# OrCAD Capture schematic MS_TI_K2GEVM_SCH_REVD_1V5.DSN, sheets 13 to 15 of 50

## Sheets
13 12. SoC POWER1: size C; title: SOC POWER - CVDD,CVDD1 & PLL
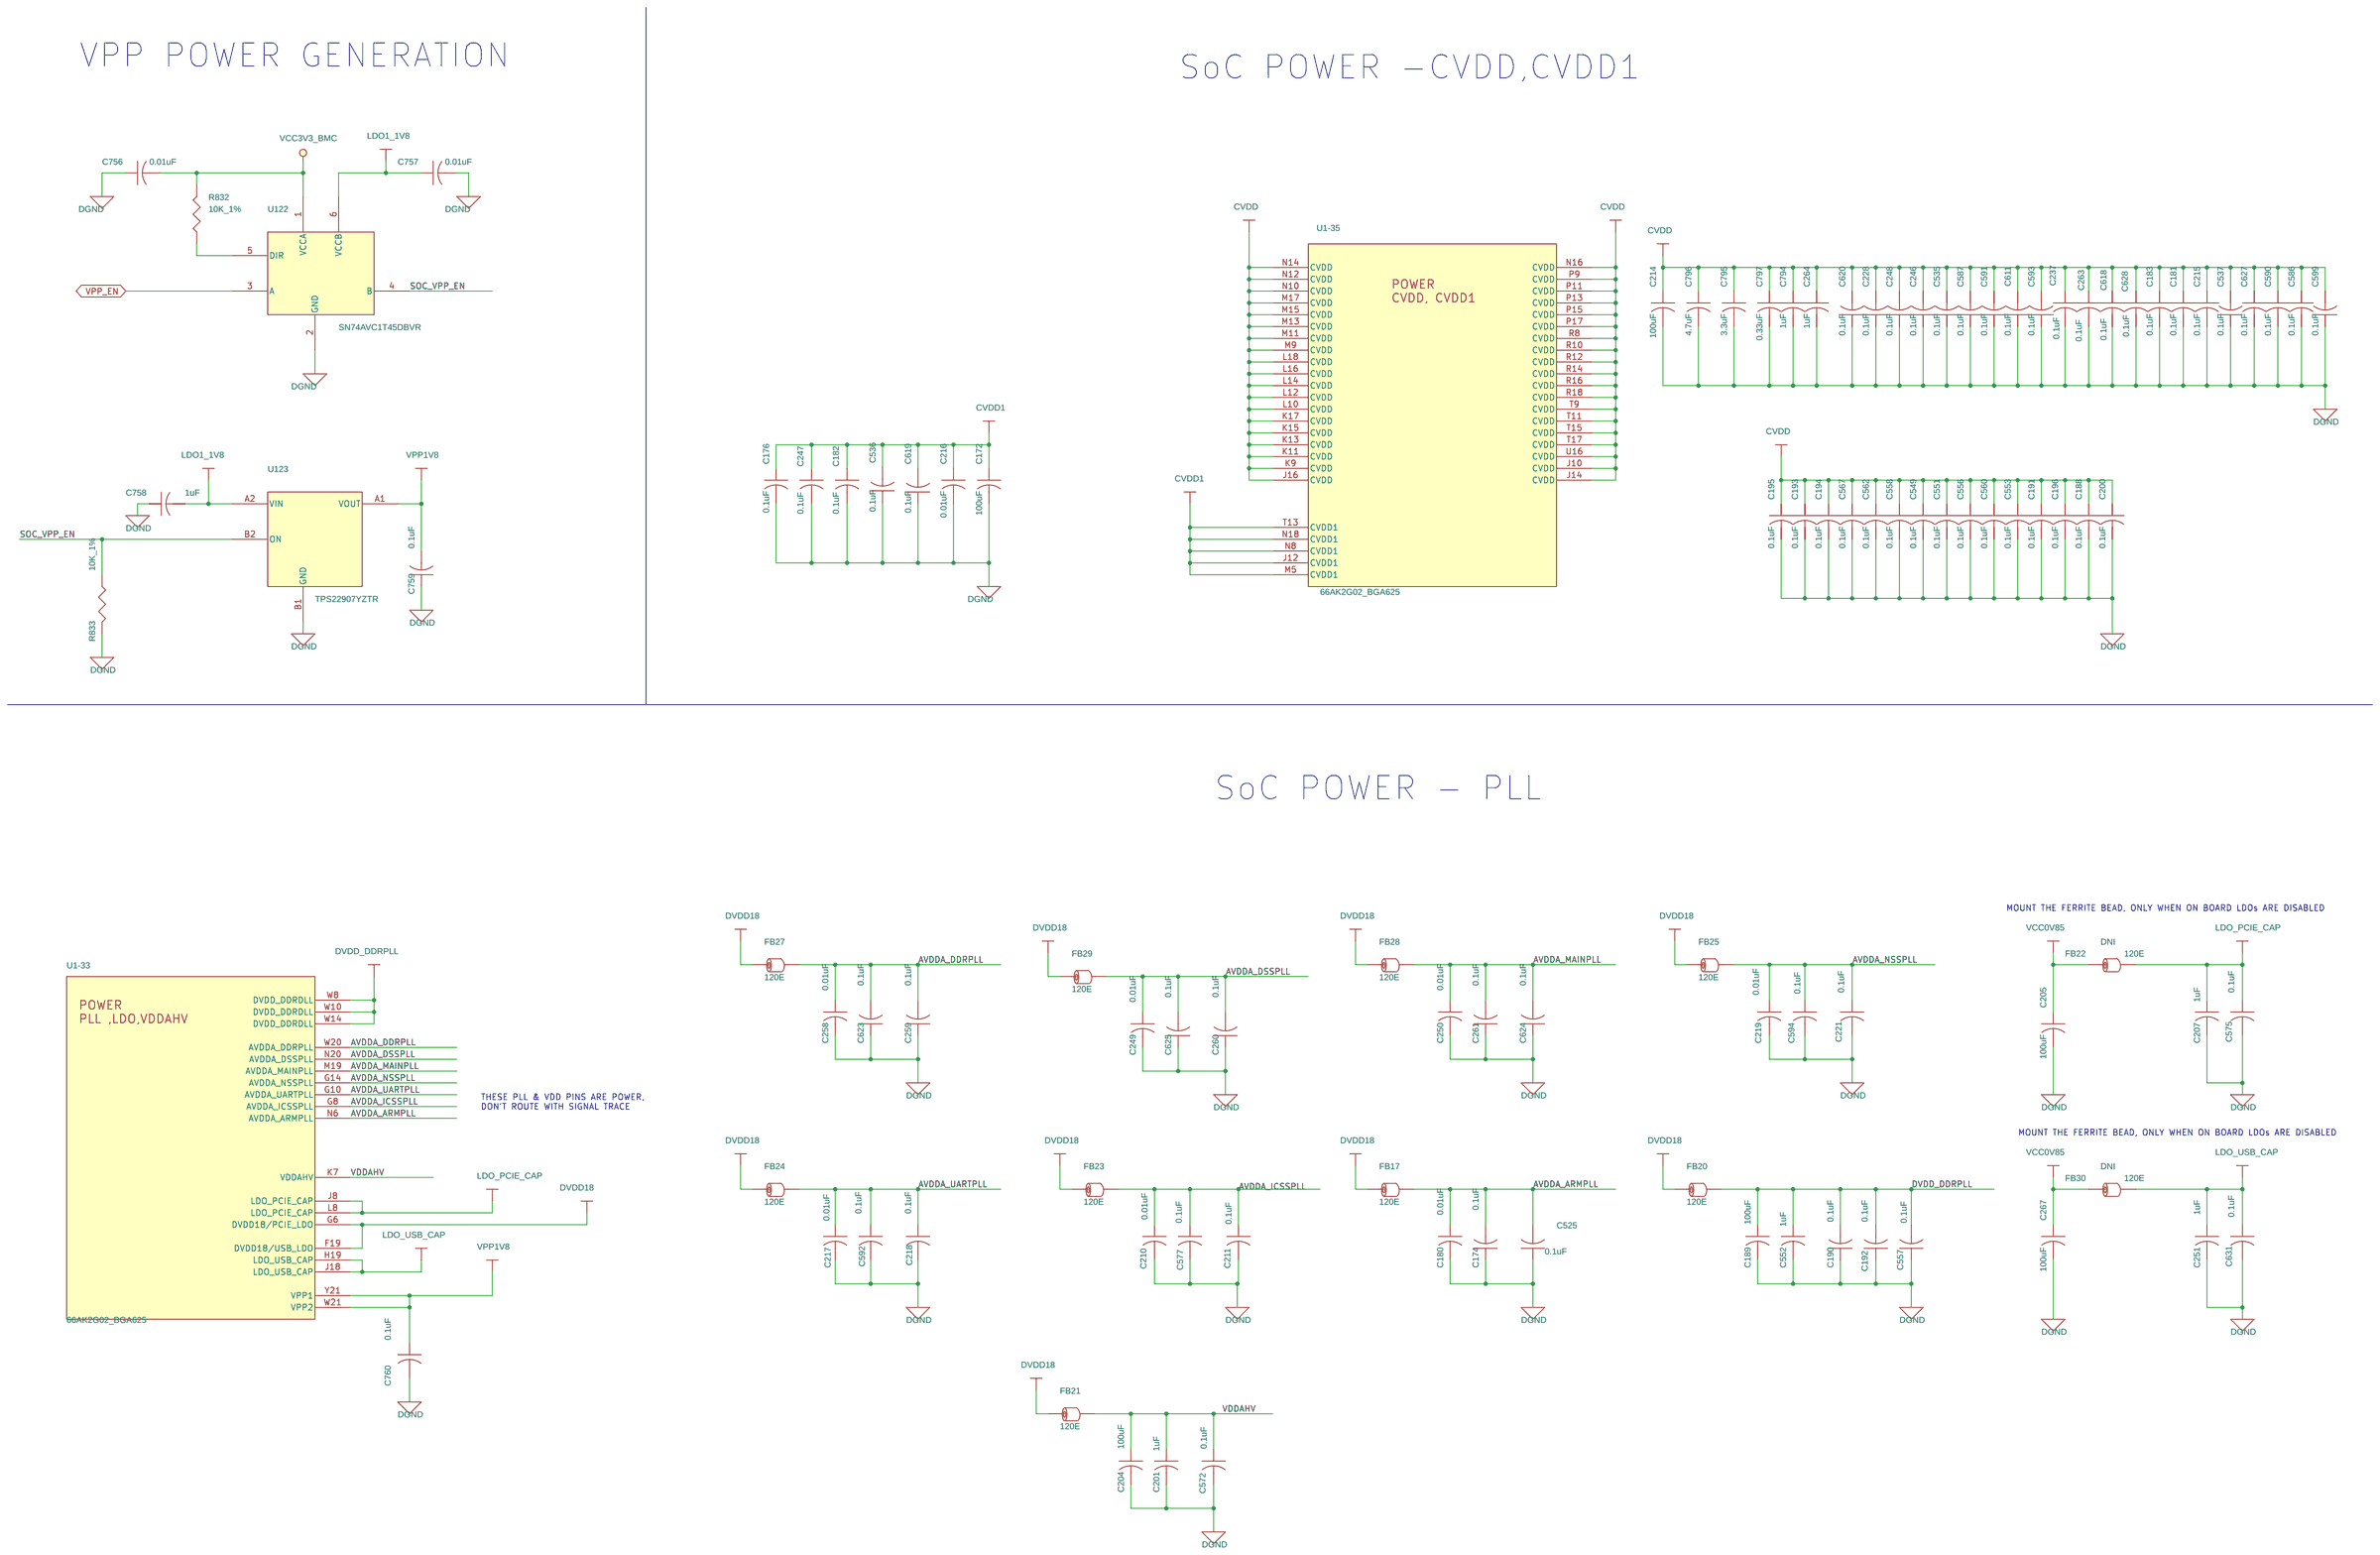
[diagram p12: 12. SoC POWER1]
14 13. SoC POWER2: size C; title: SOC POWER - DVDD33, DVDD18, DVDD_DDR & VSS
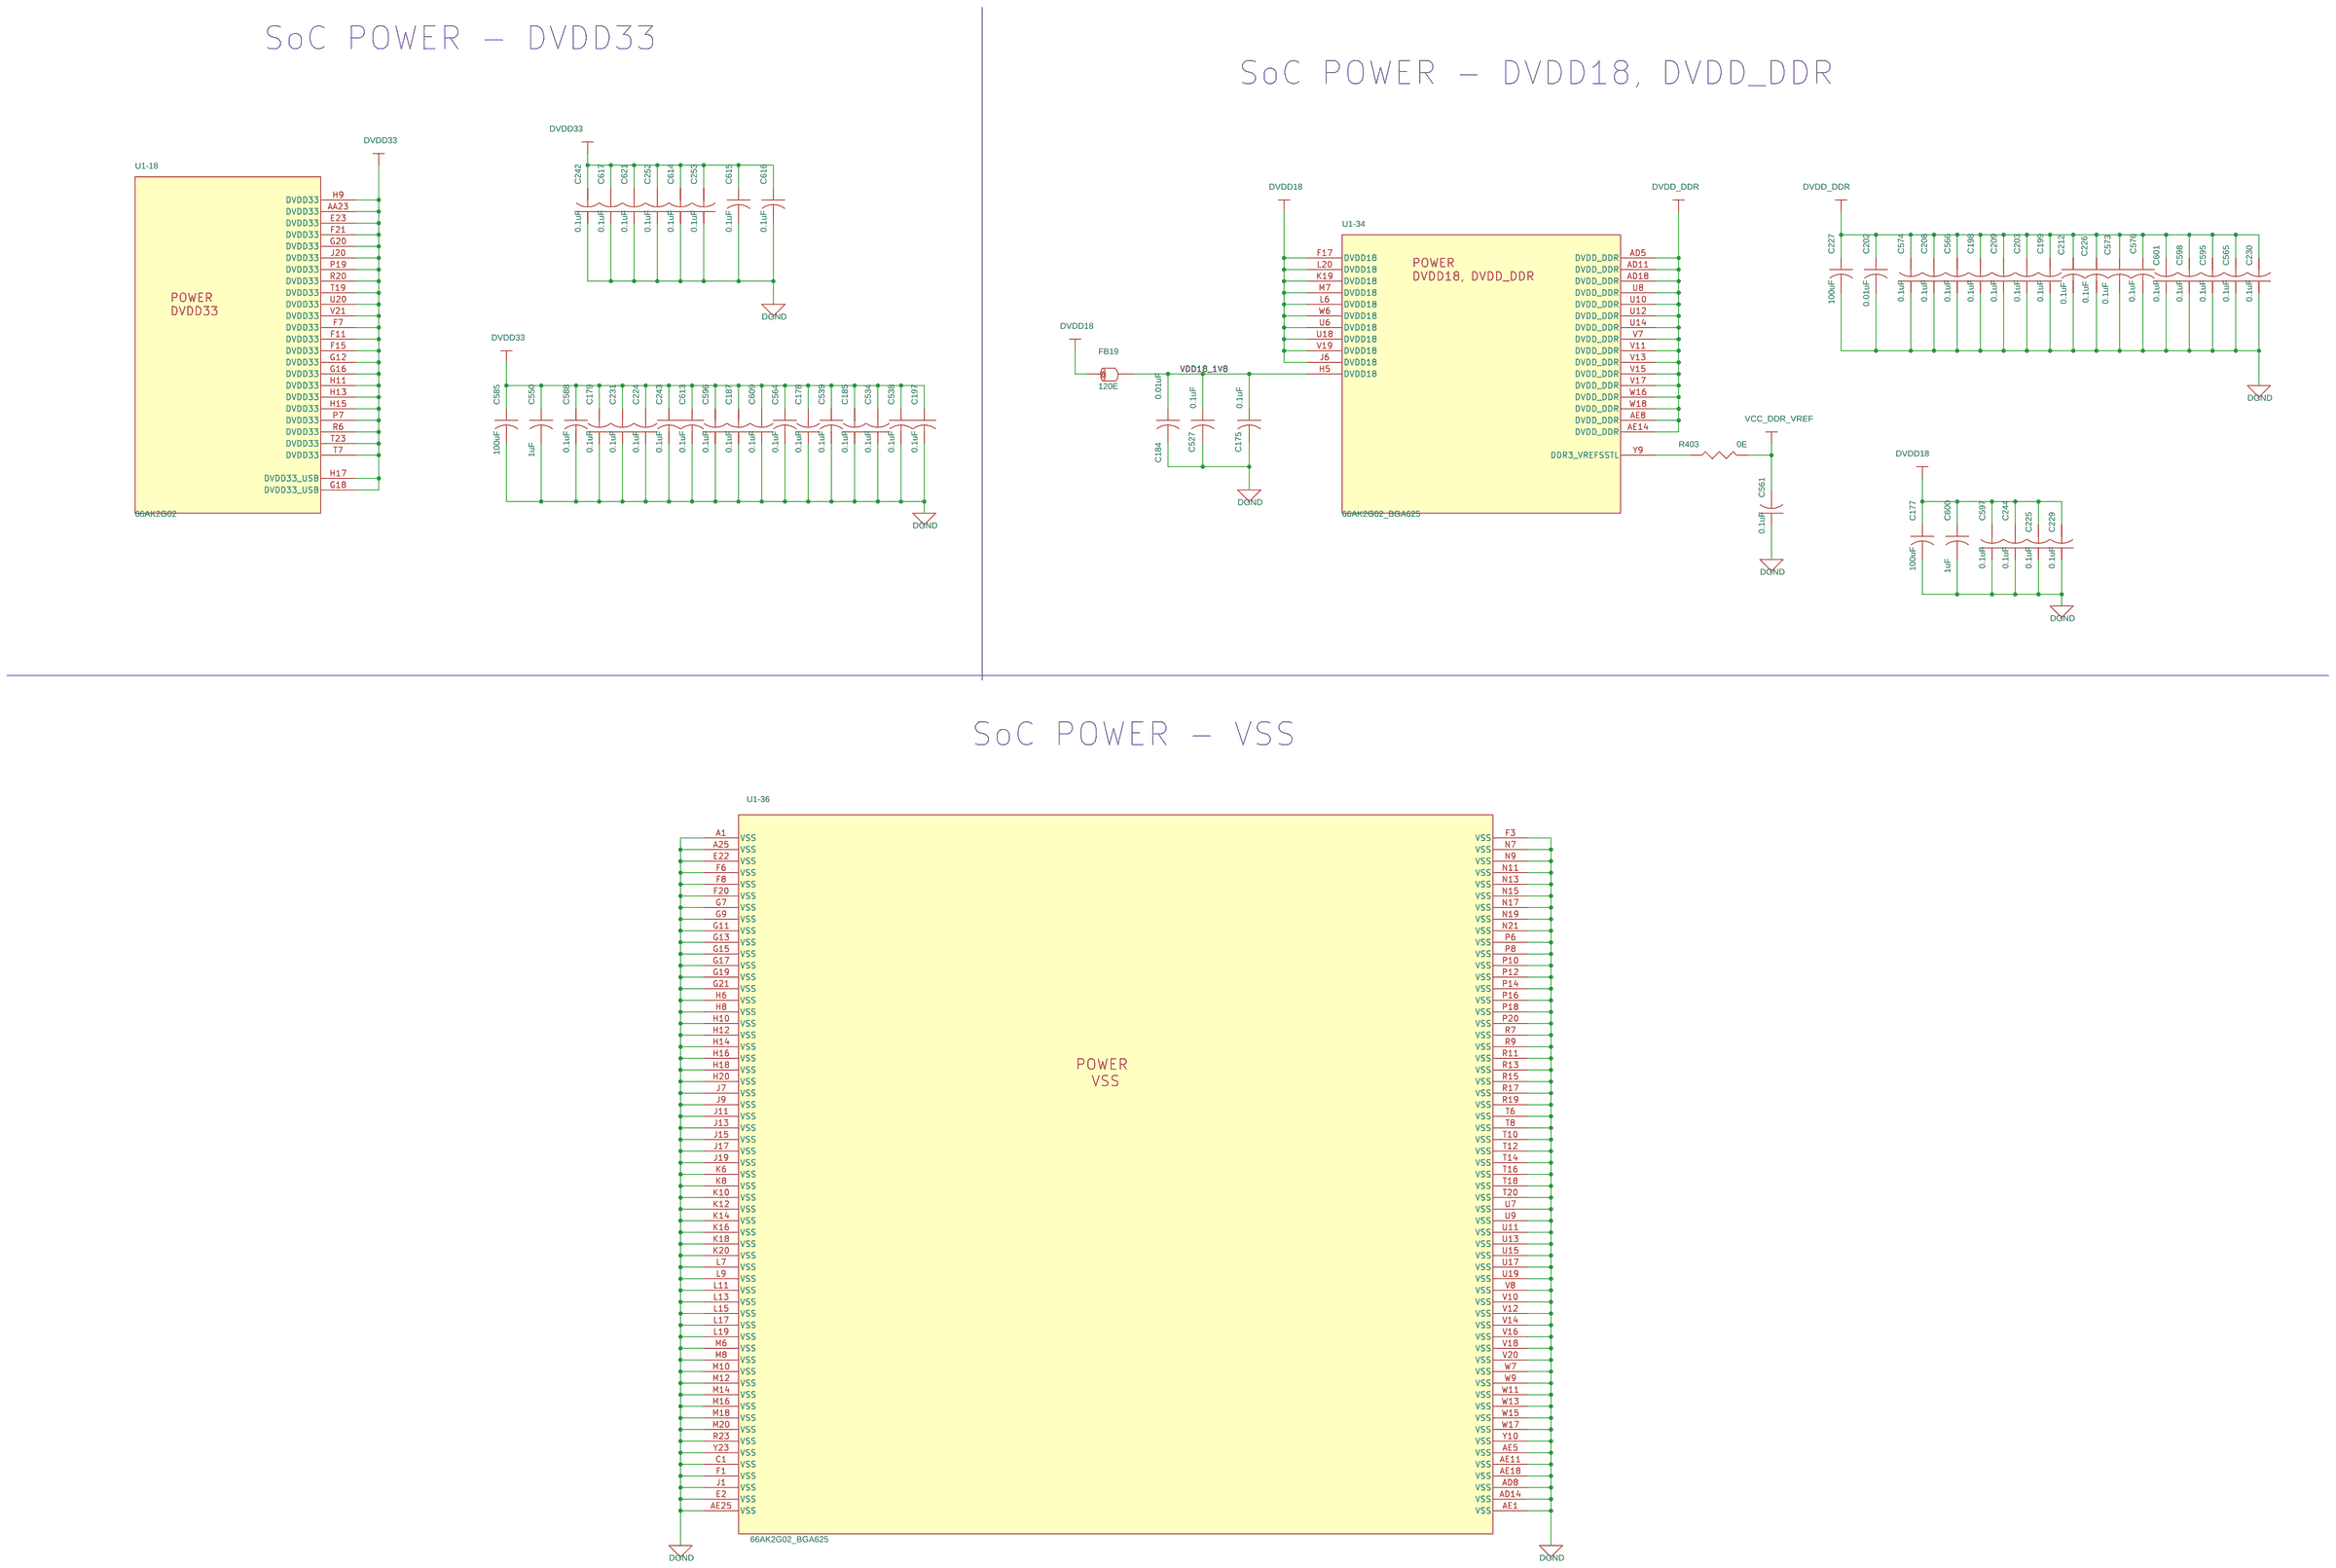
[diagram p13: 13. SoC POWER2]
15 14. DDR3 MEMORY: size C; title: DDR3L  DEVICES

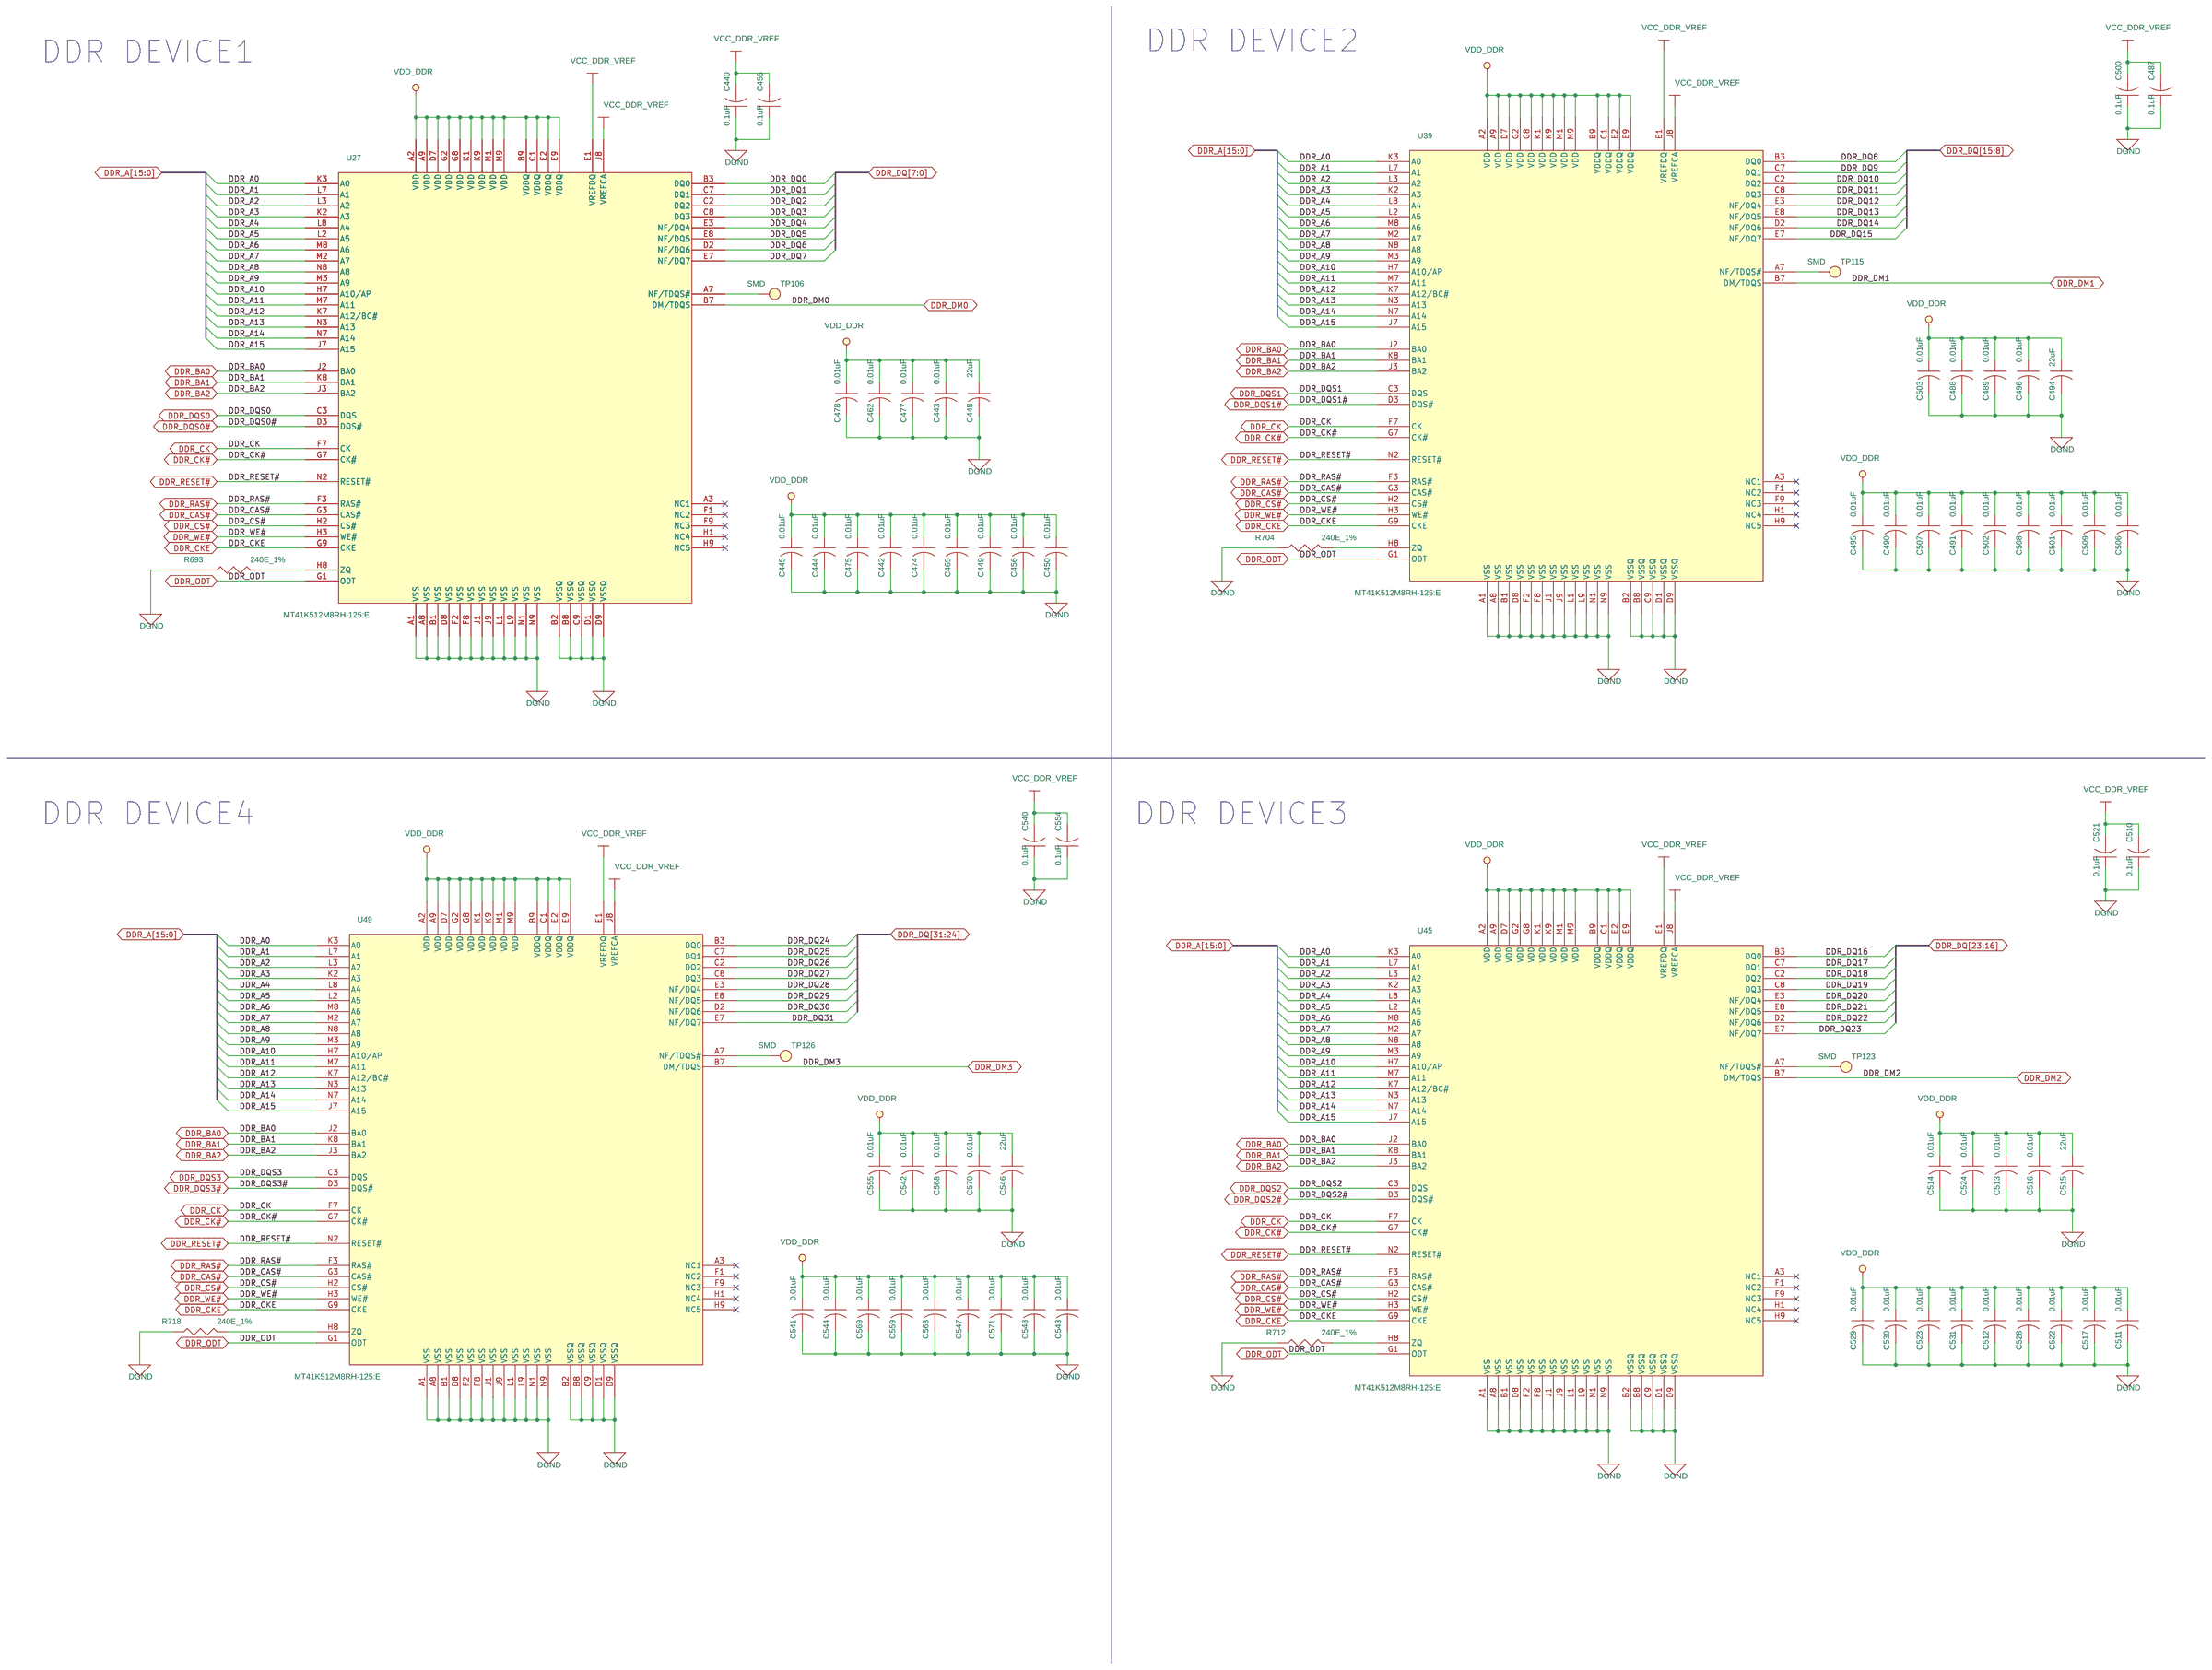
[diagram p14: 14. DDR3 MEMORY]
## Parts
sheet 12. SoC POWER1
C172  100uF  [CAP1210]
C174  0.1uF  [CAP0201]
C176  0.1uF  [CAP0201]
C180  0.01uF  [CAP0201]
C181  0.1uF  [CAP0201]
C182  0.1uF  [CAP0201]
C183  0.1uF  [CAP0201]
C188  0.1uF  [CAP0201]
C189  100uF  [CAP1210]
C190  0.1uF  [CAP0201]
C191  0.1uF  [CAP0201]
C192  0.1uF  [CAP0201]
C193  0.1uF  [CAP0201]
C194  0.1uF  [CAP0201]
C195  0.1uF  [CAP0201]
C196  0.1uF  [CAP0201]
C200  0.1uF  [CAP0201]
C201  1uF  [CAP0402]
C204  100uF  [CAP1210]
C205  100uF  [CAP1210]
C207  1uF  [CAP0204]
C210  0.01uF  [CAP0201]
C211  0.1uF  [CAP0201]
C214  100uF  [CAP1210]
C215  0.1uF  [CAP0201]
C216  0.01uF  [CAP0201]
C217  0.01uF  [CAP0201]
C218  0.1uF  [CAP0201]
C219  0.01uF  [CAP0201]
C221  0.1uF  [CAP0201]
C228  0.1uF  [CAP0201]
C237  0.1uF  [CAP0201]
C246  0.1uF  [CAP0201]
C247  0.1uF  [CAP0201]
C248  0.1uF  [CAP0201]
C249  0.01uF  [CAP0201]
C250  0.01uF  [CAP0201]
C251  1uF  [CAP0204]
C258  0.01uF  [CAP0201]
C259  0.1uF  [CAP0201]
C260  0.1uF  [CAP0201]
C261  0.1uF  [CAP0201]
C263  0.1uF  [CAP0201]
C264  1uF  [CAP0402]
C267  100uF  [CAP1210]
C525  0.1uF  [CAP0201]
C535  0.1uF  [CAP0201]
C536  0.1uF  [CAP0201]
C537  0.1uF  [CAP0402]
C549  0.1uF  [CAP0201]
C551  0.1uF  [CAP0201]
C552  1uF  [CAP0402]
C553  0.1uF  [CAP0201]
C556  0.1uF  [CAP0201]
C557  0.1uF  [CAP0201]
C558  0.1uF  [CAP0201]
C560  0.1uF  [CAP0201]
C562  0.1uF  [CAP0201]
C567  0.1uF  [CAP0201]
C572  0.1uF  [CAP0201]
C575  0.1uF  [CAP0201]
C577  0.1uF  [CAP0201]
C586  0.1uF  [CAP0201]
C587  0.1uF  [CAP0201]
C590  0.1uF  [CAP0201]
C591  0.1uF  [CAP0201]
C592  0.1uF  [CAP0201]
C593  0.1uF  [CAP0201]
C594  0.1uF  [CAP0201]
C599  0.1uF  [CAP0402]
C611  0.1uF  [CAP0201]
C618  0.1uF  [CAP0201]
C619  0.1uF  [CAP0201]
C620  0.1uF  [CAP0201]
C623  0.1uF  [CAP0201]
C624  0.1uF  [CAP0201]
C625  0.1uF  [CAP0201]
C627  0.1uF  [CAP0201]
C628  0.1uF  [CAP0201]
C631  0.1uF  [CAP0201]
C756  0.01uF  [CAP0402]
C757  0.01uF  [CAP0402]
C758  1uF  [CAP0402]
C759  0.1uF  [CAP0402]
C760  0.1uF  [CAP0201]
C794  1uF  [CAP0402]
C795  3.3uF  [CAP0402]
C796  4.7uF  [CAP0603]
C797  0.33uF  [CAP0201]
FB17  120E  [IND0402]
FB20  120E  [IND0402]
FB21  120E  [IND0402]
FB22  120E  [IND0402]
FB23  120E  [IND0402]
FB24  120E  [IND0402]
FB25  120E  [IND0402]
FB27  120E  [IND0402]
FB28  120E  [IND0402]
FB29  120E  [IND0402]
FB30  120E  [IND0402]
R832  10K_1%  [RES0402]
R833  10K_1%  [RES0402]
U122  SN74AVC1T45DBVR  [SOT23-6]
U123  TPS22907YZTR  [DSBGA4_19-68_40X40]
sheet 13. SoC POWER2
C175  0.1uF  [CAP0201]
C177  100uF  [CAP1210]
C178  0.1uF  [CAP0402]
C179  0.1uF  [CAP0402]
C184  0.01uF  [CAP0201]
C185  0.1uF  [CAP0402]
C187  0.1uF  [CAP0402]
C197  0.1uF  [CAP0201]
C198  0.1uF  [CAP0201]
C199  0.1uF  [CAP0201]
C202  0.01uF  [CAP0201]
C203  0.1uF  [CAP0201]
C208  0.1uF  [CAP0201]
C209  0.1uF  [CAP0201]
C212  0.1uF  [CAP0201]
C224  0.1uF  [CAP0402]
C225  0.1uF  [CAP0402]
C226  0.1uF  [CAP0201]
C227  100uF  [CAP1210]
C229  0.1uF  [CAP0402]
C230  0.1uF  [CAP0402]
C231  0.1uF  [CAP0402]
C242  0.1uF  [CAP0201]
C243  0.1uF  [CAP0201]
C244  0.1uF  [CAP0201]
C252  0.1uF  [CAP0201]
C253  0.1uF  [CAP0201]
C527  0.1uF  [CAP0201]
C534  0.1uF  [CAP0402]
C538  0.1uF  [CAP0201]
C539  0.1uF  [CAP0201]
C550  1uF  [CAP0402]
C561  0.1uF  [CAP0402]
C564  0.1uF  [CAP0201]
C565  0.1uF  [CAP0402]
C566  0.1uF  [CAP0201]
C573  0.1uF  [CAP0201]
C574  0.1uF  [CAP0201]
C576  0.1uF  [CAP0201]
C585  100uF  [CAP1210]
C588  0.1uF  [CAP0201]
C595  0.1uF  [CAP0402]
C596  0.1uF  [CAP0402]
C597  0.1uF  [CAP0201]
C598  0.1uF  [CAP0402]
C600  1uF  [CAP0402]
C601  0.1uF  [CAP0402]
C609  0.1uF  [CAP0402]
C613  0.1uF  [CAP0201]
C614  0.1uF  [CAP0201]
C615  0.1uF  [CAP0201]
C616  0.1uF  [CAP0201]
C617  0.1uF  [CAP0201]
C621  0.1uF  [CAP0201]
FB19  120E  [IND0402]
R403  0E  [RES0402]
sheet 14. DDR3 MEMORY
C440  0.1uF  [CAP0402]
C442  0.01uF  [CAP0402]
C443  0.01uF  [CAP0402]
C444  0.01uF  [CAP0402]
C445  0.01uF  [CAP0402]
C448  22uF  [CAP0805]
C449  0.01uF  [CAP0402]
C450  0.01uF  [CAP0402]
C455  0.1uF  [CAP0402]
C456  0.01uF  [CAP0402]
C462  0.01uF  [CAP0402]
C465  0.01uF  [CAP0402]
C474  0.01uF  [CAP0402]
C475  0.01uF  [CAP0402]
C477  0.01uF  [CAP0402]
C478  0.01uF  [CAP0402]
C487  0.1uF  [CAP0402]
C488  0.01uF  [CAP0402]
C489  0.01uF  [CAP0402]
C490  0.01uF  [CAP0402]
C491  0.01uF  [CAP0402]
C494  22uF  [CAP0805]
C495  0.01uF  [CAP0402]
C496  0.01uF  [CAP0402]
C500  0.1uF  [CAP0402]
C501  0.01uF  [CAP0402]
C502  0.01uF  [CAP0402]
C503  0.01uF  [CAP0402]
C506  0.01uF  [CAP0402]
C507  0.01uF  [CAP0402]
C508  0.01uF  [CAP0402]
C509  0.01uF  [CAP0402]
C510  0.1uF  [CAP0402]
C511  0.01uF  [CAP0402]
C512  0.01uF  [CAP0402]
C513  0.01uF  [CAP0402]
C514  0.01uF  [CAP0402]
C515  22uF  [CAP0805]
C516  0.01uF  [CAP0402]
C517  0.01uF  [CAP0402]
C521  0.1uF  [CAP0402]
C522  0.01uF  [CAP0402]
C523  0.01uF  [CAP0402]
C524  0.01uF  [CAP0402]
C528  0.01uF  [CAP0402]
C529  0.01uF  [CAP0402]
C530  0.01uF  [CAP0402]
C531  0.01uF  [CAP0402]
C540  0.1uF  [CAP0402]
C541  0.01uF  [CAP0402]
C542  0.01uF  [CAP0402]
C543  0.01uF  [CAP0402]
C544  0.01uF  [CAP0402]
C546  22uF  [CAP0805]
C547  0.01uF  [CAP0402]
C548  0.01uF  [CAP0402]
C554  0.1uF  [CAP0402]
C555  0.01uF  [CAP0402]
C559  0.01uF  [CAP0402]
C563  0.01uF  [CAP0402]
C568  0.01uF  [CAP0402]
C569  0.01uF  [CAP0402]
C570  0.01uF  [CAP0402]
C571  0.01uF  [CAP0402]
R693  240E_1%  [RES0402]
R704  240E_1%  [RES0402]
R712  240E_1%  [RES0402]
R718  240E_1%  [RES0402]
TP106  SMD  [TP40_SMD]
TP115  SMD  [TP40_SMD]
TP123  SMD  [TP40_SMD]
TP126  SMD  [TP40_SMD]
U27  MT41K512M8RH-125:E  [FBGA78_31-49_360X420]
U39  MT41K512M8RH-125:E  [FBGA78_31-49_360X420]
U45  MT41K512M8RH-125:E  [FBGA78_31-49_360X420]
U49  MT41K512M8RH-125:E  [FBGA78_31-49_360X420]
sheet 18. NAND FLASH & MICRO SD CARD
U1  66AK2G02_BGA625  [BGASKT625_31-49_1270x1270]  (sections -1,-10,-11,-12,-13,-14,-15,-16,-17,-18,-19,-2,-20,-21,-22,-23,-24,-25,-26,-27,-28,-29,-3,-30,-31,-32,-33,-34,-35,-36,-37,-38,-4,-5,-6,-7,-8,-9)

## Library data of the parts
C172 C177 C189 C204 C205 C214 C227 C267 C585 = CAP: CAP CERAMIC 100uF10V 20% X5R 1210; Chkd/date: MAZHAR/161208; Crtd /date: MAZHAR/140505; Custom_Duty: 15%; Customs_HS_Code: 85322990; Distributor_name: DIGIKEY; Distributor_part_number: 587-1965-1-ND; Height: 2.10MM; Mfr_name: TAIYO YUDEN; Mfr_part_number: LMK325BJ107MM-T; Mistral Part No: 120009030172; Package: 1210; Part_type: CAPACITORS\CERAMIC; Project: SMART VIEW_NVR; Tolerance: 20%; Voltage: 10V; Datasheet: Y:\MIS_DATABASE\DATASHEETS\CAPACITORS\JMKSERIES.PDF
C174-C176 C181-C183 C188 C190-C200 C203 C208 C209 C211 C212 C215 C218 C221 C226 C228 C237 C242-C244 C246-C248 C252 C253 C259-C261 C263 C525 C527 C535 C536 C538 C539 C549 C551 C553 C556-C558 C560 C562 C564 C566 C567 C572-C577 C586-C588 C590-C594 C597 C611 C613-C621 C623-C625 C627 C628 C631 C760 = CAP: CAP CERAMIC 0.1uF 10V 10% X5R 0201; Chkd/date: MAZHAR/010709; Crtd /date: USMAN/220509; Custom_Duty: 15%; Customs_HS_Code: 85322990; Distributor_name: DIGIKEY; Distributor_part_number: 587-2241-1-ND; Height: 0.33MM; Mfr_name: TAIYO YUDEN; Mfr_part_number: LMK063BJ104KP-F; Mistral Part No: 120009050017; Package: 0201; Part_type: CAPACITORS\CERAMIC; Project: GPD; Tolerance: 10%; Voltage: 10V; Datasheet: Y:\MIS_DATABASE\DATASHEETS\CAPACITORS\JMKSERIES1.PDF
C180 C184 C202 C210 C216 C217 C219 C249 C250 C258 = CAP: CAP CERAMIC 0.01uF 10V 10% X5R 0201; Chkd/date: MAZHAR/010211; Crtd /date: BAVISH/131010; Custom_Duty: 15%; Customs_HS_Code: 85322990; Distributor_name: DIGIKEY; Distributor_part_number: 445-1793-1-ND; Height: 0.33MM; Mfr_name: TDK CORPORATION; Mfr_part_number: C0603X5R1A103K; Mistral Part No: 120011010015-R; Package: 0201; Part_type: CAPACITORS\CERAMIC; Project: IDMATEK2; RoHS: RoHS; Temperature: -55°C+85°C; Tolerance: 10%; Voltage: 10V; Wattage: NA; Weight: NA; Datasheet: Y:\MIS_DATABASE\DATASHEETS\CAPACITORS\TDK_CAP.PDF
C201 C264 C550 C552 C600 C758 C794 = CAP: CAP CERAMIC 1uF 10V 10% X5R 0402; Chkd/date: BALACHANDAR/160514; Crtd /date: SARANYA/060514; Custom_Duty: 15%; Customs_HS_Code: 85322990; Distributor_name: DIGIKEY; Distributor_part_number: 478-4596-1-ND; Height: 0.56MM; Mfr_name: AVX CORPORATION; Mfr_part_number: 0402ZD105KAT2A; Mistral Part No: 120014050010-R; Package: 0402; Part_type: CAPACITORS\CERAMIC; Project: AEGIS GP BETA2; RoHS: RoHS; Temperature: -55°C+85°C; Tolerance: 10%; Voltage: 10V; Wattage: NA; Weight: NA; Datasheet: Y:\MIS_DATABASE\DATASHEETS\CAPACITORS\AVX_MLC.PDF
C207 C251 = CAP: CAP CERAMIC 1uF 2.5V 20% X7S 0204; Chkd/date: NAVEED/180315; Crtd /date: NAVEED/130115; Custom_Duty: 15%; Customs_HS_Code: 85322990; Distributor_name: NA; Distributor_part_number: NA; Height: 0.35MM; Mfr_name: MURATA; Mfr_part_number: LLL153C70E105ME21; Mistral Part No: 120015010017; Package: 0204; Part_type: CAPACITORS\CERAMIC; Project: GALILEO_EVM; Temperature: -55°C+125°C; Tolerance: 20%; Voltage: 2.5V; Weight: NA; Datasheet: Y:\MIS_DATABASE\DATASHEETS\CAPACITORS\LLL153C7.PDF
C178 C179 C185 C187 C224 C225 C229-C231 C440 C455 C487 C500 C510 C521 C534 C537 C540 C554 C561 C565 C595 C596 C598 C599 C601 C609 C759 = CAP: CAP CERAMIC 0.1uF 25V -20% TO +80 Y5V 0402; Chkd/date: SHREESHAIL/301105; Crtd /date: MAZHAR/251005; Custom_Duty: 15%; Customs_HS_Code: 85322990; Distributor_name: DIGIKEY; Distributor_part_number: 490-3271-1-ND; Height: 0.55MM; Mfr_name: MURATA; Mfr_part_number: GRM155F51E104ZA01D; Mistral Part No: 120009030085; Package: 0402; Part_type: CAPACITORS\CERAMIC; Project: ADR; Tolerance: -20% TO +80%; Voltage: 25V; Datasheet: Y:\MIS_DATABASE\DATASHEETS\CAPACITORS\GRM188SERIES.PDF
C442-C445 C449 C450 C456 C462 C465 C474 C475 C477 C478 C488-C491 C495 C496 C501-C503 C506-C509 C511-C514 C516 C517 C522-C524 C528-C531 C541-C544 C547 C548 C555 C559 C563 C568-C571 C756 C757 = CAP: CAP CERAMIC 0.01uF 16V 10% X7R 0402; Alternate_mfr_name_A: AVX CORPORATION; Alternate_mfr_name_B: KEMET; Alternate_mfr_name_D: TDK CORPORATION; Alternate_mfr_part_number_A: 0402YC103KAT2A; Alternate_mfr_part_number_B: C0402C103K4RACTU; Alternate_mfr_part_number_D: C1005X7R1C103K; Chkd/date: SHREESHAIL/180506; Crtd /date: MAZHAR/110506; Custom_Duty: 15%; Customs_HS_Code: 85322990; Distributor_name: DIGIKEY; Distributor_name_A: DIGIKEY; Distributor_name_B: DIGIKEY; Distributor_name_D: DIGIKEY; Distributor_part_number: PCC103BQCT-ND; Distributor_part_number_A: 478-1114-1-ND; Distributor_part_number_B: 399-1038-1-ND; Distributor_part_number_D: 445-1262-1-ND; Height: 0.55MM; Mfr_name: PANASONIC-ECG; Mfr_part_number: ECJ-0EB1C103K; Mistral Part No: 120009030032-R; Package: 0402; Part_type: CAPACITORS\CERAMIC; Project: VOCERA; RoHS: RoHS; Tolerance: 10%; Voltage: 16V; Datasheet: Y:\MIS_DATABASE\DATASHEETS\CAPACITORS\PAN-ECJ.PDF
C795 = CAP: CAP CERAMIC 3.3uF 6.3V 20% X5R 0402; Chkd/date: NAVEED/270315; Crtd /date: VASANTHA/130215; Custom_Duty: 15%; Customs_HS_Code: 85322990; Distributor_name: DIGIKEY; Distributor_part_number: 445-7394-1-ND; Height: 0.60MM; Mfr_name: TDK CORPORATION; Mfr_part_number: C1005X5R0J335M050BC; Mistral Part No: 120015002002-R; Package: 0402; Part_type: CAPACITORS\CERAMIC; Project: GALILEO_EVM; RoHS: RoHS; Temperature: -55°C+85°C; Tolerance: 20%; Voltage: 6.3V; Wattage: NA; Weight: NA; Datasheet: Y:\MIS_DATABASE\DATASHEETS\CAPACITORS\TDK_CAP.PDF
C796 = CAP: CAP CERAMIC 4.7uF 6.3V 10% X5R 0603; Alternate_mfr_name_A: MURATA; Alternate_mfr_name_B: TAIYO YUDEN; Alternate_mfr_name_C: PANASONIC-ECG; Alternate_mfr_part_number_A: GRM188R60J475KE19D; Alternate_mfr_part_number_B: JMK107BJ475KA-T; Alternate_mfr_part_number_C: ECJ-1VB0J475K; Chkd/date: SHREESHAIL/301105; Crtd /date: MAZHAR/241005; Custom_Duty: 15%; Customs_HS_Code: 85322990; Distributor_name: DIGIKEY; Distributor_name_A: DIGIKEY; Distributor_name_B: DIGIKEY; Distributor_name_C: DIGIKEY; Distributor_part_number: 399-3482-2-ND; Distributor_part_number_A: 490-3297-1-ND; Distributor_part_number_B: 587-1785-1-ND; Distributor_part_number_C: PCC2396CT-ND; Height: 0.90MM; Mfr_name: KEMET; Mfr_part_number: C0603C475K9PACTU; Mistral Part No: 120009030426-R; Package: 0603; Part_type: CAPACITORS\CERAMIC; Project: G4SLIM; RoHS: RoHS; Tolerance: 10%; Voltage: 6.3V; Datasheet: Y:\MIS_DATABASE\DATASHEETS\CAPACITORS\KEMET-C08.PDF
C797 = CAP: CAP CERAMIC 0.33uF 6.3V 20% JB 0201; Chkd/date: NAVEED/230215; Crtd /date: VASANTHA/230215; Custom_Duty: 15%; Customs_HS_Code: 85322990; Distributor_name: DIGIKEY; Distributor_part_number: 445-10738-1-ND; Height: 0.33MM; Mfr_name: TDK CORPORATION; Mfr_part_number: C0603JB0J334M030BC; Mistral Part No: 120015002003-R; Package: 0201; Part_type: CAPACITORS\CERAMIC; Project: GALILEO_EVM; RoHS: RoHS; Temperature: -25°C+85°C; Tolerance: 20%; Voltage: 6.3V; Wattage: NA; Weight: NA; Datasheet: Y:\MIS_DATABASE\DATASHEETS\CAPACITORS\CAP_SERIES.PDF
FB17 FB19-FB21 FB23-FB25 FB27-FB29 = INDUCTOR_FERRITE: IND BEAD CHIP 120E 1.2A 0402; Chkd/date: ASHOK/240212; Crtd /date: BAVISH/060711; Custom_Duty: 24%; Customs_HS_Code: 85437099; Distributor_name: DIGIKEY; Distributor_part_number: 445-2981-1-ND; Height: 0.55MM; Mfr_name: TDK CORPORATION; Mfr_part_number: MPZ1005S121C; Mistral Part No: 130011070007-R; Package: 0402; Part_type: INDUCTOR; Project: SVDU; RoHS: RoHS; Temperature: -40°C+85°C; Tolerance: NA; Voltage: NA; Wattage: NA; Weight: 1mg; Datasheet: Y:\MIS_DATABASE\DATASHEETS\DISCRETES\INDUCTORS\MPZ1005.PDF
FB22 FB30 = INDUCTOR_FERRITE: IND BEAD CHIP 120E 1.2A 0402; Chkd/date: ASHOK/240212; Crtd /date: BAVISH/060711; Custom_Duty: 24%; Customs_HS_Code: 85437099; Distributor_name: DIGIKEY; Distributor_part_number: 445-2981-1-ND; Height: 0.55MM; Loading: DNI; Mfr_name: TDK CORPORATION; Mfr_part_number: MPZ1005S121C; Mistral Part No: 130011070007-R; Package: 0402; Part_type: INDUCTOR; Project: SVDU; RoHS: RoHS; Temperature: -40°C+85°C; Tolerance: NA; Voltage: NA; Wattage: NA; Weight: 1mg; Datasheet: Y:\MIS_DATABASE\DATASHEETS\DISCRETES\INDUCTORS\MPZ1005.PDF
R832 R833 = RESISTOR: RES 10K 1/16W 1% 0402; Alternate_mfr_name_A: AVX CORPORATION; Alternate_mfr_name_B: PANASONIC-ECG-ECG; Alternate_mfr_name_C: YAGEO AMERICA; Alternate_mfr_name_D: VISHAY; Alternate_mfr_part_number_A: CR05-103F-H; Alternate_mfr_part_number_B: ERJ-2RKF1002X; Alternate_mfr_part_number_C: 9C04021A1002FLHF3; Alternate_mfr_part_number_D: CRCW040210K0FKED; Chkd/date: SHREESHAIL/310506; Crtd /date: GEETHA/290506; Custom_Duty: 15%; Customs_HS_Code: 85332119; Distributor_name: DIGIKEY; Distributor_name_A: NA; Distributor_name_B: DIGIKEY; Distributor_name_C: DIGIKEY; Distributor_name_D: DIGIKEY; Distributor_part_number: 311-10.0KLRTR-ND; Distributor_part_number_A: NA; Distributor_part_number_B: P10.0KLCT-ND; Distributor_part_number_C: 311-10.0KLCT-ND; Distributor_part_number_D: 541-10.0KLCT-ND; Height: 0.40MM; Mfr_name: YAGEO AMERICA; Mfr_part_number: RC0402FR-0710KL; Mistral Part No: 110009030220-P; Package: 0402; Part_type: RESISTORS\FIXED; Project: VOCERA; RoHS: Pb-Free; Tolerance: 1%; Wattage: 1/16W; Datasheet: Y:\MIS_DATABASE\DATASHEETS\RESISTORS\YAGEO-RC0402.PDF
U122 = SN74AVC1T45DBVR_SOT23-6: IC SINGLE-BIT DUAL-SUPPLY BUS TRANSCEIVER SOT23-6; Chkd/date: MAZHAR/050208; Crtd /date: USMAN/050208; Custom_Duty: 15%; Customs_HS_Code: 85423100; Distributor_name: DIGIKEY; Distributor_part_number: 296-19094-1-ND; Height: 1.45MM; Mfr_name: TEXAS INSTRUMENTS; Mistral Part No: 141009030019-R; Part_type: ICS\DIGITAL\BUSTRANSCEIVER; Project: HS100RD; RoHS: RoHS; Datasheet: Y:\MIS_DATABASE\DATASHEETS\ICS\DIGITAL\BUSTRANSCEIVER\SN74AVC1T45.PDF
U123 = TPS22907YZTR_DSBGA4: IC LOW INPUT VOLTAGE LOAD SWITCH WITH ULTRA-LOW Ron  DSBGA4; Chkd/date: RAGESH/080311; Crtd /date: MUDDU/290110; Custom_Duty: 15%; Customs_HS_Code: 85423100; Distributor_name: NA; Distributor_part_number: NA; Height: 0.62MM; Mfr_name: TEXAS INSTRUMENTS; Mistral Part No: 142010020003-R; Package: DSBGA4; Part_type: ICS\POWER; Project: KOPIN_MODULS; RoHS: RoHS; Temperature: -40°C to 85°C; Datasheet: Y:\MIS_DATABASE\DATASHEETS\ICS\POWER\TPS22907YZTR.pdf
R403 = RESISTOR: RES 0E 1/10W 5% 0402; Chkd/date: NAVEED/241114; Crtd /date: NAVEED/201014; Custom_Duty: 15%; Customs_HS_Code: 85332119; Distributor_name: DIGIKEY; Distributor_part_number: P0.0JCT-ND; Height: 0.40MM; Mfr_name: PANASONIC-ECG; Mfr_part_number: ERJ-2GE0R00X; Mistral Part No: 110014100008-R; Package: 0402; Part_type: RESISTORS\FIXED; Project: AEGIS POM; RoHS: RoHS; Tolerance: 5%; Wattage: 1/10W; Datasheet: Y:\MIS_DATABASE\DATASHEETS\RESISTORS\ERJ12.PDF
C448 C494 C515 C546 = CAP: CAP CERAMIC 22uF 16V 10% X5R 0805; Chkd/date: MAZHAR/291110; Crtd /date: BAVISH/271110; Custom_Duty: 15%; Customs_HS_Code: 85322990; Distributor_name: NA; Distributor_part_number: NA; Height: 1.45MM; Mfr_name: TDK CORPORATION; Mfr_part_number: C2012X5R1C226K; Mistral Part No: 120010110025-R; Package: 0805; Part_type: CAPACITORS\CERAMIC; Project: EM-FLS; RoHS: RoHS; Temperature: -55°C+85°C; Tolerance: 10%; Voltage: 16V; Wattage: NA; Weight: NA; Datasheet: Y:\MIS_DATABASE\DATASHEETS\CAPACITORS\C2012.PDF
R693 R704 R712 R718 = RESISTOR: RES 240E 1/10W 1% 0402; Chkd/date: MAZHAR/150611; Crtd /date: BAVISH/020611; Custom_Duty: 15%; Customs_HS_Code: 85332119; Distributor_name: DIGIKEY; Distributor_part_number: P240LCT-ND; Height: 0.40MM; Mfr_name: PANASONIC-ECG; Mfr_part_number: ERJ-2RKF2400X; Mistral Part No: 110011060017-R; Package: 0402; Part_type: RESISTORS\FIXED; Project: AM4515_EVM_LCD; RoHS: RoHS; Temperature: -55°C+125°C; Tolerance: 1%; Voltage: NA; Wattage: 1/10W; Weight: 0.8/1000g; Datasheet: Y:\MIS_DATABASE\DATASHEETS\RESISTORS\ERJ-2R.PDF
TP106 TP115 TP123 TP126 = TESTPOINT: TESTPOINT 40 SMD; Chkd/date: MAZHAR/190505; Crtd /date: MAZHAR/190505; Distributor_name: NA; Distributor_part_number: NA; Height: NA; Mfr_name: LOCAL; Mistral Part No: 130009030933; Part_type: MISC\TESTPOINT; Project: RAINIER-3
U27 U39 U45 U49 = MT41J128M8JP-125_FBGA78: IC 512Mb DDR SDRAM FBGA78; Chkd/date: NAVEED/241114; Crtd /date: VASANTHA/071014; Custom_Duty: 15%; Customs_HS_Code: 85423100; Distributor_name: NA; Distributor_part_number: NA; Height: 1.20MM; Mfr_name: MICRON; Mistral Part No: 141114100002-P; Package: FBGA78; Part_type: ICS\DIGITAL\MEMORY; Project: GALILEO_EVM; RoHS: Pb-Free; Temperature: -0°C+85°C; Tolerance: NA; Voltage: NA; Wattage: NA; Weight: NA; Datasheet: Y:\MIS_DATABASE\DATASHEETS\ICS\MEMORY\MT41K.PDF
U1 = 66AK2G02_BGA625: IC ARM CORTEX AND DSP 32 BIT MICROPROCESSOR BGA625; Chkd/date: NAVEED/141114; Color: Default; Crtd /date: VASANTHA/081014; Custom_Duty: 15%; Customs_HS_Code: 85423100; Distributor_name: NA; Distributor_part_number: NA; Height: 1.70MM; Location X-Coordinate: 0; Location Y-Coordinate: 0; Mfr_name: TEXAS INSTRUMENTS; Mfr_part_number: 66AK2G02; Mistral Part No: 141014100003; Package: BGA625; Part_type: ICS\DIGITAL\MICROPROCESSOR; Power Pins Visible: False; Primitive: DEFAULT; Project: GALILEO_EVM; Tolerance: NA; Voltage: NA; Wattage: NA; Weight: NA; Datasheet: Y:\MIS_DATABASE\DATASHEETS\ICS\DIGITAL\MICROCONTROLLER\SG-BGA-6094.PDF    Y:\MIS_DATABASE\DATASHEETS\ICS\DIGITAL\MICROCONTROLLER\SG-BGA_FP.PDF

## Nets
AVDDA_ARMPLL: C174.2 C180.1 C525.2 FB17.2 U1.N6(AVDDA_ARMPLL)
AVDDA_DDRPLL: C258.1 C259.2 C623.2 FB27.2 U1.W20(AVDDA_DDRPLL)
AVDDA_DSSPLL: C249.1 C260.2 C625.2 FB29.2 U1.N20(AVDDA_DSSPLL)
AVDDA_ICSSPLL: C210.1 C211.1 C577.1 FB23.2 U1.G8(AVDDA_ICSSPLL)
AVDDA_MAINPLL: C250.1 C261.2 C624.2 FB28.2 U1.M19(AVDDA_MAINPLL)
AVDDA_NSSPLL: C219.1 C221.1 C594.1 FB25.2 U1.G14(AVDDA_NSSPLL)
AVDDA_UARTPLL: C217.1 C218.1 C592.1 FB24.2 U1.G10(AVDDA_UARTPLL)
DGND: C172.2 C174.1 C175.2 C176.2 C177.2 C178.1 C179.1 C180.2 C181.2 C182.2 C183.2 C184.2 C185.1 C187.1 C188.2 C189.2 C190.1 C191.2 C192.1 C193.2 C194.2 C195.2 C196.2 C197.2 C198.1 C199.1 C200.2 C201.2 C202.2 C203.1 C204.2 C205.2 C207.2 C208.1 C209.1 C210.2 C211.2 C212.2 C214.2 C215.2 C216.2 C217.2 C218.2 C219.2 C221.2 C224.1 C225.1 C226.2 C227.2 C228.1 C229.1 C230.1 C231.1 C237.2 C242.1 C243.2 C244.1 C246.1 C247.2 C248.1 C249.2 C250.2 C251.2 C252.1 C253.1 C258.2 C259.1 C260.1 C261.1 C263.2 C264.2 C267.2 C440.1 C442.2 C443.2 C444.2 C445.2 C448.2 C449.2 C450.2 C455.1 C456.2 C462.2 C465.2 C474.2 C475.2 C477.2 C478.2 C487.1 C488.2 C489.2 C490.2 C491.2 C494.2 C495.2 C496.2 C500.1 C501.2 C502.2 C503.2 C506.2 C507.2 C508.2 C509.2 C510.1 C511.2 C512.2 C513.2 C514.2 C515.2 C516.2 C517.2 C521.1 C522.2 C523.2 C524.2 C525.1 C527.2 C528.2 C529.2 C530.2 C531.2 C534.1 C535.1 C536.1 C537.1 C538.2 C539.2 C540.1 C541.2 C542.2 C543.2 C544.2 C546.2 C547.2 C548.2 C549.2 C550.2 C551.2 C552.2 C553.2 C554.1 C555.2 C556.2 C557.1 C558.2 C559.2 C560.2 C561.1 C562.2 C563.2 C564.2 C565.1 C566.1 C567.2 C568.2 C569.2 C570.2 C571.2 C572.2 C573.2 C574.1 C575.2 C576.2 C577.2 C585.2 C586.2 C587.1 C588.2 C590.2 C591.1 C592.2 C593.1 C594.2 C595.1 C596.1 C597.1 C598.1 C599.1 C600.2 C601.1 C609.1 C611.1 C613.2 C614.1 C615.2 C616.2 C617.1 C618.2 C619.1 C620.1 C621.1 C623.1 C624.1 C625.1 C627.2 C628.2 C631.2 C756.1 C757.2 C758.1 C759.1 C760.2 C794.2 C795.2 C796.2 C797.2 R693.1 R704.1 R712.1 R718.1 R833.2 U1.A1(VSS) U1.A25(VSS) U1.AD8(VSS) U1.AD14(VSS) U1.AE1(VSS) U1.AE5(VSS) U1.AE11(VSS) U1.AE18(VSS) U1.AE25(VSS) U1.C1(VSS) U1.E2(VSS) U1.E22(VSS) U1.F1(VSS) U1.F3(VSS) U1.F6(VSS) U1.F8(VSS) U1.F20(VSS) U1.G7(VSS) U1.G9(VSS) U1.G11(VSS) U1.G13(VSS) U1.G15(VSS) U1.G17(VSS) U1.G19(VSS) U1.G21(VSS) U1.H6(VSS) U1.H8(VSS) U1.H10(VSS) U1.H12(VSS) U1.H14(VSS) U1.H16(VSS) U1.H18(VSS) U1.H20(VSS) U1.J1(VSS) U1.J7(VSS) U1.J9(VSS) U1.J11(VSS) U1.J13(VSS) U1.J15(VSS) U1.J17(VSS) U1.J19(VSS) U1.K6(VSS) U1.K8(VSS) U1.K10(VSS) U1.K12(VSS) U1.K14(VSS) U1.K16(VSS) U1.K18(VSS) U1.K20(VSS) U1.L7(VSS) U1.L9(VSS) U1.L11(VSS) U1.L13(VSS) U1.L15(VSS) U1.L17(VSS) U1.L19(VSS) U1.M6(VSS) U1.M8(VSS) U1.M10(VSS) U1.M12(VSS) U1.M14(VSS) U1.M16(VSS) U1.M18(VSS) U1.M20(VSS) U1.N7(VSS) U1.N9(VSS) U1.N11(VSS) U1.N13(VSS) U1.N15(VSS) U1.N17(VSS) U1.N19(VSS) U1.N21(VSS) U1.P6(VSS) U1.P8(VSS) U1.P10(VSS) U1.P12(VSS) U1.P14(VSS) U1.P16(VSS) U1.P18(VSS) U1.P20(VSS) U1.R7(VSS) U1.R9(VSS) U1.R11(VSS) U1.R13(VSS) U1.R15(VSS) U1.R17(VSS) U1.R19(VSS) U1.R23(VSS) U1.T6(VSS) U1.T8(VSS) U1.T10(VSS) U1.T12(VSS) U1.T14(VSS) U1.T16(VSS) U1.T18(VSS) U1.T20(VSS) U1.U7(VSS) U1.U9(VSS) U1.U11(VSS) U1.U13(VSS) U1.U15(VSS) U1.U17(VSS) U1.U19(VSS) U1.V8(VSS) U1.V10(VSS) U1.V12(VSS) U1.V14(VSS) U1.V16(VSS) U1.V18(VSS) U1.V20(VSS) U1.W7(VSS) U1.W9(VSS) U1.W11(VSS) U1.W13(VSS) U1.W15(VSS) U1.W17(VSS) U1.Y10(VSS) U1.Y23(VSS) U27.A1(VSS) U27.A8(VSS) U27.B1(VSS) U27.B2(VSSQ) U27.B8(VSSQ) U27.C9(VSSQ) U27.D1(VSSQ) U27.D8(VSS) U27.D9(VSSQ) U27.F2(VSS) U27.F8(VSS) U27.J1(VSS) U27.J9(VSS) U27.L1(VSS) U27.L9(VSS) U27.N1(VSS) U27.N9(VSS) U39.A1(VSS) U39.A8(VSS) U39.B1(VSS) U39.B2(VSSQ) U39.B8(VSSQ) U39.C9(VSSQ) U39.D1(VSSQ) U39.D8(VSS) U39.D9(VSSQ) U39.F2(VSS) U39.F8(VSS) U39.J1(VSS) U39.J9(VSS) U39.L1(VSS) U39.L9(VSS) U39.N1(VSS) U39.N9(VSS) U45.A1(VSS) U45.A8(VSS) U45.B1(VSS) U45.B2(VSSQ) U45.B8(VSSQ) U45.C9(VSSQ) U45.D1(VSSQ) U45.D8(VSS) U45.D9(VSSQ) U45.F2(VSS) U45.F8(VSS) U45.J1(VSS) U45.J9(VSS) U45.L1(VSS) U45.L9(VSS) U45.N1(VSS) U45.N9(VSS) U49.A1(VSS) U49.A8(VSS) U49.B1(VSS) U49.B2(VSSQ) U49.B8(VSSQ) U49.C9(VSSQ) U49.D1(VSSQ) U49.D8(VSS) U49.D9(VSSQ) U49.F2(VSS) U49.F8(VSS) U49.J1(VSS) U49.J9(VSS) U49.L1(VSS) U49.L9(VSS) U49.N1(VSS) U49.N9(VSS) U122.2(GND) U123.B1(GND) ; also on sheet 1 11 12 16 17 18 19 20 21 22 23 24 25 26 27 28 29 30 31 32 33 34 35 36 37 38 39 40 41 42 43 44 45 46 47 48 49 50
DVDD18: C177.1 C225.2 C229.2 C244.2 C597.2 C600.1 FB17.1 FB19.1 FB20.1 FB21.1 FB23.1 FB24.1 FB25.1 FB27.1 FB28.1 FB29.1 U1.F17(DVDD18) U1.F19(DVDD18/USB_LDO) U1.G6(DVDD18/PCIE_LDO) U1.J6(DVDD18) U1.K19(DVDD18) U1.L6(DVDD18) U1.L20(DVDD18) U1.M7(DVDD18) U1.U6(DVDD18) U1.U18(DVDD18) U1.V19(DVDD18) U1.W6(DVDD18) ; also on sheet 48
DVDD33: C178.2 C179.2 C185.2 C187.2 C197.1 C224.2 C231.2 C242.2 C243.1 C252.2 C253.2 C534.2 C538.1 C539.1 C550.1 C564.1 C585.1 C588.1 C596.2 C609.2 C613.1 C614.2 C615.1 C616.1 C617.2 C621.2 U1.AA23(DVDD33) U1.E23(DVDD33) U1.F7(DVDD33) U1.F11(DVDD33) U1.F15(DVDD33) U1.F21(DVDD33) U1.G12(DVDD33) U1.G16(DVDD33) U1.G18(DVDD33_USB) U1.G20(DVDD33) U1.H9(DVDD33) U1.H11(DVDD33) U1.H13(DVDD33) U1.H15(DVDD33) U1.H17(DVDD33_USB) U1.J20(DVDD33) U1.P7(DVDD33) U1.P19(DVDD33) U1.R6(DVDD33) U1.R20(DVDD33) U1.T7(DVDD33) U1.T19(DVDD33) U1.T23(DVDD33) U1.U20(DVDD33) U1.V21(DVDD33) ; also on sheet 48
DVDD_DDR: C198.2 C199.2 C202.1 C203.2 C208.2 C209.2 C212.1 C226.1 C227.1 C230.2 C565.2 C566.2 C573.1 C574.2 C576.1 C595.2 C598.2 C601.2 U1.AD5(DVDD_DDR) U1.AD11(DVDD_DDR) U1.AD18(DVDD_DDR) U1.AE8(DVDD_DDR) U1.AE14(DVDD_DDR) U1.U8(DVDD_DDR) U1.U10(DVDD_DDR) U1.U12(DVDD_DDR) U1.U14(DVDD_DDR) U1.V7(DVDD_DDR) U1.V11(DVDD_DDR) U1.V13(DVDD_DDR) U1.V15(DVDD_DDR) U1.V17(DVDD_DDR) U1.W16(DVDD_DDR) U1.W18(DVDD_DDR) ; also on sheet 48
DVDD_DDRPLL: C189.1 C190.2 C192.2 C552.1 C557.2 FB20.2 U1.W8(DVDD_DDRDLL) U1.W10(DVDD_DDRDLL) U1.W14(DVDD_DDRDLL)
VCC0V85: C205.1 C267.1 FB22.1 FB30.1 ; also on sheet 50
VCC3V3_BMC: C756.2 R832.1 U122.1(VCCA) ; also on sheet 28 29 37 38 45 46 47 50
VCC_DDR_VREF: C440.2 C455.2 C487.2 C500.2 C510.2 C521.2 C540.2 C554.2 C561.2 R403.2 U27.E1(VREFDQ) U27.J8(VREFCA) U39.E1(VREFDQ) U39.J8(VREFCA) U45.E1(VREFDQ) U45.J8(VREFCA) U49.E1(VREFDQ) U49.J8(VREFCA) ; also on sheet 16 50
VDD18_1V8: C175.1 C184.1 C527.1 FB19.2 U1.H5(DVDD18)
VDDAHV: C201.1 C204.1 C572.1 FB21.2 U1.K7(VDDAHV)
CVDD: C181.1 C183.1 C188.1 C191.1 C193.1 C194.1 C195.1 C196.1 C200.1 C214.1 C215.1 C228.2 C237.1 C246.2 C248.2 C263.1 C264.1 C535.2 C537.2 C549.1 C551.1 C553.1 C556.1 C558.1 C560.1 C562.1 C567.1 C586.1 C587.2 C590.1 C591.2 C593.2 C599.2 C611.2 C618.1 C620.2 C627.1 C628.1 C794.1 C795.1 C796.1 C797.1 U1.J10(CVDD) U1.J14(CVDD) U1.J16(CVDD) U1.K9(CVDD) U1.K11(CVDD) U1.K13(CVDD) U1.K15(CVDD) U1.K17(CVDD) U1.L10(CVDD) U1.L12(CVDD) U1.L14(CVDD) U1.L16(CVDD) U1.L18(CVDD) U1.M9(CVDD) U1.M11(CVDD) U1.M13(CVDD) U1.M15(CVDD) U1.M17(CVDD) U1.N10(CVDD) U1.N12(CVDD) U1.N14(CVDD) U1.N16(CVDD) U1.P9(CVDD) U1.P11(CVDD) U1.P13(CVDD) U1.P15(CVDD) U1.P17(CVDD) U1.R8(CVDD) U1.R10(CVDD) U1.R12(CVDD) U1.R14(CVDD) U1.R16(CVDD) U1.R18(CVDD) U1.T9(CVDD) U1.T11(CVDD) U1.T15(CVDD) U1.T17(CVDD) U1.U16(CVDD) ; also on sheet 48
CVDD1: C172.1 C176.1 C182.1 C216.1 C247.1 C536.2 C619.2 U1.J12(CVDD1) U1.M5(CVDD1) U1.N8(CVDD1) U1.N18(CVDD1) U1.T13(CVDD1) ; also on sheet 48
DDR_A0: U27.K3(A0) U39.K3(A0) U45.K3(A0) U49.K3(A0) ; also on sheet 16
DDR_A1: U27.L7(A1) U39.L7(A1) U45.L7(A1) U49.L7(A1) ; also on sheet 16
DDR_A2: U27.L3(A2) U39.L3(A2) U45.L3(A2) U49.L3(A2) ; also on sheet 16
DDR_A3: U27.K2(A3) U39.K2(A3) U45.K2(A3) U49.K2(A3) ; also on sheet 16
DDR_A4: U27.L8(A4) U39.L8(A4) U45.L8(A4) U49.L8(A4) ; also on sheet 16
DDR_A5: U27.L2(A5) U39.L2(A5) U45.L2(A5) U49.L2(A5) ; also on sheet 16
DDR_A6: U27.M8(A6) U39.M8(A6) U45.M8(A6) U49.M8(A6) ; also on sheet 16
DDR_A7: U27.M2(A7) U39.M2(A7) U45.M2(A7) U49.M2(A7) ; also on sheet 16
DDR_A8: U27.N8(A8) U39.N8(A8) U45.N8(A8) U49.N8(A8) ; also on sheet 16
DDR_A9: U27.M3(A9) U39.M3(A9) U45.M3(A9) U49.M3(A9) ; also on sheet 16
DDR_A10: U27.H7(A10/AP) U39.H7(A10/AP) U45.H7(A10/AP) U49.H7(A10/AP) ; also on sheet 16
DDR_A11: U27.M7(A11) U39.M7(A11) U45.M7(A11) U49.M7(A11) ; also on sheet 16
DDR_A12: U27.K7(A12/BC#) U39.K7(A12/BC#) U45.K7(A12/BC#) U49.K7(A12/BC#) ; also on sheet 16
DDR_A13: U27.N3(A13) U39.N3(A13) U45.N3(A13) U49.N3(A13) ; also on sheet 16
DDR_A14: U27.N7(A14) U39.N7(A14) U45.N7(A14) U49.N7(A14) ; also on sheet 16
DDR_A15: U27.J7(A15) U39.J7(A15) U45.J7(A15) U49.J7(A15) ; also on sheet 16
DDR_BA0: U27.J2(BA0) U39.J2(BA0) U45.J2(BA0) U49.J2(BA0) ; also on sheet 16
DDR_BA1: U27.K8(BA1) U39.K8(BA1) U45.K8(BA1) U49.K8(BA1) ; also on sheet 16
DDR_BA2: U27.J3(BA2) U39.J3(BA2) U45.J3(BA2) U49.J3(BA2) ; also on sheet 16
DDR_CAS#: U27.G3(CAS#) U39.G3(CAS#) U45.G3(CAS#) U49.G3(CAS#) ; also on sheet 16
DDR_CK: U27.F7(CK) U39.F7(CK) U45.F7(CK) U49.F7(CK) ; also on sheet 16
DDR_CK#: U27.G7(CK#) U39.G7(CK#) U45.G7(CK#) U49.G7(CK#) ; also on sheet 16
DDR_CKE: U27.G9(CKE) U39.G9(CKE) U45.G9(CKE) U49.G9(CKE) ; also on sheet 16
DDR_CS#: U27.H2(CS#) U39.H2(CS#) U45.H2(CS#) U49.H2(CS#) ; also on sheet 16
DDR_DM0: U27.B7(DM/TDQS) ; also on sheet 16
DDR_DM1: U39.B7(DM/TDQS) ; also on sheet 16
DDR_DM2: U45.B7(DM/TDQS) ; also on sheet 16
DDR_DM3: U49.B7(DM/TDQS) ; also on sheet 16
DDR_DQ0: U27.B3(DQ0) ; also on sheet 16
DDR_DQ1: U27.C7(DQ1) ; also on sheet 16
DDR_DQ2: U27.C2(DQ2) ; also on sheet 16
DDR_DQ3: U27.C8(DQ3) ; also on sheet 16
DDR_DQ4: U27.E3(NF/DQ4) ; also on sheet 16
DDR_DQ5: U27.E8(NF/DQ5) ; also on sheet 16
DDR_DQ6: U27.D2(NF/DQ6) ; also on sheet 16
DDR_DQ7: U27.E7(NF/DQ7) ; also on sheet 16
DDR_DQ8: U39.B3(DQ0) ; also on sheet 16
DDR_DQ9: U39.C7(DQ1) ; also on sheet 16
DDR_DQ10: U39.C2(DQ2) ; also on sheet 16
DDR_DQ11: U39.C8(DQ3) ; also on sheet 16
DDR_DQ12: U39.E3(NF/DQ4) ; also on sheet 16
DDR_DQ13: U39.E8(NF/DQ5) ; also on sheet 16
DDR_DQ14: U39.D2(NF/DQ6) ; also on sheet 16
DDR_DQ15: U39.E7(NF/DQ7) ; also on sheet 16
DDR_DQ16: U45.B3(DQ0) ; also on sheet 16
DDR_DQ17: U45.C7(DQ1) ; also on sheet 16
DDR_DQ18: U45.C2(DQ2) ; also on sheet 16
DDR_DQ19: U45.C8(DQ3) ; also on sheet 16
DDR_DQ20: U45.E3(NF/DQ4) ; also on sheet 16
DDR_DQ21: U45.E8(NF/DQ5) ; also on sheet 16
DDR_DQ22: U45.D2(NF/DQ6) ; also on sheet 16
DDR_DQ23: U45.E7(NF/DQ7) ; also on sheet 16
DDR_DQ24: U49.B3(DQ0) ; also on sheet 16
DDR_DQ25: U49.C7(DQ1) ; also on sheet 16
DDR_DQ26: U49.C2(DQ2) ; also on sheet 16
DDR_DQ27: U49.C8(DQ3) ; also on sheet 16
DDR_DQ28: U49.E3(NF/DQ4) ; also on sheet 16
DDR_DQ29: U49.E8(NF/DQ5) ; also on sheet 16
DDR_DQ30: U49.D2(NF/DQ6) ; also on sheet 16
DDR_DQ31: U49.E7(NF/DQ7) ; also on sheet 16
DDR_DQS0: U27.C3(DQS) ; also on sheet 16
DDR_DQS0#: U27.D3(DQS#) ; also on sheet 16
DDR_DQS1: U39.C3(DQS) ; also on sheet 16
DDR_DQS1#: U39.D3(DQS#) ; also on sheet 16
DDR_DQS2: U45.C3(DQS) ; also on sheet 16
DDR_DQS2#: U45.D3(DQS#) ; also on sheet 16
DDR_DQS3: U49.C3(DQS) ; also on sheet 16
DDR_DQS3#: U49.D3(DQS#) ; also on sheet 16
DDR_ODT: U27.G1(ODT) U39.G1(ODT) U45.G1(ODT) U49.G1(ODT) ; also on sheet 16
DDR_RAS#: U27.F3(RAS#) U39.F3(RAS#) U45.F3(RAS#) U49.F3(RAS#) ; also on sheet 16
DDR_RESET#: U27.N2(RESET#) U39.N2(RESET#) U45.N2(RESET#) U49.N2(RESET#) ; also on sheet 16
DDR_WE#: U27.H3(WE#) U39.H3(WE#) U45.H3(WE#) U49.H3(WE#) ; also on sheet 16
LDO1_1V8: C757.1 C758.2 U122.6(VCCB) U123.A2(VIN) ; also on sheet 18 23 24 30 36 48
LDO_PCIE_CAP: C207.1 C575.1 FB22.2 U1.J8(LDO_PCIE_CAP) U1.L8(LDO_PCIE_CAP)
LDO_USB_CAP: C251.1 C631.1 FB30.2 U1.H19(LDO_USB_CAP) U1.J18(LDO_USB_CAP)
PMIC_VDD2: C442.1 C443.1 C444.1 C445.1 C448.1 C449.1 C450.1 C456.1 C462.1 C465.1 C474.1 C475.1 C477.1 C478.1 C488.1 C489.1 C490.1 C491.1 C494.1 C495.1 C496.1 C501.1 C502.1 C503.1 C506.1 C507.1 C508.1 C509.1 C511.1 C512.1 C513.1 C514.1 C515.1 C516.1 C517.1 C522.1 C523.1 C524.1 C528.1 C529.1 C530.1 C531.1 C541.1 C542.1 C543.1 C544.1 C546.1 C547.1 C548.1 C555.1 C559.1 C563.1 C568.1 C569.1 C570.1 C571.1 U27.A2(VDD) U27.A9(VDD) U27.B9(VDDQ) U27.C1(VDDQ) U27.D7(VDD) U27.E2(VDDQ) U27.E9(VDDQ) U27.G2(VDD) U27.G8(VDD) U27.K1(VDD) U27.K9(VDD) U27.M1(VDD) U27.M9(VDD) U39.A2(VDD) U39.A9(VDD) U39.B9(VDDQ) U39.C1(VDDQ) U39.D7(VDD) U39.E2(VDDQ) U39.E9(VDDQ) U39.G2(VDD) U39.G8(VDD) U39.K1(VDD) U39.K9(VDD) U39.M1(VDD) U39.M9(VDD) U45.A2(VDD) U45.A9(VDD) U45.B9(VDDQ) U45.C1(VDDQ) U45.D7(VDD) U45.E2(VDDQ) U45.E9(VDDQ) U45.G2(VDD) U45.G8(VDD) U45.K1(VDD) U45.K9(VDD) U45.M1(VDD) U45.M9(VDD) U49.A2(VDD) U49.A9(VDD) U49.B9(VDDQ) U49.C1(VDDQ) U49.D7(VDD) U49.E2(VDDQ) U49.E9(VDDQ) U49.G2(VDD) U49.G8(VDD) U49.K1(VDD) U49.K9(VDD) U49.M1(VDD) U49.M9(VDD) ; also on sheet 16 48 50
SOC_VPP_EN: R833.1 U122.4(B) U123.B2(ON)
VPP1V8: C759.2 C760.1 U1.W21(VPP2) U1.Y21(VPP1) U123.A1(VOUT)
VPP_EN: U122.3(A) ; also on sheet 46
N16863485: R693.2 U27.H8(ZQ)
N16909238: R704.2 U39.H8(ZQ)
N16911821: R712.2 U45.H8(ZQ)
N17856438: TP106.1(TP) U27.A7(NF/TDQS#)
N17856470: TP115.1(TP) U39.A7(NF/TDQS#)
N17856498: TP123.1(TP) U45.A7(NF/TDQS#)
N19533446: R718.2 U49.H8(ZQ)
N19533734: TP126.1(TP) U49.A7(NF/TDQS#)
N19760880: R403.1 U1.Y9(DDR3_VREFSSTL)
N23280297: R832.2 U122.5(DIR)

Not connected (* = marked no-connect by the designer): U27 A3(NC1)* F1(NC2)* F9(NC3)* H1(NC4)* H9(NC5)*; U39 A3(NC1)* F1(NC2)* F9(NC3)* H1(NC4)* H9(NC5)*; U45 A3(NC1)* F1(NC2)* F9(NC3)* H1(NC4)* H9(NC5)*; U49 A3(NC1)* F1(NC2)* F9(NC3)* H1(NC4)* H9(NC5)*

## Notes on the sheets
sheet 13
- VPP POWER GENERATION
- SoC POWER -CVDD,CVDD1
- SoC POWER - PLL
- MOUNT THE FERRITE BEAD, ONLY WHEN ON BOARD LDOs ARE DISABLED
- THESE PLL & VDD PINS ARE POWER,
  DON'T ROUTE WITH SIGNAL TRACE
- MOUNT THE FERRITE BEAD, ONLY WHEN ON BOARD LDOs ARE DISABLED
sheet 14
- SoC POWER - DVDD33
- SoC POWER - DVDD18, DVDD_DDR
- SoC POWER - VSS
sheet 15
- DDR DEVICE2
- DDR DEVICE1
- DDR DEVICE4
- DDR DEVICE3
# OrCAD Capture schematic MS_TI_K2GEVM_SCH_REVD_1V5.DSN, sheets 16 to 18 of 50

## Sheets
16 15. DDR3 ECC & TERMINATIONS: size C; title: SOC DDR MODULE, ECC & TERMINATION
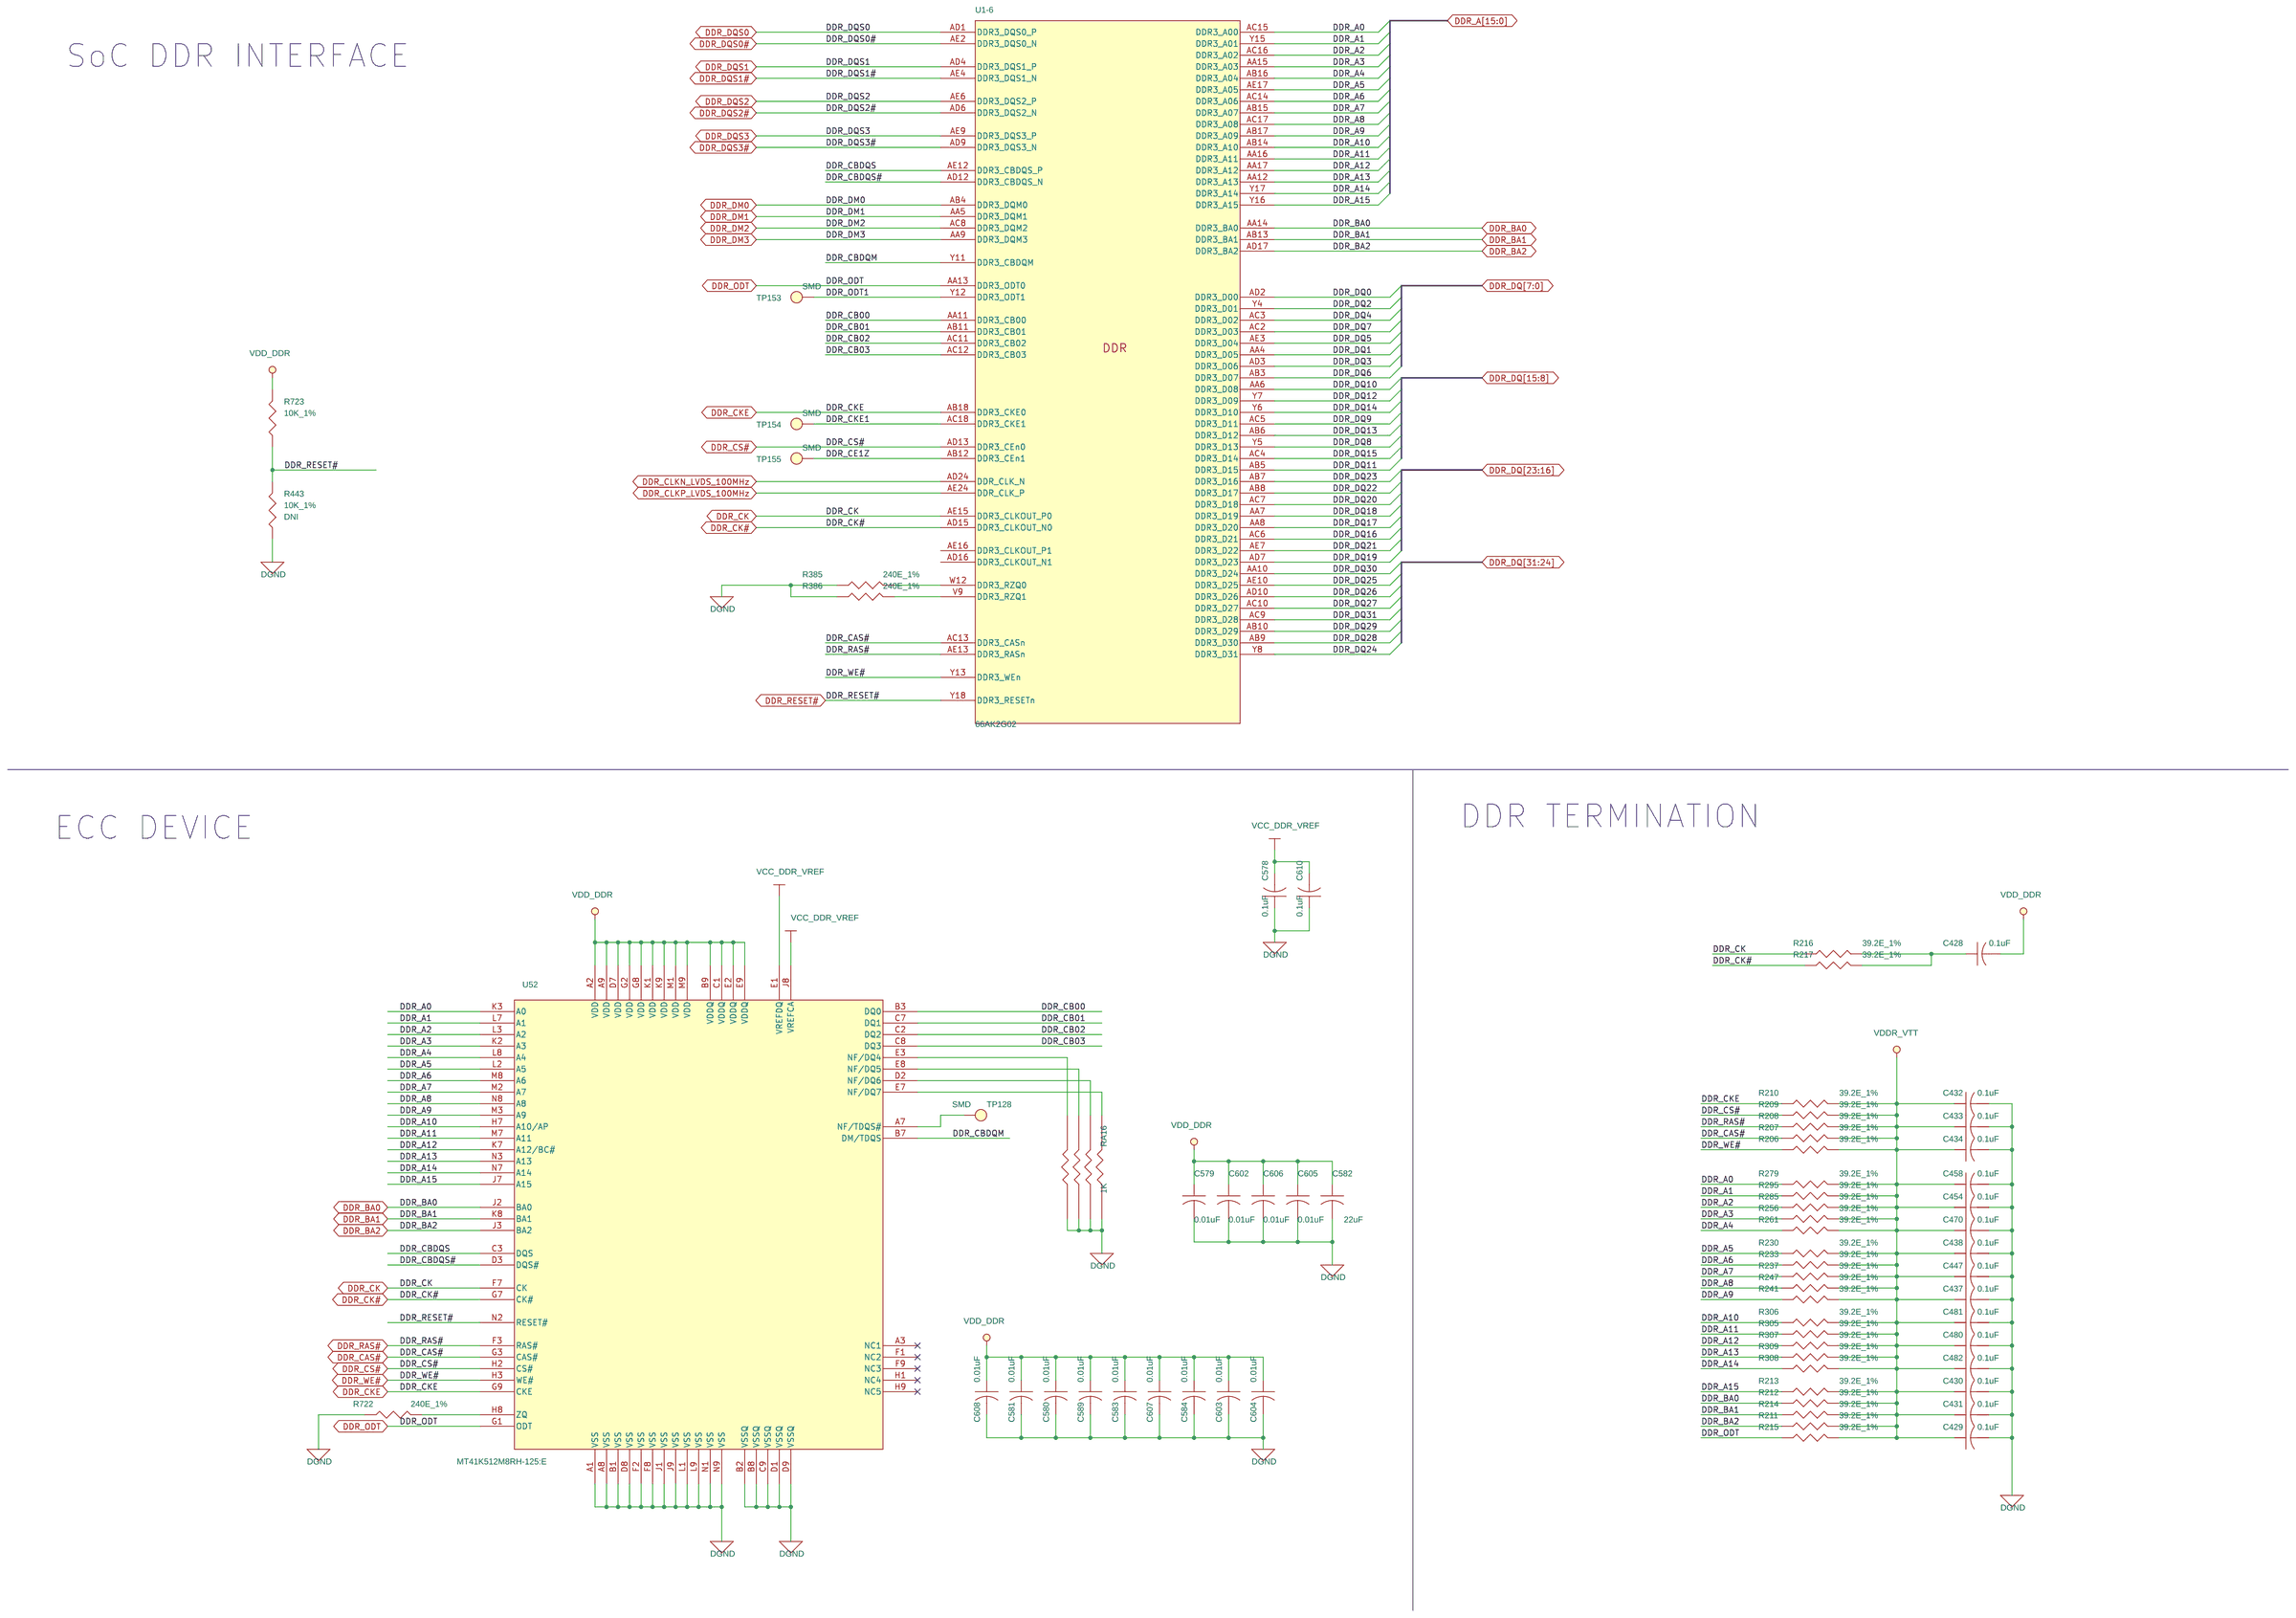
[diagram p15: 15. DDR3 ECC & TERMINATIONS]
17 16. QSPI, SPI & I2C EEPROM: size C; title: QSPI, I2C & SPI EEPROM FLASH
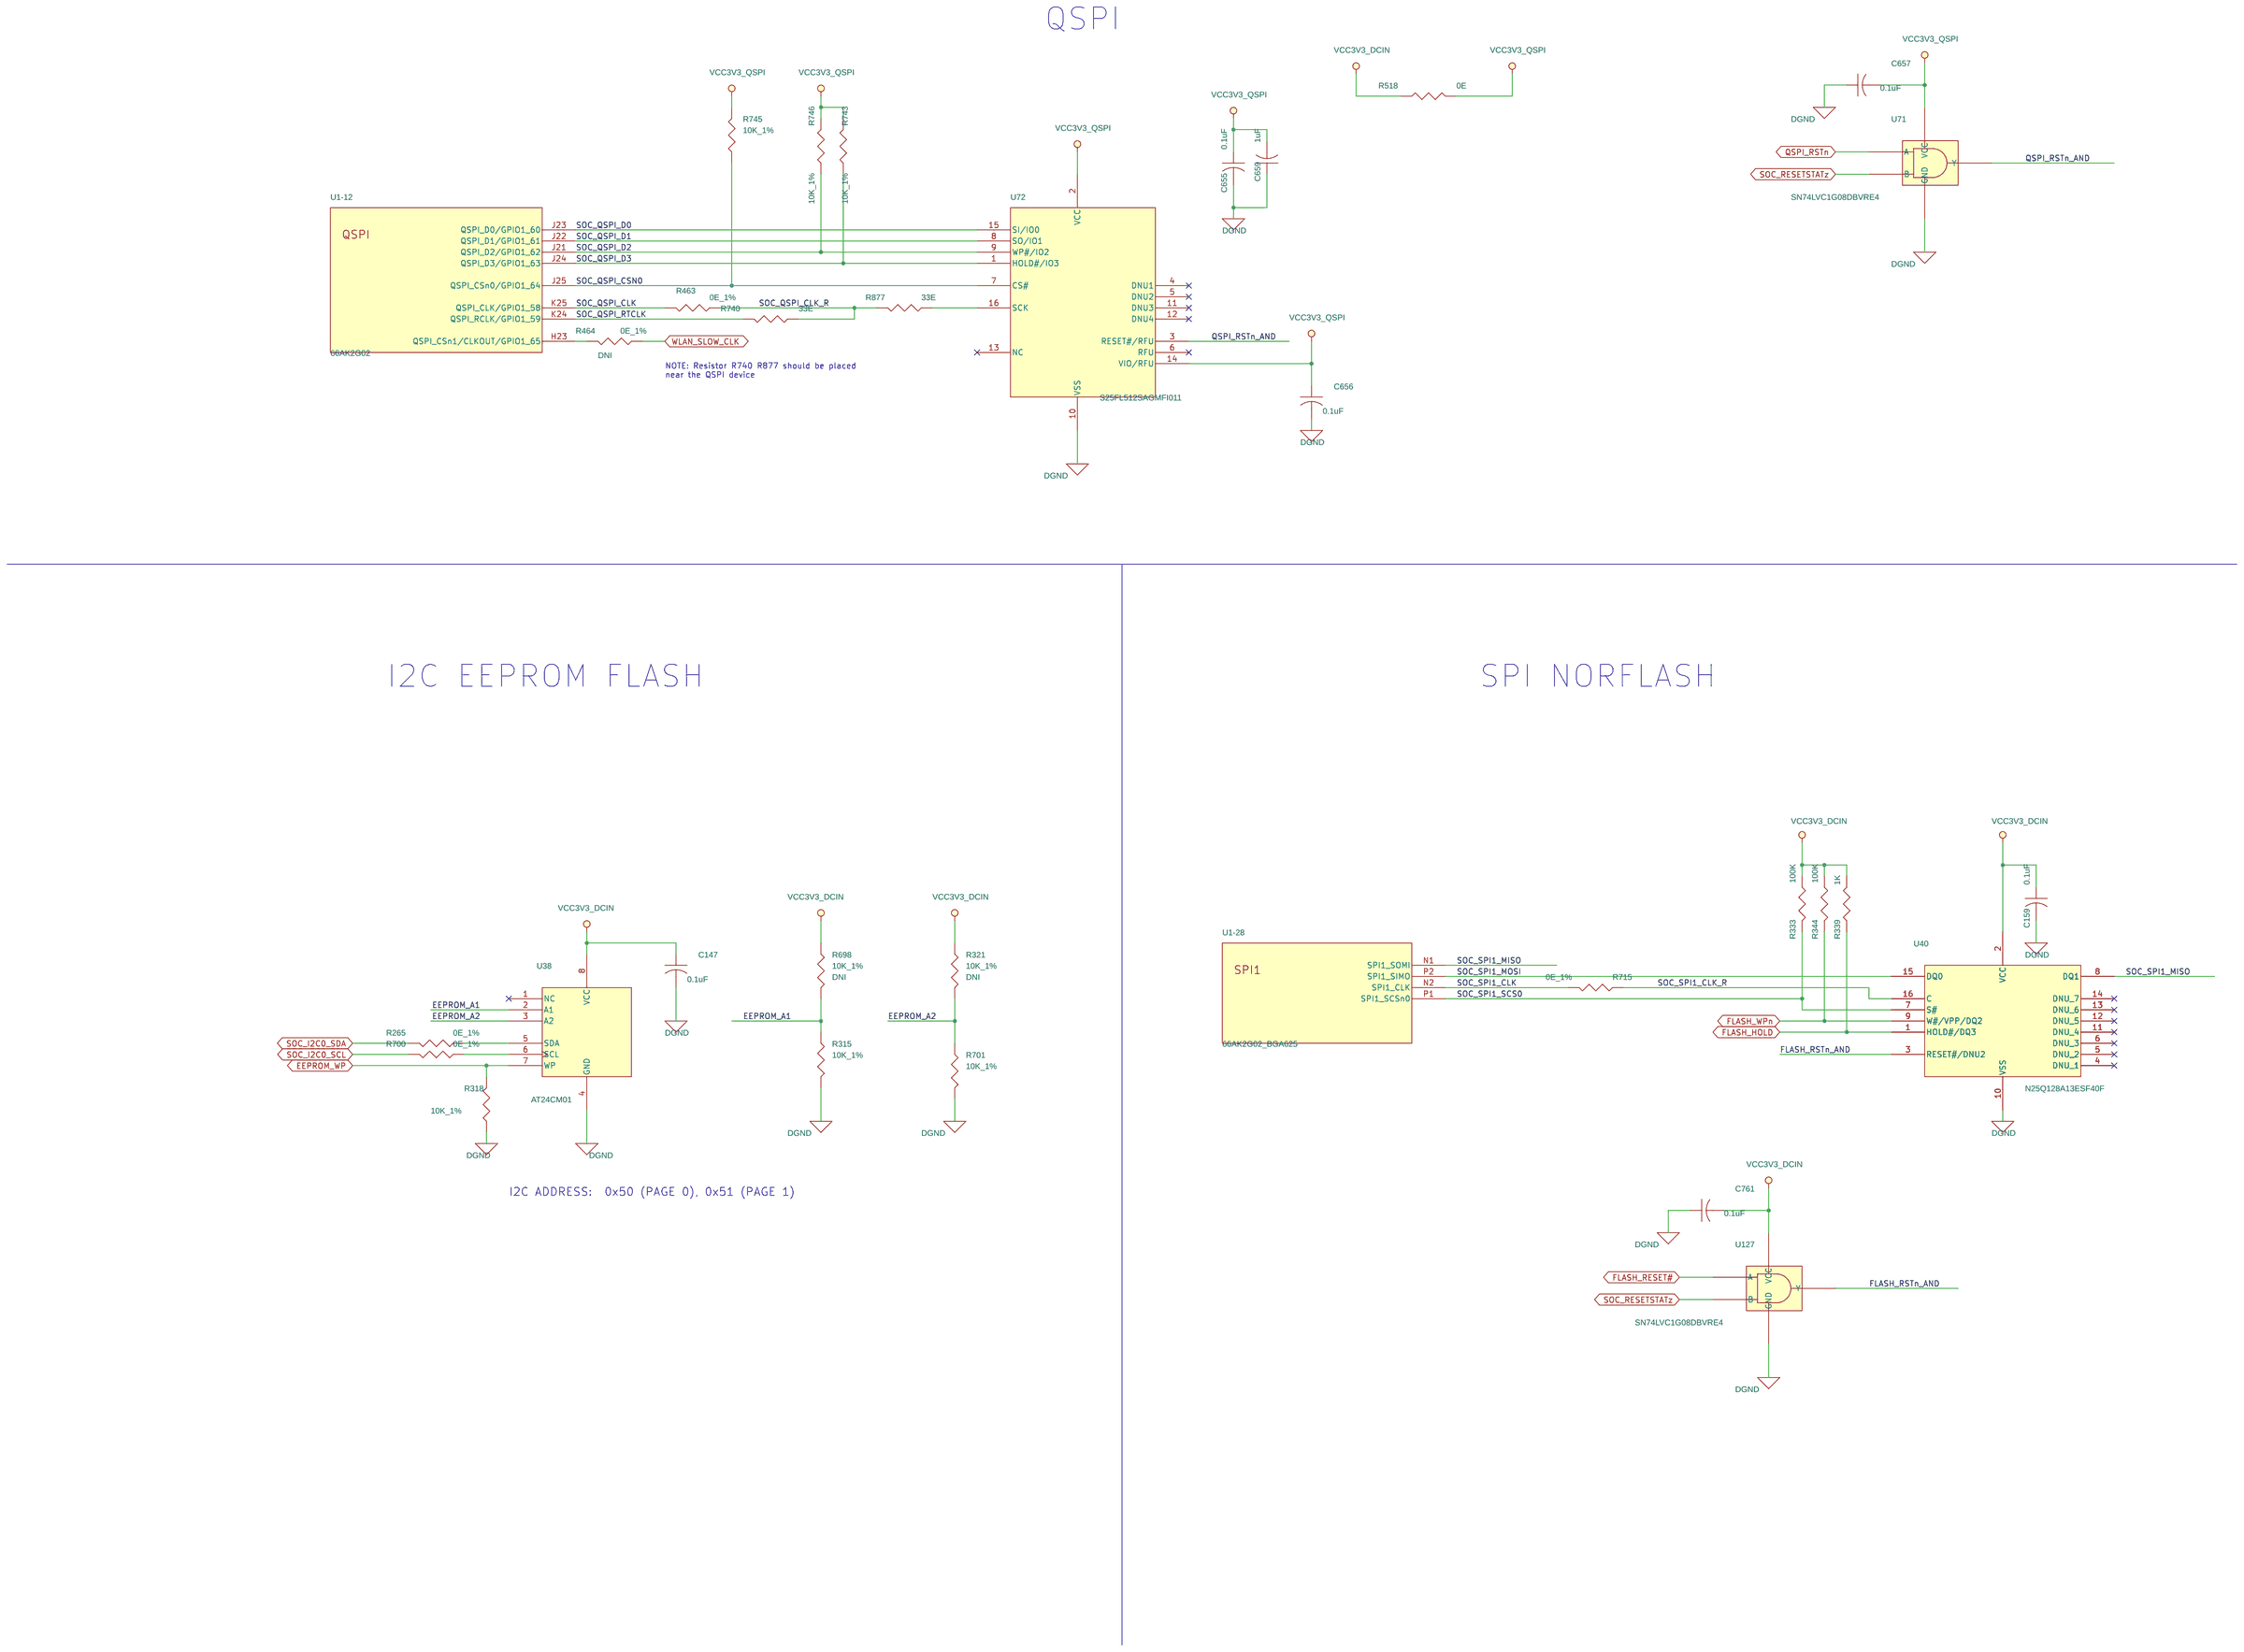
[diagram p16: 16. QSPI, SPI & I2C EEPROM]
18 17. EMMC FLASH: size C; title: EMMC FLASH

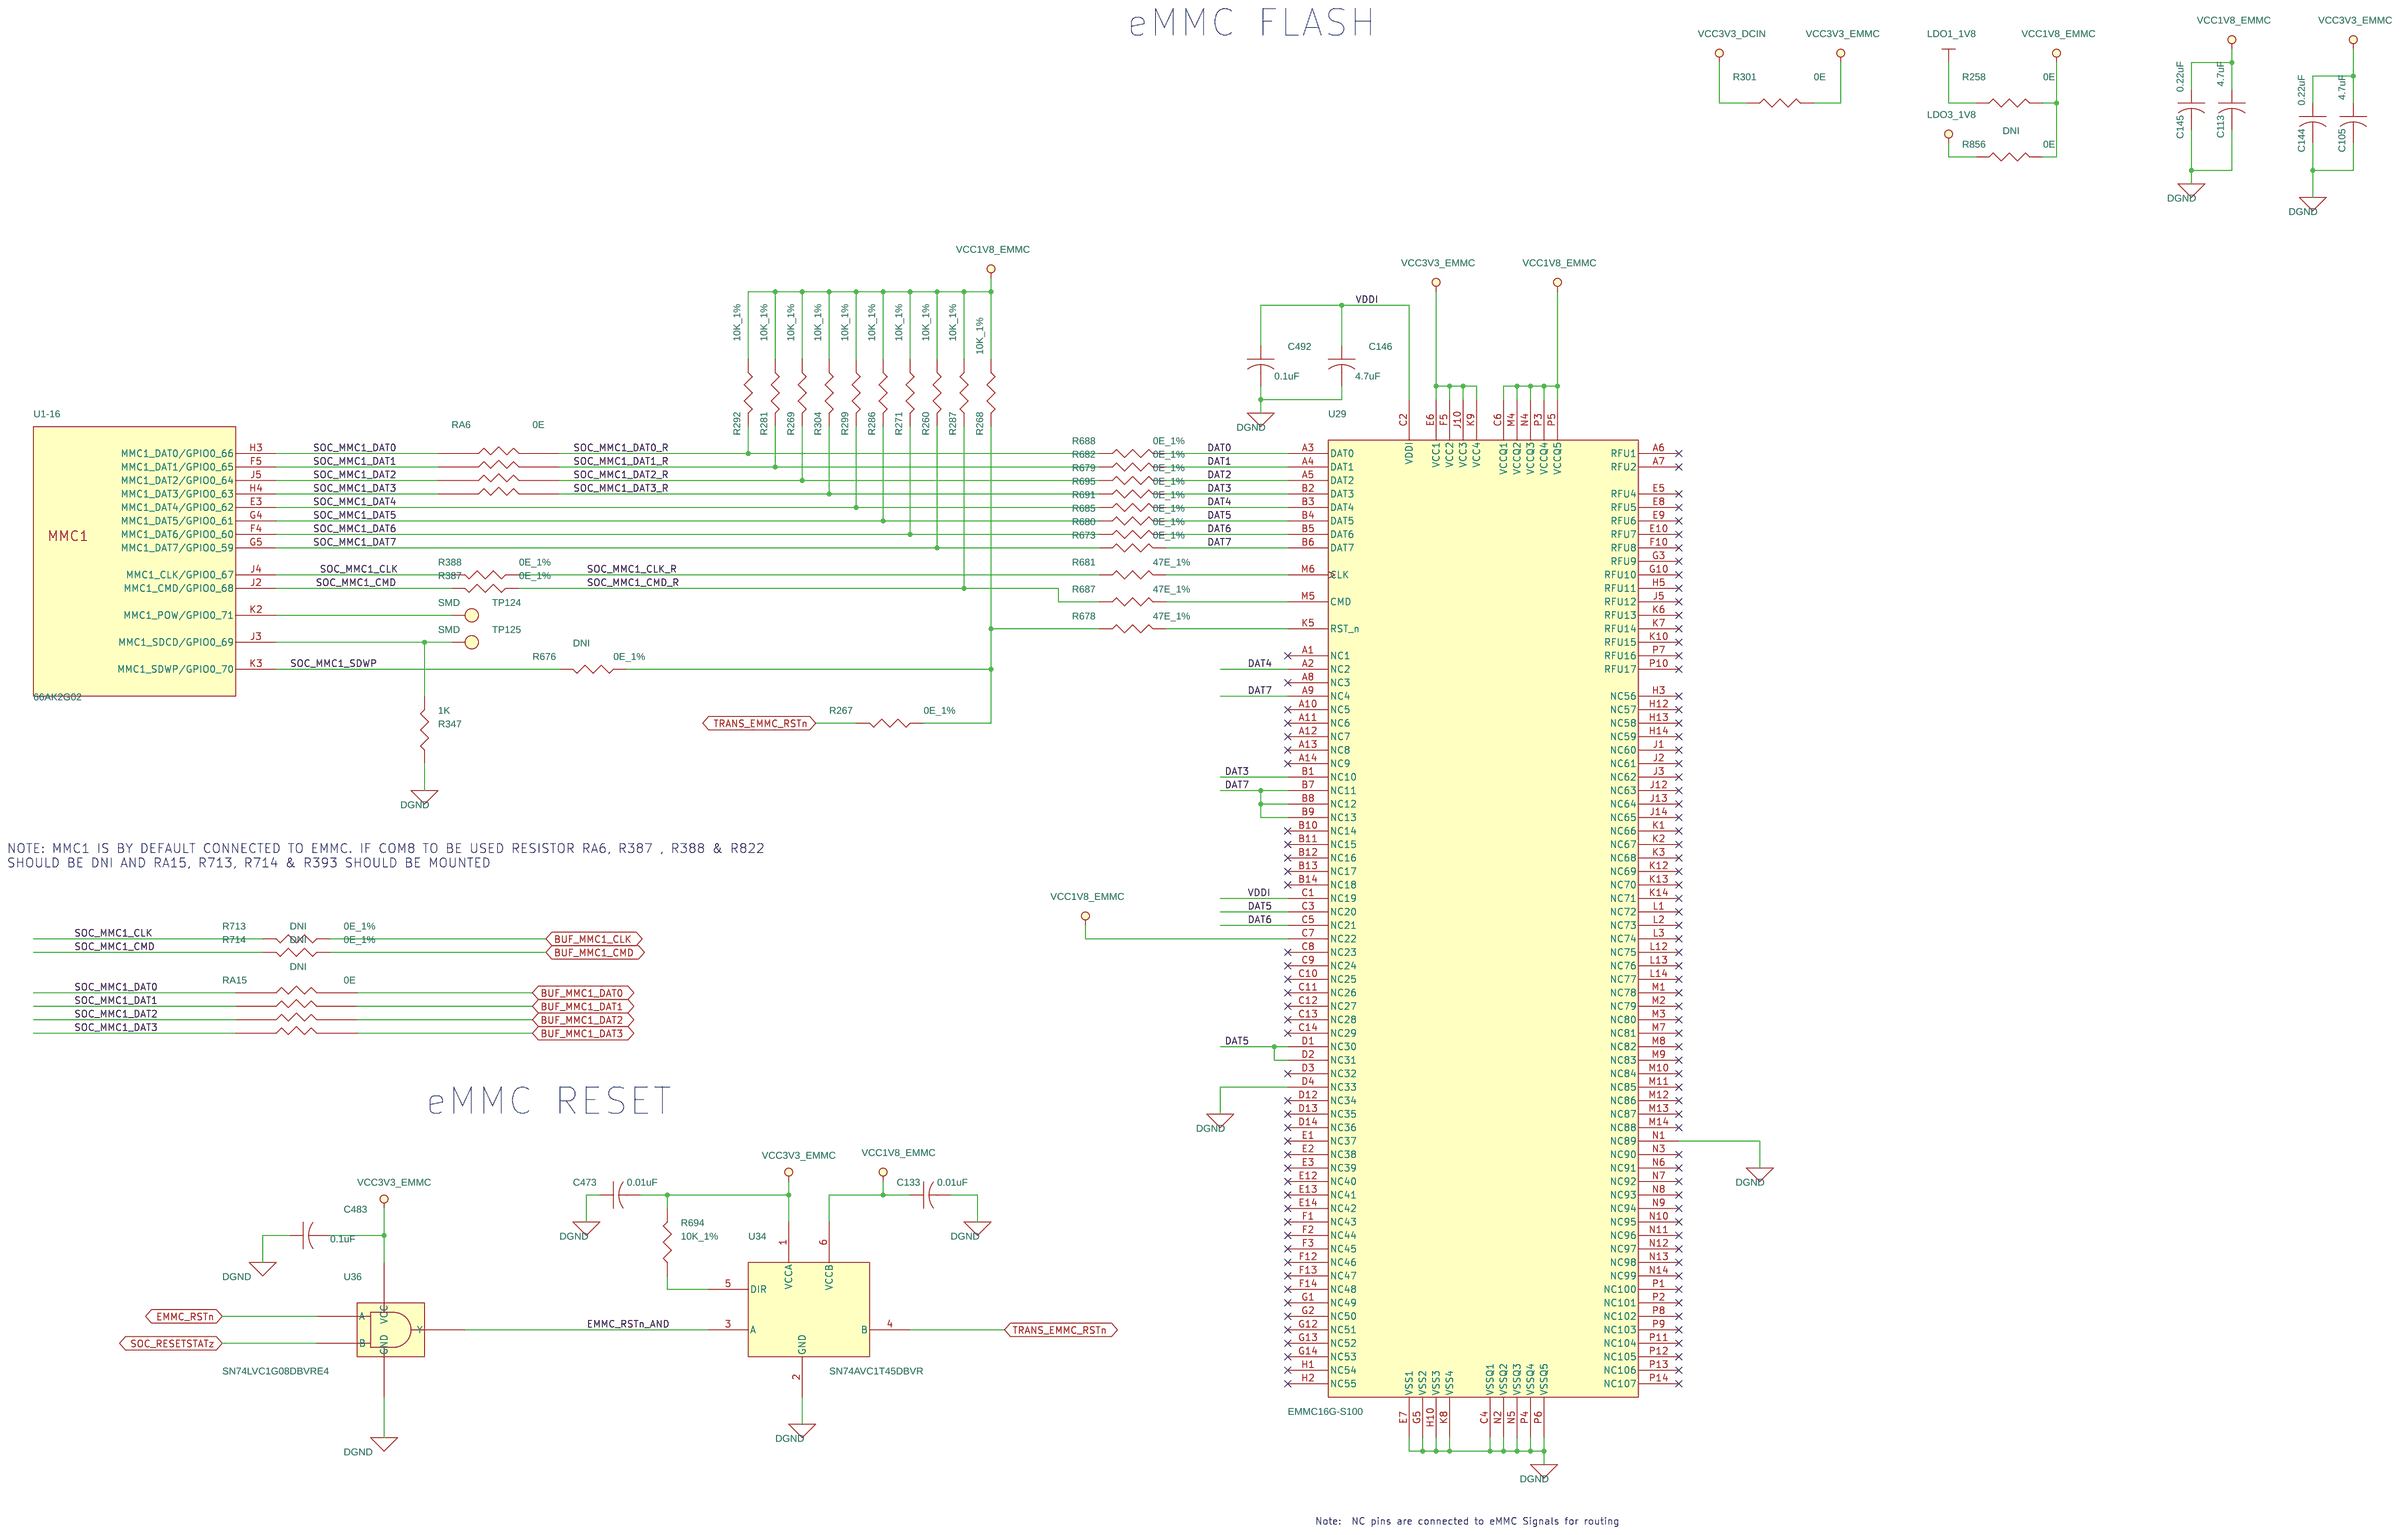
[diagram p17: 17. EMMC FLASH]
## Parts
sheet 15. DDR3 ECC & TERMINATIONS
C428  0.1uF  [CAP0402]
C429  0.1uF  [CAP0402]
C430  0.1uF  [CAP0402]
C431  0.1uF  [CAP0402]
C432  0.1uF  [CAP0402]
C433  0.1uF  [CAP0402]
C434  0.1uF  [CAP0402]
C437  0.1uF  [CAP0402]
C438  0.1uF  [CAP0402]
C447  0.1uF  [CAP0402]
C454  0.1uF  [CAP0402]
C458  0.1uF  [CAP0402]
C470  0.1uF  [CAP0402]
C480  0.1uF  [CAP0402]
C481  0.1uF  [CAP0402]
C482  0.1uF  [CAP0402]
C578  0.1uF  [CAP0402]
C579  0.01uF  [CAP0402]
C580  0.01uF  [CAP0402]
C581  0.01uF  [CAP0402]
C582  22uF  [CAP0805]
C583  0.01uF  [CAP0402]
C584  0.01uF  [CAP0402]
C589  0.01uF  [CAP0402]
C602  0.01uF  [CAP0402]
C603  0.01uF  [CAP0402]
C604  0.01uF  [CAP0402]
C605  0.01uF  [CAP0402]
C606  0.01uF  [CAP0402]
C607  0.01uF  [CAP0402]
C608  0.01uF  [CAP0402]
C610  0.1uF  [CAP0402]
R206  39.2E_1%  [RES0402]
R207  39.2E_1%  [RES0402]
R208  39.2E_1%  [RES0402]
R209  39.2E_1%  [RES0402]
R210  39.2E_1%  [RES0402]
R211  39.2E_1%  [RES0402]
R212  39.2E_1%  [RES0402]
R213  39.2E_1%  [RES0402]
R214  39.2E_1%  [RES0402]
R215  39.2E_1%  [RES0402]
R216  39.2E_1%  [RES0402]
R217  39.2E_1%  [RES0402]
R230  39.2E_1%  [RES0402]
R233  39.2E_1%  [RES0402]
R237  39.2E_1%  [RES0402]
R241  39.2E_1%  [RES0402]
R247  39.2E_1%  [RES0402]
R256  39.2E_1%  [RES0402]
R261  39.2E_1%  [RES0402]
R279  39.2E_1%  [RES0402]
R285  39.2E_1%  [RES0402]
R295  39.2E_1%  [RES0402]
R305  39.2E_1%  [RES0402]
R306  39.2E_1%  [RES0402]
R307  39.2E_1%  [RES0402]
R308  39.2E_1%  [RES0402]
R309  39.2E_1%  [RES0402]
R385  240E_1%  [RES0201]
R386  240E_1%  [RES0201]
R443  10K_1%  [RES0402]
R722  240E_1%  [RES0402]
R723  10K_1%  [RES0402]
RA16  1K  [RESA_0402-4]
TP128  SMD  [TP40_SMD]
TP153  SMD  [TP40_SMD]
TP154  SMD  [TP40_SMD]
TP155  SMD  [TP40_SMD]
U52  MT41K512M8RH-125:E  [FBGA78_31-49_360X420]
sheet 16. QSPI, SPI & I2C EEPROM
C147  0.1uF  [CAP0402]
C159  0.1uF  [CAP0402]
C655  0.1uF  [CAP0402]
C656  0.1uF  [CAP0402]
C657  0.1uF  [CAP0402]
C659  1uF  [CAP0402]
C761  0.1uF  [CAP0402]
R265  0E_1%  [RES0402]
R315  10K_1%  [RES0402]
R318  10K_1%  [RES0402]
R321  10K_1%  [RES0402]
R333  100K  [RES0402]
R339  1K  [RES0402]
R344  100K  [RES0402]
R463  0E_1%  [RES0402]
R464  0E_1%  [RES0402]
R518  0E  [RES0402]
R698  10K_1%  [RES0402]
R700  0E_1%  [RES0402]
R701  10K_1%  [RES0402]
R715  0E_1%  [RES0402]
R740  33E  [RES0402]
R743  10K_1%  [RES0402]
R745  10K_1%  [RES0402]
R746  10K_1%  [RES0402]
R877  33E  [RES0402]
U38  AT24CM01  [TSSOP8_25-59_125X180]
U40  N25Q128A13ESF40F  [SOIC16_W]
U71  SN74LVC1G08DBVRE4  [SOT23-5]
U72  S25FL512SAGMFI011  [SOIC16_W]
U127  SN74LVC1G08DBVRE4  [SOT23-5]
sheet 17. EMMC FLASH
C105  4.7uF  [CAP0603]
C113  4.7uF  [CAP0603]
C133  0.01uF  [CAP0402]
C144  0.22uF  [CAP0402]
C145  0.22uF  [CAP0402]
C146  4.7uF  [CAP0603]
C473  0.01uF  [CAP0402]
C483  0.1uF  [CAP0402]
C492  0.1uF  [CAP0402]
R258  0E  [RES0402]
R260  10K_1%  [RES0402]
R267  0E_1%  [RES0402]
R268  10K_1%  [RES0402]
R269  10K_1%  [RES0402]
R271  10K_1%  [RES0402]
R281  10K_1%  [RES0402]
R286  10K_1%  [RES0402]
R287  10K_1%  [RES0402]
R292  10K_1%  [RES0402]
R299  10K_1%  [RES0402]
R301  0E  [RES0402]
R304  10K_1%  [RES0402]
R347  1K  [RES0402]
R387  0E_1%  [RES0402]
R388  0E_1%  [RES0402]
R673  0E_1%  [RES0402]
R676  0E_1%  [RES0402]
R678  47E_1%  [RES0402]
R679  0E_1%  [RES0402]
R680  0E_1%  [RES0402]
R681  47E_1%  [RES0402]
R682  0E_1%  [RES0402]
R685  0E_1%  [RES0402]
R687  47E_1%  [RES0402]
R688  0E_1%  [RES0402]
R691  0E_1%  [RES0402]
R694  10K_1%  [RES0402]
R695  0E_1%  [RES0402]
R713  0E_1%  [RES0402]
R714  0E_1%  [RES0402]
R856  0E  [RES0402]
RA6  0E  [RESA_0402-4]
RA15  0E  [RESA_0402-4]
TP124  SMD  [TP40_SMD]
TP125  SMD  [TP40_SMD]
U29  EMMC16G-S100  [FBGA153_19-68_460X515]
U34  SN74AVC1T45DBVR  [SOT23-6]
U36  SN74LVC1G08DBVRE4  [SOT23-5]
sheet 18. NAND FLASH & MICRO SD CARD
U1  66AK2G02_BGA625  [BGASKT625_31-49_1270x1270]  (sections -1,-10,-11,-12,-13,-14,-15,-16,-17,-18,-19,-2,-20,-21,-22,-23,-24,-25,-26,-27,-28,-29,-3,-30,-31,-32,-33,-34,-35,-36,-37,-38,-4,-5,-6,-7,-8,-9)

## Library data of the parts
C147 C159 C428-C434 C437 C438 C447 C454 C458 C470 C480-C483 C492 C655-C657 C761 = CAP: CAP CERAMIC 0.1uF 16V 10% X7R 0402; Alternate_mfr_name_A: KEMET; Alternate_mfr_part_number_A: C0402C104K4RACT; Chkd/date: MAZHAR/281108; Crtd /date: MAZHAR/030907; Custom_Duty: 15%; Customs_HS_Code: 85322990; Distributor_name: DIGIKEY; Distributor_name_A: DIGIKEY; Distributor_part_number: 490-3261-1-ND; Distributor_part_number_A: 399-3521-1-ND; Height: 0.55MM; Mfr_name: MURATA; Mfr_part_number: GRM155R71C104KA88D; Mistral Part No: 120009030060-R; Package: 0402; Part_type: CAPACITORS\CERAMIC; Project: SMART VIEW_IP CAMERA; Tolerance: 10%; Voltage: 16V; Datasheet: Y:\MIS_DATABASE\DATASHEETS\CAPACITORS\GRM188SERIES.PDF
C578 C610 = CAP: CAP CERAMIC 0.1uF 25V -20% TO +80 Y5V 0402; Chkd/date: SHREESHAIL/301105; Crtd /date: MAZHAR/251005; Custom_Duty: 15%; Customs_HS_Code: 85322990; Distributor_name: DIGIKEY; Distributor_part_number: 490-3271-1-ND; Height: 0.55MM; Mfr_name: MURATA; Mfr_part_number: GRM155F51E104ZA01D; Mistral Part No: 120009030085; Package: 0402; Part_type: CAPACITORS\CERAMIC; Project: ADR; Tolerance: -20% TO +80%; Voltage: 25V; Datasheet: Y:\MIS_DATABASE\DATASHEETS\CAPACITORS\GRM188SERIES.PDF
C133 C473 C579-C581 C583 C584 C589 C602-C608 = CAP: CAP CERAMIC 0.01uF 16V 10% X7R 0402; Alternate_mfr_name_A: AVX CORPORATION; Alternate_mfr_name_B: KEMET; Alternate_mfr_name_D: TDK CORPORATION; Alternate_mfr_part_number_A: 0402YC103KAT2A; Alternate_mfr_part_number_B: C0402C103K4RACTU; Alternate_mfr_part_number_D: C1005X7R1C103K; Chkd/date: SHREESHAIL/180506; Crtd /date: MAZHAR/110506; Custom_Duty: 15%; Customs_HS_Code: 85322990; Distributor_name: DIGIKEY; Distributor_name_A: DIGIKEY; Distributor_name_B: DIGIKEY; Distributor_name_D: DIGIKEY; Distributor_part_number: PCC103BQCT-ND; Distributor_part_number_A: 478-1114-1-ND; Distributor_part_number_B: 399-1038-1-ND; Distributor_part_number_D: 445-1262-1-ND; Height: 0.55MM; Mfr_name: PANASONIC-ECG; Mfr_part_number: ECJ-0EB1C103K; Mistral Part No: 120009030032-R; Package: 0402; Part_type: CAPACITORS\CERAMIC; Project: VOCERA; RoHS: RoHS; Tolerance: 10%; Voltage: 16V; Datasheet: Y:\MIS_DATABASE\DATASHEETS\CAPACITORS\PAN-ECJ.PDF
C582 = CAP: CAP CERAMIC 22uF 16V 10% X5R 0805; Chkd/date: MAZHAR/291110; Crtd /date: BAVISH/271110; Custom_Duty: 15%; Customs_HS_Code: 85322990; Distributor_name: NA; Distributor_part_number: NA; Height: 1.45MM; Mfr_name: TDK CORPORATION; Mfr_part_number: C2012X5R1C226K; Mistral Part No: 120010110025-R; Package: 0805; Part_type: CAPACITORS\CERAMIC; Project: EM-FLS; RoHS: RoHS; Temperature: -55°C+85°C; Tolerance: 10%; Voltage: 16V; Wattage: NA; Weight: NA; Datasheet: Y:\MIS_DATABASE\DATASHEETS\CAPACITORS\C2012.PDF
R206-R217 R230 R233 R237 R241 R247 R256 R261 R279 R285 R295 R305-R309 = RESISTOR: RES 39.2E 1/16W 1% 0402; Chkd/date: RAGESH/210411; Crtd /date: MAZHAR/210411; Custom_Duty: 15%; Customs_HS_Code: 85332119; Distributor_name: DIGIKEY; Distributor_part_number: RMCF0402FT39R2CT-ND; Height: 0.40MM; Mfr_name: STACKPOLE ELECTRONICS; Mfr_part_number: RMCF0402FT39R2; Mistral Part No: 110011040030-R; Package: 0402; Part_type: RESISTORS\FIXED; Project: AOD_POD-BASECARD; RoHS: RoHS; Temperature: -55°C+155°C; Tolerance: 1%; Voltage: NA; Wattage: 1/16W; Weight: NA; Datasheet: Y:\MIS_DATABASE\DATASHEETS\RESISTORS\RMCF-SERIES.PDF
R385 R386 = RESISTOR: RES 240E 1/20W 1% 0201; Chkd/date: MAZHAR/121207; Crtd /date: USMAN/121207; Custom_Duty: 15%; Customs_HS_Code: 85332119; Distributor_name: DIGIKEY; Distributor_part_number: P240ABCT-ND; Height: 0.26MM; Mfr_name: PANASONIC-ECG; Mfr_part_number: ERJ-1GEF2400C; Mistral Part No: 110009030546; Package: 0201; Part_type: RESISTORS\FIXED; Project: SD_WATERLOO; RoHS: NA; Tolerance: 1%; Wattage: 1/20W; Datasheet: Y:\MIS_DATABASE\DATASHEETS\RESISTORS\ERJ-1G.PDF
R321 R443 R698 = RESISTOR: RES 10K 1/16W 1% 0402; Alternate_mfr_name_A: AVX CORPORATION; Alternate_mfr_name_B: PANASONIC-ECG-ECG; Alternate_mfr_name_C: YAGEO AMERICA; Alternate_mfr_name_D: VISHAY; Alternate_mfr_part_number_A: CR05-103F-H; Alternate_mfr_part_number_B: ERJ-2RKF1002X; Alternate_mfr_part_number_C: 9C04021A1002FLHF3; Alternate_mfr_part_number_D: CRCW040210K0FKED; Chkd/date: SHREESHAIL/310506; Crtd /date: GEETHA/290506; Custom_Duty: 15%; Customs_HS_Code: 85332119; Distributor_name: DIGIKEY; Distributor_name_A: NA; Distributor_name_B: DIGIKEY; Distributor_name_C: DIGIKEY; Distributor_name_D: DIGIKEY; Distributor_part_number: 311-10.0KLRTR-ND; Distributor_part_number_A: NA; Distributor_part_number_B: P10.0KLCT-ND; Distributor_part_number_C: 311-10.0KLCT-ND; Distributor_part_number_D: 541-10.0KLCT-ND; Height: 0.40MM; Loading: DNI; Mfr_name: YAGEO AMERICA; Mfr_part_number: RC0402FR-0710KL; Mistral Part No: 110009030220-P; Package: 0402; Part_type: RESISTORS\FIXED; Project: VOCERA; RoHS: Pb-Free; Tolerance: 1%; Wattage: 1/16W; Datasheet: Y:\MIS_DATABASE\DATASHEETS\RESISTORS\YAGEO-RC0402.PDF
R722 = RESISTOR: RES 240E 1/10W 1% 0402; Chkd/date: MAZHAR/150611; Crtd /date: BAVISH/020611; Custom_Duty: 15%; Customs_HS_Code: 85332119; Distributor_name: DIGIKEY; Distributor_part_number: P240LCT-ND; Height: 0.40MM; Mfr_name: PANASONIC-ECG; Mfr_part_number: ERJ-2RKF2400X; Mistral Part No: 110011060017-R; Package: 0402; Part_type: RESISTORS\FIXED; Project: AM4515_EVM_LCD; RoHS: RoHS; Temperature: -55°C+125°C; Tolerance: 1%; Voltage: NA; Wattage: 1/10W; Weight: 0.8/1000g; Datasheet: Y:\MIS_DATABASE\DATASHEETS\RESISTORS\ERJ-2R.PDF
R260 R268 R269 R271 R281 R286 R287 R292 R299 R304 R315 R318 R694 R701 R723 R743 R745 R746 = RESISTOR: RES 10K 1/16W 1% 0402; Alternate_mfr_name_A: AVX CORPORATION; Alternate_mfr_name_B: PANASONIC-ECG-ECG; Alternate_mfr_name_C: YAGEO AMERICA; Alternate_mfr_name_D: VISHAY; Alternate_mfr_part_number_A: CR05-103F-H; Alternate_mfr_part_number_B: ERJ-2RKF1002X; Alternate_mfr_part_number_C: 9C04021A1002FLHF3; Alternate_mfr_part_number_D: CRCW040210K0FKED; Chkd/date: SHREESHAIL/310506; Crtd /date: GEETHA/290506; Custom_Duty: 15%; Customs_HS_Code: 85332119; Distributor_name: DIGIKEY; Distributor_name_A: NA; Distributor_name_B: DIGIKEY; Distributor_name_C: DIGIKEY; Distributor_name_D: DIGIKEY; Distributor_part_number: 311-10.0KLRTR-ND; Distributor_part_number_A: NA; Distributor_part_number_B: P10.0KLCT-ND; Distributor_part_number_C: 311-10.0KLCT-ND; Distributor_part_number_D: 541-10.0KLCT-ND; Height: 0.40MM; Mfr_name: YAGEO AMERICA; Mfr_part_number: RC0402FR-0710KL; Mistral Part No: 110009030220-P; Package: 0402; Part_type: RESISTORS\FIXED; Project: VOCERA; RoHS: Pb-Free; Tolerance: 1%; Wattage: 1/16W; Datasheet: Y:\MIS_DATABASE\DATASHEETS\RESISTORS\YAGEO-RC0402.PDF
RA16 = RESARR_ISO4: RES ARRAY 1K 31mW 5% 0402; Chkd/date: MAZHAR/291208; Crtd /date: USMAN/261108; Distributor_name: DIGIKEY; Distributor_part_number: Y7102CT-ND; Height: 0.45MM; Mfr_name: PANASONIC-ECG; Mfr_part_number: EXB-28V102JX; Mistral Part No: 110009030016-R; Package: 0402; Part_type: RESISTORS\ARRAY; Project: KHAN_MAIN; RoHS: RoHS; Tolerance: 5%; Wattage: 31mW; Datasheet: Y:\MIS_DATABASE\DATASHEETS\RESISTORS\EXB-2HV.PDF
TP124 TP125 TP128 TP153-TP155 = TESTPOINT: TESTPOINT 40 SMD; Chkd/date: MAZHAR/190505; Crtd /date: MAZHAR/190505; Distributor_name: NA; Distributor_part_number: NA; Height: NA; Mfr_name: LOCAL; Mistral Part No: 130009030933; Part_type: MISC\TESTPOINT; Project: RAINIER-3
U52 = MT41J128M8JP-125_FBGA78: IC 512Mb DDR SDRAM FBGA78; Chkd/date: NAVEED/241114; Crtd /date: VASANTHA/071014; Custom_Duty: 15%; Customs_HS_Code: 85423100; Distributor_name: NA; Distributor_part_number: NA; Height: 1.20MM; Mfr_name: MICRON; Mistral Part No: 141114100002-P; Package: FBGA78; Part_type: ICS\DIGITAL\MEMORY; Project: GALILEO_EVM; RoHS: Pb-Free; Temperature: -0°C+85°C; Tolerance: NA; Voltage: NA; Wattage: NA; Weight: NA; Datasheet: Y:\MIS_DATABASE\DATASHEETS\ICS\MEMORY\MT41K.PDF
C659 = CAP: CAP CERAMIC 1uF 10V 10% X5R 0402; Chkd/date: BALACHANDAR/160514; Crtd /date: SARANYA/060514; Custom_Duty: 15%; Customs_HS_Code: 85322990; Distributor_name: DIGIKEY; Distributor_part_number: 478-4596-1-ND; Height: 0.56MM; Mfr_name: AVX CORPORATION; Mfr_part_number: 0402ZD105KAT2A; Mistral Part No: 120014050010-R; Package: 0402; Part_type: CAPACITORS\CERAMIC; Project: AEGIS GP BETA2; RoHS: RoHS; Temperature: -55°C+85°C; Tolerance: 10%; Voltage: 10V; Wattage: NA; Weight: NA; Datasheet: Y:\MIS_DATABASE\DATASHEETS\CAPACITORS\AVX_MLC.PDF
R265 R267 R387 R388 R463 R673 R679 R680 R682 R685 R688 R691 R695 R700 R715 = RESISTOR: RES 0E 1/16W 1% 0402; Chkd/date: MAZHAR/220709; Crtd /date: USMAN/270109; Custom_Duty: 15%; Customs_HS_Code: 85332119; Distributor_name: NA; Distributor_part_number: NA; Height: 0.40MM; Mfr_name: YAGEO AMERICA; Mfr_part_number: RC0402FR-070RL; Mistral Part No: 110009030085-P; Package: 0402; Part_type: RESISTORS\FIXED; Project: OMAP_EVM; RoHS: Pb-Free; Tolerance: 1%; Wattage: 1/16W; Datasheet: Y:\MIS_DATABASE\DATASHEETS\RESISTORS\CRCW0603.PDF
R333 R344 = RESISTOR: RES 100K 1/16W 5% 0402; Chkd/date: JAGADEESWARAN.S/250414; Crtd /date: BAVISH/010611; Custom_Duty: 15%; Customs_HS_Code: 85332119; Distributor_name: DIGIKEY; Distributor_part_number: 541-100KJCT-ND; Height: 0.40MM; Mfr_name: VISHAY; Mfr_part_number: CRCW0402100KJNED; Mistral Part No: 110011060002-R; Package: 0402; Part_type: RESISTORS\FIXED; Project: AM4515_EVM_LCD; RoHS: RoHS; Temperature: -55°C+155°C; Tolerance: 5%; Voltage: NA; Wattage: 1/16W; Weight: 0.65mg; Datasheet: Y:\MIS_DATABASE\DATASHEETS\RESISTORS\CRCW0603.PDF
R339 R347 = RESISTOR: RES 1K 1/16W 5% 0402; Alternate_mfr_name_A: AVX CORPORATION; Alternate_mfr_name_C: YAGEO AMERICA; Alternate_mfr_part_number_A: CR05-102J-H; Alternate_mfr_part_number_C: RC0402JR-071KL; Chkd/date: SHREESHAIL/121205; Crtd /date: MAZHAR/230805; Custom_Duty: 15%; Customs_HS_Code: 85332119; Distributor_name: DIGIKEY; Distributor_name_A: NA; Distributor_name_C: DIGIKEY; Distributor_part_number: P1.0KJCT-ND; Distributor_part_number_A: NA; Distributor_part_number_C: 311-1.0KJRCT-ND; Height: 0.40MM; Mfr_name: PANASONIC-ECG; Mfr_part_number: ERJ-2GEJ102X; Mistral Part No: 110009030400-R; Package: 0402; Part_type: RESISTORS\FIXED; Project: HSE; RoHS: RoHS; Tolerance: 5%; Wattage: 1/16W; Datasheet: Y:\MIS_DATABASE\DATASHEETS\RESISTORS\ERJ12.PDF
R464 R676 R713 R714 = RESISTOR: RES 0E 1/16W 1% 0402; Chkd/date: MAZHAR/220709; Crtd /date: USMAN/270109; Custom_Duty: 15%; Customs_HS_Code: 85332119; Distributor_name: NA; Distributor_part_number: NA; Height: 0.40MM; Loading: DNI; Mfr_name: YAGEO AMERICA; Mfr_part_number: RC0402FR-070RL; Mistral Part No: 110009030085-P; Package: 0402; Part_type: RESISTORS\FIXED; Project: OMAP_EVM; RoHS: Pb-Free; Tolerance: 1%; Wattage: 1/16W; Datasheet: Y:\MIS_DATABASE\DATASHEETS\RESISTORS\CRCW0603.PDF
R258 R301 R518 = RESISTOR: RES 0E 1/10W 5% 0402; Chkd/date: NAVEED/241114; Crtd /date: NAVEED/201014; Custom_Duty: 15%; Customs_HS_Code: 85332119; Distributor_name: DIGIKEY; Distributor_part_number: P0.0JCT-ND; Height: 0.40MM; Mfr_name: PANASONIC-ECG; Mfr_part_number: ERJ-2GE0R00X; Mistral Part No: 110014100008-R; Package: 0402; Part_type: RESISTORS\FIXED; Project: AEGIS POM; RoHS: RoHS; Tolerance: 5%; Wattage: 1/10W; Datasheet: Y:\MIS_DATABASE\DATASHEETS\RESISTORS\ERJ12.PDF
R740 R877 = RESISTOR: RES 33E 1/16W 5% 0402; Alternate_mfr_name_A: AVX CORPORATION; Alternate_mfr_name_B: ROHM; Alternate_mfr_name_C: YAGEO AMERICA; Alternate_mfr_name_D: YAGEO AMERICA; Alternate_mfr_part_number_A: CR05-330J-H; Alternate_mfr_part_number_B: MCR01MZPJ330; Alternate_mfr_part_number_C: 9C04021A33R0JLHF3; Alternate_mfr_part_number_D: RC0402JR-0733RL; Chkd/date: SHREESHAIL/200406; Crtd /date: GEETHA/190406; Custom_Duty: 15%; Customs_HS_Code: 85332119; Distributor_name: DIGIKEY; Distributor_name_A: NA; Distributor_name_B: DIGIKEY; Distributor_name_C: DIGIKEY; Distributor_name_D: DIGIKEY; Distributor_part_number: P33JCT-ND; Distributor_part_number_A: NA; Distributor_part_number_B: RHM33JCT-ND; Distributor_part_number_C: 311-33JCT-ND; Distributor_part_number_D: 311-33JRCT-ND; Height: 0.40MM; Mfr_name: PANASONIC-ECG; Mfr_part_number: ERJ-2GEJ330X; Mistral Part No: 110009030699-R; Package: 0402; Part_type: RESISTORS\FIXED; Project: RED EYE; RoHS: RoHS; Tolerance: 5%; Wattage: 1/16W; Datasheet: Y:\MIS_DATABASE\DATASHEETS\RESISTORS\ERJ12.PDF
U38 = AT24HC04B-TH-B_TSSOP8: IC SERIAL EEPROM TSSOP8; Chkd/date: NAVEED/241114; Crtd /date: VASANTHA/230914; Custom_Duty: 15%; Customs_HS_Code: 85423100; Distributor_name: DIGIKEY; Distributor_part_number: AT24CM01-XHD-TCT-ND; Height: 1.20MM; Mfr_name: ATMEL; Mfr_part_number: AT24CM01-XHD-T; Mistral Part No: 141114090006-R; Package: TSSOP8; Part_type: ICS\DIGITAL\MEMORY; Project: GALILEO_EVM; RoHS: RoHS; Temperature: -40°C+85°C; Tolerance: NA; Voltage: NA; Wattage: NA; Weight: NA; Datasheet: Y:\MIS_DATABASE\DATASHEETS\ICS\MEMORY\AT24CM01.PDF
U40 = N25Q256A83ESF_SOP2-16: IC 128Mb NOR FLASH MEMORY SOP2-16; Chkd/date: NAVEED/060115; Crtd /date: VASANTHA/101214; Custom_Duty: 15%; Customs_HS_Code: 85423100; Distributor_name: DIGIKEY; Distributor_part_number: N25Q128A13ESF40F-ND; Height: 2.65MM; Mfr_name: MICRON; Mistral Part No: 141114120003-R; Package: SOP2-16; Part_type: ICS\DIGITAL\MEMORY; Project: GALILEO_EVM; RoHS: RoHS; Temperature: -40°C+85°C; Tolerance: NA; Voltage: NA; Wattage: NA; Weight: NA; Datasheet: Y:\MIS_DATABASE\DATASHEETS\ICS\MEMORY\N25Q128A13E.PDF
U36 U71 U127 = SN74LVC1G08DBVRE4_SOT23-5: IC SINGLE 2-INPUT POSITIVE AND GATE SOT23-5; Chkd/date: SUHAS/221010; Crtd /date: USMAN/151008; Custom_Duty: 15%; Customs_HS_Code: 85423100; Distributor_name: DIGIKEY; Distributor_part_number: SN74LVC1G08DBVRE4-ND; Height: 1.45MM; Mfr_name: TEXAS INSTRUMENTS; Mistral Part No: 141009060026-R; Part_type: ICS\DIGITAL\GATES; Project: KHAN_MAIN; RoHS: Sb/ Br FREE; Temperature: -40°C+85°C; Datasheet: Y:\MIS_DATABASE\DATASHEETS\ICS\DIGITAL\GATES\SN74LVC1G08.PDF
U72 = S25FL512SAGMFI011_SOIC16: IC 512MBIT EEPROM SOIC16; Chkd/date: NAVEED/241114; Crtd /date: VASANTHA/230914; Custom_Duty: 15%; Customs_HS_Code: 85423100; Distributor_name: DIGIKEY; Distributor_part_number: 1274-1006-ND; Height: 2.65MM; Mfr_name: SPANSION; Mistral Part No: 141114090005-R; Package: SOIC16; Part_type: ICS\DIGITAL\MEMORY; Project: GALILEO_EVM; RoHS: Pb-Free; Temperature: -40°C+85°C; Tolerance: NA; Voltage: NA; Wattage: NA; Weight: NA; Datasheet: Y:\MIS_DATABASE\DATASHEETS\ICS\MEMORY\S25FL512S.PDF
C105 C113 C146 = CAP: CAP CERAMIC 4.7uF 16V 10% X5R 0603; Chkd/date: VASANTHA/230714; Crtd /date: BAVISH/060511; Custom_Duty: 15%; Customs_HS_Code: 85322990; Distributor_name: DIGIKEY; Distributor_part_number: 587-2786-1-ND; Height: 0.90MM; Mfr_name: TAIYO YUDEN; Mfr_part_number: EMK107ABJ475KA-T; Mistral Part No: 120011050004-R; Package: 0603; Part_type: CAPACITORS\CERAMIC; Project: HMC; RoHS: RoHS; Temperature: -55°C+85°C; Tolerance: 10%; Voltage: 16V; Wattage: NA; Weight: NA; Datasheet: Y:\MIS_DATABASE\DATASHEETS\CAPACITORS\EMK107.PDF
C144 C145 = CAP: CAP CERAMIC 0.22uF 10V 10% X5R 0402; Chkd/date: MAZHAR/151208; Crtd /date: MAZHAR/170907; Custom_Duty: 15%; Customs_HS_Code: 85322990; Distributor_name: DIGIKEY; Distributor_part_number: 490-3910-1-ND; Height: 0.55MM; Mfr_name: MURATA; Mfr_part_number: GRM155R61A224KE19D; Mistral Part No: 120009030090; Package: 0402; Part_type: CAPACITORS\CERAMIC; Project: SMART VIEW_NVR; Tolerance: 10%; Voltage: 10V; Datasheet: Y:\MIS_DATABASE\DATASHEETS\CAPACITORS\GRM188SERIES.PDF
R678 R681 R687 = RESISTOR: RES 47E 1/16W 1% 0402; Alternate_mfr_name_A: AVX CORPORATION; Alternate_mfr_name_C: YAGEO AMERICA; Alternate_mfr_part_number_A: CR05-470F-H; Alternate_mfr_part_number_C: RC0402FR-0747RL; Chkd/date: SHREESHAIL/240507; Crtd /date: MAZHAR/180507; Custom_Duty: 15%; Customs_HS_Code: 85332119; Distributor_name: DIGIKEY; Distributor_name_A: NA; Distributor_name_C: DIGIKEY; Distributor_part_number: 541-47.0LCT-ND; Distributor_part_number_A: NA; Distributor_part_number_C: 311-47JRCT-ND; Height: 0.40MM; Mfr_name: VISHAY; Mfr_part_number: CRCW040247R0FKED; Mistral Part No: 110009030878; Package: 0402; Part_type: RESISTORS\FIXED; Project: MICODER-1; Tolerance: 1%; Wattage: 1/16W; Datasheet: Y:\MIS_DATABASE\DATASHEETS\RESISTORS\CRCW0603.PDF
R856 = RESISTOR: RES 0E 1/10W 5% 0402; Chkd/date: NAVEED/241114; Crtd /date: NAVEED/201014; Custom_Duty: 15%; Customs_HS_Code: 85332119; Distributor_name: DIGIKEY; Distributor_part_number: P0.0JCT-ND; Height: 0.40MM; Loading: DNI; Mfr_name: PANASONIC-ECG; Mfr_part_number: ERJ-2GE0R00X; Mistral Part No: 110014100008-R; Package: 0402; Part_type: RESISTORS\FIXED; Project: AEGIS POM; RoHS: RoHS; Tolerance: 5%; Wattage: 1/10W; Datasheet: Y:\MIS_DATABASE\DATASHEETS\RESISTORS\ERJ12.PDF
RA6 = RESARR_ISO4: RES ARRAY 0E 31mW 0402; Chkd/date: SUHAS/270910; Crtd /date: USMAN/190209; Custom_Duty: 15%; Distributor_name: DIGIKEY; Distributor_part_number: Y10000CT-ND; Height: 0.55MM; Mfr_name: PANASONIC-ECG; Mfr_part_number: EXB-N8VR000X; Mistral Part No: 110009030002-R; Package: 0402; Part_type: RESISTORS\ARRAY; Project: AXON; RoHS: RoHS; Temperature: -55°C+125°C; Voltage: 50V; Wattage: 31mW; Weight: 3g/1000pcs; Datasheet: Y:\MIS_DATABASE\DATASHEETS\RESISTORS\EXB-X.PDF
RA15 = RESARR_ISO4: RES ARRAY 0E 31mW 0402; Chkd/date: SUHAS/270910; Crtd /date: USMAN/190209; Custom_Duty: 15%; Distributor_name: DIGIKEY; Distributor_part_number: Y10000CT-ND; Height: 0.55MM; Loading: DNI; Mfr_name: PANASONIC-ECG; Mfr_part_number: EXB-N8VR000X; Mistral Part No: 110009030002-R; Package: 0402; Part_type: RESISTORS\ARRAY; Project: AXON; RoHS: RoHS; Temperature: -55°C+125°C; Voltage: 50V; Wattage: 31mW; Weight: 3g/1000pcs; Datasheet: Y:\MIS_DATABASE\DATASHEETS\RESISTORS\EXB-X.PDF
U29 = THGBM5G5A1JBAIR_VFBGA153: IC NAND FLASH EMMC 16GB FBGA153; Chkd/date: NAVEED/241114; Crtd /date: VASANTHA/071014; Custom_Duty: 15%; Customs_HS_Code: 85423100; Distributor_name: NA; Distributor_part_number: NA; Height: 1.00MM; Mfr_name: KINGSTON; Mistral Part No: 141114100001-R; Package: FBGA153; Part_type: ICS\DIGITAL\MEMORY; Project: GALILEO_EVM; RoHS: RoHS; Temperature: -25°C+85°C; Tolerance: NA; Voltage: NA; Wattage: NA; Weight: NA; Datasheet: Y:\MIS_DATABASE\DATASHEETS\ICS\MEMORY\EMMC.PDF
U34 = SN74AVC1T45DBVR_SOT23-6: IC SINGLE-BIT DUAL-SUPPLY BUS TRANSCEIVER SOT23-6; Chkd/date: MAZHAR/050208; Crtd /date: USMAN/050208; Custom_Duty: 15%; Customs_HS_Code: 85423100; Distributor_name: DIGIKEY; Distributor_part_number: 296-19094-1-ND; Height: 1.45MM; Mfr_name: TEXAS INSTRUMENTS; Mistral Part No: 141009030019-R; Part_type: ICS\DIGITAL\BUSTRANSCEIVER; Project: HS100RD; RoHS: RoHS; Datasheet: Y:\MIS_DATABASE\DATASHEETS\ICS\DIGITAL\BUSTRANSCEIVER\SN74AVC1T45.PDF
U1 = 66AK2G02_BGA625: IC ARM CORTEX AND DSP 32 BIT MICROPROCESSOR BGA625; Chkd/date: NAVEED/141114; Color: Default; Crtd /date: VASANTHA/081014; Custom_Duty: 15%; Customs_HS_Code: 85423100; Distributor_name: NA; Distributor_part_number: NA; Height: 1.70MM; Location X-Coordinate: 0; Location Y-Coordinate: 0; Mfr_name: TEXAS INSTRUMENTS; Mfr_part_number: 66AK2G02; Mistral Part No: 141014100003; Package: BGA625; Part_type: ICS\DIGITAL\MICROPROCESSOR; Power Pins Visible: False; Primitive: DEFAULT; Project: GALILEO_EVM; Tolerance: NA; Voltage: NA; Wattage: NA; Weight: NA; Datasheet: Y:\MIS_DATABASE\DATASHEETS\ICS\DIGITAL\MICROCONTROLLER\SG-BGA-6094.PDF    Y:\MIS_DATABASE\DATASHEETS\ICS\DIGITAL\MICROCONTROLLER\SG-BGA_FP.PDF

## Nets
DGND: C105.2 C113.2 C133.2 C144.2 C145.2 C146.2 C147.2 C159.2 C429.2 C430.2 C431.2 C432.2 C433.2 C434.2 C437.2 C438.2 C447.2 C454.2 C458.2 C470.2 C473.1 C480.2 C481.2 C482.2 C483.1 C492.2 C578.1 C579.2 C580.2 C581.2 C582.2 C583.2 C584.2 C589.2 C602.2 C603.2 C604.2 C605.2 C606.2 C607.2 C608.2 C610.1 C655.2 C656.2 C657.1 C659.1 C761.1 R315.2 R318.2 R347.1 R385.1 R386.1 R443.1 R701.2 R722.1 RA16.1 RA16.2 RA16.3 RA16.4 U29.C4(VSSQ1) U29.D4(NC33) U29.E7(VSS1) U29.G5(VSS2) U29.H10(VSS3) U29.K8(VSS4) U29.N1(NC89) U29.N2(VSSQ2) U29.N5(VSSQ3) U29.P4(VSSQ4) U29.P6(VSSQ5) U34.2(GND) U36.3(GND) U38.4(GND) U40.10(VSS) U52.A1(VSS) U52.A8(VSS) U52.B1(VSS) U52.B2(VSSQ) U52.B8(VSSQ) U52.C9(VSSQ) U52.D1(VSSQ) U52.D8(VSS) U52.D9(VSSQ) U52.F2(VSS) U52.F8(VSS) U52.J1(VSS) U52.J9(VSS) U52.L1(VSS) U52.L9(VSS) U52.N1(VSS) U52.N9(VSS) U71.3(GND) U72.10(VSS) U127.3(GND) ; also on sheet 1 11 12 13 14 15 19 20 21 22 23 24 25 26 27 28 29 30 31 32 33 34 35 36 37 38 39 40 41 42 43 44 45 46 47 48 49 50
VCC1V8_EMMC: C113.1 C133.1 C145.1 R258.2 R260.2 R268.2 R269.2 R271.2 R281.2 R286.2 R287.2 R292.2 R299.2 R304.2 R856.2 U29.C6(VCCQ1) U29.C7(NC22) U29.M4(VCCQ2) U29.N4(VCCQ3) U29.P3(VCCQ4) U29.P5(VCCQ5) U34.6(VCCB)
VCC3V3_DCIN: C147.1 C159.1 C761.2 R301.1 R321.1 R333.1 R339.2 R344.1 R518.1 R698.1 U38.8(VCC) U40.2(VCC) U127.5(VCC) ; also on sheet 11 19 20 21 22 23 24 25 26 27 28 29 30 31 32 33 34 35 36 37 38 43 44 45 46 47 48 50
VCC3V3_EMMC: C105.1 C144.1 C473.2 C483.2 R301.2 R694.1 U29.E6(VCC1) U29.F5(VCC2) U29.J10(VCC3) U29.K9(VCC4) U34.1(VCCA) U36.5(VCC)
VCC3V3_QSPI: C655.1 C656.1 C657.2 C659.2 R518.2 R743.1 R745.1 R746.1 U71.5(VCC) U72.2(VCC) U72.14(VIO/RFU)
VCC_DDR_VREF: C578.2 C610.2 U52.E1(VREFDQ) U52.J8(VREFCA) ; also on sheet 14 15 50
VDDI: C146.1 C492.1 U29.C1(NC19) U29.C2(VDDI)
VDDR_VTT: C429.1 C430.1 C431.1 C432.1 C433.1 C434.1 C437.1 C438.1 C447.1 C454.1 C458.1 C470.1 C480.1 C481.1 C482.1 R206.2 R207.2 R208.2 R209.2 R210.2 R211.2 R212.2 R213.2 R214.2 R215.2 R230.2 R233.2 R237.2 R241.2 R247.2 R256.2 R261.2 R279.2 R285.2 R295.2 R305.2 R306.2 R307.2 R308.2 R309.2 ; also on sheet 50
BUF_MMC1_CLK: R713.1 ; also on sheet 24
BUF_MMC1_CMD: R714.1 ; also on sheet 24
BUF_MMC1_DAT0: RA15.8 ; also on sheet 24
BUF_MMC1_DAT1: RA15.7 ; also on sheet 24
BUF_MMC1_DAT2: RA15.6 ; also on sheet 24
BUF_MMC1_DAT3: RA15.5 ; also on sheet 24
DAT0: R688.1 U29.A3(DAT0)
DAT1: R682.1 U29.A4(DAT1)
DAT2: R679.1 U29.A5(DAT2)
DAT3: R695.1 U29.B1(NC10) U29.B2(DAT3)
DAT4: R691.1 U29.A2(NC2) U29.B3(DAT4)
DAT5: R685.1 U29.B4(DAT5) U29.C3(NC20) U29.D1(NC30) U29.D2(NC31)
DAT6: R680.1 U29.B5(DAT6) U29.C5(NC21)
DAT7: R673.1 U29.A9(NC4) U29.B6(DAT7) U29.B7(NC11) U29.B8(NC12) U29.B9(NC13)
DDR_A0: R279.1 U1.AC15(DDR3_A00) U52.K3(A0) ; also on sheet 15
DDR_A1: R295.1 U1.Y15(DDR3_A01) U52.L7(A1) ; also on sheet 15
DDR_A2: R285.1 U1.AC16(DDR3_A02) U52.L3(A2) ; also on sheet 15
DDR_A3: R256.1 U1.AA15(DDR3_A03) U52.K2(A3) ; also on sheet 15
DDR_A4: R261.1 U1.AB16(DDR3_A04) U52.L8(A4) ; also on sheet 15
DDR_A5: R230.1 U1.AE17(DDR3_A05) U52.L2(A5) ; also on sheet 15
DDR_A6: R233.1 U1.AC14(DDR3_A06) U52.M8(A6) ; also on sheet 15
DDR_A7: R237.1 U1.AB15(DDR3_A07) U52.M2(A7) ; also on sheet 15
DDR_A8: R247.1 U1.AC17(DDR3_A08) U52.N8(A8) ; also on sheet 15
DDR_A9: R241.1 U1.AB17(DDR3_A09) U52.M3(A9) ; also on sheet 15
DDR_A10: R306.1 U1.AB14(DDR3_A10) U52.H7(A10/AP) ; also on sheet 15
DDR_A11: R305.1 U1.AA16(DDR3_A11) U52.M7(A11) ; also on sheet 15
DDR_A12: R307.1 U1.AA17(DDR3_A12) U52.K7(A12/BC#) ; also on sheet 15
DDR_A13: R309.1 U1.AA12(DDR3_A13) U52.N3(A13) ; also on sheet 15
DDR_A14: R308.1 U1.Y17(DDR3_A14) U52.N7(A14) ; also on sheet 15
DDR_A15: R213.1 U1.Y16(DDR3_A15) U52.J7(A15) ; also on sheet 15
DDR_BA0: R212.1 U1.AA14(DDR3_BA0) U52.J2(BA0) ; also on sheet 15
DDR_BA1: R214.1 U1.AB13(DDR3_BA1) U52.K8(BA1) ; also on sheet 15
DDR_BA2: R211.1 U1.AD17(DDR3_BA2) U52.J3(BA2) ; also on sheet 15
DDR_CAS#: R207.1 U1.AC13(DDR3_CASn) U52.G3(CAS#) ; also on sheet 15
DDR_CB00: U1.AA11(DDR3_CB00) U52.B3(DQ0)
DDR_CB01: U1.AB11(DDR3_CB01) U52.C7(DQ1)
DDR_CB02: U1.AC11(DDR3_CB02) U52.C2(DQ2)
DDR_CB03: U1.AC12(DDR3_CB03) U52.C8(DQ3)
DDR_CBDQM: U1.Y11(DDR3_CBDQM) U52.B7(DM/TDQS)
DDR_CBDQS: U1.AE12(DDR3_CBDQS_P) U52.C3(DQS)
DDR_CBDQS#: U1.AD12(DDR3_CBDQS_N) U52.D3(DQS#)
DDR_CE1Z: TP155.1(TP) U1.AB12(DDR3_CEn1)
DDR_CK: R216.1 U1.AE15(DDR3_CLKOUT_P0) U52.F7(CK) ; also on sheet 15
DDR_CK#: R217.1 U1.AD15(DDR3_CLKOUT_N0) U52.G7(CK#) ; also on sheet 15
DDR_CKE: R210.1 U1.AB18(DDR3_CKE0) U52.G9(CKE) ; also on sheet 15
DDR_CKE1: TP154.1(TP) U1.AC18(DDR3_CKE1)
DDR_CLKN_LVDS_100MHz: U1.AD24(DDR_CLK_N) ; also on sheet 36
DDR_CLKP_LVDS_100MHz: U1.AE24(DDR_CLK_P) ; also on sheet 36
DDR_CS#: R209.1 U1.AD13(DDR3_CEn0) U52.H2(CS#) ; also on sheet 15
DDR_DM0: U1.AB4(DDR3_DQM0) ; also on sheet 15
DDR_DM1: U1.AA5(DDR3_DQM1) ; also on sheet 15
DDR_DM2: U1.AC8(DDR3_DQM2) ; also on sheet 15
DDR_DM3: U1.AA9(DDR3_DQM3) ; also on sheet 15
DDR_DQ0: U1.AD2(DDR3_D00) ; also on sheet 15
DDR_DQ1: U1.AA4(DDR3_D05) ; also on sheet 15
DDR_DQ2: U1.Y4(DDR3_D01) ; also on sheet 15
DDR_DQ3: U1.AD3(DDR3_D06) ; also on sheet 15
DDR_DQ4: U1.AC3(DDR3_D02) ; also on sheet 15
DDR_DQ5: U1.AE3(DDR3_D04) ; also on sheet 15
DDR_DQ6: U1.AB3(DDR3_D07) ; also on sheet 15
DDR_DQ7: U1.AC2(DDR3_D03) ; also on sheet 15
DDR_DQ8: U1.Y5(DDR3_D13) ; also on sheet 15
DDR_DQ9: U1.AC5(DDR3_D11) ; also on sheet 15
DDR_DQ10: U1.AA6(DDR3_D08) ; also on sheet 15
DDR_DQ11: U1.AB5(DDR3_D15) ; also on sheet 15
DDR_DQ12: U1.Y7(DDR3_D09) ; also on sheet 15
DDR_DQ13: U1.AB6(DDR3_D12) ; also on sheet 15
DDR_DQ14: U1.Y6(DDR3_D10) ; also on sheet 15
DDR_DQ15: U1.AC4(DDR3_D14) ; also on sheet 15
DDR_DQ16: U1.AC6(DDR3_D21) ; also on sheet 15
DDR_DQ17: U1.AA8(DDR3_D20) ; also on sheet 15
DDR_DQ18: U1.AA7(DDR3_D19) ; also on sheet 15
DDR_DQ19: U1.AD7(DDR3_D23) ; also on sheet 15
DDR_DQ20: U1.AC7(DDR3_D18) ; also on sheet 15
DDR_DQ21: U1.AE7(DDR3_D22) ; also on sheet 15
DDR_DQ22: U1.AB8(DDR3_D17) ; also on sheet 15
DDR_DQ23: U1.AB7(DDR3_D16) ; also on sheet 15
DDR_DQ24: U1.Y8(DDR3_D31) ; also on sheet 15
DDR_DQ25: U1.AE10(DDR3_D25) ; also on sheet 15
DDR_DQ26: U1.AD10(DDR3_D26) ; also on sheet 15
DDR_DQ27: U1.AC10(DDR3_D27) ; also on sheet 15
DDR_DQ28: U1.AB9(DDR3_D30) ; also on sheet 15
DDR_DQ29: U1.AB10(DDR3_D29) ; also on sheet 15
DDR_DQ30: U1.AA10(DDR3_D24) ; also on sheet 15
DDR_DQ31: U1.AC9(DDR3_D28) ; also on sheet 15
DDR_DQS0: U1.AD1(DDR3_DQS0_P) ; also on sheet 15
DDR_DQS0#: U1.AE2(DDR3_DQS0_N) ; also on sheet 15
DDR_DQS1: U1.AD4(DDR3_DQS1_P) ; also on sheet 15
DDR_DQS1#: U1.AE4(DDR3_DQS1_N) ; also on sheet 15
DDR_DQS2: U1.AE6(DDR3_DQS2_P) ; also on sheet 15
DDR_DQS2#: U1.AD6(DDR3_DQS2_N) ; also on sheet 15
DDR_DQS3: U1.AE9(DDR3_DQS3_P) ; also on sheet 15
DDR_DQS3#: U1.AD9(DDR3_DQS3_N) ; also on sheet 15
DDR_ODT: R215.1 U1.AA13(DDR3_ODT0) U52.G1(ODT) ; also on sheet 15
DDR_ODT1: TP153.1(TP) U1.Y12(DDR3_ODT1)
DDR_RAS#: R208.1 U1.AE13(DDR3_RASn) U52.F3(RAS#) ; also on sheet 15
DDR_RESET#: R443.2 R723.1 U1.Y18(DDR3_RESETn) U52.N2(RESET#) ; also on sheet 15
DDR_WE#: R206.1 U1.Y13(DDR3_WEn) U52.H3(WE#) ; also on sheet 15
EEPROM_A1: R315.1 R698.2 U38.2(A1)
EEPROM_A2: R321.2 R701.1 U38.3(A2)
EEPROM_WP: R318.1 U38.7(WP) ; also on sheet 47
EMMC_RSTn: U36.1(A) ; also on sheet 47
EMMC_RSTn_AND: U34.3(A) U36.4(Y)
FLASH_HOLD: R339.1 U40.1(HOLD#/DQ3) ; also on sheet 12
FLASH_RESET#: U127.1(A) ; also on sheet 47
FLASH_RSTn_AND: U40.3(RESET#/DNU2) U127.4(Y)
FLASH_WPn: R344.2 U40.9(W#/VPP/DQ2) ; also on sheet 47
LDO1_1V8: R258.1 ; also on sheet 13 23 24 30 36 48
LDO3_1V8: R856.1 ; also on sheet 36 48
PMIC_VDD2: C428.2 C579.1 C580.1 C581.1 C582.1 C583.1 C584.1 C589.1 C602.1 C603.1 C604.1 C605.1 C606.1 C607.1 C608.1 R723.2 U52.A2(VDD) U52.A9(VDD) U52.B9(VDDQ) U52.C1(VDDQ) U52.D7(VDD) U52.E2(VDDQ) U52.E9(VDDQ) U52.G2(VDD) U52.G8(VDD) U52.K1(VDD) U52.K9(VDD) U52.M1(VDD) U52.M9(VDD) ; also on sheet 15 48 50
QSPI_RSTn: U71.1(A) ; also on sheet 47
QSPI_RSTn_AND: U71.4(Y) U72.3(RESET#/RFU)
SOC_I2C0_SCL: R700.2 ; also on sheet 26 34 35 45
SOC_I2C0_SDA: R265.2 ; also on sheet 26 34 35 45
SOC_MMC1_CLK: R388.2 R713.2 U1.J4(MMC1_CLK/GPIO0_67)
SOC_MMC1_CLK_R: R388.1 R681.1
SOC_MMC1_CMD: R387.2 R714.2 U1.J2(MMC1_CMD/GPIO0_68)
SOC_MMC1_CMD_R: R287.1 R387.1 R687.1
SOC_MMC1_DAT0: RA6.1 RA15.1 U1.H3(MMC1_DAT0/GPIO0_66)
SOC_MMC1_DAT0_R: R292.1 R688.2 RA6.8
SOC_MMC1_DAT1: RA6.2 RA15.2 U1.F5(MMC1_DAT1/GPIO0_65)
SOC_MMC1_DAT1_R: R281.1 R682.2 RA6.7
SOC_MMC1_DAT2: RA6.3 RA15.3 U1.J5(MMC1_DAT2/GPIO0_64)
SOC_MMC1_DAT2_R: R269.1 R679.2 RA6.6
SOC_MMC1_DAT3: RA6.4 RA15.4 U1.H4(MMC1_DAT3/GPIO0_63)
SOC_MMC1_DAT3_R: R304.1 R695.2 RA6.5
SOC_MMC1_DAT4: R299.1 R691.2 U1.E3(MMC1_DAT4/GPIO0_62)
SOC_MMC1_DAT5: R286.1 R685.2 U1.G4(MMC1_DAT5/GPIO0_61)
SOC_MMC1_DAT6: R271.1 R680.2 U1.F4(MMC1_DAT6/GPIO0_60)
SOC_MMC1_DAT7: R260.1 R673.2 U1.G5(MMC1_DAT7/GPIO0_59)
SOC_MMC1_SDWP: R676.1 U1.K3(MMC1_SDWP/GPIO0_70)
SOC_QSPI_CLK: R463.2 U1.K25(QSPI_CLK/GPIO1_58)
SOC_QSPI_CLK_R: R463.1 R740.1 R877.2
SOC_QSPI_CSN0: R745.2 U1.J25(QSPI_CSn0/GPIO1_64) U72.7(CS#)
SOC_QSPI_D0: U1.J23(QSPI_D0/GPIO1_60) U72.15(SI/IO0)
SOC_QSPI_D1: U1.J22(QSPI_D1/GPIO1_61) U72.8(SO/IO1)
SOC_QSPI_D2: R746.2 U1.J21(QSPI_D2/GPIO1_62) U72.9(WP#/IO2)
SOC_QSPI_D3: R743.2 U1.J24(QSPI_D3/GPIO1_63) U72.1(HOLD#/IO3)
SOC_QSPI_RTCLK: R740.2 U1.K24(QSPI_RCLK/GPIO1_59)
SOC_RESETSTATz: U36.2(B) U71.2(B) U127.2(B) ; also on sheet 11 21 22 23 25 26 31 33 45 46
SOC_SPI1_CLK: R715.2 U1.N2(SPI1_CLK)
SOC_SPI1_CLK_R: R715.1 U40.16(C)
SOC_SPI1_MISO: U1.N1(SPI1_SOMI) U40.8(DQ1)
SOC_SPI1_MOSI: U1.P2(SPI1_SIMO) U40.15(DQ0)
SOC_SPI1_SCS0: R333.2 U1.P1(SPI1_SCSn0) U40.7(S#)
TRANS_EMMC_RSTn: R267.1 U34.4(B)
WLAN_SLOW_CLK: R464.1 ; also on sheet 30 49
N17944399: R347.2 TP125.1(TP) U1.J3(MMC1_SDCD/GPIO0_69)
N17944408: TP124.1(TP) U1.K2(MMC1_POW/GPIO0_71)
N18124845: R694.2 U34.5(DIR)
N19442104: R464.2 U1.H23(QSPI_CSn1/CLKOUT/GPIO1_65)
N19442180: R877.1 U72.16(SCK)
N19520807: R722.2 U52.H8(ZQ)
N19521112: TP128.1(TP) U52.A7(NF/TDQS#)
N19521127: RA16.7 U52.E8(NF/DQ5)
N19521129: RA16.6 U52.D2(NF/DQ6)
N19521147: RA16.8 U52.E3(NF/DQ4)
N19521183: RA16.5 U52.E7(NF/DQ7)
N19525941: C428.1 R216.2 R217.2
N19536013: R385.2 U1.W12(DDR3_RZQ0)
N19536015: R386.2 U1.V9(DDR3_RZQ1)
N21103450: R265.1 U38.5(SDA)
N21103457: R700.1 U38.6(SCL)
N26217961: R681.2 U29.M6(CLK)
N26217993: R687.2 U29.M5(CMD)
N26218848: R267.2 R268.1 R676.2 R678.1
N26218884: R678.2 U29.K5(RST_n)

Not connected (* = marked no-connect by the designer): U1 AD16(DDR3_CLKOUT_N1) AE16(DDR3_CLKOUT_P1); U29 A1(NC1)* A6(RFU1)* A7(RFU2)* A8(NC3)* A10(NC5)* A11(NC6)* A12(NC7)* A13(NC8)* A14(NC9)* B10(NC14)* B11(NC15)* B12(NC16)* B13(NC17)* B14(NC18)* C8(NC23)* C9(NC24)* C10(NC25)* C11(NC26)* C12(NC27)* C13(NC28)* C14(NC29)* D3(NC32)* D12(NC34)* D13(NC35)* D14(NC36)* E1(NC37)* E2(NC38)* E3(NC39)* E5(RFU4)* E8(RFU5)* E9(RFU6)* E10(RFU7)* E12(NC40)* E13(NC41)* E14(NC42)* F1(NC43)* F2(NC44)* F3(NC45)* F10(RFU8)* F12(NC46)* F13(NC47)* F14(NC48)* G1(NC49)* G2(NC50)* G3(RFU9)* G10(RFU10)* G12(NC51)* G13(NC52)* G14(NC53)* H1(NC54)* H2(NC55)* H3(NC56)* H5(RFU11)* H12(NC57)* H13(NC58)* H14(NC59)* J1(NC60)* J2(NC61)* J3(NC62)* J5(RFU12)* J12(NC63)* J13(NC64)* J14(NC65)* K1(NC66)* K2(NC67)* K3(NC68)* K6(RFU13)* K7(RFU14)* K10(RFU15)* K12(NC69)* K13(NC70)* K14(NC71)* L1(NC72)* L2(NC73)* L3(NC74)* L12(NC75)* L13(NC76)* L14(NC77)* M1(NC78)* M2(NC79)* M3(NC80)* M7(NC81)* M8(NC82)* M9(NC83)* M10(NC84)* M11(NC85)* M12(NC86)* M13(NC87)* M14(NC88)* N3(NC90)* N6(NC91)* N7(NC92)* N8(NC93)* N9(NC94)* N10(NC95)* N11(NC96)* N12(NC97)* N13(NC98)* N14(NC99)* P1(NC100)* P2(NC101)* P7(RFU16)* P8(NC102)* P9(NC103)* P10(RFU17)* P11(NC104)* P12(NC105)* P13(NC106)* P14(NC107)*; U38 1(NC)*; U40 4(DNU_1)* 5(DNU_2)* 6(DNU_3)* 11(DNU_4)* 12(DNU_5)* 13(DNU_6)* 14(DNU_7)*; U52 A3(NC1)* F1(NC2)* F9(NC3)* H1(NC4)* H9(NC5)*; U72 4(DNU1)* 5(DNU2)* 6(RFU)* 11(DNU3)* 12(DNU4)* 13(NC)*

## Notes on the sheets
sheet 16
- SoC DDR INTERFACE
- DDR TERMINATION
- ECC DEVICE
sheet 17
- QSPI
- NOTE: Resistor R740 R877 should be placed
  near the QSPI device
- I2C EEPROM FLASH
- SPI NORFLASH
- I2C ADDRESS:  0x50 (PAGE 0), 0x51 (PAGE 1)
sheet 18
- eMMC FLASH
- NOTE: MMC1 IS BY DEFAULT CONNECTED TO EMMC. IF COM8 TO BE USED RESISTOR RA6, R387 , R388 & R822
  SHOULD BE DNI AND RA15, R713, R714 & R393 SHOULD BE MOUNTED
- eMMC RESET
- Note:  NC pins are connected to eMMC Signals for routing
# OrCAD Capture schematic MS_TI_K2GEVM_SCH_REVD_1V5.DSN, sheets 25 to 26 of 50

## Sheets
25 24. ETHERNET PHY: size C; title: ETHERNET PHY
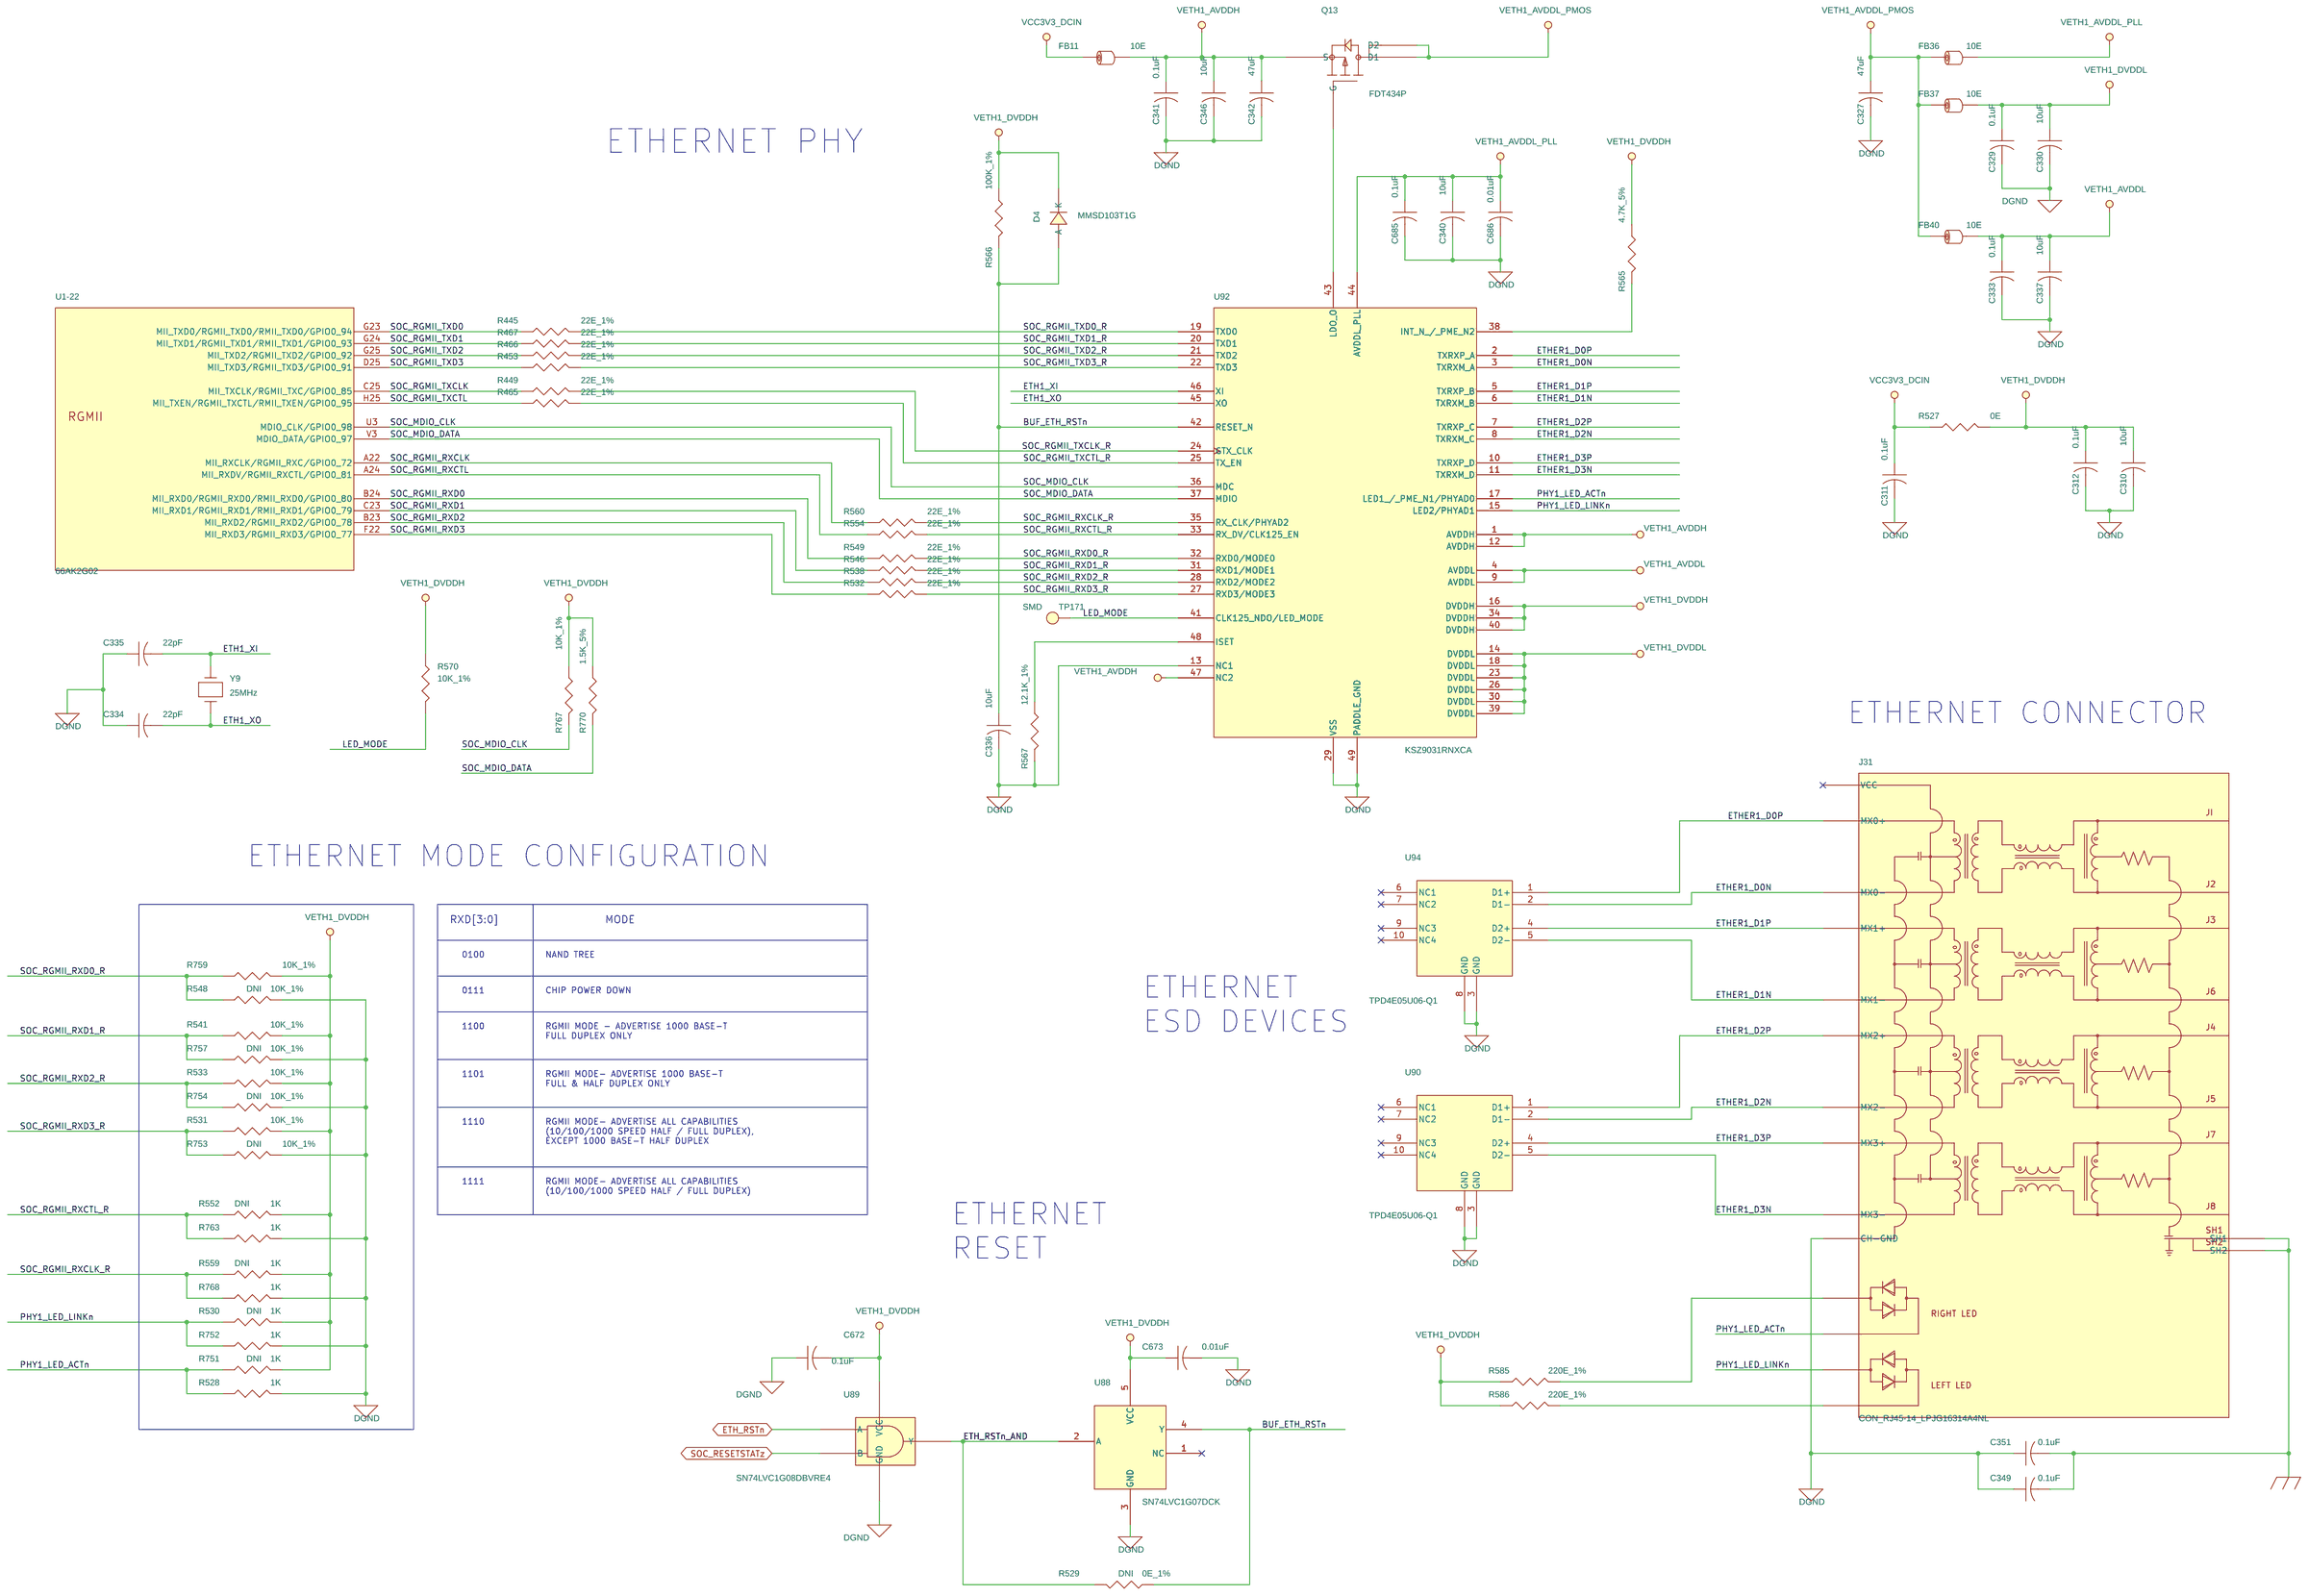
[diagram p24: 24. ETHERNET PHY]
26 25. PCIE x1  CONNECTOR: size C; title: PCIe x1 CONNECTOR

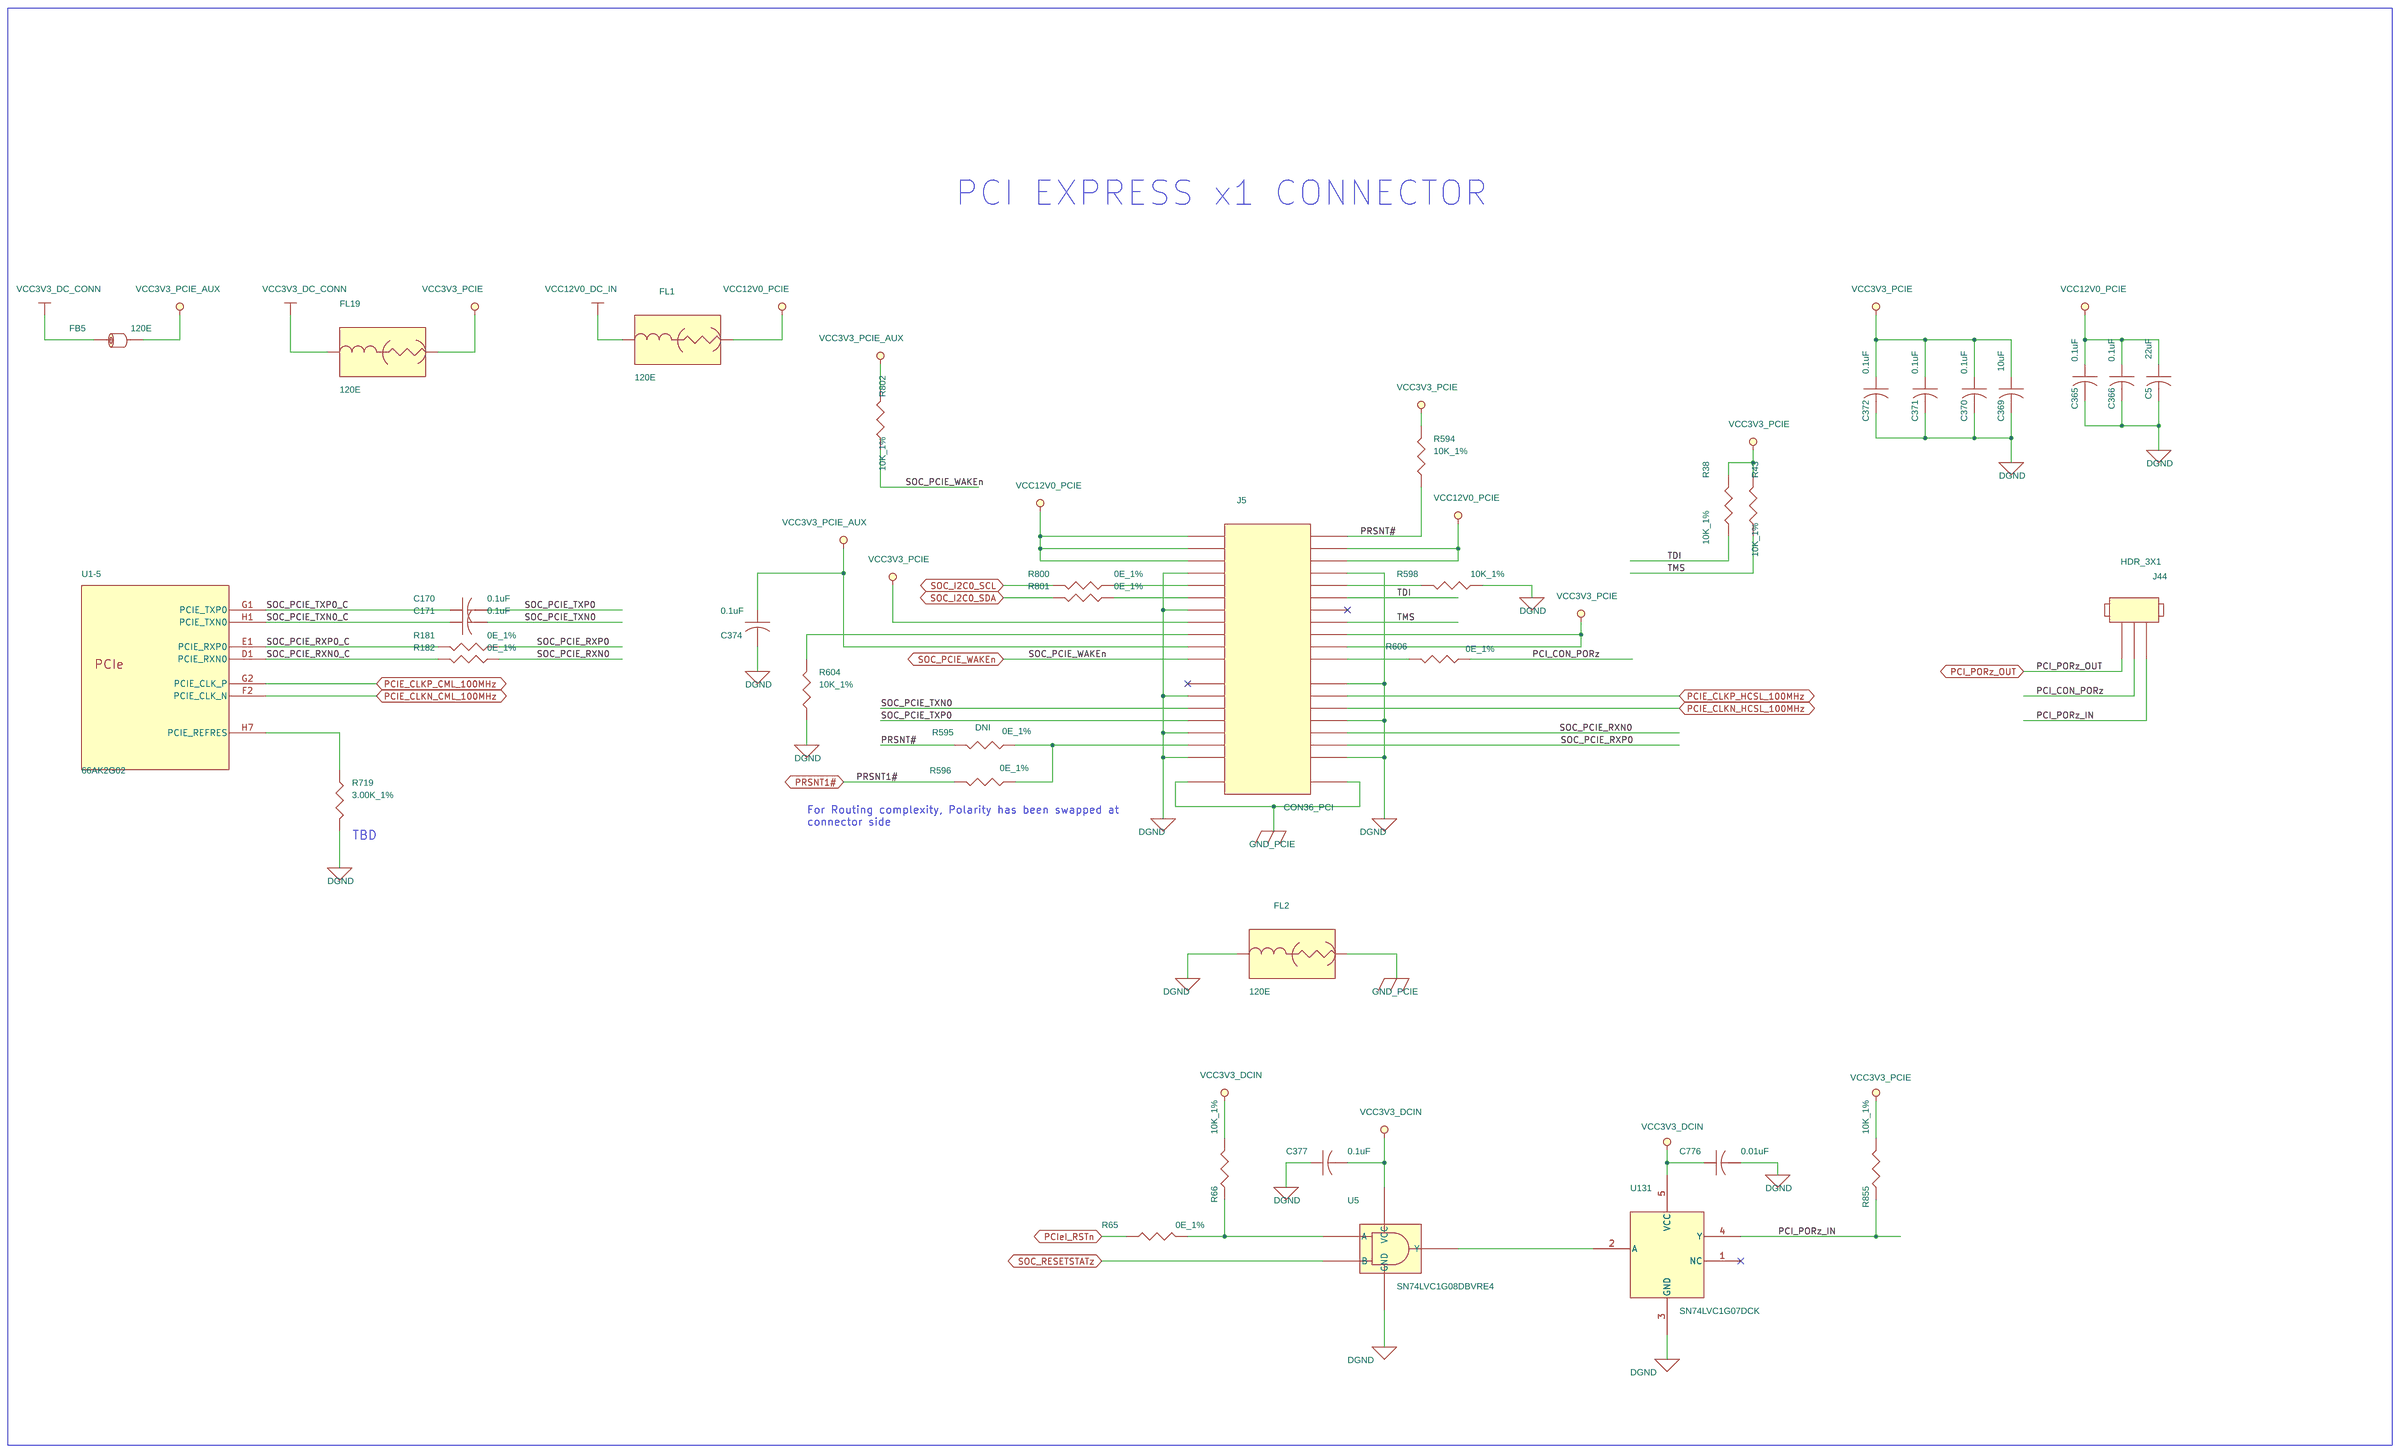
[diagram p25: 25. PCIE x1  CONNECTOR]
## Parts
sheet 18. NAND FLASH & MICRO SD CARD
U1  66AK2G02_BGA625  [BGASKT625_31-49_1270x1270]  (sections -1,-10,-11,-12,-13,-14,-15,-16,-17,-18,-19,-2,-20,-21,-22,-23,-24,-25,-26,-27,-28,-29,-3,-30,-31,-32,-33,-34,-35,-36,-37,-38,-4,-5,-6,-7,-8,-9)
sheet 24. ETHERNET PHY
C310  10uF  [CAP0805]
C311  0.1uF  [CAP0402]
C312  0.1uF  [CAP0402]
C327  47uF  [CAP1206]
C329  0.1uF  [CAP0402]
C330  10uF  [CAP0805]
C333  0.1uF  [CAP0402]
C334  22pF  [CAP0402]
C335  22pF  [CAP0402]
C336  10uF  [CAP0805]
C337  10uF  [CAP0805]
C340  10uF  [CAP0805]
C341  0.1uF  [CAP0402]
C342  47uF  [CAP1206]
C346  10uF  [CAP0805]
C349  0.1uF  [CAP0402]
C351  0.1uF  [CAP0402]
C672  0.1uF  [CAP0402]
C673  0.01uF  [CAP0402]
C685  0.1uF  [CAP0402]
C686  0.01uF  [CAP0402]
D4  MMSD103T1G  [DIO_SOD123]
FB11  10E  [IND_201209_90X60_SMD]
FB36  10E  [IND_201209_90X60_SMD]
FB37  10E  [IND_201209_90X60_SMD]
FB40  10E  [IND_201209_90X60_SMD]
J31  CON_RJ45-14_LPJG16314A4NL  [CON_RJ45-14_LPJG16314A4NL_S_R_T]
Q13  FDT434P  [SOT223-3]
R445  22E_1%  [RES0402]
R449  22E_1%  [RES0402]
R453  22E_1%  [RES0402]
R465  22E_1%  [RES0402]
R466  22E_1%  [RES0402]
R467  22E_1%  [RES0402]
R527  0E  [RES0402]
R528  1K  [RES0402]
R529  0E_1%  [RES0402]
R530  1K  [RES0402]
R531  10K_1%  [RES0402]
R532  22E_1%  [RES0402]
R533  10K_1%  [RES0402]
R538  22E_1%  [RES0402]
R541  10K_1%  [RES0402]
R546  22E_1%  [RES0402]
R548  10K_1%  [RES0402]
R549  22E_1%  [RES0402]
R552  1K  [RES0402]
R554  22E_1%  [RES0402]
R559  1K  [RES0402]
R560  22E_1%  [RES0402]
R565  4.7K_5%  [RES0402]
R566  100K_1%  [RES0402]
R567  12.1K_1%  [RES0603]
R570  10K_1%  [RES0402]
R585  220E_1%  [RES0402]
R586  220E_1%  [RES0402]
R751  1K  [RES0402]
R752  1K  [RES0402]
R753  10K_1%  [RES0402]
R754  10K_1%  [RES0402]
R757  10K_1%  [RES0402]
R759  10K_1%  [RES0402]
R763  1K  [RES0402]
R767  10K_1%  [RES0402]
R768  1K  [RES0402]
R770  1.5K_5%  [RES0402]
TP171  SMD  [TP20_SMD]
U88  SN74LVC1G07DCK  [SC70-5]
U89  SN74LVC1G08DBVRE4  [SOT23-5]
U90  TPD4E05U06-Q1  [USON10_19-68_40X100]
U92  KSZ9031RNXCA  [QFN48_19-68_280X280]
U94  TPD4E05U06-Q1  [USON10_19-68_40X100]
Y9  25MHz  [XTAL_ABM3_205X130_SMD]
sheet 25. PCIE x1  CONNECTOR
C5  22uF  [CAP1210]
C170  0.1uF  [CAP0402]
C171  0.1uF  [CAP0402]
C365  0.1uF  [CAP0402]
C366  0.1uF  [CAP0402]
C369  10uF  [CAP0805]
C370  0.1uF  [CAP0402]
C371  0.1uF  [CAP0402]
C372  0.1uF  [CAP0402]
C374  0.1uF  [CAP0402]
C377  0.1uF  [CAP0402]
C776  0.01uF  [CAP0402]
FB5  120E  [IND0402]
FL1  120E  [EMIFIL_BLM18R_0603]
FL2  120E  [EMIFIL_BLM18R_0603]
FL19  120E  [EMIFIL_BLM18K_0603]
J5  CON36_PCI  [CON_PCI_18X2_10061913_S_S_S]
J44  HDR_3X1  [HDR_3X1_100_S_T]
R38  10K_1%  [RES0402]
R43  10K_1%  [RES0402]
R65  0E_1%  [RES0402]
R66  10K_1%  [RES0402]
R181  0E_1%  [RES0402]
R182  0E_1%  [RES0402]
R594  10K_1%  [RES0402]
R595  0E_1%  [RES0402]
R596  0E_1%  [RES0402]
R598  10K_1%  [RES0402]
R604  10K_1%  [RES0402]
R606  0E_1%  [RES0402]
R719  3.00K_1%  [RES0201]
R800  0E_1%  [RES0402]
R801  0E_1%  [RES0402]
R802  10K_1%  [RES0402]
R855  10K_1%  [RES0402]
U5  SN74LVC1G08DBVRE4  [SOT23-5]
U131  SN74LVC1G07DCK  [SC70-5]

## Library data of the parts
U1 = 66AK2G02_BGA625: IC ARM CORTEX AND DSP 32 BIT MICROPROCESSOR BGA625; Chkd/date: NAVEED/141114; Color: Default; Crtd /date: VASANTHA/081014; Custom_Duty: 15%; Customs_HS_Code: 85423100; Distributor_name: NA; Distributor_part_number: NA; Height: 1.70MM; Location X-Coordinate: 0; Location Y-Coordinate: 0; Mfr_name: TEXAS INSTRUMENTS; Mfr_part_number: 66AK2G02; Mistral Part No: 141014100003; Package: BGA625; Part_type: ICS\DIGITAL\MICROPROCESSOR; Power Pins Visible: False; Primitive: DEFAULT; Project: GALILEO_EVM; Tolerance: NA; Voltage: NA; Wattage: NA; Weight: NA; Datasheet: Y:\MIS_DATABASE\DATASHEETS\ICS\DIGITAL\MICROCONTROLLER\SG-BGA-6094.PDF    Y:\MIS_DATABASE\DATASHEETS\ICS\DIGITAL\MICROCONTROLLER\SG-BGA_FP.PDF
C310 C330 C336 C337 C340 C346 C369 = CAP: CAP CERAMIC 10uF 16V 10% X5R 0805; Alternate_mfr_name_A: TAIYO YUDEN; Alternate_mfr_part_number_A: EMK212BJ106KG-T; Chkd/date: RAVI/020511; Crtd /date: BAVISH/290411; Custom_Duty: 15%; Customs_HS_Code: 85322990; Distributor_name: DIGIKEY; Distributor_name_A: DIGIKEY; Distributor_part_number: 478-5165-1-ND; Distributor_part_number_A: 587-1295-1-ND; Height: 1.40MM; Mfr_name: AVX CORPORATION; Mfr_part_number: 0805YD106KAT2A; Mistral Part No: 120011040011-R; Package: 0805; Part_type: CAPACITORS\CERAMIC; Project: AOD_POD-RF; RoHS: RoHS; Temperature: -55°C+85°C; Tolerance: 10%; Voltage: 16V; Wattage: NA; Weight: NA; Datasheet: Y:\MIS_DATABASE\DATASHEETS\CAPACITORS\AVX_CERAMIC.PDF
C170 C171 C311 C312 C329 C333 C341 C349 C351 C370-C372 C374 C377 C672 C685 = CAP: CAP CERAMIC 0.1uF 16V 10% X7R 0402; Alternate_mfr_name_A: KEMET; Alternate_mfr_part_number_A: C0402C104K4RACT; Chkd/date: MAZHAR/281108; Crtd /date: MAZHAR/030907; Custom_Duty: 15%; Customs_HS_Code: 85322990; Distributor_name: DIGIKEY; Distributor_name_A: DIGIKEY; Distributor_part_number: 490-3261-1-ND; Distributor_part_number_A: 399-3521-1-ND; Height: 0.55MM; Mfr_name: MURATA; Mfr_part_number: GRM155R71C104KA88D; Mistral Part No: 120009030060-R; Package: 0402; Part_type: CAPACITORS\CERAMIC; Project: SMART VIEW_IP CAMERA; Tolerance: 10%; Voltage: 16V; Datasheet: Y:\MIS_DATABASE\DATASHEETS\CAPACITORS\GRM188SERIES.PDF
C327 C342 = CAP: CAP CERAMIC 47uF 16V 20% X5R 1206; Chkd/date: JAGADEESWARAN.S/250414; Crtd /date: BAVISH/010611; Custom_Duty: 15%; Customs_HS_Code: 85322990; Distributor_name: DIGIKEY; Distributor_part_number: 445-6003-1-ND; Height: 1.80MM; Mfr_name: TDK CORPORATION; Mfr_part_number: C3216X5R1C476M; Mistral Part No: 120011060001-R; Package: 1206; Part_type: CAPACITORS\CERAMIC; Project: TE_MODULE; RoHS: RoHS; Temperature: -55°C+85°C; Tolerance: 20%; Voltage: 16V; Wattage: NA; Weight: NA; Datasheet: Y:\MIS_DATABASE\DATASHEETS\CAPACITORS\TDK-C3216.PDF
C334 C335 = CAP: CAP CERAMIC 22pF 25V 5% NP0 0402; Chkd/date: SHREESHAIL/291105; Crtd /date: MAZHAR/040505; Custom_Duty: 15%; Customs_HS_Code: 85322990; Distributor_name: DIGIKEY; Distributor_part_number: 04023A220JAT2A-ND; Height: 0.60MM; Mfr_name: AVX CORPORATION; Mfr_part_number: 04023A220JAT2A; Mistral Part No: 120009030322-R; Package: 0402; Part_type: CAPACITORS\CERAMIC; Project: TELEMATICS-02; RoHS: RoHS; Tolerance: 5%; Voltage: 25V; Datasheet: Y:\MIS_DATABASE\DATASHEETS\CAPACITORS\AVX_MLC.PDF
C673 C686 C776 = CAP: CAP CERAMIC 0.01uF 16V 10% X7R 0402; Alternate_mfr_name_A: AVX CORPORATION; Alternate_mfr_name_B: KEMET; Alternate_mfr_name_D: TDK CORPORATION; Alternate_mfr_part_number_A: 0402YC103KAT2A; Alternate_mfr_part_number_B: C0402C103K4RACTU; Alternate_mfr_part_number_D: C1005X7R1C103K; Chkd/date: SHREESHAIL/180506; Crtd /date: MAZHAR/110506; Custom_Duty: 15%; Customs_HS_Code: 85322990; Distributor_name: DIGIKEY; Distributor_name_A: DIGIKEY; Distributor_name_B: DIGIKEY; Distributor_name_D: DIGIKEY; Distributor_part_number: PCC103BQCT-ND; Distributor_part_number_A: 478-1114-1-ND; Distributor_part_number_B: 399-1038-1-ND; Distributor_part_number_D: 445-1262-1-ND; Height: 0.55MM; Mfr_name: PANASONIC-ECG; Mfr_part_number: ECJ-0EB1C103K; Mistral Part No: 120009030032-R; Package: 0402; Part_type: CAPACITORS\CERAMIC; Project: VOCERA; RoHS: RoHS; Tolerance: 10%; Voltage: 16V; Datasheet: Y:\MIS_DATABASE\DATASHEETS\CAPACITORS\PAN-ECJ.PDF
D4 = DIODE_BAT54T1G_SOD123: DIODE SWITCHING 250V 0.2A SOD123; Chkd/date: VASANTHA/190614; Crtd /date: NAVEED/160614; Custom_Duty: 15%; Customs_HS_Code: 85412900; Distributor_name: DIGIKEY; Distributor_part_number: MMSD103T1GOSCT-ND; Height: 1.35MM; Mfr_name: ON SEMICONDUCTOR; Mistral Part No: 130014060029-R; Package: SOD123; Part_type: DIODE\MISC; Project: AEGIS_POM; RoHS: RoHS; Temperature: -55°C+150°C; Tolerance: NA; Voltage: 250V; Wattage: NA; Weight: NA; Datasheet: Y:\MIS_DATABASE\DATASHEETS\DISCRETES\DIODES\MMSD103T1G.PDF
FB11 FB36 FB37 FB40 = INDUCTOR_FERRITE: IND FERRITE BEAD CHIP 10E SMD; Chkd/date: Suhas/300910; Crtd /date: USMAN/020209; Custom_Duty: 24%; Customs_HS_Code: 85437099; Distributor_name: MOUSER; Distributor_part_number: 810-HF70ACB201209-T; Height: 1.10MM; Mfr_name: TDK CORPORATION; Mfr_part_number: HF70ACB201209; Mistral Part No: 130009030451; Package: SMD; Part_type: INDUCTOR; Project: PMC_ENCODER; Tolerance: 25%; Datasheet: Y:\MIS_DATABASE\DATASHEETS\DISCRETES\INDUCTORS\HF70.PDF
J31 = CON_RJ45-14_LPJG16314A4NL: CON RJ-45 FEMALE 14POS RT TH; Chkd/date: VASANTHA/150714; Crtd /date: BALACHANDAR/120614; Custom_Duty: 24%; Customs_HS_Code: 85369090; Distributor_name: NA; Distributor_part_number: NA; Height: 13.60MM; Mfr_name: LINK-PP; Mfr_part_number: LPJG16314A4NL; Mistral Part No: 150014060029-R; Package: THRU-HOLE; Part_type: CONNECTOR\JACK; Project: AEGIS; RoHS: RoHS; Temperature: -0°C+70°C; Tolerance: NA; Voltage: NA; Wattage: NA; Weight: NA; Datasheet: Y:\MIS_DATABASE\DATASHEETS\CONNECTORS\LPJG16314A4NL.PDF
Q13 = MOSFET_FDT434P_SOT223-3: IC MOSFET P-CHANNEL 20V 6A SOT-223; Chkd/date: NAVEED/150714; Crtd /date: VASANTHA/190614; Custom_Duty: 15%; Customs_HS_Code: 85322990; Distributor_name: DIGIKEY; Distributor_part_number: FDT434PCT-ND; Height: 1.80MM; Mfr_name: FAIRCHILD; Mistral Part No: 142014060010-R; Part_type: ICS\POWER\MOSFET; Project: AEGIS_POM; RoHS: RoHS; Temperature: -55°C+150°C; Tolerance: NA; Voltage: 20V; Wattage: NA; Weight: NA; Datasheet: Y:\MIS_DATABASE\DATASHEETS\DISCRETES\TRANSISTORS_FETS\FDT434P.PDF
R445 R449 R453 R465-R467 R532 R538 R546 R549 R554 R560 = RESISTOR: RES 22E 1/16W 1% 0402; Alternate_mfr_name_A: VISHAY; Alternate_mfr_part_number_A: CRCW040222R0FKED; Chkd/date: SUHAS/290910; Crtd /date: MAZHAR/090909; Custom_Duty: 15%; Customs_HS_Code: 85332119; Distributor_name: DIGIKEY; Distributor_name_A: DIGIKEY; Distributor_part_number: 311-22.0LRCT-ND; Distributor_part_number_A: 541-22.0LCT-ND; Height: 0.40MM; Mfr_name: YAGEO AMERICA; Mfr_part_number: RC0402FR-0722RL; Mistral Part No: 110009090004-P; Package: 0402; Part_type: RESISTORS\FIXED; Project: VMEFMCD; Remarks: In alternate datasheet it is RoHS COMPLIANT. Y:\MIS_DATABASE\DATASHEETS\RESISTORS\CRCW0402.PDF; RoHS: Pb-Free; Temperature: -55°C+155°C; Tolerance: 1%; Voltage: 50V; Wattage: 1/16W; Weight: 0.8g/1000pcs; Datasheet: Y:\MIS_DATABASE\DATASHEETS\RESISTORS\YAGEO-RC0402.PDF
R527 = RESISTOR: RES 0E 1/10W 5% 0402; Chkd/date: NAVEED/241114; Crtd /date: NAVEED/201014; Custom_Duty: 15%; Customs_HS_Code: 85332119; Distributor_name: DIGIKEY; Distributor_part_number: P0.0JCT-ND; Height: 0.40MM; Mfr_name: PANASONIC-ECG; Mfr_part_number: ERJ-2GE0R00X; Mistral Part No: 110014100008-R; Package: 0402; Part_type: RESISTORS\FIXED; Project: AEGIS POM; RoHS: RoHS; Tolerance: 5%; Wattage: 1/10W; Datasheet: Y:\MIS_DATABASE\DATASHEETS\RESISTORS\ERJ12.PDF
R528 R752 R763 R768 = RESISTOR: RES 1K 1/16W 5% 0402; Alternate_mfr_name_A: AVX CORPORATION; Alternate_mfr_name_C: YAGEO AMERICA; Alternate_mfr_part_number_A: CR05-102J-H; Alternate_mfr_part_number_C: RC0402JR-071KL; Chkd/date: SHREESHAIL/121205; Crtd /date: MAZHAR/230805; Custom_Duty: 15%; Customs_HS_Code: 85332119; Distributor_name: DIGIKEY; Distributor_name_A: NA; Distributor_name_C: DIGIKEY; Distributor_part_number: P1.0KJCT-ND; Distributor_part_number_A: NA; Distributor_part_number_C: 311-1.0KJRCT-ND; Height: 0.40MM; Mfr_name: PANASONIC-ECG; Mfr_part_number: ERJ-2GEJ102X; Mistral Part No: 110009030400-R; Package: 0402; Part_type: RESISTORS\FIXED; Project: HSE; RoHS: RoHS; Tolerance: 5%; Wattage: 1/16W; Datasheet: Y:\MIS_DATABASE\DATASHEETS\RESISTORS\ERJ12.PDF
R529 R595 = RESISTOR: RES 0E 1/16W 1% 0402; Chkd/date: MAZHAR/220709; Crtd /date: USMAN/270109; Custom_Duty: 15%; Customs_HS_Code: 85332119; Distributor_name: NA; Distributor_part_number: NA; Height: 0.40MM; Loading: DNI; Mfr_name: YAGEO AMERICA; Mfr_part_number: RC0402FR-070RL; Mistral Part No: 110009030085-P; Package: 0402; Part_type: RESISTORS\FIXED; Project: OMAP_EVM; RoHS: Pb-Free; Tolerance: 1%; Wattage: 1/16W; Datasheet: Y:\MIS_DATABASE\DATASHEETS\RESISTORS\CRCW0603.PDF
R530 R552 R559 R751 = RESISTOR: RES 1K 1/16W 5% 0402; ASSEMBLY_INSTRUCTION: DNI; Alternate_mfr_name_A: AVX CORPORATION; Alternate_mfr_name_C: YAGEO AMERICA; Alternate_mfr_part_number_A: CR05-102J-H; Alternate_mfr_part_number_C: RC0402JR-071KL; Chkd/date: SHREESHAIL/121205; Crtd /date: MAZHAR/230805; Custom_Duty: 15%; Customs_HS_Code: 85332119; Distributor_name: DIGIKEY; Distributor_name_A: NA; Distributor_name_C: DIGIKEY; Distributor_part_number: P1.0KJCT-ND; Distributor_part_number_A: NA; Distributor_part_number_C: 311-1.0KJRCT-ND; Height: 0.40MM; Loading: DNI; Mfr_name: PANASONIC-ECG; Mfr_part_number: ERJ-2GEJ102X; Mistral Part No: 110009030400-R; Package: 0402; Part_type: RESISTORS\FIXED; Project: HSE; RoHS: RoHS; Tolerance: 5%; Wattage: 1/16W; Datasheet: Y:\MIS_DATABASE\DATASHEETS\RESISTORS\ERJ12.PDF
R38 R43 R66 R531 R533 R541 R570 R594 R598 R604 R759 R767 R802 R855 = RESISTOR: RES 10K 1/16W 1% 0402; Alternate_mfr_name_A: AVX CORPORATION; Alternate_mfr_name_B: PANASONIC-ECG-ECG; Alternate_mfr_name_C: YAGEO AMERICA; Alternate_mfr_name_D: VISHAY; Alternate_mfr_part_number_A: CR05-103F-H; Alternate_mfr_part_number_B: ERJ-2RKF1002X; Alternate_mfr_part_number_C: 9C04021A1002FLHF3; Alternate_mfr_part_number_D: CRCW040210K0FKED; Chkd/date: SHREESHAIL/310506; Crtd /date: GEETHA/290506; Custom_Duty: 15%; Customs_HS_Code: 85332119; Distributor_name: DIGIKEY; Distributor_name_A: NA; Distributor_name_B: DIGIKEY; Distributor_name_C: DIGIKEY; Distributor_name_D: DIGIKEY; Distributor_part_number: 311-10.0KLRTR-ND; Distributor_part_number_A: NA; Distributor_part_number_B: P10.0KLCT-ND; Distributor_part_number_C: 311-10.0KLCT-ND; Distributor_part_number_D: 541-10.0KLCT-ND; Height: 0.40MM; Mfr_name: YAGEO AMERICA; Mfr_part_number: RC0402FR-0710KL; Mistral Part No: 110009030220-P; Package: 0402; Part_type: RESISTORS\FIXED; Project: VOCERA; RoHS: Pb-Free; Tolerance: 1%; Wattage: 1/16W; Datasheet: Y:\MIS_DATABASE\DATASHEETS\RESISTORS\YAGEO-RC0402.PDF
R548 R753 R754 R757 = RESISTOR: RES 10K 1/16W 1% 0402; Alternate_mfr_name_A: AVX CORPORATION; Alternate_mfr_name_B: PANASONIC-ECG-ECG; Alternate_mfr_name_C: YAGEO AMERICA; Alternate_mfr_name_D: VISHAY; Alternate_mfr_part_number_A: CR05-103F-H; Alternate_mfr_part_number_B: ERJ-2RKF1002X; Alternate_mfr_part_number_C: 9C04021A1002FLHF3; Alternate_mfr_part_number_D: CRCW040210K0FKED; Chkd/date: SHREESHAIL/310506; Crtd /date: GEETHA/290506; Custom_Duty: 15%; Customs_HS_Code: 85332119; Distributor_name: DIGIKEY; Distributor_name_A: NA; Distributor_name_B: DIGIKEY; Distributor_name_C: DIGIKEY; Distributor_name_D: DIGIKEY; Distributor_part_number: 311-10.0KLRTR-ND; Distributor_part_number_A: NA; Distributor_part_number_B: P10.0KLCT-ND; Distributor_part_number_C: 311-10.0KLCT-ND; Distributor_part_number_D: 541-10.0KLCT-ND; Height: 0.40MM; Loading: DNI; Mfr_name: YAGEO AMERICA; Mfr_part_number: RC0402FR-0710KL; Mistral Part No: 110009030220-P; Package: 0402; Part_type: RESISTORS\FIXED; Project: VOCERA; RoHS: Pb-Free; Tolerance: 1%; Wattage: 1/16W; Datasheet: Y:\MIS_DATABASE\DATASHEETS\RESISTORS\YAGEO-RC0402.PDF
R565 = RESISTOR: RES 4.7K 1/16W 5% 0402; Chkd/date: VASANTHA/190614; Crtd /date: NAVEED/160614; Custom_Duty: 15%; Customs_HS_Code: 85332119; Distributor_name: DIGIKEY; Distributor_part_number: RMCF0402JT4K70CT-ND; Height: 0.40MM; Mfr_name: STACKPOLE ELECTRONICS; Mfr_part_number: RMCF0402JT4K70; Mistral Part No: 110014060028-R; Package: 0402; Part_type: RESISTORS\FIXED; Project: AEGIS_POM; RoHS: RoHS; Temperature: -55°C+155°C; Tolerance: 5%; Voltage: NA; Wattage: 1/16W; Weight: NA; Datasheet: Y:\MIS_DATABASE\DATASHEETS\RESISTORS\RMCF-SERIES1.PDF
R566 = RESISTOR: RES 100K 1/16W 1% 0402; Alternate_mfr_name_A: VISHAY; Alternate_mfr_part_number_A: CRCW0402100KFNED; Chkd/date: VASANTHA/200614; Crtd /date: NAVEED/170614; Custom_Duty: 15%; Customs_HS_Code: 85332119; Distributor_name: DIGIKEY; Distributor_name_A: NA; Distributor_part_number: RMCF0402FT100KCT-ND; Distributor_part_number_A: NA; Height: 0.40MM; Mfr_name: STACKPOLE ELECTRONICS; Mfr_part_number: RMCF0402FT100K; Mistral Part No: 110014060043-R; Package: 0402; Part_type: RESISTORS\FIXED; Project: AEGIS_POM; RoHS: RoHS; Temperature: -55°C+155°C; Tolerance: 1%; Voltage: NA; Wattage: 1/16W; Weight: NA; Datasheet: Y:\MIS_DATABASE\DATASHEETS\RESISTORS\RMCF-SERIES1.PDF
R567 = RESISTOR: RES 12.1K 1/10W 1% 0603; Alternate_mfr_name_A: YAGEO AMERICA; Alternate_mfr_name_D: VISHAY; Alternate_mfr_part_number_A: RC0603FR-0712K1L; Alternate_mfr_part_number_D: CRCW060312K1FKEA; Chkd/date: MAZHAR/310508; Crtd /date: MAZHAR/170907; Custom_Duty: 15%; Customs_HS_Code: 85332119; Distributor_name: DIGIKEY; Distributor_name_A: DIGIKEY; Distributor_name_D: DIGIKEY; Distributor_part_number: P12.1KHCT-ND; Distributor_part_number_A: 311-12.1KHRCT-ND; Distributor_part_number_D: 541-12.1KHCT-ND; Height: 0.55MM; Mfr_name: PANASONIC-ECG; Mfr_part_number: ERJ-3EKF1212V; Mistral Part No: 110009030247-R; Package: 0603; Part_type: RESISTORS\FIXED; Project: SMART VIEW_NVR; RoHS: RoHS; Temperature: -55°C+155°C; Tolerance: 1%; Voltage: NA; Wattage: 1/10W; Weight: 2/1000g; Datasheet: Y:\MIS_DATABASE\DATASHEETS\RESISTORS\PAN_ERJ.PDF
R585 R586 = RESISTOR: RES 220E 1/16W 1% 0402; Chkd/date: BAVISH/290811; Crtd /date: BAVISH/260711; Custom_Duty: 15%; Customs_HS_Code: 85332119; Distributor_name: DIGIKEY; Distributor_part_number: P220LCT-ND; Height: 0.40MM; Mfr_name: PANASONIC-ECG; Mfr_part_number: ERJ-2RKF2200X; Mistral Part No: 110011070017-R; Package: 0402; Part_type: RESISTORS\FIXED; Project: LSM; RoHS: RoHS; Temperature: -55°C+125°C; Tolerance: 1%; Voltage: NA; Wattage: 1/10W; Weight: 0.8/1000g; Datasheet: Y:\MIS_DATABASE\DATASHEETS\RESISTORS\PAN_ERJ.PDF
R770 = RESISTOR: RES 1.5K 1/16W 5% 0402; Chkd/date: VASANTHA/200614; Crtd /date: NAVEED/170614; Custom_Duty: 15%; Customs_HS_Code: 85332119; Distributor_name: DIGIKEY; Distributor_part_number: RMCF0402JT1K50CT-ND; Height: 0.40MM; Mfr_name: STACKPOLE ELECTRONICS; Mfr_part_number: RMCF0402JT1K50C; Mistral Part No: 110014060038-R; Package: 0402; Part_type: RESISTORS\FIXED; Project: AEGIS_POM; RoHS: RoHS; Temperature: -55°C+155°C; Tolerance: 5%; Voltage: NA; Wattage: 1/16W; Weight: NA; Datasheet: Y:\MIS_DATABASE\DATASHEETS\RESISTORS\RMCF-SERIES1.PDF
TP171 = TESTPOINT: TESTPOINT 20 SMD; Chkd/date: SHREESHAIL/171006; Crtd /date: MAZHAR/171006; Distributor_name: NA; Distributor_part_number: NA; Height: NA; Mfr_name: LOCAL; Mistral Part No: NA4; Part_type: MISC\TESTPOINT; Project: BT MODULE_CSRBC04
U88 U131 = SN74LVC1G07DBVR_SOT23-5: IC SINGLE BUFFER/DRIVER SC-70; Chkd/date: VASANTHA/150714; Crtd /date: NAVEED/160614; Custom_Duty: 15%; Customs_HS_Code: 85423100; Distributor_name: DIGIKEY; Distributor_part_number: 296-8486-1-ND; Height: 1.10MM; Mfr_name: TEXAS INSTRUMENTS; Mfr_part_number: SN74LVC1G07DCKR; Mistral Part No: 141014060023-R; Part_type: ICS\INTERFACE\LINE DRIVER; Project: AEGIS_POM; RoHS: Sb/ Br FREE; Temperature: -40°C+85°C; Tolerance: NA; Voltage: NA; Wattage: NA; Weight: NA; Datasheet: Y:\MIS_DATABASE\DATASHEETS\ICS\INTERFACE\SN74LVC1G07.PDF
U5 U89 = SN74LVC1G08DBVRE4_SOT23-5: IC SINGLE 2-INPUT POSITIVE AND GATE SOT23-5; Chkd/date: SUHAS/221010; Crtd /date: USMAN/151008; Custom_Duty: 15%; Customs_HS_Code: 85423100; Distributor_name: DIGIKEY; Distributor_part_number: SN74LVC1G08DBVRE4-ND; Height: 1.45MM; Mfr_name: TEXAS INSTRUMENTS; Mistral Part No: 141009060026-R; Part_type: ICS\DIGITAL\GATES; Project: KHAN_MAIN; RoHS: Sb/ Br FREE; Temperature: -40°C+85°C; Datasheet: Y:\MIS_DATABASE\DATASHEETS\ICS\DIGITAL\GATES\SN74LVC1G08.PDF
U90 U94 = TPD4E05U06_USON10: IC 4-CHANNEL PROTECTION SOLUTION FOR SUPER-SPEED USON10; Chkd/date: NAVEED/070115; Crtd /date: NAVEED/311014; Custom_Duty: 15%; Customs_HS_Code: 85423100; Distributor_name: NA; Distributor_part_number: NA; Height: 0.55MM; Mfr_name: TEXAS INSTRUMENTS; Mistral Part No: 141014100018-R; Package: USON10; Part_type: ICS\INTERFACE; Project: GALILEO_EVM; RoHS: RoHS; Temperature: -40°C+125°C; Tolerance: NA; Voltage: NA; Wattage: NA; Weight: NA; Datasheet: Y:\MIS_DATABASE\DATASHEETS\ICS\INTERFACE\TPD4E05U06.PDF
U92 = KSZ9031RNX_QFN48: IC ETHERNET TRANSCEIVER 10/100/1000 Mbps QFN48; Chkd/date: VASANTHA/150714; Crtd /date: BALACHANDAR/120614; Custom_Duty: 15%; Customs_HS_Code: 85423100; Distributor_name: DIGIKEY; Distributor_part_number: 576-4041-1-ND; Height: 0.90MM; Mfr_name: MICREL; Mistral Part No: 143014060002-R; Package: QFN48; Part_type: ICS\TELECOM\TRANSCEIVER; Project: AEGIS; RoHS: Pb-Free; Temperature: -0°C+70°C; Tolerance: NA; Voltage: NA; Wattage: NA; Weight: NA; Datasheet: Y:\MIS_DATABASE\DATASHEETS\ICS\DIGITAL\BUSTRANSCEIVER\KSZ9031RNX.PDF
Y9 = CRY: CRY 25MHz SMD; Chkd/date: NAVEED/210714; Crtd /date: VASANTHA/160714; Distributor_name: DIGIKEY; Distributor_part_number: CTX1167CT-ND; Height: 1.35MM; Mfr_name: CTS; Mfr_part_number: 445C25D25M00000; Mistral Part No: 130014070029-R; Package: SMD; Part_type: CRYSTAL; Project: AEGIS_POM; RoHS: RoHS; Temperature: -20°C+70°C; Tolerance: NA; Voltage: NA; Wattage: NA; Weight: NA; Datasheet: Y:\MIS_DATABASE\DATASHEETS\MISC\CRY_OSC\445.PDF
C5 = CAP: CAP CERAMIC 22uF 25V 10% X7R 1210; Chkd/date: BAVISH/040311; Crtd /date: MAZHAR/190111; Custom_Duty: 15%; Customs_HS_Code: 85322990; Distributor_name: DIGIKEY; Distributor_part_number: 490-5313-1-ND; Height: 2.70MM; Mfr_name: MURATA; Mfr_part_number: GRM32ER71E226KE15L; Mistral Part No: 120011010016-R; Package: 1210; Part_type: CAPACITORS\CERAMIC; Project: ITS-PWR_CARD; RoHS: RoHS; Temperature: -55°C+125°C; Tolerance: 10%; Voltage: 25V; Wattage: NA; Weight: NA; Datasheet: Y:\MIS_DATABASE\DATASHEETS\CAPACITORS\GRM32,43,55.PDF
C365 C366 = CAP: CAP CERAMIC 0.1uF 25V -20% TO +80 Y5V 0402; Chkd/date: SHREESHAIL/301105; Crtd /date: MAZHAR/251005; Custom_Duty: 15%; Customs_HS_Code: 85322990; Distributor_name: DIGIKEY; Distributor_part_number: 490-3271-1-ND; Height: 0.55MM; Mfr_name: MURATA; Mfr_part_number: GRM155F51E104ZA01D; Mistral Part No: 120009030085; Package: 0402; Part_type: CAPACITORS\CERAMIC; Project: ADR; Tolerance: -20% TO +80%; Voltage: 25V; Datasheet: Y:\MIS_DATABASE\DATASHEETS\CAPACITORS\GRM188SERIES.PDF
FB5 = INDUCTOR_FERRITE: IND BEAD CHIP 120E 1.2A 0402; Chkd/date: ASHOK/240212; Crtd /date: BAVISH/060711; Custom_Duty: 24%; Customs_HS_Code: 85437099; Distributor_name: DIGIKEY; Distributor_part_number: 445-2981-1-ND; Height: 0.55MM; Mfr_name: TDK CORPORATION; Mfr_part_number: MPZ1005S121C; Mistral Part No: 130011070007-R; Package: 0402; Part_type: INDUCTOR; Project: SVDU; RoHS: RoHS; Temperature: -40°C+85°C; Tolerance: NA; Voltage: NA; Wattage: NA; Weight: 1mg; Datasheet: Y:\MIS_DATABASE\DATASHEETS\DISCRETES\INDUCTORS\MPZ1005.PDF
FL1 FL2 = EMIFILTER_IND: FERRITE BEAD 120E 2A 0603; Chkd/date: RAGESH/111010; Crtd /date: MUDDU/190610; Custom_Duty: 24%; Customs_HS_Code: 85437099; Distributor_name: DIGIKEY; Distributor_part_number: 490-3991-1-ND; Height: 0.95MM; Mfr_name: MURATA; Mfr_part_number: BLM18EG121SN1D; Mistral Part No: 130010060030-R; Package: 0603; Part_type: MISC\FILTER; Project: CENTAURUS; Temperature: -55°C+125°C; Weight: NA; Datasheet: Y:\MIS_DATABASE\DATASHEETS\DISCRETES\INDUCTORS\BLM18E.PDF
FL19 = EMIFILTER_IND: FERRITE CHIP 120E 3A 0603; Chkd/date: MANOJ/300414; Crtd /date: USMAN/260313; Custom_Duty: 15%; Customs_HS_Code: 85412900; Distributor_name: DIGIKEY; Distributor_part_number: 490-5254-1-ND; Height: 0.75MM; Mfr_name: MURATA; Mfr_part_number: BLM18KG121TN1D; Mistral Part No: 130013030027-R; Package: 0603; Part_type: MISC\FILTER; Project: GEN_3-8; RoHS: RoHS; Temperature: -55°C+125°C; Tolerance: 25%; Voltage: NA; Wattage: NA; Weight: NA; Datasheet: Y:\MIS_DATABASE\DATASHEETS\DISCRETES\INDUCTORS\BLM18K-SERIES.PDF
J5 = CON36_PCI: CON PCI EXPRESS 36POS SMD; Chkd/date: NAVEED/060115; Crtd /date: VASANTHA/031214; Custom_Duty: 24%; Customs_HS_Code: 85369090; Distributor_name: DIGIKEY; Distributor_part_number: 609-2882-ND; Height: 11.10MM; Mfr_name: FCI; Mfr_part_number: 10061913-100CLF; Mistral Part No: 150014120003-R; Package: SMD; Part_type: CONNECTOR\PCI; Project: GALILEO_EVM; RoHS: RoHS; Temperature: NA; Tolerance: NA; Voltage: NA; Wattage: NA; Weight: NA; Datasheet: Y:\MIS_DATABASE\DATASHEETS\CONNECTORS\10061913-101CLF.PDF
J44 = HEADER_3X1: CON HDR 3X1 2.54MM PITCH ST TH; Chkd/date: MAZHAR/100311; Crtd /date: BAVISH/160211; Custom_Duty: 24%; Customs_HS_Code: 85369090; Distributor_name: DIGIKEY; Distributor_part_number: A26545-ND; Height: 10.74MM; Mfr_name: TYCO ELECTRONICS; Mfr_part_number: 87224-3; Mistral Part No: 150011020004-R; Package: THRU-HOLE; Part_type: CONNECTOR\HEADERS; Project: OMAPL1_PEC20; RoHS: RoHS; Temperature: NA; Tolerance: NA; Voltage: NA; Wattage: NA; Weight: NA; Datasheet: Y:\MIS_DATABASE\DATASHEETS\CONNECTORS\87224.PDF
R65 R181 R182 R596 R606 R800 R801 = RESISTOR: RES 0E 1/16W 1% 0402; Chkd/date: MAZHAR/220709; Crtd /date: USMAN/270109; Custom_Duty: 15%; Customs_HS_Code: 85332119; Distributor_name: NA; Distributor_part_number: NA; Height: 0.40MM; Mfr_name: YAGEO AMERICA; Mfr_part_number: RC0402FR-070RL; Mistral Part No: 110009030085-P; Package: 0402; Part_type: RESISTORS\FIXED; Project: OMAP_EVM; RoHS: Pb-Free; Tolerance: 1%; Wattage: 1/16W; Datasheet: Y:\MIS_DATABASE\DATASHEETS\RESISTORS\CRCW0603.PDF
R719 = RESISTOR: RES 3.00K 1/20W 1% 0201; Chkd/date: SUHAS/270910; Crtd /date: MUDDU/030310; Custom_Duty: 15%; Customs_HS_Code: 85332119; Distributor_name: DIGIKEY; Distributor_part_number: P3.00KABCT-ND; Height: 0.26MM; Mfr_name: PANASONIC-ECG; Mfr_part_number: ERJ-1GEF3001C; Mistral Part No: 110010030003-R; Package: 0201; Part_type: RESISTORS\FIXED; Project: KOPIN_MODULS; RoHS: RoHS; Temperature: -55°C+125°C; Tolerance: 1%; Wattage: 1/20W; Weight: 0.15g/1000pcs; Datasheet: Y:\MIS_DATABASE\DATASHEETS\RESISTORS\ERJ-1G.PDF

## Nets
DGND: C5.2 C310.2 C311.2 C312.2 C327.2 C329.2 C330.2 C333.2 C334.1 C335.1 C336.2 C337.2 C340.2 C341.2 C342.2 C346.2 C349.1 C351.1 C365.2 C366.2 C369.2 C370.2 C371.2 C372.2 C374.2 C377.1 C672.1 C673.2 C685.2 C686.2 C776.2 FL2.1 J5.A4 J5.A12 J5.A15 J5.A18 J5.B4 J5.B7 J5.B13 J5.B16 J5.B18 J31.1(CH-GND) R528.2 R548.2 R567.2 R598.2 R604.2 R719.2 R752.2 R753.2 R754.2 R757.2 R763.2 R768.2 U5.3(GND) U88.3(GND) U89.3(GND) U90.3(GND) U90.8(GND) U92.13(NC1) U92.29(VSS) U92.49(PADDLE_GND) U94.3(GND) U94.8(GND) U131.3(GND) ; also on sheet 1 11 12 13 14 15 16 17 18 19 20 21 22 23 24 27 28 29 30 31 32 33 34 35 36 37 38 39 40 41 42 43 44 45 46 47 48 49 50
GND_EARTH: C349.2 C351.2 J31.15(SH1) J31.16(SH2)
GND_PCIE: FL2.2 J5.SH1 J5.SH2
VCC3V3_DC_CONN: FB5.1 FL19.1 ; also on sheet 32 50
VCC3V3_DCIN: C311.1 C377.2 C776.1 FB11.1 R66.1 R527.1 U5.5(VCC) U131.5(VCC) ; also on sheet 11 17 18 19 20 21 22 23 24 27 28 29 30 31 32 33 34 35 36 37 38 43 44 45 46 47 48 50
VCC3V3_PCIE: C369.1 C370.1 C371.1 C372.1 FL19.2 J5.A9 J5.A10 J5.B8 R38.1 R43.1 R594.2 R855.2
VCC3V3_PCIE_AUX: C374.1 FB5.2 J5.B10 R802.1
VCC12V0_DC_IN: FL1.1 ; also on sheet 1 31 33 34 47 48 50
VCC12V0_PCIE: C5.1 C365.1 C366.1 FL1.2 J5.A2 J5.A3 J5.B1 J5.B2 J5.B3
BUF_ETH_RSTn: C336.1 D4.2(A) R529.1 R566.2 U88.4(Y) U92.42(RESET_N)
ETH1_XI: C335.2 U92.46(XI) Y9.2
ETH1_XO: C334.2 U92.45(XO) Y9.1
ETH_RSTn: U89.1(A) ; also on sheet 47
ETH_RSTn_AND: R529.2 U88.2(A) U89.4(Y)
ETHER1_D0N: J31.10(MX0-) U92.3(TXRXM_A) U94.2(D1-)
ETHER1_D0P: J31.9(MX0+) U92.2(TXRXP_A) U94.1(D1+)
ETHER1_D1N: J31.8(MX1-) U92.6(TXRXM_B) U94.5(D2-)
ETHER1_D1P: J31.7(MX1+) U92.5(TXRXP_B) U94.4(D2+)
ETHER1_D2N: J31.6(MX2-) U90.2(D1-) U92.8(TXRXM_C)
ETHER1_D2P: J31.5(MX2+) U90.1(D1+) U92.7(TXRXP_C)
ETHER1_D3N: J31.4(MX3-) U90.5(D2-) U92.11(TXRXM_D)
ETHER1_D3P: J31.3(MX3+) U90.4(D2+) U92.10(TXRXP_D)
LED_MODE: R570.2 TP171.1(TP) U92.41(CLK125_NDO/LED_MODE)
PCI_CON_PORz: J44.2 R606.2
PCI_PORz_IN: J44.1 R855.1 U131.4(Y)
PCI_PORz_OUT: J44.3 ; also on sheet 11
PCIE_CLKN_CML_100MHz: U1.F2(PCIE_CLK_N) ; also on sheet 36
PCIE_CLKN_HCSL_100MHz: J5.A14 ; also on sheet 36
PCIE_CLKP_CML_100MHz: U1.G2(PCIE_CLK_P) ; also on sheet 36
PCIE_CLKP_HCSL_100MHz: J5.A13 ; also on sheet 36
PCIeI_RSTn: R65.1 ; also on sheet 47
PHY1_LED_ACTn: J31.12 R528.1 R751.1 U92.17(LED1_/_PME_N1/PHYAD0)
PHY1_LED_LINKn: J31.13 R530.1 R752.1 U92.15(LED2/PHYAD1)
PRSNT1#: R596.1 ; also on sheet 12
PRSNT#: J5.A1 R594.1 R595.1
SOC_I2C0_SCL: R800.2 ; also on sheet 17 34 35 45
SOC_I2C0_SDA: R801.2 ; also on sheet 17 34 35 45
SOC_MDIO_CLK: R767.2 U1.U3(MDIO_CLK/GPIO0_98) U92.36(MDC)
SOC_MDIO_DATA: R770.2 U1.V3(MDIO_DATA/GPIO0_97) U92.37(MDIO)
SOC_PCIE_RXN0: J5.A16 R182.2
SOC_PCIE_RXN0_C: R182.1 U1.D1(PCIE_RXN0)
SOC_PCIE_RXP0: J5.A17 R181.2
SOC_PCIE_RXP0_C: R181.1 U1.E1(PCIE_RXP0)
SOC_PCIE_TXN0: C171.2 J5.B14
SOC_PCIE_TXN0_C: C171.1 U1.H1(PCIE_TXN0)
SOC_PCIE_TXP0: C170.2 J5.B15
SOC_PCIE_TXP0_C: C170.1 U1.G1(PCIE_TXP0)
SOC_PCIE_WAKEn: J5.B11 R802.2 ; also on sheet 12
SOC_RESETSTATz: U5.2(B) U89.2(B) ; also on sheet 11 17 18 21 22 23 31 33 45 46
SOC_RGMII_RXCLK: R560.1 U1.A22(MII_RXCLK/RGMII_RXC/GPIO0_72)
SOC_RGMII_RXCLK_R: R559.1 R560.2 R768.1 U92.35(RX_CLK/PHYAD2)
SOC_RGMII_RXCTL: R554.1 U1.A24(MII_RXDV/RGMII_RXCTL/GPIO0_81)
SOC_RGMII_RXCTL_R: R552.1 R554.2 R763.1 U92.33(RX_DV/CLK125_EN)
SOC_RGMII_RXD0: R549.1 U1.B24(MII_RXD0/RGMII_RXD0/RMII_RXD0/GPIO0_80)
SOC_RGMII_RXD0_R: R548.1 R549.2 R759.1 U92.32(RXD0/MODE0)
SOC_RGMII_RXD1: R546.1 U1.C23(MII_RXD1/RGMII_RXD1/RMII_RXD1/GPIO0_79)
SOC_RGMII_RXD1_R: R541.1 R546.2 R757.1 U92.31(RXD1/MODE1)
SOC_RGMII_RXD2: R538.1 U1.B23(MII_RXD2/RGMII_RXD2/GPIO0_78)
SOC_RGMII_RXD2_R: R533.1 R538.2 R754.1 U92.28(RXD2/MODE2)
SOC_RGMII_RXD3: R532.1 U1.F22(MII_RXD3/RGMII_RXD3/GPIO0_77)
SOC_RGMII_RXD3_R: R531.1 R532.2 R753.1 U92.27(RXD3/MODE3)
SOC_RGMII_TXCLK: R449.1 U1.C25(MII_TXCLK/RGMII_TXC/GPIO0_85)
SOC_RGMII_TXCLK_R: R449.2 U92.24(GTX_CLK)
SOC_RGMII_TXCTL: R465.1 U1.H25(MII_TXEN/RGMII_TXCTL/RMII_TXEN/GPIO0_95)
SOC_RGMII_TXCTL_R: R465.2 U92.25(TX_EN)
SOC_RGMII_TXD0: R445.1 U1.G23(MII_TXD0/RGMII_TXD0/RMII_TXD0/GPIO0_94)
SOC_RGMII_TXD0_R: R445.2 U92.19(TXD0)
SOC_RGMII_TXD1: R467.1 U1.G24(MII_TXD1/RGMII_TXD1/RMII_TXD1/GPIO0_93)
SOC_RGMII_TXD1_R: R467.2 U92.20(TXD1)
SOC_RGMII_TXD2: R466.1 U1.G25(MII_TXD2/RGMII_TXD2/GPIO0_92)
SOC_RGMII_TXD2_R: R466.2 U92.21(TXD2)
SOC_RGMII_TXD3: R453.1 U1.D25(MII_TXD3/RGMII_TXD3/GPIO0_91)
SOC_RGMII_TXD3_R: R453.2 U92.22(TXD3)
TDI: J5.A6 R38.2
TMS: J5.A8 R43.2
VETH1_AVDDH: C341.1 C342.1 C346.1 FB11.2 Q13.3(S) U92.1(AVDDH) U92.12(AVDDH) U92.47(NC2)
VETH1_AVDDL: C333.1 C337.1 FB40.2 U92.4(AVDDL) U92.9(AVDDL)
VETH1_AVDDL_PLL: C340.1 C685.1 C686.1 FB36.2 U92.44(AVDDL_PLL)
VETH1_AVDDL_PMOS: C327.1 FB36.1 FB37.1 FB40.1 Q13.2(D1) Q13.4(D2)
VETH1_DVDDH: C310.1 C312.1 C672.2 C673.1 D4.1(K) R527.2 R530.2 R531.2 R533.2 R541.2 R552.2 R559.2 R565.1 R566.1 R570.1 R585.1 R586.1 R751.2 R759.2 R767.1 R770.1 U88.5(VCC) U89.5(VCC) U92.16(DVDDH) U92.34(DVDDH) U92.40(DVDDH)
VETH1_DVDDL: C329.1 C330.1 FB37.2 U92.14(DVDDL) U92.18(DVDDL) U92.23(DVDDL) U92.26(DVDDL) U92.30(DVDDL) U92.39(DVDDL)
N14091468: R567.1 U92.48(ISET)
N14092548: R565.2 U92.38(INT_N_/_PME_N2)
N14093724: Q13.1(G) U92.43(LDO_O)
N14093756: J31.11 R585.2
N17428402: R719.1 U1.H7(PCIE_REFRES)
N18192341: J5.B17 R595.2 R596.2
N18211886: R65.2 R66.2 U5.1(A)
N18211953: U5.4(Y) U131.2(A)
N18214699: J5.A11 R606.1
N19623002: J31.14 R586.2
N20368231: J5.B9 R604.1
N20368804: J5.A5 R598.1
N22366198: J5.B5 R800.1
N22366201: J5.B6 R801.1

Not connected (* = marked no-connect by the designer): J5 A7* B12*; J31 2(VCC)*; U88 1(NC)*; U90 6(NC1)* 7(NC2)* 9(NC3)* 10(NC4)*; U94 6(NC1)* 7(NC2)* 9(NC3)* 10(NC4)*; U131 1(NC)*

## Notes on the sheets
sheet 25
- ETHERNET PHY
- ETHERNET CONNECTOR
- ETHERNET MODE CONFIGURATION
- RXD[3:0]
- MODE
- 0100
- NAND TREE
- 0111
- CHIP POWER DOWN
- ETHERNET
  ESD DEVICES
- 1100
- RGMII MODE - ADVERTISE 1000 BASE-T
  FULL DUPLEX ONLY
- 1101
- RGMII MODE- ADVERTISE 1000 BASE-T
  FULL & HALF DUPLEX ONLY
- 1110
- RGMII MODE- ADVERTISE ALL CAPABILITIES
  (10/100/1000 SPEED HALF / FULL DUPLEX),
  EXCEPT 1000 BASE-T HALF DUPLEX
- 1111
- RGMII MODE- ADVERTISE ALL CAPABILITIES
  (10/100/1000 SPEED HALF / FULL DUPLEX)
- ETHERNET
  RESET
sheet 26
- PCI EXPRESS x1 CONNECTOR
- For Routing complexity, Polarity has been swapped at
  connector side
- TBD
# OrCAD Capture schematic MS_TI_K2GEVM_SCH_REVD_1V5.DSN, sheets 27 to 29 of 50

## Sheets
27 26. USB DUAL ROLE &  HOST: size C; title: USB DUAL ROLE & HOST
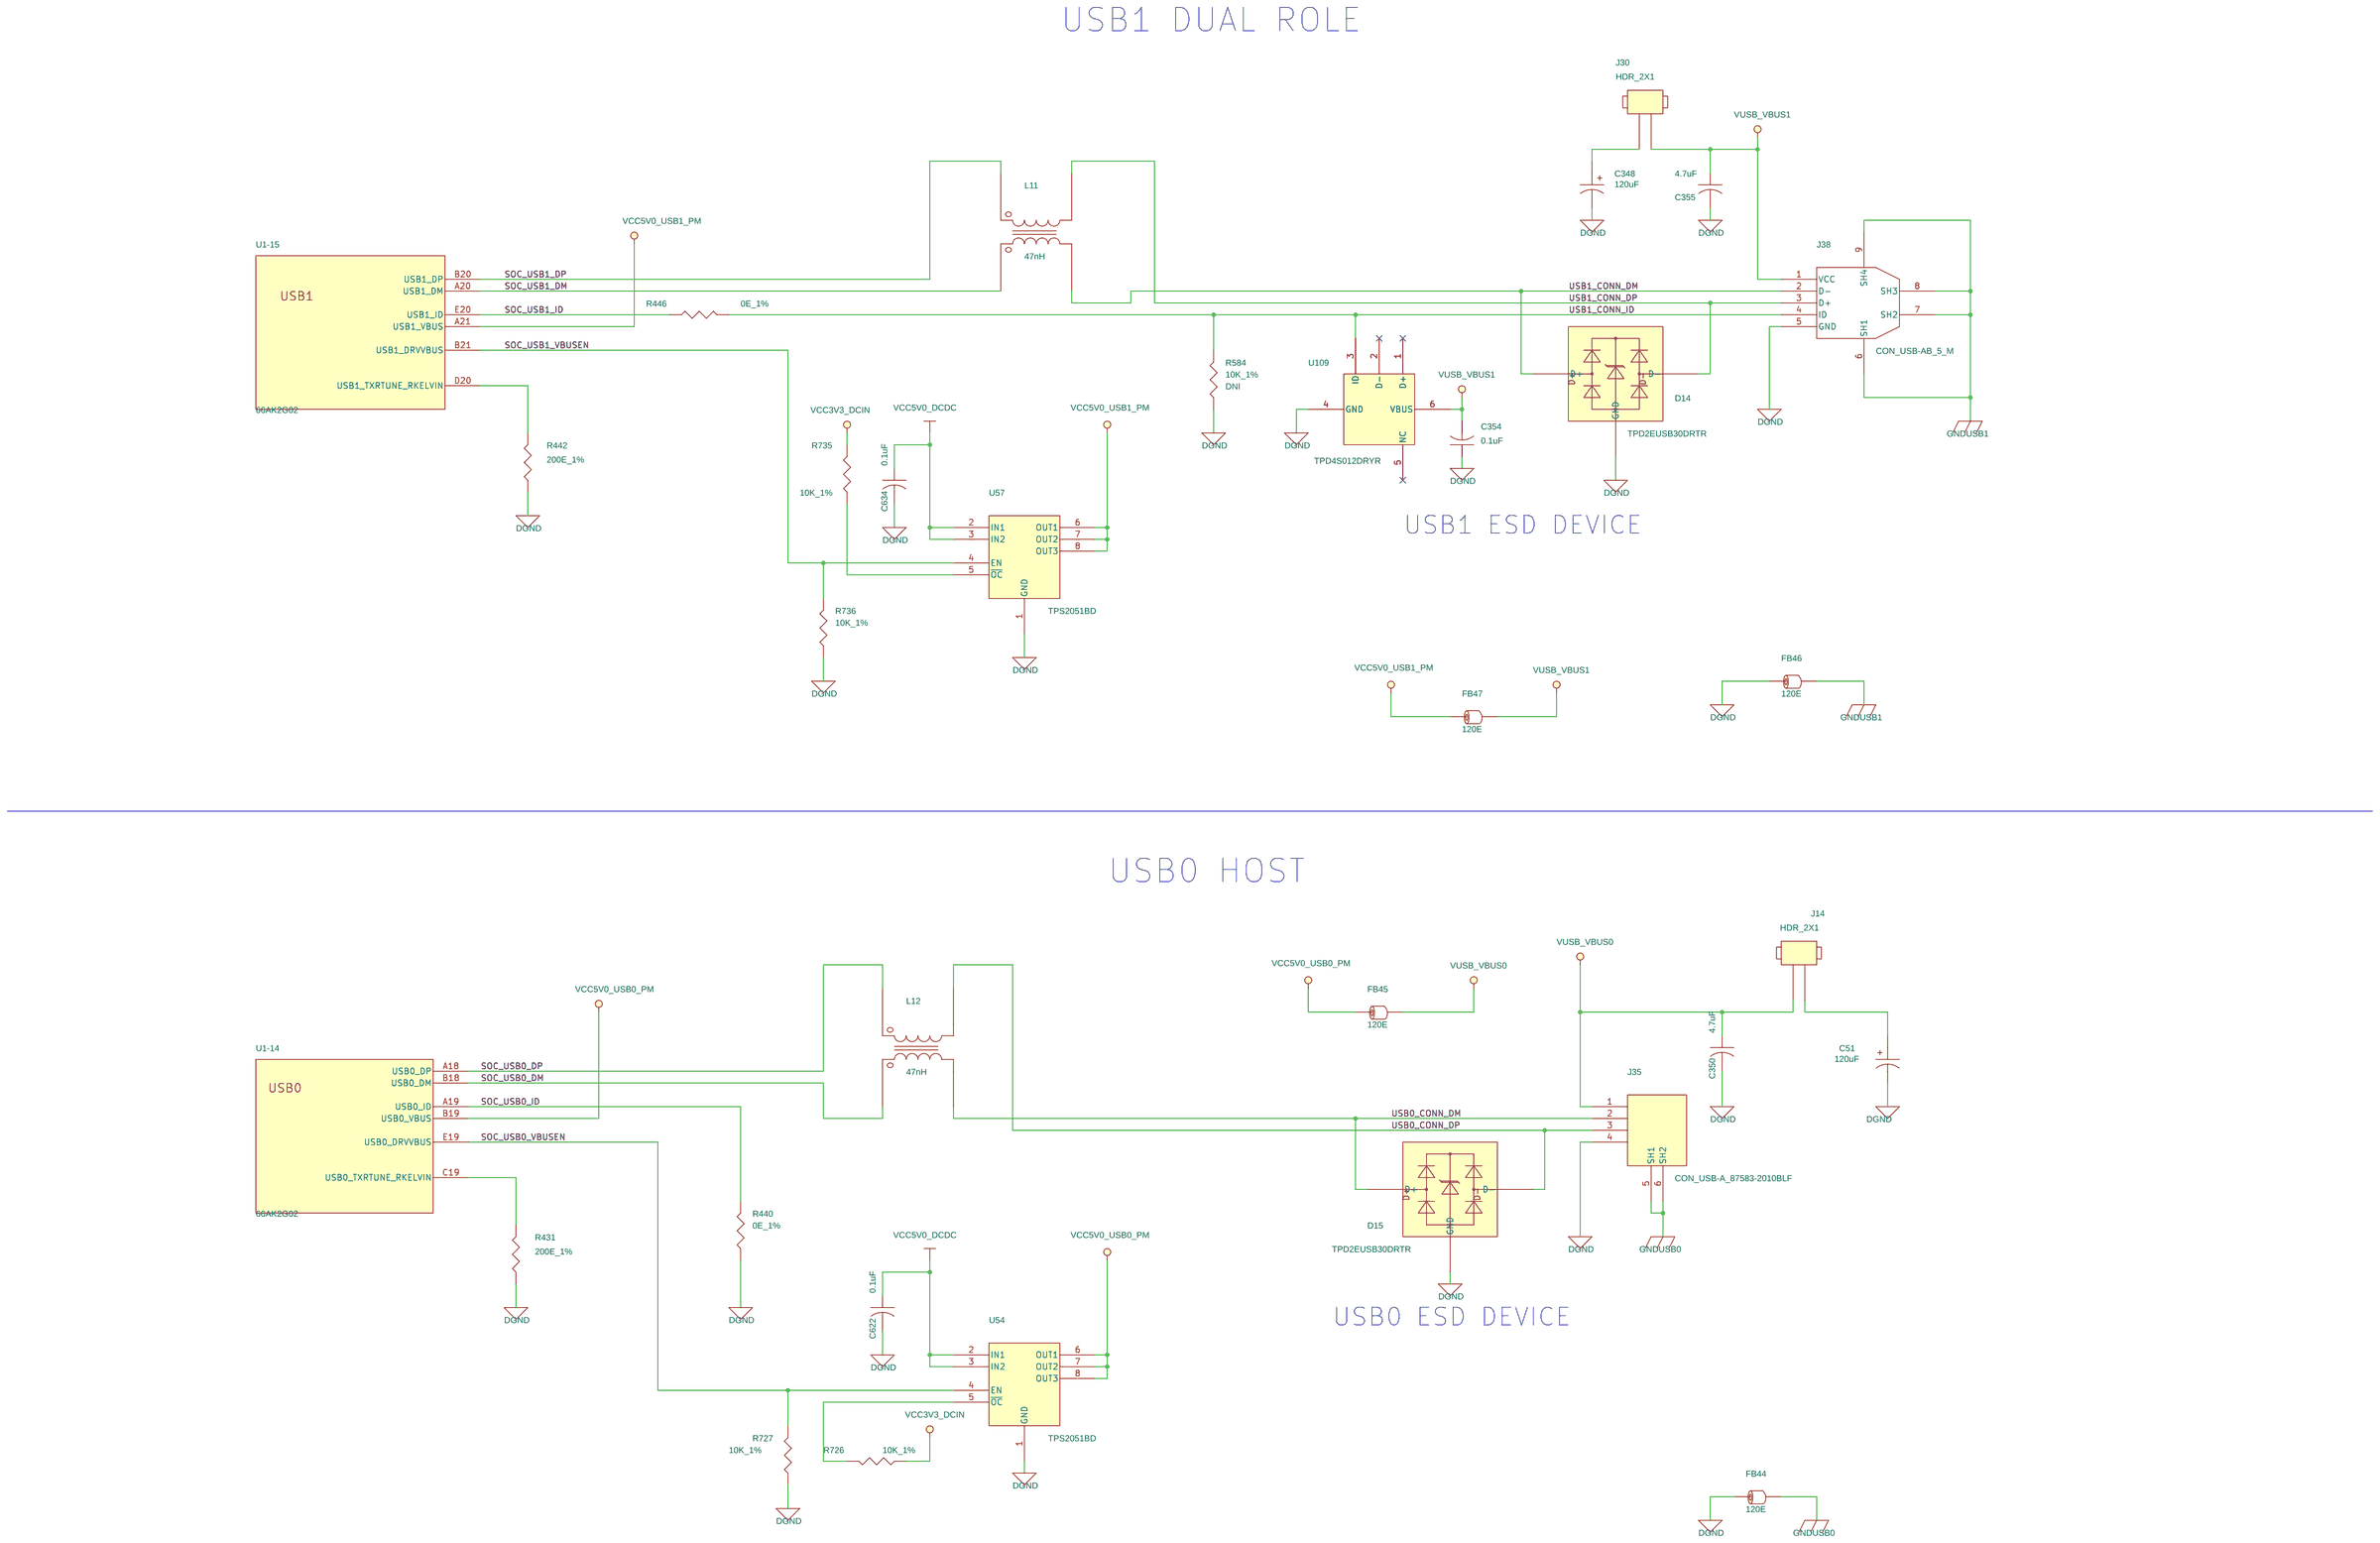
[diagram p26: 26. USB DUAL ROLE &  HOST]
28 27. UART0 & UART1: size C; title: UART 0,1,& 2
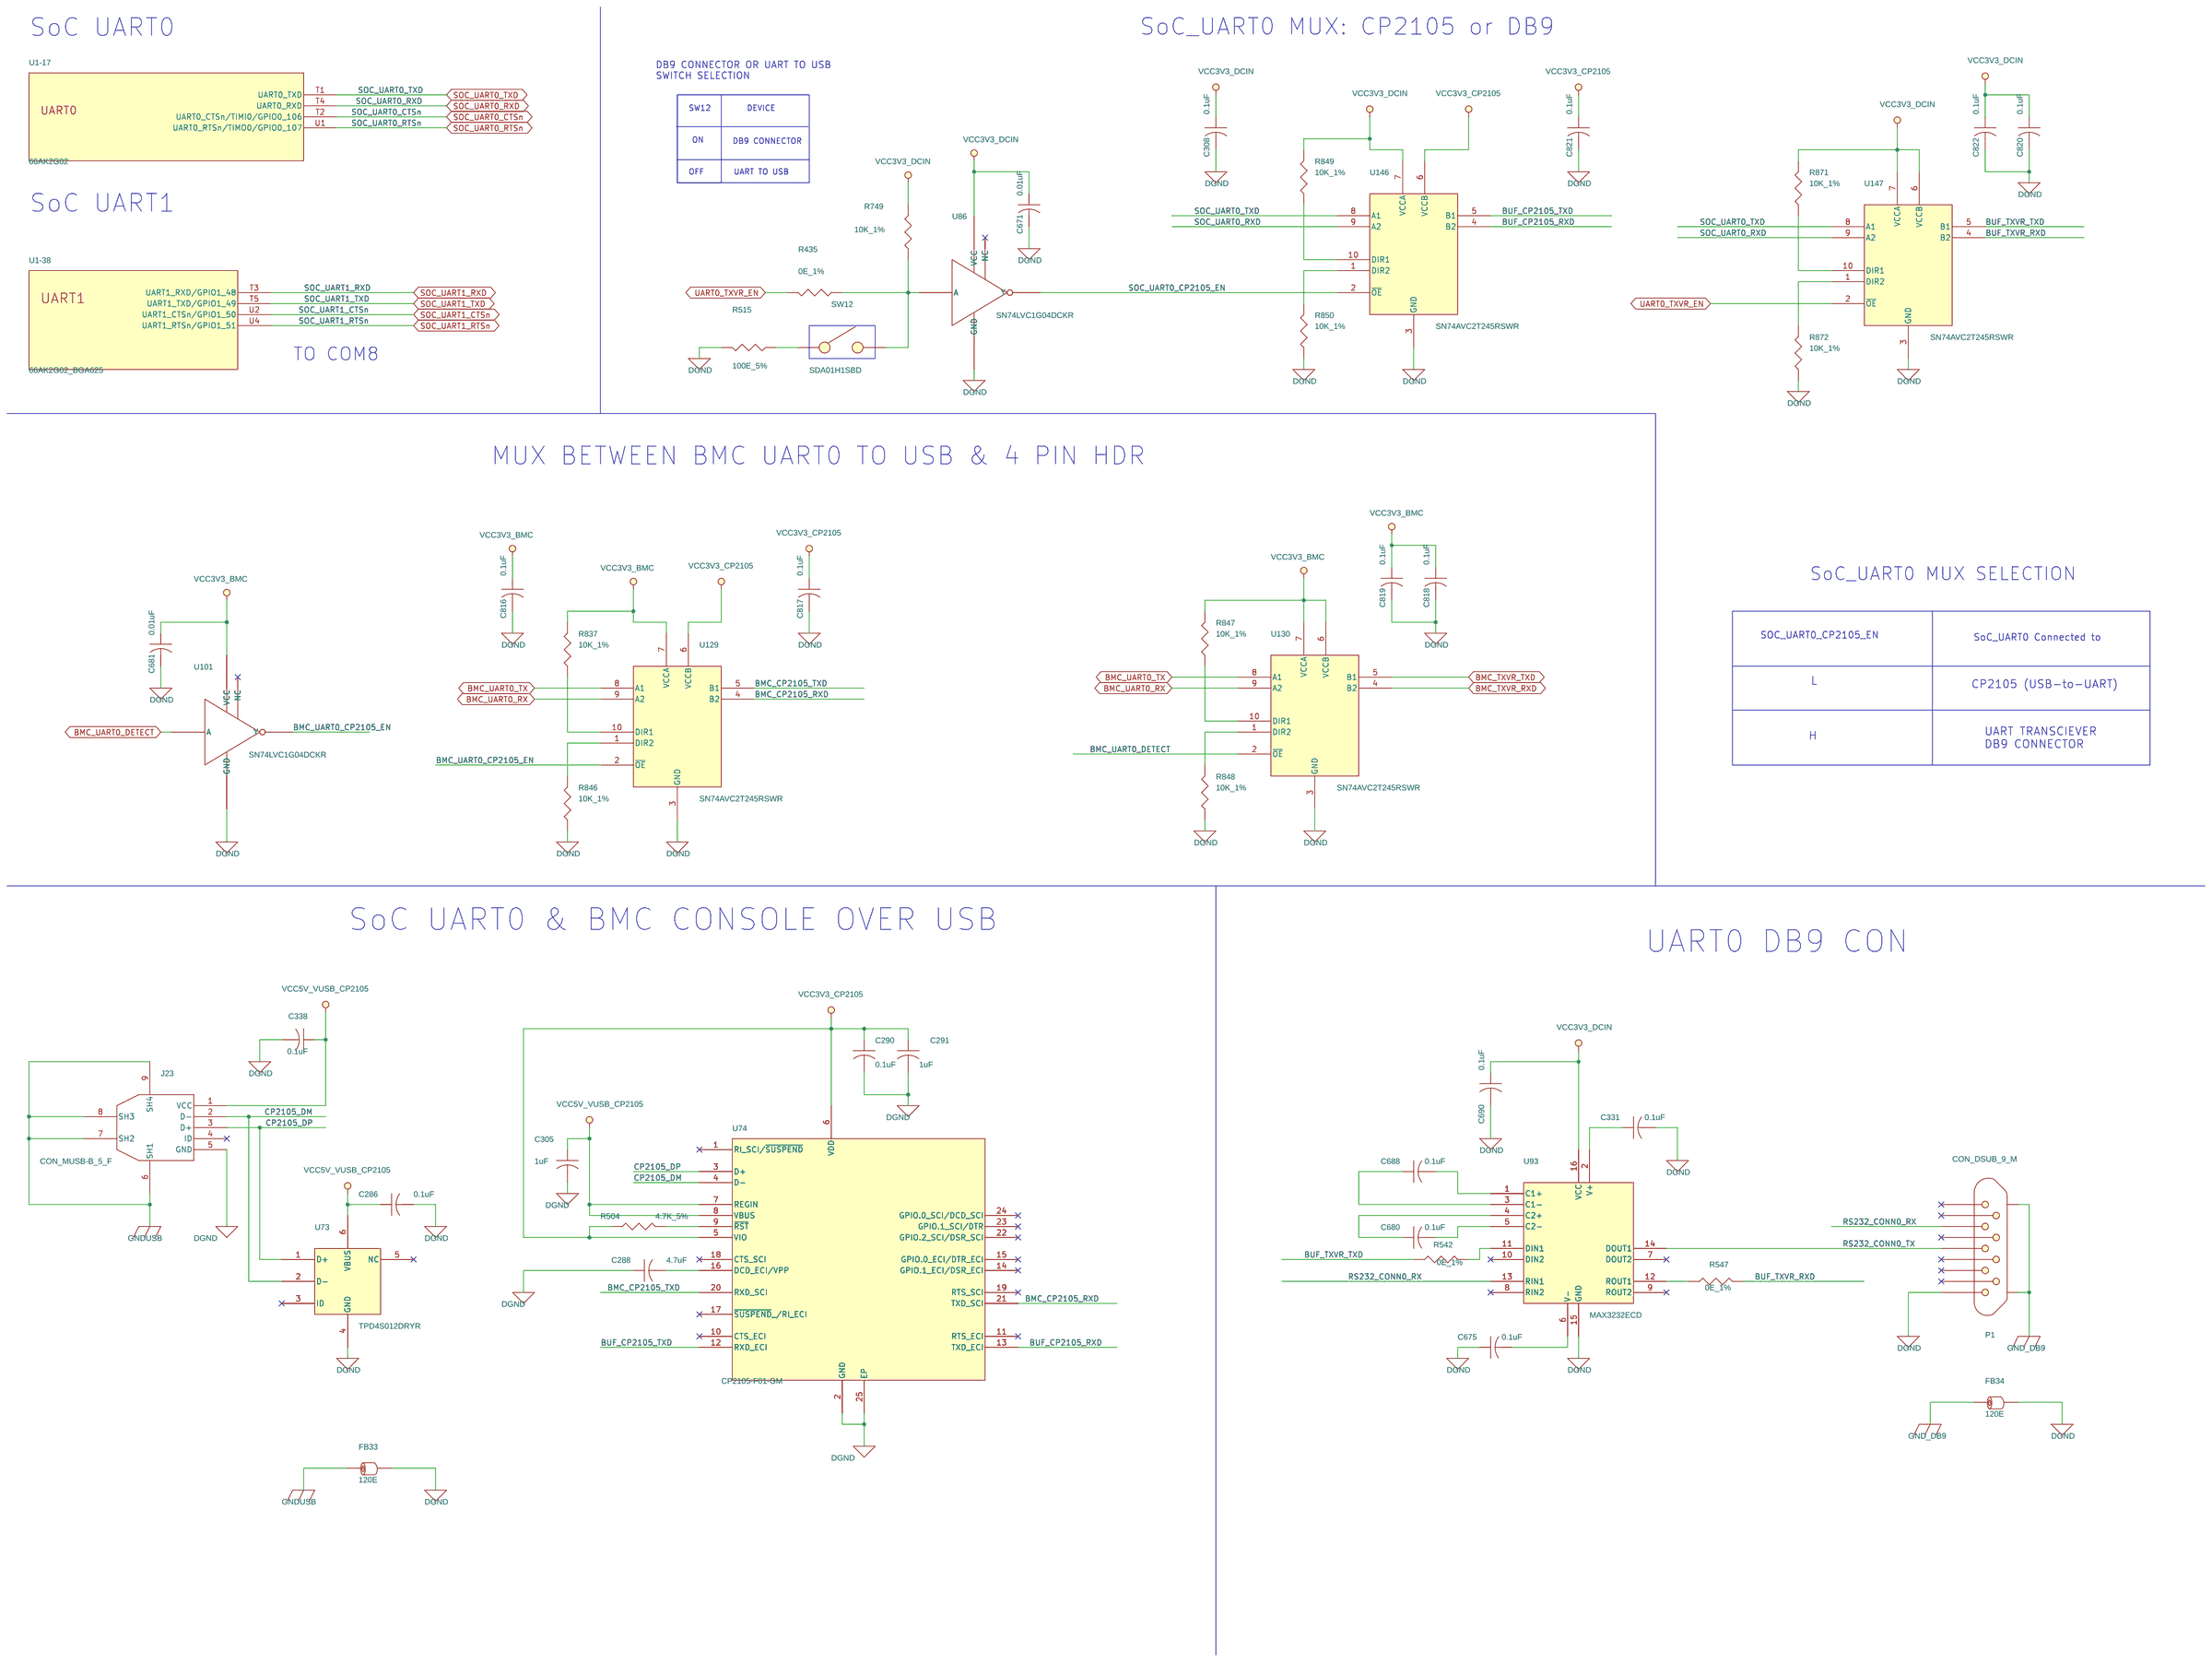
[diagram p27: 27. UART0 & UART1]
29 28. UART2: size C; title: UART2

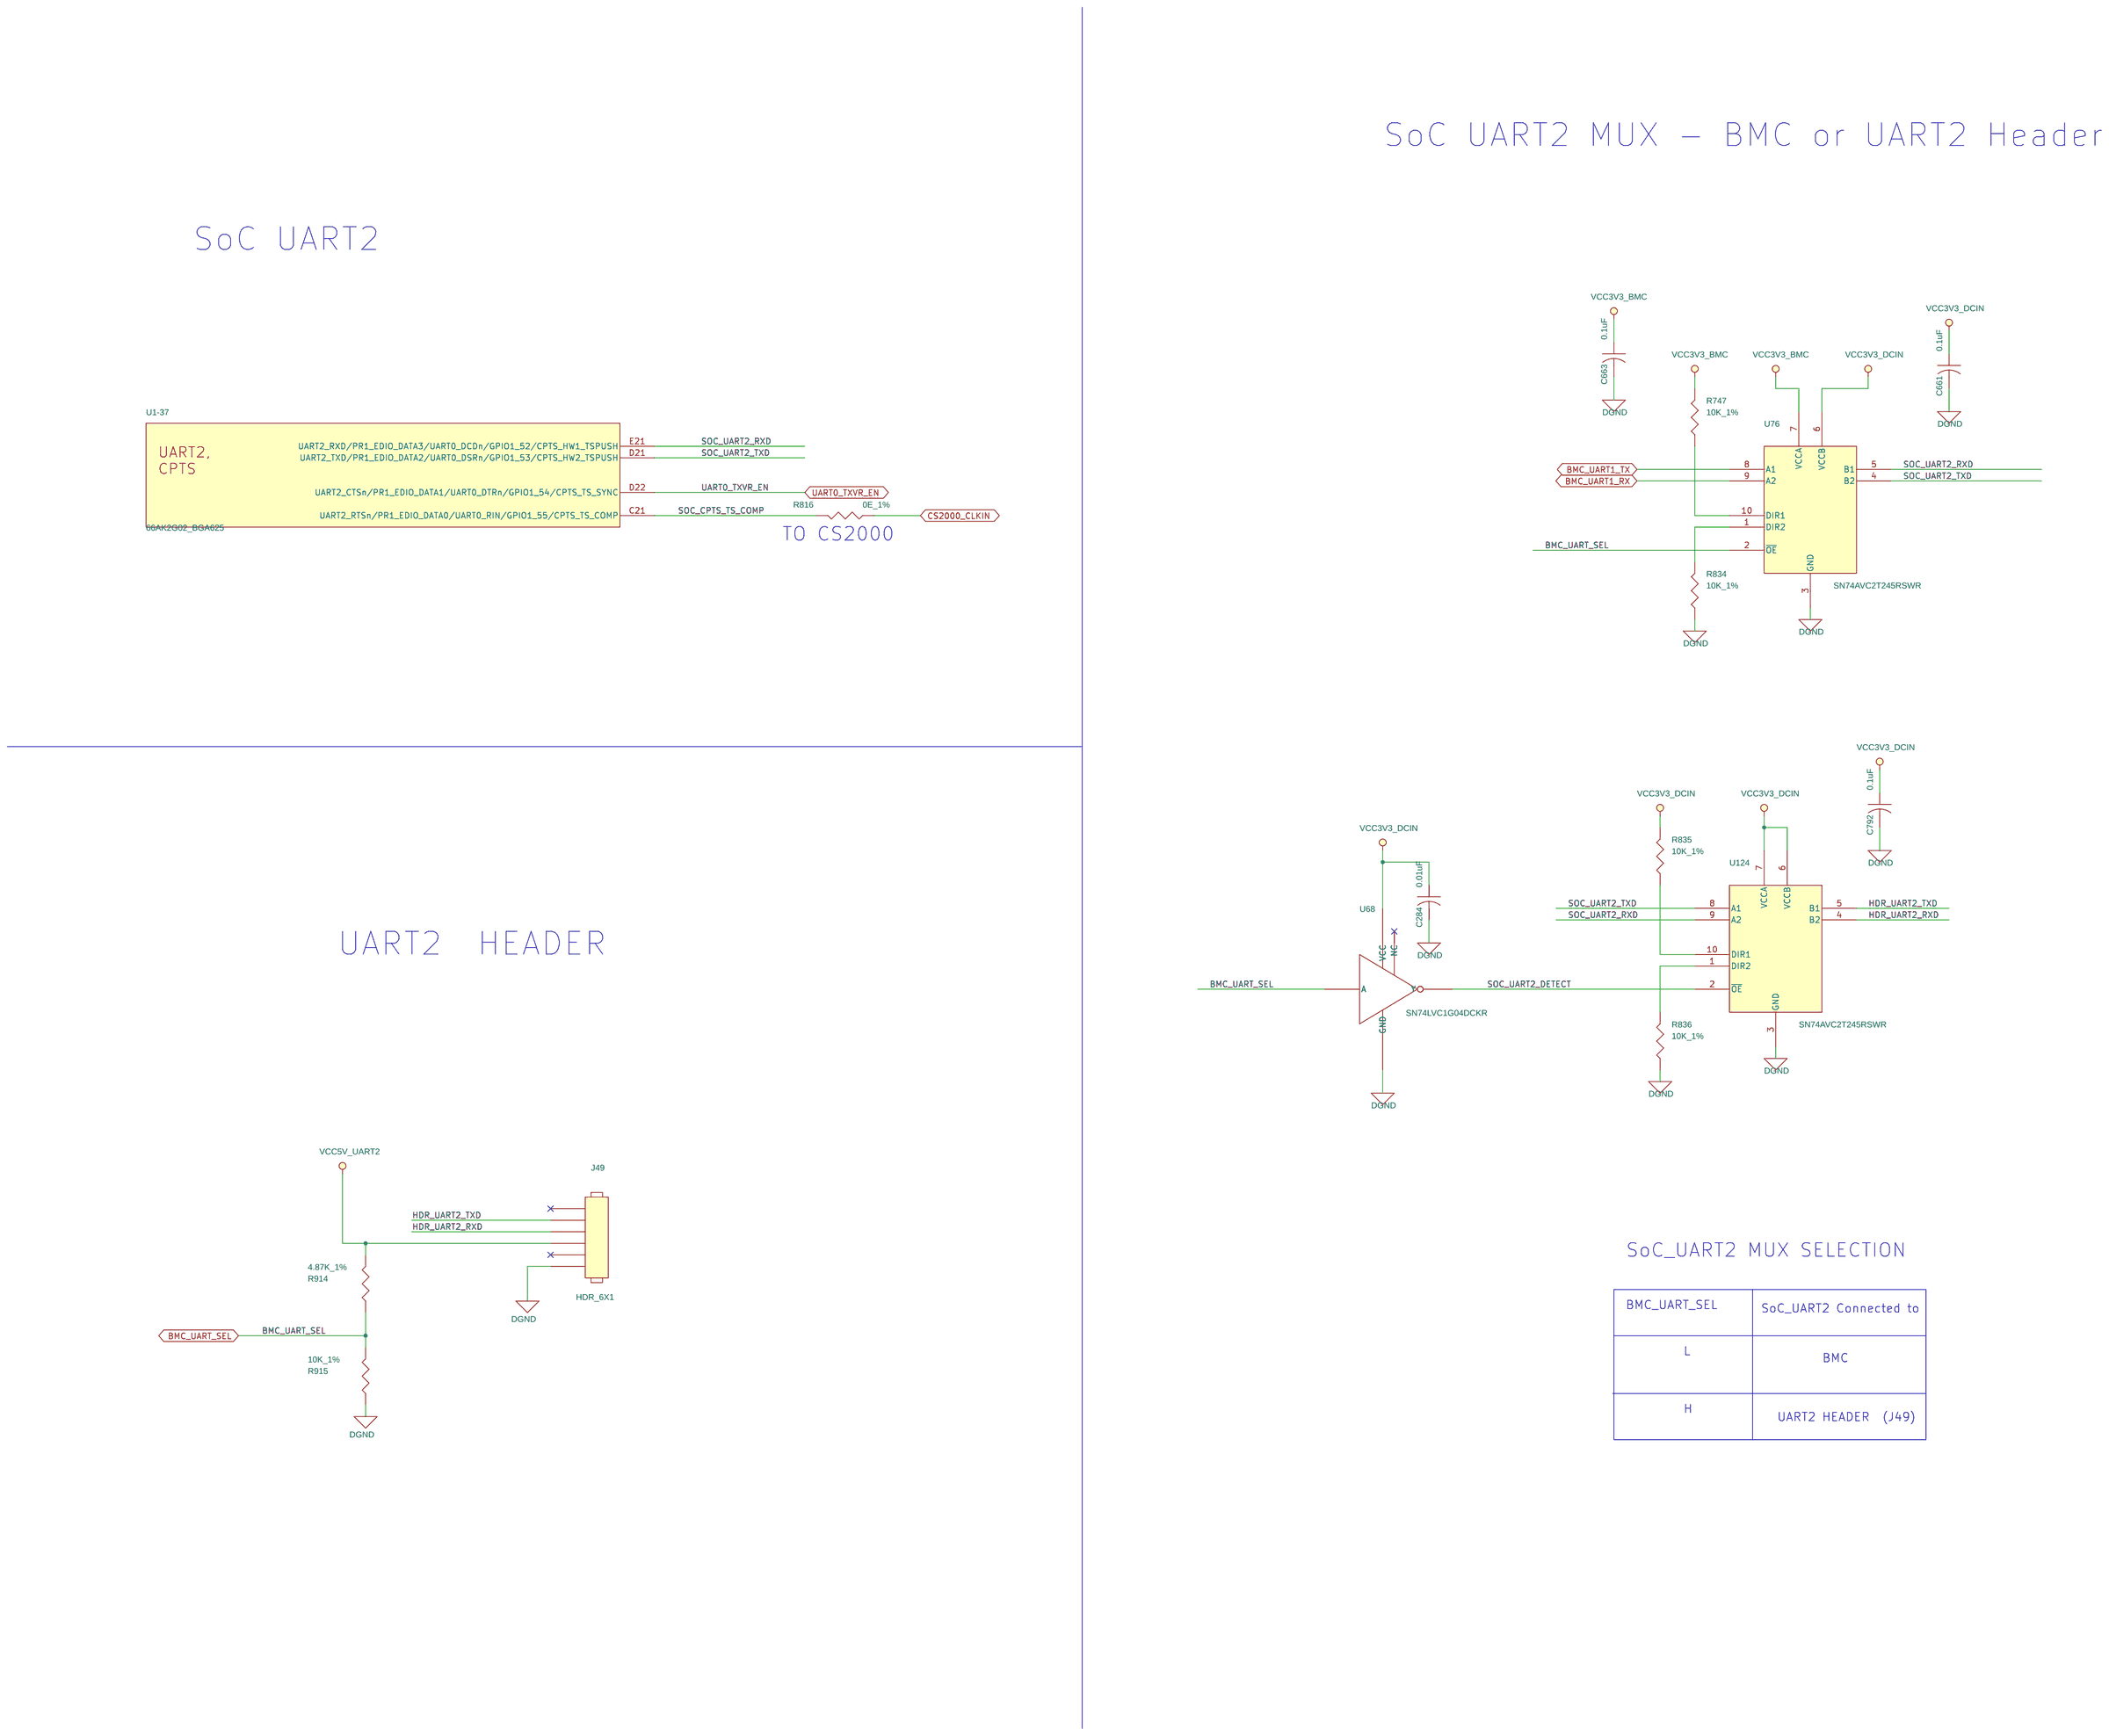
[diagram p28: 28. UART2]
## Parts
sheet 18. NAND FLASH & MICRO SD CARD
U1  66AK2G02_BGA625  [BGASKT625_31-49_1270x1270]  (sections -1,-10,-11,-12,-13,-14,-15,-16,-17,-18,-19,-2,-20,-21,-22,-23,-24,-25,-26,-27,-28,-29,-3,-30,-31,-32,-33,-34,-35,-36,-37,-38,-4,-5,-6,-7,-8,-9)
sheet 26. USB DUAL ROLE &  HOST
C51  120uF  [CAPAE_ECASE]
C348  120uF  [CAPAE_ECASE]
C350  4.7uF  [CAP0603]
C354  0.1uF  [CAP0402]
C355  4.7uF  [CAP0603]
C622  0.1uF  [CAP0402]
C634  0.1uF  [CAP0402]
D14  TPD2EUSB30DRTR  [SOT-3]
D15  TPD2EUSB30DRTR  [SOT-3]
FB44  120E  [IND0402]
FB45  120E  [IND0402]
FB46  120E  [IND0402]
FB47  120E  [IND0402]
J14  HDR_2X1  [HDR_2X1_100_S_T]
J30  HDR_2X1  [HDR_2X1_100_S_T]
J35  CON_USB-A_87583-2010BLF  [CON_USBA4_87583-2010_S_R_S]
J38  CON_USB-AB_5_M  [CON_USBAB5_ZX62_P_R_S]
L11  47nH  [FILTRER_COILCRAFT_0805]
L12  47nH  [FILTRER_COILCRAFT_0805]
R431  200E_1%  [RES0402]
R440  0E_1%  [RES0402]
R442  200E_1%  [RES0402]
R446  0E_1%  [RES0402]
R584  10K_1%  [RES0402]
R726  10K_1%  [RES0402]
R727  10K_1%  [RES0402]
R735  10K_1%  [RES0402]
R736  10K_1%  [RES0402]
U54  TPS2051BD  [SOIC8]
U57  TPS2051BD  [SOIC8]
U109  TPD4S012DRYR  [SON6_19-68_60X45]
sheet 27. UART0 & UART1
C286  0.1uF  [CAP0402]
C288  4.7uF  [CAP0603]
C290  0.1uF  [CAP0402]
C291  1uF  [CAP0402]
C305  1uF  [CAP0402]
C308  0.1uF  [CAP0402]
C331  0.1uF  [CAP0402]
C338  0.1uF  [CAP0402]
C671  0.01uF  [CAP0402]
C675  0.1uF  [CAP0402]
C680  0.1uF  [CAP0402]
C681  0.01uF  [CAP0402]
C688  0.1uF  [CAP0402]
C690  0.1uF  [CAP0402]
C816  0.1uF  [CAP0402]
C817  0.1uF  [CAP0402]
C818  0.1uF  [CAP0402]
C819  0.1uF  [CAP0402]
C820  0.1uF  [CAP0402]
C821  0.1uF  [CAP0402]
C822  0.1uF  [CAP0402]
FB33  120E  [IND0402]
FB34  120E  [IND0402]
J23  CON_MUSB-B_5_F  [CON_USBAB5_54819-0572_S_R_S]
P1  CON_DSUB_9_M  [CON_DB9_182-009-113R531_P_R_T]
R435  0E_1%  [RES0402]
R504  4.7K_5%  [RES0402]
R515  100E_5%  [RES0402]
R542  0E_1%  [RES0402]
R547  0E_1%  [RES0402]
R749  10K_1%  [RES0402]
R837  10K_1%  [RES0402]
R846  10K_1%  [RES0402]
R847  10K_1%  [RES0402]
R848  10K_1%  [RES0402]
R849  10K_1%  [RES0402]
R850  10K_1%  [RES0402]
R871  10K_1%  [RES0402]
R872  10K_1%  [RES0402]
SW12  SDA01H1SBD  [SW2_100X324-80_180X300_SMD]
U73  TPD4S012DRYR  [SON6_19-68_60X45]
U74  CP2105-F01-GM  [QFN24_19-68_160X160]
U86  SN74LVC1G04DCKR  [SC70-5]
U93  MAX3232ECD  [SOIC16]
U101  SN74LVC1G04DCKR  [SC70-5]
U129  SN74AVC2T245RSWR  [QFN10_15-74_75X60]
U130  SN74AVC2T245RSWR  [QFN10_15-74_75X60]
U146  SN74AVC2T245RSWR  [QFN10_15-74_75X60]
U147  SN74AVC2T245RSWR  [QFN10_15-74_75X60]
sheet 28. UART2
C284  0.01uF  [CAP0402]
C661  0.1uF  [CAP0402]
C663  0.1uF  [CAP0402]
C792  0.1uF  [CAP0402]
J49  HDR_6X1  [HDR_6X1_100_S_T]
R747  10K_1%  [RES0402]
R816  0E_1%  [RES0402]
R834  10K_1%  [RES0402]
R835  10K_1%  [RES0402]
R836  10K_1%  [RES0402]
R914  4.87K_1%  [RES0402]
R915  10K_1%  [RES0402]
U68  SN74LVC1G04DCKR  [SC70-5]
U76  SN74AVC2T245RSWR  [QFN10_15-74_75X60]
U124  SN74AVC2T245RSWR  [QFN10_15-74_75X60]

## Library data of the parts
U1 = 66AK2G02_BGA625: IC ARM CORTEX AND DSP 32 BIT MICROPROCESSOR BGA625; Chkd/date: NAVEED/141114; Color: Default; Crtd /date: VASANTHA/081014; Custom_Duty: 15%; Customs_HS_Code: 85423100; Distributor_name: NA; Distributor_part_number: NA; Height: 1.70MM; Location X-Coordinate: 0; Location Y-Coordinate: 0; Mfr_name: TEXAS INSTRUMENTS; Mfr_part_number: 66AK2G02; Mistral Part No: 141014100003; Package: BGA625; Part_type: ICS\DIGITAL\MICROPROCESSOR; Power Pins Visible: False; Primitive: DEFAULT; Project: GALILEO_EVM; Tolerance: NA; Voltage: NA; Wattage: NA; Weight: NA; Datasheet: Y:\MIS_DATABASE\DATASHEETS\ICS\DIGITAL\MICROCONTROLLER\SG-BGA-6094.PDF    Y:\MIS_DATABASE\DATASHEETS\ICS\DIGITAL\MICROCONTROLLER\SG-BGA_FP.PDF
C51 C348 = CAP_POL: CAP POLYMER 120uF 16V 20% ECASE_8383; Chkd/date: MAZHAR/160609; Crtd /date: USMAN/090609; Custom_Duty: 15%; Customs_HS_Code: 85322990; Distributor_name: DIGIKEY; Distributor_part_number: 493-3054-1-ND; Height: 8.10MM; Mfr_name: NICHICON; Mfr_part_number: PCJ1C121MCL1GS; Mistral Part No: 120009060010-R; Package: ECASE_8383; Part_type: CAPACITORS\POLYPROPYLENE; Project: BBB; RoHS: RoHS; Tolerance: 20%; Voltage: 16V; Datasheet: Y:\MIS_DATABASE\DATASHEETS\CAPACITORS\PCJSERIES.PDF
C288 C350 C355 = CAP: CAP CERAMIC 4.7uF 16V 10% X5R 0603; Chkd/date: VASANTHA/230714; Crtd /date: BAVISH/060511; Custom_Duty: 15%; Customs_HS_Code: 85322990; Distributor_name: DIGIKEY; Distributor_part_number: 587-2786-1-ND; Height: 0.90MM; Mfr_name: TAIYO YUDEN; Mfr_part_number: EMK107ABJ475KA-T; Mistral Part No: 120011050004-R; Package: 0603; Part_type: CAPACITORS\CERAMIC; Project: HMC; RoHS: RoHS; Temperature: -55°C+85°C; Tolerance: 10%; Voltage: 16V; Wattage: NA; Weight: NA; Datasheet: Y:\MIS_DATABASE\DATASHEETS\CAPACITORS\EMK107.PDF
C286 C290 C308 C331 C338 C354 C622 C634 C661 C663 C675 C680 C688 C690 C792 C816-C822 = CAP: CAP CERAMIC 0.1uF 16V 10% X7R 0402; Alternate_mfr_name_A: KEMET; Alternate_mfr_part_number_A: C0402C104K4RACT; Chkd/date: MAZHAR/281108; Crtd /date: MAZHAR/030907; Custom_Duty: 15%; Customs_HS_Code: 85322990; Distributor_name: DIGIKEY; Distributor_name_A: DIGIKEY; Distributor_part_number: 490-3261-1-ND; Distributor_part_number_A: 399-3521-1-ND; Height: 0.55MM; Mfr_name: MURATA; Mfr_part_number: GRM155R71C104KA88D; Mistral Part No: 120009030060-R; Package: 0402; Part_type: CAPACITORS\CERAMIC; Project: SMART VIEW_IP CAMERA; Tolerance: 10%; Voltage: 16V; Datasheet: Y:\MIS_DATABASE\DATASHEETS\CAPACITORS\GRM188SERIES.PDF
D14 D15 = TPD2EUSB30D_SOT-3: DIODE 2-CHANNEL ESD PROTECTION DIODES SOT-3; Chkd/date: JEBRAN/160215; Crtd /date: JEBRAN/160215; Custom_Duty: 15%; Customs_HS_Code: 85412900; Distributor_name: DIGIKEY; Distributor_part_number: 296-25509-1-ND; Height: 0.50MM; Mfr_name: TEXAS INSTRUMENTS; Mistral Part No: 130015070018-R; Part_type: DIODE\TVS; Project: GALILEO_EVM; RoHS: RoHS; Temperature: -40°C+85°C; Tolerance: NA; Voltage: NA; Wattage: NA; Weight: NA; Datasheet: Y:\MIS_DATABASE\DATASHEETS\DISCRETES\DIODES\TPD2EUSB30D.PDF
FB33 FB34 FB44-FB47 = INDUCTOR_FERRITE: IND BEAD CHIP 120E 1.2A 0402; Chkd/date: ASHOK/240212; Crtd /date: BAVISH/060711; Custom_Duty: 24%; Customs_HS_Code: 85437099; Distributor_name: DIGIKEY; Distributor_part_number: 445-2981-1-ND; Height: 0.55MM; Mfr_name: TDK CORPORATION; Mfr_part_number: MPZ1005S121C; Mistral Part No: 130011070007-R; Package: 0402; Part_type: INDUCTOR; Project: SVDU; RoHS: RoHS; Temperature: -40°C+85°C; Tolerance: NA; Voltage: NA; Wattage: NA; Weight: 1mg; Datasheet: Y:\MIS_DATABASE\DATASHEETS\DISCRETES\INDUCTORS\MPZ1005.PDF
J14 J30 = HEADER_2X1: CON HDR 2X1 2.54MM PITCH ST TH; ASSEMBLY_INSTRUCTION: DNI; Alternate_mfr_name_A: SULLINS ELECTRONICS; Alternate_mfr_name_B: SAMTEC; Alternate_mfr_name_C: HANTRONIX; Alternate_mfr_part_number_A: PZC02SAAN; Alternate_mfr_part_number_B: TLW-102-06-G-S; Alternate_mfr_part_number_C: HDM20216L; Chkd/date: SHREESHAIL/140206; Crtd /date: MAZHAR/280405; Custom_Duty: 24%; Customs_HS_Code: 85369090; Distributor_name: DIGIKEY; Distributor_part_number: WM4000-ND; Height: 10.79MM; Mfr_name: MOLEX; Mfr_part_number: 22-03-2021; Mistral Part No: 150009030246-R; Package: THRU-HOLE; Part_type: CONNECTOR\HEADERS; Project: FPGA EXTENDER CARD; RoHS: RoHS; Datasheet: Y:\MIS_DATABASE\DATASHEETS\CONNECTORS\HEADER_X4030.PDF
J35 = CON4_USB_A_USBR-A-S-S-O-TH: CON USB TYPE-A RECPT 4POS FLAG PCB FEMALE RT SMD; Chkd/date: JEBRAN/170215; Crtd /date: JEBRAN/170215; Custom_Duty: 24%; Customs_HS_Code: 85369090; Distributor_name: DIGIKEY; Distributor_part_number: 609-4413-ND; Height: 7.74MM; Mfr_name: FCI; Mfr_part_number: 87583-2010BLF; Mistral Part No: 150015070016-R; Package: SMD; Part_type: CONNECTOR\USB; Project: GALILEO_EVM; RoHS: RoHS; Temperature: NA; Tolerance: NA; Voltage: NA; Wattage: NA; Weight: NA; Datasheet: Y:\MIS_DATABASE\DATASHEETS\CONNECTORS\87583-2010BL.PDF
J38 = CON_USB_MINI-AB: CON RECEPTACLE USB 5POS MALE RT SMD; Chkd/date: USMAN/070612; Crtd /date: BAVISH/241210; Custom_Duty: 24%; Customs_HS_Code: 85369090; Distributor_name: DIGIKEY; Distributor_part_number: H11635CT-ND; Height: 2.80MM; Mfr_name: HRS; Mfr_part_number: ZX62-AB-5PA(11); Mistral Part No: 150010120015-R; Package: SMD; Part_type: CONNECTOR\USB; Project: EBOOK; RoHS: RoHS; Temperature: -30°C+85°C; Tolerance: NA; Voltage: NA; Wattage: NA; Weight: NA; Datasheet: Y:\MIS_DATABASE\DATASHEETS\CONNECTORS\ZX62-AB.PDF
L11 L12 = IND4_P12XS43: IND CHOKE 47nH SMD; Chkd/date: BAVISH/210311; Crtd /date: MAZHAR/110610; Custom_Duty: 24%; Customs_HS_Code: 85437099; Distributor_name: NA; Distributor_part_number: NA; Height: 1.65MM; Mfr_name: COIL CRAFT; Mfr_part_number: 0805USB-901MLB; Mistral Part No: 130010060008-R; Package: SMD; Part_type: INDUCTOR; Project: PCU; RoHS: RoHS; Temperature: -40°C+85°C; Tolerance: NA; Voltage: NA; Wattage: NA; Weight: 15.2mg; Datasheet: Y:\MIS_DATABASE\DATASHEETS\DISCRETES\INDUCTORS\0805USB.PDF
R431 R442 = RESISTOR: RES 200E 1/16W 1% 0402; Alternate_mfr_name_C: YAGEO AMERICA; Alternate_mfr_part_number_C: RC0402FR-07200RL; Chkd/date: MAZHAR/130709; Crtd /date: USMAN/060109; Custom_Duty: 15%; Customs_HS_Code: 85332119; Distributor_name: DIGIKEY; Distributor_name_C: NA; Distributor_part_number: 541-200LCT-ND; Distributor_part_number_C: NA; Height: 0.40MM; Mfr_name: VISHAY; Mfr_part_number: CRCW0402200RFKED; Mistral Part No: 110009030467-P; Package: 0402; Part_type: RESISTORS\FIXED; Project: OMAP_EVM; RoHS: Pb-Free; Tolerance: 1%; Wattage: 1/16W; Datasheet: Y:\MIS_DATABASE\DATASHEETS\RESISTORS\CRCW0603.PDF
R435 R440 R446 R542 R547 R816 = RESISTOR: RES 0E 1/16W 1% 0402; Chkd/date: MAZHAR/220709; Crtd /date: USMAN/270109; Custom_Duty: 15%; Customs_HS_Code: 85332119; Distributor_name: NA; Distributor_part_number: NA; Height: 0.40MM; Mfr_name: YAGEO AMERICA; Mfr_part_number: RC0402FR-070RL; Mistral Part No: 110009030085-P; Package: 0402; Part_type: RESISTORS\FIXED; Project: OMAP_EVM; RoHS: Pb-Free; Tolerance: 1%; Wattage: 1/16W; Datasheet: Y:\MIS_DATABASE\DATASHEETS\RESISTORS\CRCW0603.PDF
R584 = RESISTOR: RES 10K 1/16W 1% 0402; Alternate_mfr_name_A: AVX CORPORATION; Alternate_mfr_name_B: PANASONIC-ECG-ECG; Alternate_mfr_name_C: YAGEO AMERICA; Alternate_mfr_name_D: VISHAY; Alternate_mfr_part_number_A: CR05-103F-H; Alternate_mfr_part_number_B: ERJ-2RKF1002X; Alternate_mfr_part_number_C: 9C04021A1002FLHF3; Alternate_mfr_part_number_D: CRCW040210K0FKED; Chkd/date: SHREESHAIL/310506; Crtd /date: GEETHA/290506; Custom_Duty: 15%; Customs_HS_Code: 85332119; Distributor_name: DIGIKEY; Distributor_name_A: NA; Distributor_name_B: DIGIKEY; Distributor_name_C: DIGIKEY; Distributor_name_D: DIGIKEY; Distributor_part_number: 311-10.0KLRTR-ND; Distributor_part_number_A: NA; Distributor_part_number_B: P10.0KLCT-ND; Distributor_part_number_C: 311-10.0KLCT-ND; Distributor_part_number_D: 541-10.0KLCT-ND; Height: 0.40MM; Loading: DNI; Mfr_name: YAGEO AMERICA; Mfr_part_number: RC0402FR-0710KL; Mistral Part No: 110009030220-P; Package: 0402; Part_type: RESISTORS\FIXED; Project: VOCERA; RoHS: Pb-Free; Tolerance: 1%; Wattage: 1/16W; Datasheet: Y:\MIS_DATABASE\DATASHEETS\RESISTORS\YAGEO-RC0402.PDF
R726 R727 R735 R736 R747 R749 R834-R837 R846-R850 R871 R872 R915 = RESISTOR: RES 10K 1/16W 1% 0402; Alternate_mfr_name_A: AVX CORPORATION; Alternate_mfr_name_B: PANASONIC-ECG-ECG; Alternate_mfr_name_C: YAGEO AMERICA; Alternate_mfr_name_D: VISHAY; Alternate_mfr_part_number_A: CR05-103F-H; Alternate_mfr_part_number_B: ERJ-2RKF1002X; Alternate_mfr_part_number_C: 9C04021A1002FLHF3; Alternate_mfr_part_number_D: CRCW040210K0FKED; Chkd/date: SHREESHAIL/310506; Crtd /date: GEETHA/290506; Custom_Duty: 15%; Customs_HS_Code: 85332119; Distributor_name: DIGIKEY; Distributor_name_A: NA; Distributor_name_B: DIGIKEY; Distributor_name_C: DIGIKEY; Distributor_name_D: DIGIKEY; Distributor_part_number: 311-10.0KLRTR-ND; Distributor_part_number_A: NA; Distributor_part_number_B: P10.0KLCT-ND; Distributor_part_number_C: 311-10.0KLCT-ND; Distributor_part_number_D: 541-10.0KLCT-ND; Height: 0.40MM; Mfr_name: YAGEO AMERICA; Mfr_part_number: RC0402FR-0710KL; Mistral Part No: 110009030220-P; Package: 0402; Part_type: RESISTORS\FIXED; Project: VOCERA; RoHS: Pb-Free; Tolerance: 1%; Wattage: 1/16W; Datasheet: Y:\MIS_DATABASE\DATASHEETS\RESISTORS\YAGEO-RC0402.PDF
U54 U57 = TPS2051BD_SOIC8: IC POWER DISTRIBUTION SWITCH SOIC8; Chkd/date: NAVEED/150714; Crtd /date: VASANTHA/190614; Custom_Duty: 15%; Customs_HS_Code: 85423100; Distributor_name: DIGIKEY; Distributor_part_number: 296-26911-5-ND; Height: 1.75MM; Mfr_name: TEXAS INSTRUMENTS; Mistral Part No: 142014060011-R; Part_type: ICS\POWER; Project: AEGIS_POM; RoHS: RoHS; Temperature: -40°C+125°C; Tolerance: NA; Voltage: NA; Wattage: NA; Weight: NA; Datasheet: Y:\MIS_DATABASE\DATASHEETS\MISC\REGULATORS\TPS2051BDBVR.PDF
U73 U109 = TPD4S012DRY_SON6: IC 4CH ESD SOLUTION SON6; Chkd/date: Vinitha/291211; Crtd /date: BAVISH/190811; Custom_Duty: 15%; Customs_HS_Code: 85423100; Distributor_name: DIGIKEY; Distributor_part_number: 296-24244-1-ND; Height: 0.60MM; Mfr_name: TEXAS INSTRUMENTS; Mistral Part No: 141011080022; Package: SON6; Part_type: ICS\INTERFACE; Project: ACRO_DM3730; RoHS: NA; Temperature: -40°C+85°C; Tolerance: NA; Voltage: NA; Wattage: NA; Weight: NA; Datasheet: Y:\MIS_DATABASE\DATASHEETS\ICS\INTERFACE\TPD4S012.PDF
C291 C305 = CAP: CAP CERAMIC 1uF 10V 10% X5R 0402; Chkd/date: BALACHANDAR/160514; Crtd /date: SARANYA/060514; Custom_Duty: 15%; Customs_HS_Code: 85322990; Distributor_name: DIGIKEY; Distributor_part_number: 478-4596-1-ND; Height: 0.56MM; Mfr_name: AVX CORPORATION; Mfr_part_number: 0402ZD105KAT2A; Mistral Part No: 120014050010-R; Package: 0402; Part_type: CAPACITORS\CERAMIC; Project: AEGIS GP BETA2; RoHS: RoHS; Temperature: -55°C+85°C; Tolerance: 10%; Voltage: 10V; Wattage: NA; Weight: NA; Datasheet: Y:\MIS_DATABASE\DATASHEETS\CAPACITORS\AVX_MLC.PDF
C284 C671 C681 = CAP: CAP CERAMIC 0.01uF 16V 10% X7R 0402; Alternate_mfr_name_A: AVX CORPORATION; Alternate_mfr_name_B: KEMET; Alternate_mfr_name_D: TDK CORPORATION; Alternate_mfr_part_number_A: 0402YC103KAT2A; Alternate_mfr_part_number_B: C0402C103K4RACTU; Alternate_mfr_part_number_D: C1005X7R1C103K; Chkd/date: SHREESHAIL/180506; Crtd /date: MAZHAR/110506; Custom_Duty: 15%; Customs_HS_Code: 85322990; Distributor_name: DIGIKEY; Distributor_name_A: DIGIKEY; Distributor_name_B: DIGIKEY; Distributor_name_D: DIGIKEY; Distributor_part_number: PCC103BQCT-ND; Distributor_part_number_A: 478-1114-1-ND; Distributor_part_number_B: 399-1038-1-ND; Distributor_part_number_D: 445-1262-1-ND; Height: 0.55MM; Mfr_name: PANASONIC-ECG; Mfr_part_number: ECJ-0EB1C103K; Mistral Part No: 120009030032-R; Package: 0402; Part_type: CAPACITORS\CERAMIC; Project: VOCERA; RoHS: RoHS; Tolerance: 10%; Voltage: 16V; Datasheet: Y:\MIS_DATABASE\DATASHEETS\CAPACITORS\PAN-ECJ.PDF
J23 = CON_USB_MINI-AB: CON MINI USB-B TYPE 5POS FEMALE RT SMD; Chkd/date: SHREESHAIL/280206; Crtd /date: MAZHAR/300605; Custom_Duty: 24%; Customs_HS_Code: 85369090; Distributor_name: DIGIKEY; Distributor_part_number: WM17116CT-ND; Height: 3.95MM; Mfr_name: MOLEX; Mfr_part_number: 54819-0572; Mistral Part No: 150009030728; Package: SMD; Part_type: CONNECTOR\USB; Project: PMP; Datasheet: Y:\MIS_DATABASE\DATASHEETS\CONNECTORS\548190572.PDF
P1 = CON_DSUB_9_M: CON DSUB 9POS MALE RT TH; Chkd/date: RAGESH/140311; Crtd /date: MAZHAR/231007; Custom_Duty: 24%; Customs_HS_Code: 85369090; Distributor_name: DIGIKEY; Distributor_part_number: 182-09ME-ND; Height: 12.55MM; Mfr_name: NORCOMP; Mfr_part_number: 182-009-113R531; Mistral Part No: 150009030096-R; Package: THRU-HOLE; Part_type: CONNECTOR\DSUB; Project: SMART VIEW_IP CAMERA; RoHS: RoHS; Temperature: -55° C to +105° C; Datasheet: Y:\MIS_DATABASE\DATASHEETS\CONNECTORS\182-009.PDF
R504 = RESISTOR: RES 4.7K 1/16W 5% 0402; Chkd/date: VASANTHA/190614; Crtd /date: NAVEED/160614; Custom_Duty: 15%; Customs_HS_Code: 85332119; Distributor_name: DIGIKEY; Distributor_part_number: RMCF0402JT4K70CT-ND; Height: 0.40MM; Mfr_name: STACKPOLE ELECTRONICS; Mfr_part_number: RMCF0402JT4K70; Mistral Part No: 110014060028-R; Package: 0402; Part_type: RESISTORS\FIXED; Project: AEGIS_POM; RoHS: RoHS; Temperature: -55°C+155°C; Tolerance: 5%; Voltage: NA; Wattage: 1/16W; Weight: NA; Datasheet: Y:\MIS_DATABASE\DATASHEETS\RESISTORS\RMCF-SERIES1.PDF
R515 = RESISTOR: RES 100E 1/16W 5% 0402; Chkd/date: VASANTHA/200614; Crtd /date: NAVEED/170614; Custom_Duty: 15%; Customs_HS_Code: 85332119; Distributor_name: DIGIKEY; Distributor_part_number: RMCF0402JT100RCT-ND; Height: 0.40MM; Mfr_name: STACKPOLE ELECTRONICS; Mfr_part_number: RMCF0402JT100R; Mistral Part No: 110014060039-R; Package: 0402; Part_type: RESISTORS\FIXED; Project: AEGIS_POM; RoHS: RoHS; Temperature: -55°C+155°C; Tolerance: 5%; Voltage: NA; Wattage: 1/16W; Weight: NA; Datasheet: Y:\MIS_DATABASE\DATASHEETS\RESISTORS\RMCF-SERIES1.PDF
SW12 = SW2: SWITCH DIP SPST LOW PROFILE SMD; Chkd/date: SARANYA/110314; Crtd /date: JAGADISH/280214; Custom_Duty: 24%; Customs_HS_Code: 85369090; Distributor_name: DIGIKEY; Distributor_part_number: CKN10358-ND; Height: 4.45MM; Mfr_name: C&K COMPONENTS; Mistral Part No: 130014030014-R; Package: SMD; Part_type: ELECTRO-MECHANICAL\SWITCH; Project: DMP; RoHS: RoHS; Temperature: -40°C+85°C; Tolerance: NA; Voltage: NA; Wattage: NA; Weight: NA; Datasheet: Y:\MIS_DATABASE\DATASHEETS\MISC\SWITCHES\SDAXXX_SERIES.PDF
U74 = CP2105-F01-GM_QFN24: IC SINGLE CHIP USB TO DUAL UART BRIDGE QFN24; Chkd/date: JEBRAN/280215; Crtd /date: JEBRAN/280215; Custom_Duty: 15%; Customs_HS_Code: 85423100; Distributor_name: DIGIKEY; Distributor_part_number: 336-2009-5-ND; Height: 0.80MM; Mfr_name: SILICON LABS; Mistral Part No: 141015070007-R; Package: QFN24; Part_type: ICS\DIGITAL\PERIPHERAL; Project: GALILEO_EVM; RoHS: RoHS; Temperature: -40°C+85°C; Tolerance: NA; Voltage: NA; Wattage: NA; Weight: NA; Datasheet: Y:\MIS_DATABASE\DATASHEETS\ICS\DIGITAL\PERIPHERAL\CP2105-F01-GM.PDF
U68 U86 U101 = SN74LVC1G04DCKR_SC70-5: IC SINGLE INVERTER GATE SC70-5; Chkd/date: SUHAS/221010; Crtd /date: USMAN/150709; Custom_Duty: 15%; Customs_HS_Code: 85423100; Distributor_name: DIGIKEY; Distributor_part_number: 296-11600-1-ND; Height: 1.10MM; Mfr_name: TEXAS INSTRUMENTS; Mistral Part No: 141009070007-R; Part_type: ICS\DIGITAL\GATES; Project: BUG_BASE-II; RoHS: Sb/ Br FREE; Temperature: -40°C+85°C; Datasheet: Y:\MIS_DATABASE\DATASHEETS\ICS\DIGITAL\GATES\SN74LVC1G04-1.PDF
U93 = MAX3232CDR_SOIC16: IC MULTICHANNEL RS-232 LINE DRIVER/RECEIVER SOIC16; Chkd/date: VASANTHA/150714; Crtd /date: NAVEED/170614; Custom_Duty: 15%; Customs_HS_Code: 85423100; Distributor_name: DIGIKEY; Distributor_part_number: 296-26154-5-ND; Height: 1.75MM; Mfr_name: TEXAS INSTRUMENTS; Mistral Part No: 141214070001-R; Part_type: ICS\INTERFACE\LINE DRIVER; Project: AEGIS_POM; RoHS: Sb/ Br FREE; Temperature: 0°C+70°C; Tolerance: NA; Voltage: NA; Wattage: NA; Weight: NA; Datasheet: Y:\MIS_DATABASE\DATASHEETS\ICS\INTERFACE\MAX3232E.PDF
U76 U124 U129 U130 U146 U147 = SN74AVC2T245RSWR_QFN10: IC DUAL-BIT DUAL SUPPLY BUS TRANSCEIVER QFN10; Chkd/date: SUHAS/031110; Crtd /date: USMAN/130309; Custom_Duty: 15%; Customs_HS_Code: 85423100; Distributor_name: DIGIKEY; Distributor_part_number: 296-23684-1-ND; Height: 0.55MM; Mfr_name: TEXAS INSTRUMENTS; Mistral Part No: 143009030061-R; Package: QFN10; Part_type: ICS\TELECOM\TRANSCEIVER; Project: AXON; RoHS: Sb/ Br FREE; Temperature: -40°C+85°C; Datasheet: Y:\MIS_DATABASE\DATASHEETS\ICS\DIGITAL\BUSTRANSCEIVER\SN74AVC2T245RSWR.PDF
J49 = HEADER_6X1: CON HDR 6X1 2.54MM PITCH ST TH; Chkd/date: MAZHAR/100311; Crtd /date: BAVISH/210111; Custom_Duty: 24%; Customs_HS_Code: 85369090; Distributor_name: DIGIKEY; Distributor_part_number: A26551-ND; Height: 10.79MM; Mfr_name: TYCO ELECTRONICS; Mfr_part_number: 87224-6; Mistral Part No: 150011010025-R; Package: THRU-HOLE; Part_type: CONNECTOR\HEADERS; Project: OMAPL1_PEC20; RoHS: RoHS; Temperature: NA; Tolerance: NA; Voltage: NA; Wattage: NA; Weight: NA; Datasheet: Y:\MIS_DATABASE\DATASHEETS\CONNECTORS\87224-6.PDF
R914 = RESISTOR: RES 4.87K 1/16W 1% 0402; Chkd/date: MAZHAR/150709; Crtd /date: USMAN/150109; Custom_Duty: 15%; Customs_HS_Code: 85332119; Distributor_name: DIGIKEY; Distributor_part_number: P4.87KLCT-ND; Height: 0.40MM; Mfr_name: PANASONIC-ECG; Mfr_part_number: ERJ2RKF4871X; Mistral Part No: 110009030803-R; Package: 0402; Part_type: RESISTORS\FIXED; Project: BSN-II; RoHS: RoHS; Tolerance: 1%; Wattage: 1/16W; Datasheet: Y:\MIS_DATABASE\DATASHEETS\RESISTORS\PAN-ERJSERIES.PDF

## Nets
DGND: C51.2 C284.2 C286.2 C288.1 C290.2 C291.2 C305.2 C308.2 C331.2 C338.2 C348.2 C350.2 C354.1 C355.2 C622.2 C634.2 C661.2 C663.2 C671.2 C675.1 C681.2 C690.2 C792.2 C816.2 C817.2 C818.2 C819.2 C820.2 C821.2 C822.2 D14.3(GND) D15.3(GND) FB33.2 FB34.2 FB44.1 FB46.1 J23.5(GND) J35.4 J38.5(GND) J49.1 P1.5 R431.1 R440.1 R442.1 R515.2 R584.1 R727.1 R736.1 R834.1 R836.1 R846.1 R848.1 R850.1 R872.1 R915.1 U54.1(GND) U57.1(GND) U68.3(GND) U73.4(GND) U74.2(GND) U74.25(EP) U76.3(GND) U86.3(GND) U93.15(GND) U101.3(GND) U109.4(GND) U124.3(GND) U129.3(GND) U130.3(GND) U146.3(GND) U147.3(GND) ; also on sheet 1 11 12 13 14 15 16 17 18 19 20 21 22 23 24 25 26 30 31 32 33 34 35 36 37 38 39 40 41 42 43 44 45 46 47 48 49 50
GND_DB9: FB34.1 P1.10 P1.11
GNDUSB: FB33.1 J23.6(SH1) J23.7(SH2) J23.8(SH3) J23.9(SH4)
GNDUSB0: FB44.2 J35.5(SH1) J35.6(SH2)
GNDUSB1: FB46.2 J38.6(SH1) J38.7(SH2) J38.8(SH3) J38.9(SH4)
VCC3V3_BMC: C663.1 C681.1 C816.1 C818.1 C819.1 R747.2 R837.2 R847.2 U76.7(VCCA) U101.5(VCC) U129.7(VCCA) U130.6(VCCB) U130.7(VCCA) ; also on sheet 13 37 38 45 46 47 50
VCC3V3_CP2105: C290.1 C291.1 C817.1 C821.1 R504.1 U74.5(VIO) U74.6(VDD) U129.6(VCCB) U146.6(VCCB)
VCC3V3_DCIN: C284.1 C308.1 C661.1 C671.1 C690.1 C792.1 C820.1 C822.1 R726.1 R735.2 R749.2 R835.2 R849.2 R871.2 U68.5(VCC) U76.6(VCCB) U86.5(VCC) U93.16(VCC) U124.6(VCCB) U124.7(VCCA) U146.7(VCCA) U147.6(VCCB) U147.7(VCCA) ; also on sheet 11 17 18 19 20 21 22 23 24 25 26 30 31 32 33 34 35 36 37 38 43 44 45 46 47 48 50
VCC5V0_DCDC: C622.1 C634.1 U54.2(IN1) U54.3(IN2) U57.2(IN1) U57.3(IN2) ; also on sheet 21 22 30 44 46 48 49 50
VCC5V0_USB0_PM: FB45.1 U1.B19(USB0_VBUS) U54.6(OUT1) U54.7(OUT2) U54.8(OUT3)
VCC5V0_USB1_PM: FB47.1 U1.A21(USB1_VBUS) U57.6(OUT1) U57.7(OUT2) U57.8(OUT3)
VCC5V_UART2: J49.3 R914.1
VCC5V_VUSB_CP2105: C286.1 C305.1 C338.1 J23.1(VCC) U73.6(VBUS) U74.7(REGIN) U74.8(VBUS)
BMC_CP2105_RXD: U74.21(TXD_SCI) U129.4(B2)
BMC_CP2105_TXD: U74.20(RXD_SCI) U129.5(B1)
BMC_TXVR_RXD: U130.4(B2) ; also on sheet 45
BMC_TXVR_TXD: U130.5(B1) ; also on sheet 45
BMC_UART0_CP2105_EN: U101.4(Y) U129.2(~{OE})
BMC_UART0_DETECT: U101.2(A) U130.2(~{OE}) ; also on sheet 45 46
BMC_UART0_RX: U129.9(A2) U130.9(A2) ; also on sheet 45
BMC_UART0_TX: U129.8(A1) U130.8(A1) ; also on sheet 45
BMC_UART1_RX: U76.9(A2) ; also on sheet 47
BMC_UART1_TX: U76.8(A1) ; also on sheet 47
BMC_UART_SEL: R914.2 R915.2 U68.2(A) U76.2(~{OE}) ; also on sheet 46
BUF_CP2105_RXD: U74.13(TXD_ECI) U146.4(B2)
BUF_CP2105_TXD: U74.12(RXD_ECI) U146.5(B1)
BUF_TXVR_RXD: R547.2 U147.4(B2)
BUF_TXVR_TXD: R542.1 U147.5(B1)
CP2105_DM: J23.2(D-) U73.2(D-) U74.4(D-)
CP2105_DP: J23.3(D+) U73.1(D+) U74.3(D+)
CS2000_CLKIN: R816.1 ; also on sheet 33 37
HDR_UART2_RXD: J49.4 U124.4(B2)
HDR_UART2_TXD: J49.5 U124.5(B1)
RS232_CONN0_RX: P1.2 U93.13(RIN1)
RS232_CONN0_TX: P1.3 U93.14(DOUT1)
SOC_CPTS_TS_COMP: R816.2 U1.C21(UART2_RTSn/PR1_EDIO_DATA0/UART0_RIN/GPIO1_55/CPTS_TS_COMP)
SOC_UART0_CP2105_EN: U86.4(Y) U146.2(~{OE})
SOC_UART0_CTSn: U1.T2(UART0_CTSn/TIMI0/GPIO0_106) ; also on sheet 34
SOC_UART0_RTSn: U1.U1(UART0_RTSn/TIMO0/GPIO0_107) ; also on sheet 34
SOC_UART0_RXD: U1.T4(UART0_RXD) U146.9(A2) U147.9(A2) ; also on sheet 34
SOC_UART0_TXD: U1.T1(UART0_TXD) U146.8(A1) U147.8(A1) ; also on sheet 34
SOC_UART1_CTSn: U1.U2(UART1_CTSn/GPIO1_50) ; also on sheet 30
SOC_UART1_RTSn: U1.U4(UART1_RTSn/GPIO1_51) ; also on sheet 30
SOC_UART1_RXD: U1.T3(UART1_RXD/GPIO1_48) ; also on sheet 30
SOC_UART1_TXD: U1.T5(UART1_TXD/GPIO1_49) ; also on sheet 30
SOC_UART2_DETECT: U68.4(Y) U124.2(~{OE})
SOC_UART2_RXD: U1.E21(UART2_RXD/PR1_EDIO_DATA3/UART0_DCDn/GPIO1_52/CPTS_HW1_TSPUSH) U76.5(B1) U124.9(A2)
SOC_UART2_TXD: U1.D21(UART2_TXD/PR1_EDIO_DATA2/UART0_DSRn/GPIO1_53/CPTS_HW2_TSPUSH) U76.4(B2) U124.8(A1)
SOC_USB0_DM: L12.1 U1.B18(USB0_DM)
SOC_USB0_DP: L12.4 U1.A18(USB0_DP)
SOC_USB0_ID: R440.2 U1.A19(USB0_ID)
SOC_USB0_VBUSEN: R727.2 U1.E19(USB0_DRVVBUS) U54.4(EN)
SOC_USB1_DM: L11.1 U1.A20(USB1_DM)
SOC_USB1_DP: L11.4 U1.B20(USB1_DP)
SOC_USB1_ID: R446.1 U1.E20(USB1_ID)
SOC_USB1_VBUSEN: R736.2 U1.B21(USB1_DRVVBUS) U57.4(EN)
UART0_TXVR_EN: R435.2 U1.D22(UART2_CTSn/PR1_EDIO_DATA1/UART0_DTRn/GPIO1_54/CPTS_TS_SYNC) U147.2(~{OE})
USB0_CONN_DM: D15.1(D+) J35.2 L12.2
USB0_CONN_DP: D15.2(D-) J35.3 L12.3
USB1_CONN_DM: D14.1(D+) J38.2(D-) L11.2
USB1_CONN_DP: D14.2(D-) J38.3(D+) L11.3
USB1_CONN_ID: J38.4(ID) R446.2 R584.2 U109.3(ID)
VUSB_VBUS0: C350.1 FB45.2 J14.1 J35.1
VUSB_VBUS1: C354.2 C355.1 FB47.2 J30.1 J38.1(VCC) U109.6(VBUS)
N11645758: R735.1 U57.5(~{OC})
N11646921: R726.2 U54.5(~{OC})
N16801982: R547.1 U93.12(ROUT1)
N16801984: R542.2 U93.11(DIN1)
N16802002: C675.2 U93.6(V-)
N16802018: C688.2 U93.1(C1+)
N16802020: C688.1 U93.3(C1-)
N16802026: C680.2 U93.5(C2-)
N16802028: C680.1 U93.4(C2+)
N16802060: C331.1 U93.2(V+)
N18091435: R435.1 R749.1 SW12.2 U86.2(A)
N19209091: R442.2 U1.D20(USB1_TXRTUNE_RKELVIN)
N19209222: R431.2 U1.C19(USB0_TXRTUNE_RKELVIN)
N19209666: C348.1 J30.2
N19849959: R515.1 SW12.1
N21235084: C51.1 J14.2
N23290716: R747.1 U76.10(DIR1)
N23290763: R834.2 U76.1(DIR2)
N23291275: R835.1 U124.10(DIR1)
N23291293: R836.2 U124.1(DIR2)
N27235884: C288.2 U74.16(DCD_ECI/VPP)
N27236702: R504.2 U74.9(~{RST})
N27270427: R837.1 U129.10(DIR1)
N27270431: R846.2 U129.1(DIR2)
N27271424: R847.1 U130.10(DIR1)
N27271428: R848.2 U130.1(DIR2)
N27273273: R849.1 U146.10(DIR1)
N27273277: R850.2 U146.1(DIR2)
N27274474: R871.1 U147.10(DIR1)
N27274478: R872.2 U147.1(DIR2)

Not connected (* = marked no-connect by the designer): J23 4(ID)*; J49 2* 6*; P1 1* 4* 6* 7* 8* 9*; U68 1(NC)*; U73 3(ID)* 5(NC)*; U74 1(RI_SCI/~{SUSPEND})* 10(CTS_ECI)* 11(RTS_ECI)* 14(GPIO.1_ECI/DSR_ECI)* 15(GPIO.0_ECI/DTR_ECI)* 17(~{SUSPEND}_/RI_ECI)* 18(CTS_SCI)* 19(RTS_SCI)* 22(GPIO.2_SCI/DSR_SCI)* 23(GPIO.1_SCI/DTR)* 24(GPIO.0_SCI/DCD_SCI)*; U86 1(NC)*; U93 7(DOUT2)* 8(RIN2)* 9(ROUT2)* 10(DIN2)*; U101 1(NC)*; U109 1(D+)* 2(D-)* 5(NC)*

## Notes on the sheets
sheet 27
- USB1 DUAL ROLE
- USB1 ESD DEVICE
- USB0 HOST
- USB0 ESD DEVICE
sheet 28
- SoC UART0
- SoC_UART0 MUX: CP2105 or DB9
- DB9 CONNECTOR OR UART TO USB
  SWITCH SELECTION
- SW12
- DEVICE
- ON
- DB9 CONNECTOR
- OFF
- UART TO USB
- SoC UART1
- TO COM8
- MUX BETWEEN BMC UART0 TO USB & 4 PIN HDR
- SoC_UART0 MUX SELECTION
- SOC_UART0_CP2105_EN
- SoC_UART0 Connected to
- L
- CP2105 (USB-to-UART)
- H
- UART TRANSCIEVER
  DB9 CONNECTOR
- SoC UART0 & BMC CONSOLE OVER USB
- UART0 DB9 CON
sheet 29
- SoC UART2 MUX - BMC or UART2 Header
- SoC UART2
- TO CS2000
- UART2  HEADER
- SoC_UART2 MUX SELECTION
- BMC_UART_SEL
- SoC_UART2 Connected to
- L
- BMC
- H
- UART2 HEADER  (J49)
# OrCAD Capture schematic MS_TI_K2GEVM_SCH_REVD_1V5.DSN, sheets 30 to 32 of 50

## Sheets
30 29. COM8 CON: size C; title: COM8 CONNECTOR
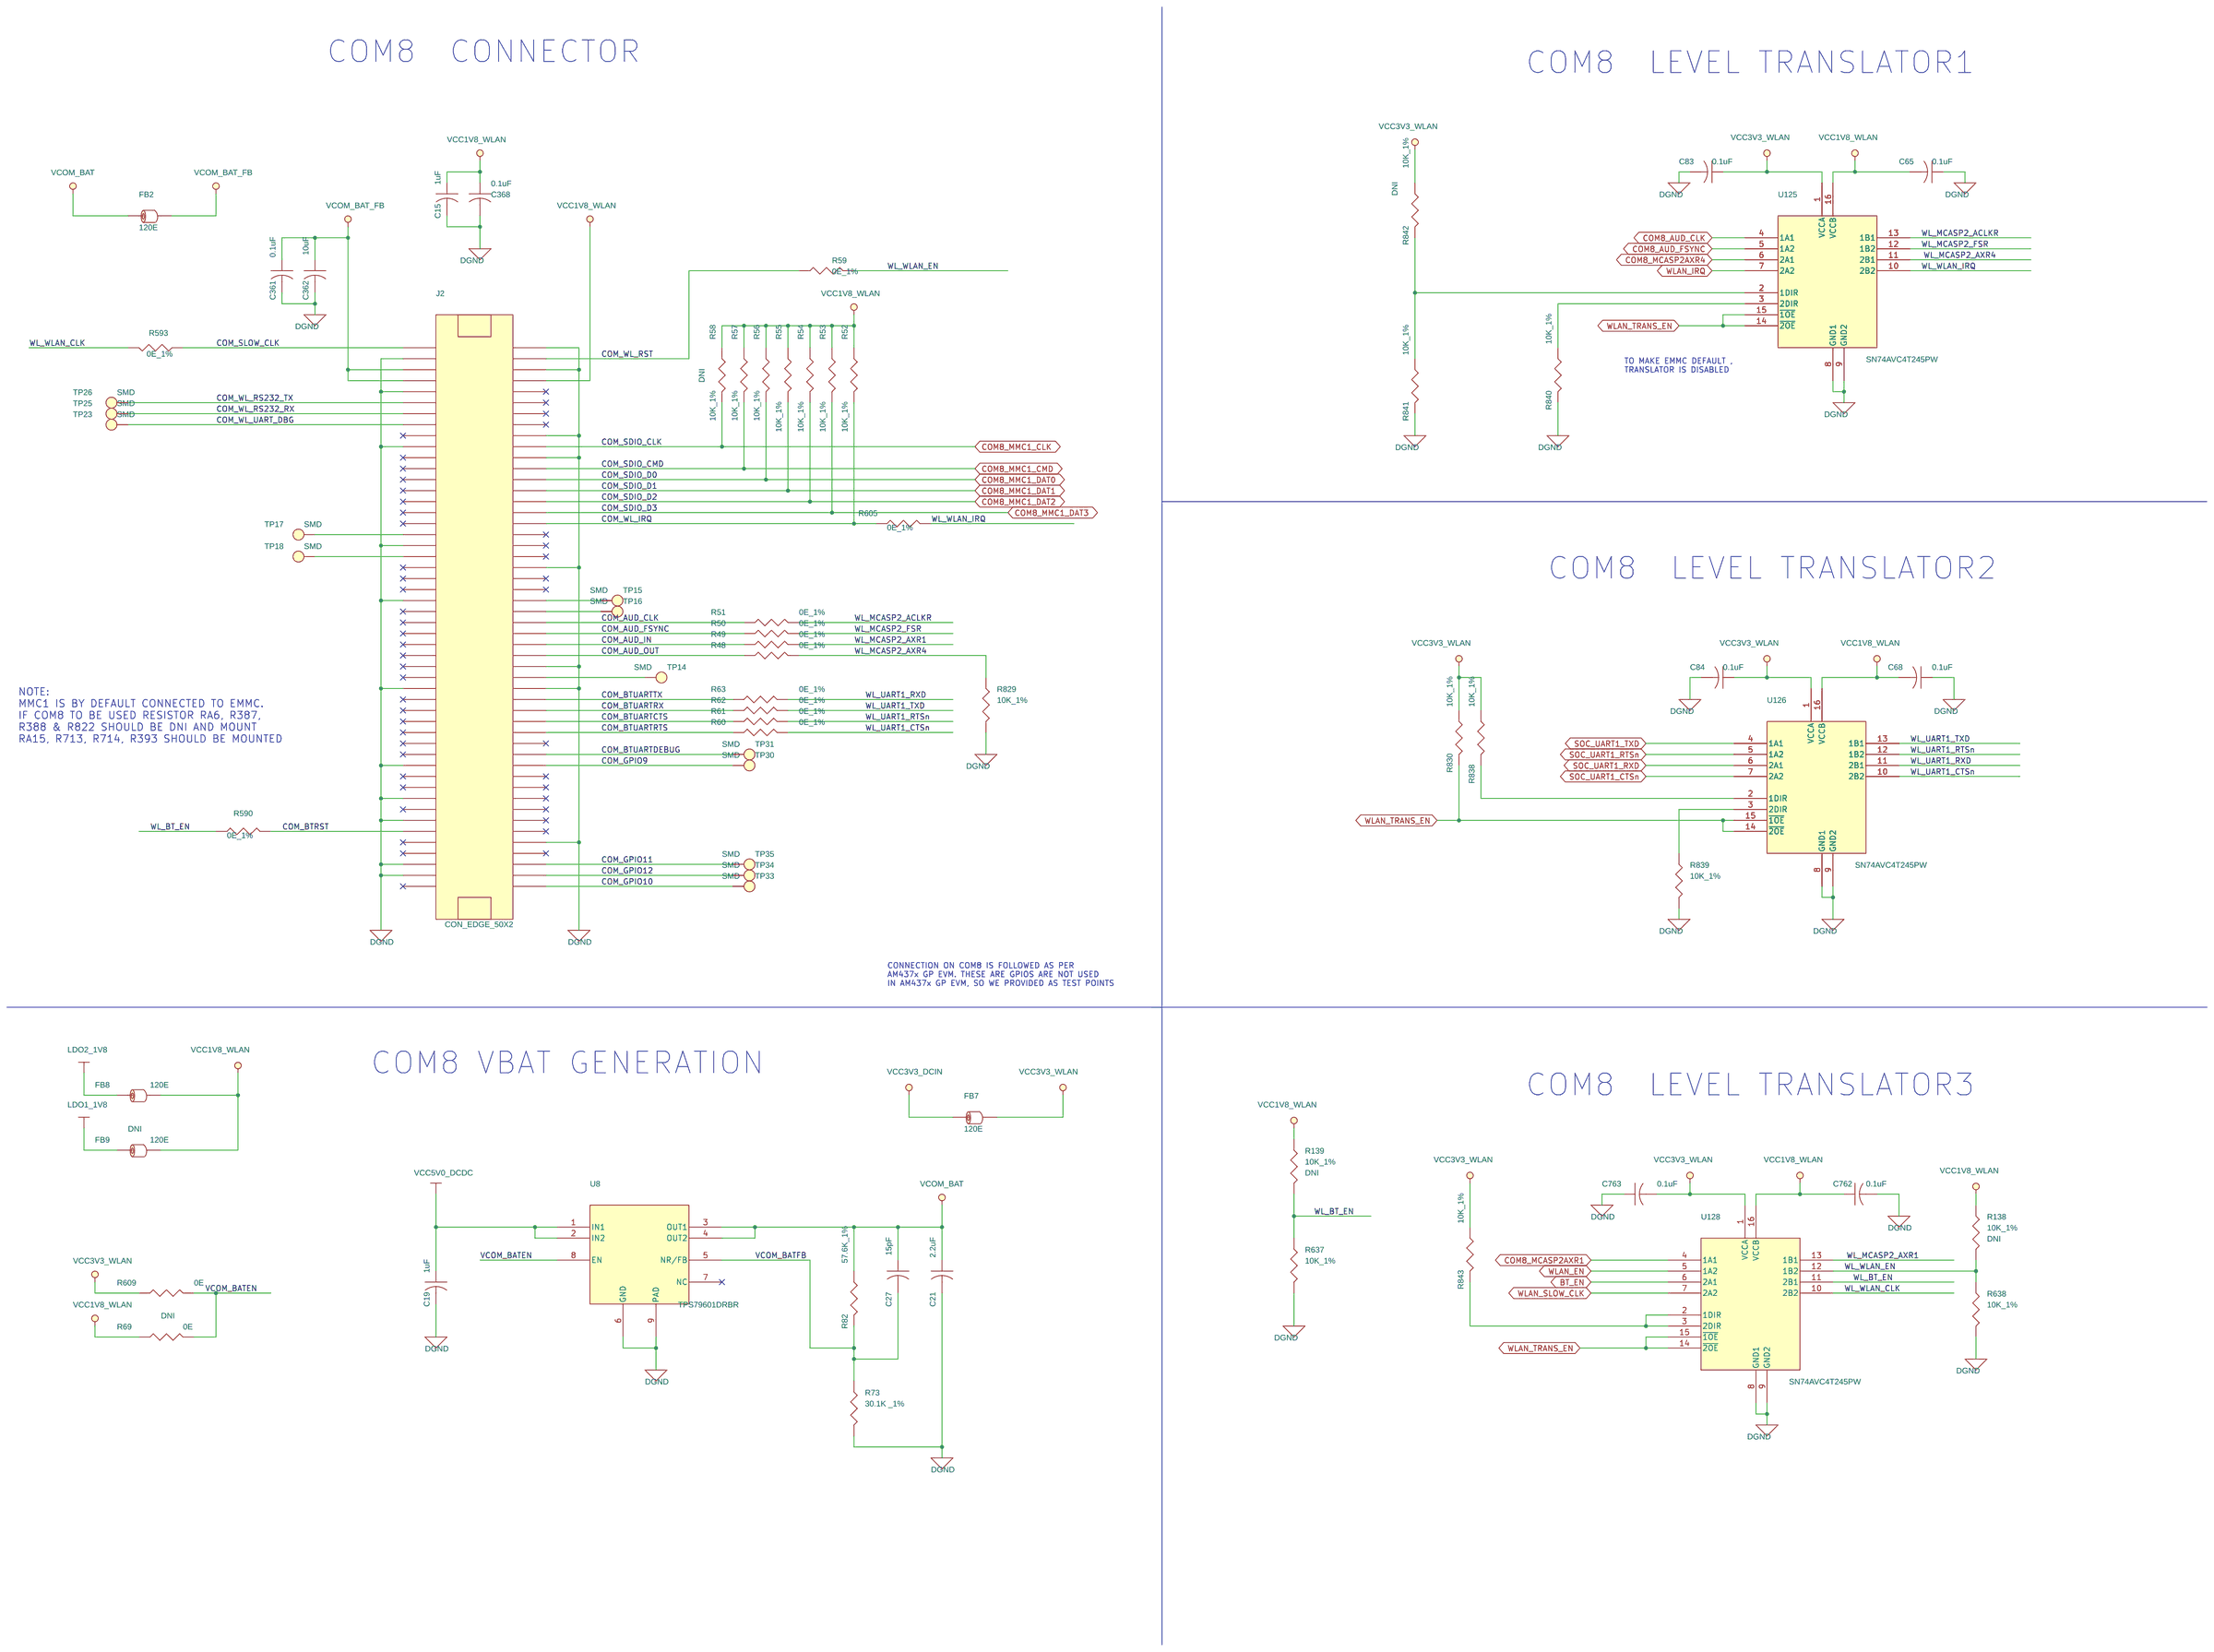
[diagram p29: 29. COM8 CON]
31 30. MLB INTERFACES: size C; title: MLB CONNECTOR
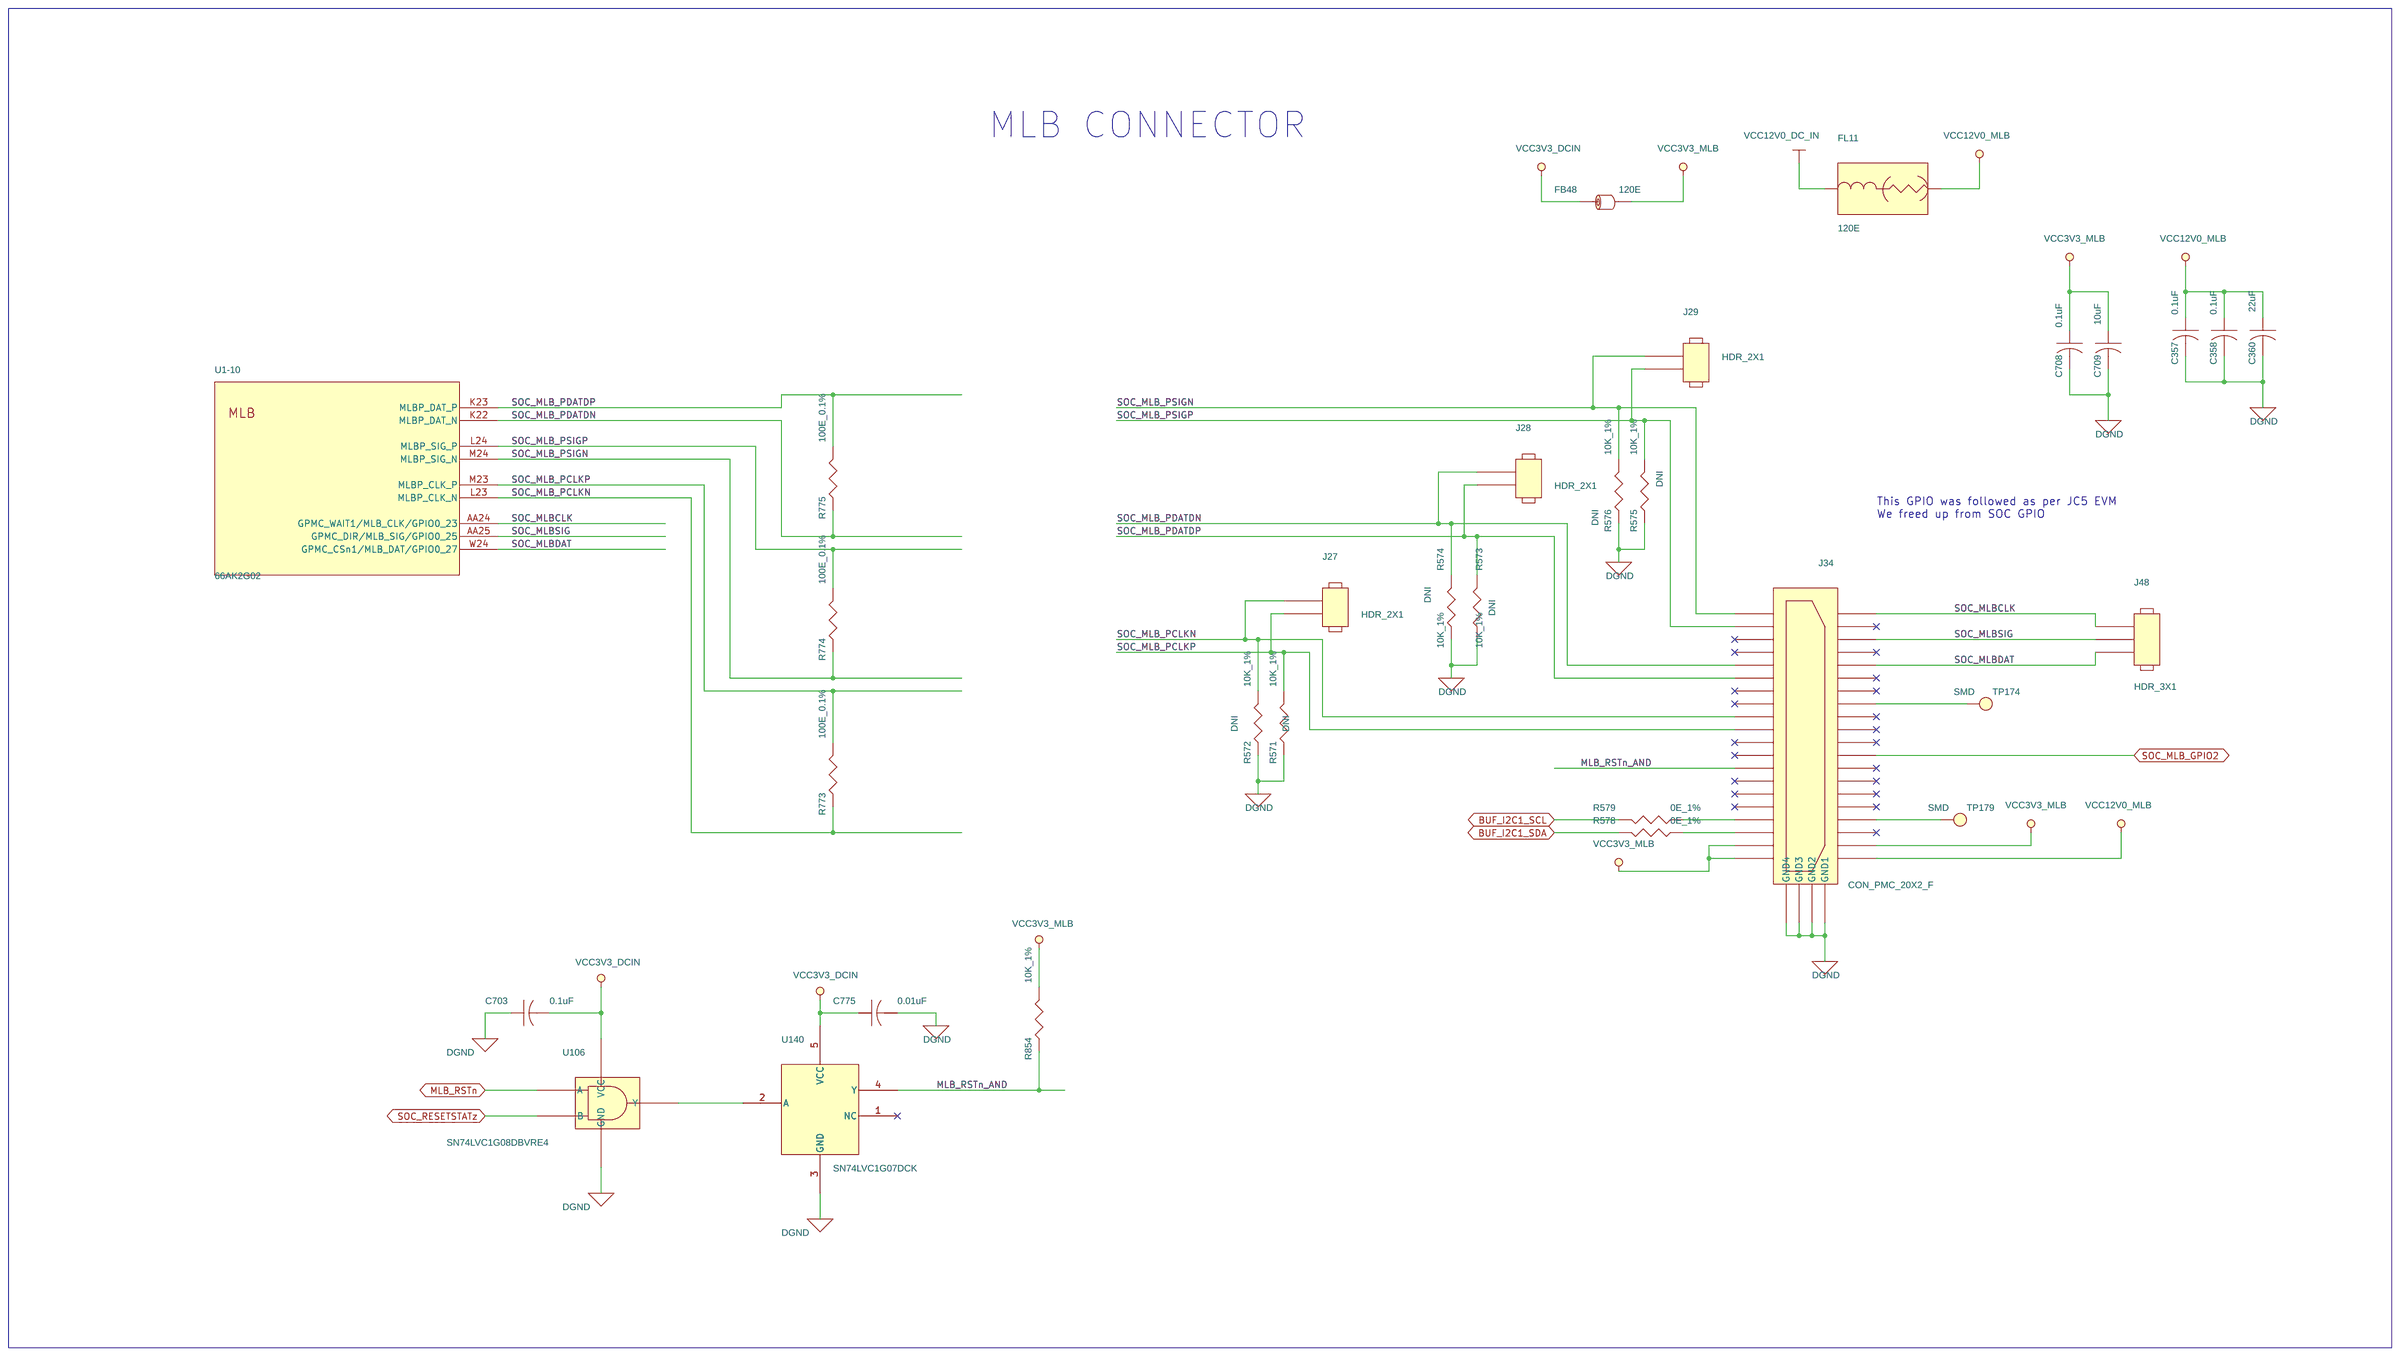
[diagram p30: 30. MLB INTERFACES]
32 31. DCAN0 & DCAN1: size C; title: DCAN CONNECTOR

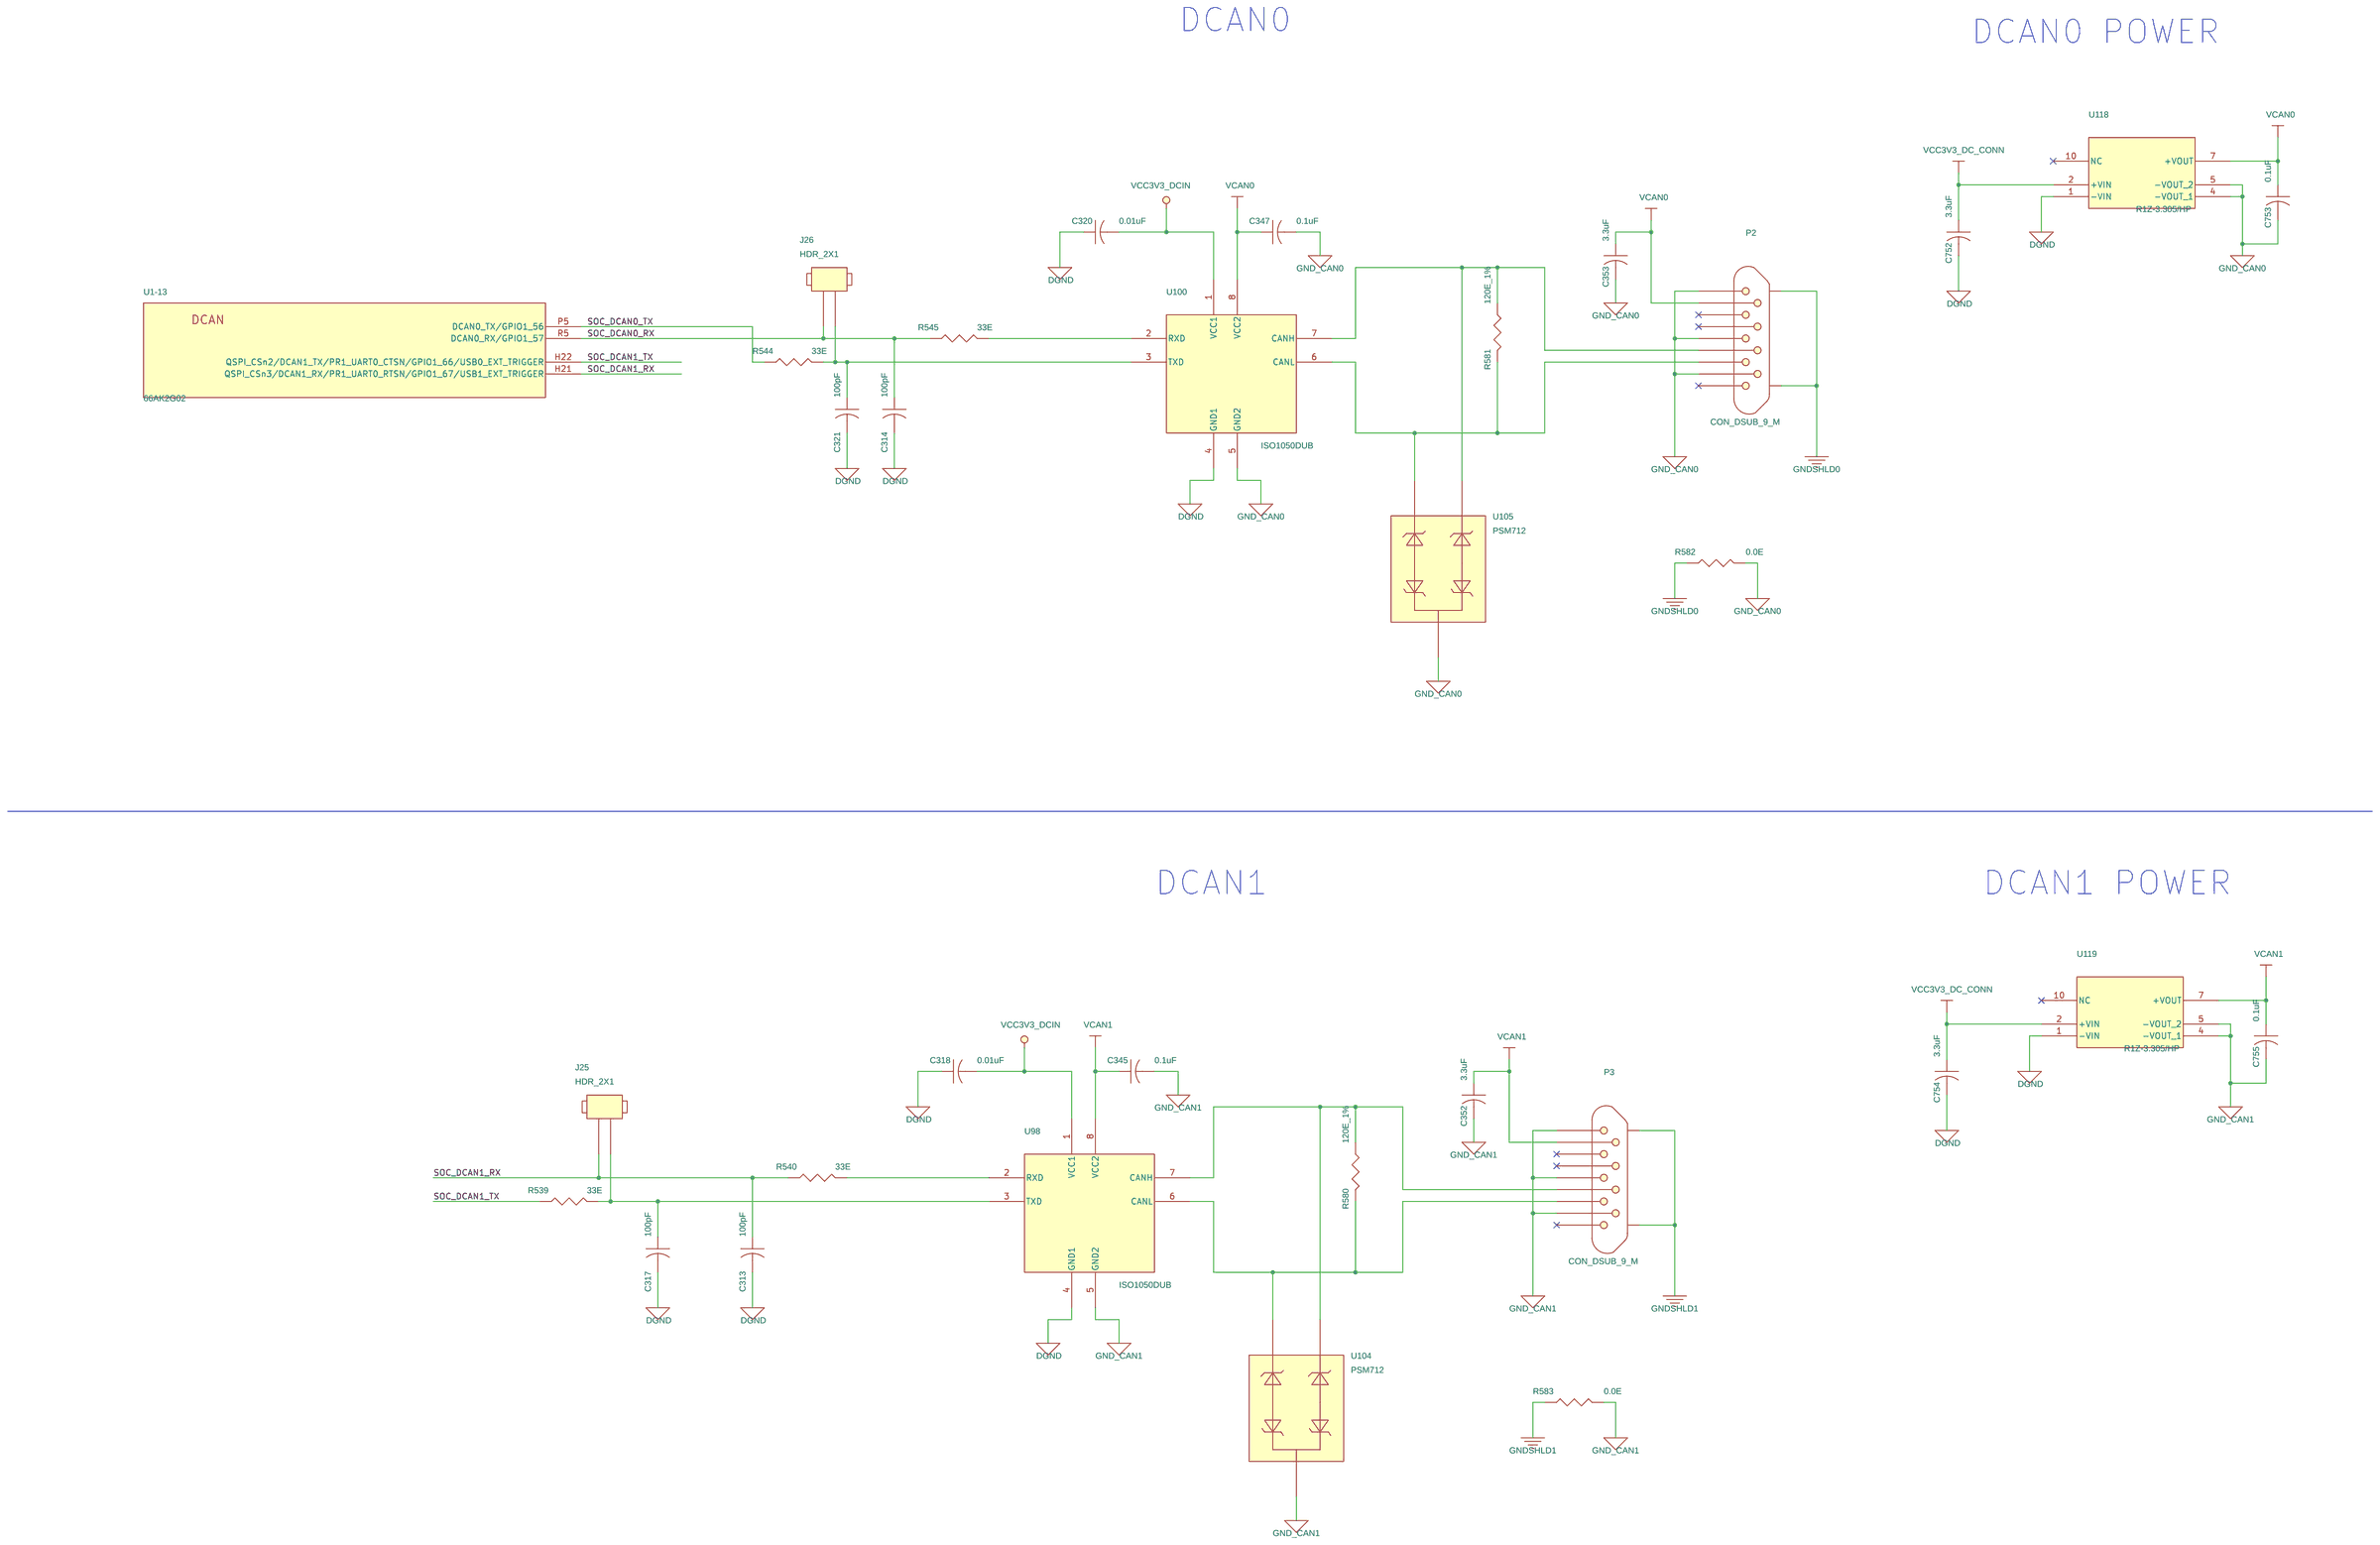
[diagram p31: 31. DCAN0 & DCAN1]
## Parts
sheet 18. NAND FLASH & MICRO SD CARD
U1  66AK2G02_BGA625  [BGASKT625_31-49_1270x1270]  (sections -1,-10,-11,-12,-13,-14,-15,-16,-17,-18,-19,-2,-20,-21,-22,-23,-24,-25,-26,-27,-28,-29,-3,-30,-31,-32,-33,-34,-35,-36,-37,-38,-4,-5,-6,-7,-8,-9)
sheet 29. COM8 CON
C15  1uF  [CAP0402]
C19  1uF  [CAP0402]
C21  2.2uF  [CAP0402]
C27  15pF  [CAP0402]
C65  0.1uF  [CAP0402]
C68  0.1uF  [CAP0402]
C83  0.1uF  [CAP0402]
C84  0.1uF  [CAP0402]
C361  0.1uF  [CAP0402]
C362  10uF  [CAP0805]
C368  0.1uF  [CAP0402]
C762  0.1uF  [CAP0402]
C763  0.1uF  [CAP0402]
FB2  120E  [IND0402]
FB7  120E  [IND0402]
FB8  120E  [IND0402]
FB9  120E  [IND0402]
J2  CON_EDGE_50X2  [CON_ED50X2_MEC6-150_S_R_S]
R48  0E_1%  [RES0402]
R49  0E_1%  [RES0402]
R50  0E_1%  [RES0402]
R51  0E_1%  [RES0402]
R52  10K_1%  [RES0402]
R53  10K_1%  [RES0402]
R54  10K_1%  [RES0402]
R55  10K_1%  [RES0402]
R56  10K_1%  [RES0402]
R57  10K_1%  [RES0402]
R58  10K_1%  [RES0402]
R59  0E_1%  [RES0402]
R60  0E_1%  [RES0402]
R61  0E_1%  [RES0402]
R62  0E_1%  [RES0402]
R63  0E_1%  [RES0402]
R69  0E  [RES0402]
R73  30.1K _1%  [RES0402]
R82  57.6K_1%  [RES0402]
R138  10K_1%  [RES0402]
R139  10K_1%  [RES0402]
R590  0E_1%  [RES0402]
R593  0E_1%  [RES0402]
R605  0E_1%  [RES0402]
R609  0E  [RES0402]
R637  10K_1%  [RES0402]
R638  10K_1%  [RES0402]
R829  10K_1%  [RES0402]
R830  10K_1%  [RES0402]
R838  10K_1%  [RES0402]
R839  10K_1%  [RES0402]
R840  10K_1%  [RES0402]
R841  10K_1%  [RES0402]
R842  10K_1%  [RES0402]
R843  10K_1%  [RES0402]
TP14  SMD  [TP40_SMD]
TP15  SMD  [TP40_SMD]
TP16  SMD  [TP40_SMD]
TP17  SMD  [TP40_SMD]
TP18  SMD  [TP40_SMD]
TP23  SMD  [TP40_SMD]
TP25  SMD  [TP40_SMD]
TP26  SMD  [TP40_SMD]
TP30  SMD  [TP40_SMD]
TP31  SMD  [TP40_SMD]
TP33  SMD  [TP40_SMD]
TP34  SMD  [TP40_SMD]
TP35  SMD  [TP40_SMD]
U8  TPS79601DRBR  [SON8_25-59_130X130]
U125  SN74AVC4T245PW  [TSSOP16_25-59_205X180]
U126  SN74AVC4T245PW  [TSSOP16_25-59_205X180]
U128  SN74AVC4T245PW  [TSSOP16_25-59_205X180]
sheet 30. MLB INTERFACES
C357  0.1uF  [CAP0402]
C358  0.1uF  [CAP0402]
C360  22uF  [CAP1210]
C703  0.1uF  [CAP0402]
C708  0.1uF  [CAP0402]
C709  10uF  [CAP0805]
C775  0.01uF  [CAP0402]
FB48  120E  [IND0402]
FL11  120E  [EMIFIL_BLM18R_0603]
J27  HDR_2X1  [HDR_2X1_100_S_T]
J28  HDR_2X1  [HDR_2X1_100_S_T]
J29  HDR_2X1  [HDR_2X1_100_S_T]
J34  CON_PMC_20X2_F  [CON_PMC20X2_QSH-D-DP_S_S_S]
J48  HDR_3X1  [HDR_3X1_100_S_T]
R571  10K_1%  [RES0402]
R572  10K_1%  [RES0402]
R573  10K_1%  [RES0402]
R574  10K_1%  [RES0402]
R575  10K_1%  [RES0402]
R576  10K_1%  [RES0402]
R578  0E_1%  [RES0402]
R579  0E_1%  [RES0402]
R773  100E_0.1%  [RES0402]
R774  100E_0.1%  [RES0402]
R775  100E_0.1%  [RES0402]
R854  10K_1%  [RES0402]
TP174  SMD  [TP40_SMD]
TP179  SMD  [TP40_SMD]
U106  SN74LVC1G08DBVRE4  [SOT23-5]
U140  SN74LVC1G07DCK  [SC70-5]
sheet 31. DCAN0 & DCAN1
C313  100pF  [CAP0402]
C314  100pF  [CAP0402]
C317  100pF  [CAP0402]
C318  0.01uF  [CAP0402]
C320  0.01uF  [CAP0402]
C321  100pF  [CAP0402]
C345  0.1uF  [CAP0402]
C347  0.1uF  [CAP0402]
C352  3.3uF  [CAP0603]
C353  3.3uF  [CAP0603]
C752  3.3uF  [CAP0603]
C753  0.1uF  [CAP0402]
C754  3.3uF  [CAP0603]
C755  0.1uF  [CAP0402]
J25  HDR_2X1  [HDR_2X1_100_S_T]
J26  HDR_2X1  [HDR_2X1_100_S_T]
P2  CON_DSUB_9_M  [CON_DB9_182-009-113R531_P_R_T]
P3  CON_DSUB_9_M  [CON_DB9_182-009-113R531_P_R_T]
R539  33E  [RES0402]
R540  33E  [RES0402]
R544  33E  [RES0402]
R545  33E  [RES0402]
R580  120E_1%  [RES0402]
R581  120E_1%  [RES0402]
R582  0.0E  [RES0603]
R583  0.0E  [RES0603]
U98  ISO1050DUB  [SOP8_100_375X260]
U100  ISO1050DUB  [SOP8_100_375X260]
U104  PSM712  [SOT23-123]
U105  PSM712  [SOT23-123]
U118  R1Z-3.305/HP  [SMD10_R1Z_600X420]
U119  R1Z-3.305/HP  [SMD10_R1Z_600X420]

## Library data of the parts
U1 = 66AK2G02_BGA625: IC ARM CORTEX AND DSP 32 BIT MICROPROCESSOR BGA625; Chkd/date: NAVEED/141114; Color: Default; Crtd /date: VASANTHA/081014; Custom_Duty: 15%; Customs_HS_Code: 85423100; Distributor_name: NA; Distributor_part_number: NA; Height: 1.70MM; Location X-Coordinate: 0; Location Y-Coordinate: 0; Mfr_name: TEXAS INSTRUMENTS; Mfr_part_number: 66AK2G02; Mistral Part No: 141014100003; Package: BGA625; Part_type: ICS\DIGITAL\MICROPROCESSOR; Power Pins Visible: False; Primitive: DEFAULT; Project: GALILEO_EVM; Tolerance: NA; Voltage: NA; Wattage: NA; Weight: NA; Datasheet: Y:\MIS_DATABASE\DATASHEETS\ICS\DIGITAL\MICROCONTROLLER\SG-BGA-6094.PDF    Y:\MIS_DATABASE\DATASHEETS\ICS\DIGITAL\MICROCONTROLLER\SG-BGA_FP.PDF
C15 C19 = CAP: CAP CERAMIC 1uF 10V 10% X5R 0402; Chkd/date: BALACHANDAR/160514; Crtd /date: SARANYA/060514; Custom_Duty: 15%; Customs_HS_Code: 85322990; Distributor_name: DIGIKEY; Distributor_part_number: 478-4596-1-ND; Height: 0.56MM; Mfr_name: AVX CORPORATION; Mfr_part_number: 0402ZD105KAT2A; Mistral Part No: 120014050010-R; Package: 0402; Part_type: CAPACITORS\CERAMIC; Project: AEGIS GP BETA2; RoHS: RoHS; Temperature: -55°C+85°C; Tolerance: 10%; Voltage: 10V; Wattage: NA; Weight: NA; Datasheet: Y:\MIS_DATABASE\DATASHEETS\CAPACITORS\AVX_MLC.PDF
C21 = CAP: CAP CERAMIC 2.2uF 16V 10% X5R 0402; Chkd/date: JAGADISH/280314; Crtd /date: SARANYA/270314; Custom_Duty: 15%; Customs_HS_Code: 85322990; Distributor_name: DIGIKEY; Distributor_part_number: 445-9085-1-ND; Height: 0.55MM; Mfr_name: TDK CORPORATION; Mfr_part_number: C1005X5R1C225K050BC; Mistral Part No: 120014030032-R; Package: 0402; Part_type: CAPACITORS\CERAMIC; Project: DMP; RoHS: RoHS; Temperature: -55°C+85°C; Tolerance: 10%; Voltage: 16V; Wattage: NA; Weight: NA; Datasheet: Y:\MIS_DATABASE\DATASHEETS\CAPACITORS\TDK_CAP.PDF
C27 = CAP: CAP CERAMIC 15pF 50V 5% NP0 0402; Alternate_mfr_name_A: AVX CORPORATION; Alternate_mfr_name_B: KEMET; Alternate_mfr_name_D: MURATA; Alternate_mfr_part_number_A: 04025A150JAT2A; Alternate_mfr_part_number_B: C0402C150J5GACTU; Alternate_mfr_part_number_D: GRM1555C1H150JZ01D; Chkd/date: SHREESHAIL/220506; Crtd /date: MAZHAR/150506; Custom_Duty: 15%; Customs_HS_Code: 85322990; Distributor_name: DIGIKEY; Distributor_name_A: DIGIKEY; Distributor_name_B: DIGIKEY; Distributor_name_D: DIGIKEY; Distributor_part_number: PCC150CQCT-ND; Distributor_part_number_A: 478-1072-1-ND; Distributor_part_number_B: 399-1014-1-ND; Distributor_part_number_D: 490-1280-1-ND; Height: 0.55MM; Mfr_name: PANASONIC-ECG; Mfr_part_number: ECJ-0EC1H150J; Mistral Part No: 120009030233-R; Package: 0402; Part_type: CAPACITORS\CERAMIC; Project: VOCERA; RoHS: RoHS; Tolerance: 5%; Voltage: 50V; Datasheet: Y:\MIS_DATABASE\DATASHEETS\CAPACITORS\ECJ.PDF
C65 C68 C83 C84 C345 C347 C361 C368 C703 C708 C753 C755 C762 C763 = CAP: CAP CERAMIC 0.1uF 16V 10% X7R 0402; Alternate_mfr_name_A: KEMET; Alternate_mfr_part_number_A: C0402C104K4RACT; Chkd/date: MAZHAR/281108; Crtd /date: MAZHAR/030907; Custom_Duty: 15%; Customs_HS_Code: 85322990; Distributor_name: DIGIKEY; Distributor_name_A: DIGIKEY; Distributor_part_number: 490-3261-1-ND; Distributor_part_number_A: 399-3521-1-ND; Height: 0.55MM; Mfr_name: MURATA; Mfr_part_number: GRM155R71C104KA88D; Mistral Part No: 120009030060-R; Package: 0402; Part_type: CAPACITORS\CERAMIC; Project: SMART VIEW_IP CAMERA; Tolerance: 10%; Voltage: 16V; Datasheet: Y:\MIS_DATABASE\DATASHEETS\CAPACITORS\GRM188SERIES.PDF
C362 C709 = CAP: CAP CERAMIC 10uF 16V 10% X5R 0805; Alternate_mfr_name_A: TAIYO YUDEN; Alternate_mfr_part_number_A: EMK212BJ106KG-T; Chkd/date: RAVI/020511; Crtd /date: BAVISH/290411; Custom_Duty: 15%; Customs_HS_Code: 85322990; Distributor_name: DIGIKEY; Distributor_name_A: DIGIKEY; Distributor_part_number: 478-5165-1-ND; Distributor_part_number_A: 587-1295-1-ND; Height: 1.40MM; Mfr_name: AVX CORPORATION; Mfr_part_number: 0805YD106KAT2A; Mistral Part No: 120011040011-R; Package: 0805; Part_type: CAPACITORS\CERAMIC; Project: AOD_POD-RF; RoHS: RoHS; Temperature: -55°C+85°C; Tolerance: 10%; Voltage: 16V; Wattage: NA; Weight: NA; Datasheet: Y:\MIS_DATABASE\DATASHEETS\CAPACITORS\AVX_CERAMIC.PDF
FB2 FB7 FB8 FB48 = INDUCTOR_FERRITE: IND BEAD CHIP 120E 1.2A 0402; Chkd/date: ASHOK/240212; Crtd /date: BAVISH/060711; Custom_Duty: 24%; Customs_HS_Code: 85437099; Distributor_name: DIGIKEY; Distributor_part_number: 445-2981-1-ND; Height: 0.55MM; Mfr_name: TDK CORPORATION; Mfr_part_number: MPZ1005S121C; Mistral Part No: 130011070007-R; Package: 0402; Part_type: INDUCTOR; Project: SVDU; RoHS: RoHS; Temperature: -40°C+85°C; Tolerance: NA; Voltage: NA; Wattage: NA; Weight: 1mg; Datasheet: Y:\MIS_DATABASE\DATASHEETS\DISCRETES\INDUCTORS\MPZ1005.PDF
FB9 = INDUCTOR_FERRITE: IND BEAD CHIP 120E 1.2A 0402; Chkd/date: ASHOK/240212; Crtd /date: BAVISH/060711; Custom_Duty: 24%; Customs_HS_Code: 85437099; Distributor_name: DIGIKEY; Distributor_part_number: 445-2981-1-ND; Height: 0.55MM; Loading: DNI; Mfr_name: TDK CORPORATION; Mfr_part_number: MPZ1005S121C; Mistral Part No: 130011070007-R; Package: 0402; Part_type: INDUCTOR; Project: SVDU; RoHS: RoHS; Temperature: -40°C+85°C; Tolerance: NA; Voltage: NA; Wattage: NA; Weight: 1mg; Datasheet: Y:\MIS_DATABASE\DATASHEETS\DISCRETES\INDUCTORS\MPZ1005.PDF
J2 = CON_SCK_50X2: CON EDGE 50X2 EDGE CARD SOCKET RA SMD; Chkd/date: BALACHANDAR/150514; Crtd /date: SARANYA/130514; Custom_Duty: 24%; Customs_HS_Code: 85369090; Distributor_name: DIGIKEY; Distributor_part_number: MEC6-150-02-S-D-RA1-TR; Height: 5.78MM; Mfr_name: SAMTEC; Mfr_part_number: MEC6-150-02-S-D-RA1-TR; Mistral Part No: 150014050030-R; Package: SMD; Part_type: CONNECTOR\EDGE; Project: AEGIS GP BETA2; RoHS: RoHS; Temperature: -55°C+125°C; Tolerance: NA; Voltage: NA; Wattage: NA; Weight: NA; Datasheet: Y:\MIS_DATABASE\DATASHEETS\CONNECTORS\MEC6.PDF
R48-R51 R59-R63 R578 R579 R590 R593 R605 = RESISTOR: RES 0E 1/16W 1% 0402; Chkd/date: MAZHAR/220709; Crtd /date: USMAN/270109; Custom_Duty: 15%; Customs_HS_Code: 85332119; Distributor_name: NA; Distributor_part_number: NA; Height: 0.40MM; Mfr_name: YAGEO AMERICA; Mfr_part_number: RC0402FR-070RL; Mistral Part No: 110009030085-P; Package: 0402; Part_type: RESISTORS\FIXED; Project: OMAP_EVM; RoHS: Pb-Free; Tolerance: 1%; Wattage: 1/16W; Datasheet: Y:\MIS_DATABASE\DATASHEETS\RESISTORS\CRCW0603.PDF
R52-R57 R637 R638 R829 R830 R838-R841 R843 R854 = RESISTOR: RES 10K 1/16W 1% 0402; Alternate_mfr_name_A: AVX CORPORATION; Alternate_mfr_name_B: PANASONIC-ECG-ECG; Alternate_mfr_name_C: YAGEO AMERICA; Alternate_mfr_name_D: VISHAY; Alternate_mfr_part_number_A: CR05-103F-H; Alternate_mfr_part_number_B: ERJ-2RKF1002X; Alternate_mfr_part_number_C: 9C04021A1002FLHF3; Alternate_mfr_part_number_D: CRCW040210K0FKED; Chkd/date: SHREESHAIL/310506; Crtd /date: GEETHA/290506; Custom_Duty: 15%; Customs_HS_Code: 85332119; Distributor_name: DIGIKEY; Distributor_name_A: NA; Distributor_name_B: DIGIKEY; Distributor_name_C: DIGIKEY; Distributor_name_D: DIGIKEY; Distributor_part_number: 311-10.0KLRTR-ND; Distributor_part_number_A: NA; Distributor_part_number_B: P10.0KLCT-ND; Distributor_part_number_C: 311-10.0KLCT-ND; Distributor_part_number_D: 541-10.0KLCT-ND; Height: 0.40MM; Mfr_name: YAGEO AMERICA; Mfr_part_number: RC0402FR-0710KL; Mistral Part No: 110009030220-P; Package: 0402; Part_type: RESISTORS\FIXED; Project: VOCERA; RoHS: Pb-Free; Tolerance: 1%; Wattage: 1/16W; Datasheet: Y:\MIS_DATABASE\DATASHEETS\RESISTORS\YAGEO-RC0402.PDF
R58 R138 R139 R571-R576 R842 = RESISTOR: RES 10K 1/16W 1% 0402; Alternate_mfr_name_A: AVX CORPORATION; Alternate_mfr_name_B: PANASONIC-ECG-ECG; Alternate_mfr_name_C: YAGEO AMERICA; Alternate_mfr_name_D: VISHAY; Alternate_mfr_part_number_A: CR05-103F-H; Alternate_mfr_part_number_B: ERJ-2RKF1002X; Alternate_mfr_part_number_C: 9C04021A1002FLHF3; Alternate_mfr_part_number_D: CRCW040210K0FKED; Chkd/date: SHREESHAIL/310506; Crtd /date: GEETHA/290506; Custom_Duty: 15%; Customs_HS_Code: 85332119; Distributor_name: DIGIKEY; Distributor_name_A: NA; Distributor_name_B: DIGIKEY; Distributor_name_C: DIGIKEY; Distributor_name_D: DIGIKEY; Distributor_part_number: 311-10.0KLRTR-ND; Distributor_part_number_A: NA; Distributor_part_number_B: P10.0KLCT-ND; Distributor_part_number_C: 311-10.0KLCT-ND; Distributor_part_number_D: 541-10.0KLCT-ND; Height: 0.40MM; Loading: DNI; Mfr_name: YAGEO AMERICA; Mfr_part_number: RC0402FR-0710KL; Mistral Part No: 110009030220-P; Package: 0402; Part_type: RESISTORS\FIXED; Project: VOCERA; RoHS: Pb-Free; Tolerance: 1%; Wattage: 1/16W; Datasheet: Y:\MIS_DATABASE\DATASHEETS\RESISTORS\YAGEO-RC0402.PDF
R69 = RESISTOR: RES 0E 1/10W 5% 0402; Chkd/date: NAVEED/241114; Crtd /date: NAVEED/201014; Custom_Duty: 15%; Customs_HS_Code: 85332119; Distributor_name: DIGIKEY; Distributor_part_number: P0.0JCT-ND; Height: 0.40MM; Loading: DNI; Mfr_name: PANASONIC-ECG; Mfr_part_number: ERJ-2GE0R00X; Mistral Part No: 110014100008-R; Package: 0402; Part_type: RESISTORS\FIXED; Project: AEGIS POM; RoHS: RoHS; Tolerance: 5%; Wattage: 1/10W; Datasheet: Y:\MIS_DATABASE\DATASHEETS\RESISTORS\ERJ12.PDF
R73 = RESISTOR: RES 30.1K 1/16W 1% 0402; Chkd/date: SHREESHAIL/061205; Crtd /date: MAZHAR/250805; Custom_Duty: 15%; Customs_HS_Code: 85332119; Distributor_name: DIGIKEY; Distributor_part_number: 311-30.1KLRCT-ND; Height: 0.40MM; Mfr_name: YAGEO AMERICA; Mfr_part_number: RC0402FR-0730K1L; Mistral Part No: 110009030648-P; Package: 0402; Part_type: RESISTORS\FIXED; Project: HSE; RoHS: Pb-Free; Tolerance: 1%; Wattage: 1/16W; Datasheet: Y:\MIS_DATABASE\DATASHEETS\RESISTORS\YAGEO-RC0402.PDF
R82 = RESISTOR: RES 57.6K 1/16W 1% 0402; Chkd/date: USMAN/021214; Crtd /date: VASANTHA/101114; Custom_Duty: 15%; Customs_HS_Code: 85332119; Distributor_name: DIGIKEY; Distributor_part_number: 541-57.6KLCT-ND; Height: 0.40MM; Mfr_name: VISHAY; Mfr_part_number: CRCW040257K6FKED; Mistral Part No: 110014110002-R; Package: 0402; Part_type: RESISTORS\FIXED; Project: GALILEO_EVM; RoHS: RoHS; Temperature: -55°C+155°C; Tolerance: 1%; Voltage: NA; Wattage: 1/16W; Weight: 0.65mg; Datasheet: Y:\MIS_DATABASE\DATASHEETS\RESISTORS\CRCW0603.PDF
R609 = RESISTOR: RES 0E 1/10W 5% 0402; Chkd/date: NAVEED/241114; Crtd /date: NAVEED/201014; Custom_Duty: 15%; Customs_HS_Code: 85332119; Distributor_name: DIGIKEY; Distributor_part_number: P0.0JCT-ND; Height: 0.40MM; Mfr_name: PANASONIC-ECG; Mfr_part_number: ERJ-2GE0R00X; Mistral Part No: 110014100008-R; Package: 0402; Part_type: RESISTORS\FIXED; Project: AEGIS POM; RoHS: RoHS; Tolerance: 5%; Wattage: 1/10W; Datasheet: Y:\MIS_DATABASE\DATASHEETS\RESISTORS\ERJ12.PDF
TP14-TP18 TP23 TP25 TP26 TP30 TP31 TP33-TP35 TP174 TP179 = TESTPOINT: TESTPOINT 40 SMD; Chkd/date: MAZHAR/190505; Crtd /date: MAZHAR/190505; Distributor_name: NA; Distributor_part_number: NA; Height: NA; Mfr_name: LOCAL; Mistral Part No: 130009030933; Part_type: MISC\TESTPOINT; Project: RAINIER-3
U8 = TPS79601DRBR_SON8: IC ADJUSTABLE LDO VOLTAGE REGULATOR HIGH PSRR 1A SON8; Chkd/date: RAGESH/211010; Crtd /date: MAZHAR/280809; Custom_Duty: 15%; Customs_HS_Code: 85423100; Distributor_name: DIGIKEY; Distributor_part_number: 296-23107-1-ND; Height: 1.00MM; Mfr_name: TEXAS INSTRUMENTS; Mistral Part No: 142009080012-R; Package: SON8; Part_type: ICS\POWER\VOLTAGE REGULATOR; Project: DIO_TXRX; RoHS: RoHS; Temperature: -40°C+125°C; Weight: NA; Datasheet: Y:\MIS_DATABASE\DATASHEETS\MISC\REGULATORS\TPS796XX.PDF
U125 U126 U128 = SN74AVC4T245PW_TSSOP16: IC 4-BIT DUAL SUPPLY BUS TRANSCEIVER TSSOP16; Chkd/date: SHREESHAIL/030506; Crtd /date: MAZHAR/270406; Custom_Duty: 15%; Customs_HS_Code: 85423100; Distributor_name: MOUSER; Distributor_part_number: 595-SN74AVC4T245PW; Height: 1.20MM; Mfr_name: TEXAS INSTRUMENTS; Mistral Part No: 141009030111-R; Package: TSSOP16; Part_type: ICS\DIGITAL\COMBINATIONAL; Project: VOCERA; RoHS: Sb/ Br FREE; Datasheet: Y:\MIS_DATABASE\DATASHEETS\ICS\DIGITAL\BUSTRANSCEIVER\SN74AVC4T245.PDF
C357 C358 = CAP: CAP CERAMIC 0.1uF 25V -20% TO +80 Y5V 0402; Chkd/date: SHREESHAIL/301105; Crtd /date: MAZHAR/251005; Custom_Duty: 15%; Customs_HS_Code: 85322990; Distributor_name: DIGIKEY; Distributor_part_number: 490-3271-1-ND; Height: 0.55MM; Mfr_name: MURATA; Mfr_part_number: GRM155F51E104ZA01D; Mistral Part No: 120009030085; Package: 0402; Part_type: CAPACITORS\CERAMIC; Project: ADR; Tolerance: -20% TO +80%; Voltage: 25V; Datasheet: Y:\MIS_DATABASE\DATASHEETS\CAPACITORS\GRM188SERIES.PDF
C360 = CAP: CAP CERAMIC 22uF 25V 10% X7R 1210; Chkd/date: BAVISH/040311; Crtd /date: MAZHAR/190111; Custom_Duty: 15%; Customs_HS_Code: 85322990; Distributor_name: DIGIKEY; Distributor_part_number: 490-5313-1-ND; Height: 2.70MM; Mfr_name: MURATA; Mfr_part_number: GRM32ER71E226KE15L; Mistral Part No: 120011010016-R; Package: 1210; Part_type: CAPACITORS\CERAMIC; Project: ITS-PWR_CARD; RoHS: RoHS; Temperature: -55°C+125°C; Tolerance: 10%; Voltage: 25V; Wattage: NA; Weight: NA; Datasheet: Y:\MIS_DATABASE\DATASHEETS\CAPACITORS\GRM32,43,55.PDF
C318 C320 C775 = CAP: CAP CERAMIC 0.01uF 16V 10% X7R 0402; Alternate_mfr_name_A: AVX CORPORATION; Alternate_mfr_name_B: KEMET; Alternate_mfr_name_D: TDK CORPORATION; Alternate_mfr_part_number_A: 0402YC103KAT2A; Alternate_mfr_part_number_B: C0402C103K4RACTU; Alternate_mfr_part_number_D: C1005X7R1C103K; Chkd/date: SHREESHAIL/180506; Crtd /date: MAZHAR/110506; Custom_Duty: 15%; Customs_HS_Code: 85322990; Distributor_name: DIGIKEY; Distributor_name_A: DIGIKEY; Distributor_name_B: DIGIKEY; Distributor_name_D: DIGIKEY; Distributor_part_number: PCC103BQCT-ND; Distributor_part_number_A: 478-1114-1-ND; Distributor_part_number_B: 399-1038-1-ND; Distributor_part_number_D: 445-1262-1-ND; Height: 0.55MM; Mfr_name: PANASONIC-ECG; Mfr_part_number: ECJ-0EB1C103K; Mistral Part No: 120009030032-R; Package: 0402; Part_type: CAPACITORS\CERAMIC; Project: VOCERA; RoHS: RoHS; Tolerance: 10%; Voltage: 16V; Datasheet: Y:\MIS_DATABASE\DATASHEETS\CAPACITORS\PAN-ECJ.PDF
FL11 = EMIFILTER_IND: FERRITE BEAD 120E 2A 0603; Chkd/date: RAGESH/111010; Crtd /date: MUDDU/190610; Custom_Duty: 24%; Customs_HS_Code: 85437099; Distributor_name: DIGIKEY; Distributor_part_number: 490-3991-1-ND; Height: 0.95MM; Mfr_name: MURATA; Mfr_part_number: BLM18EG121SN1D; Mistral Part No: 130010060030-R; Package: 0603; Part_type: MISC\FILTER; Project: CENTAURUS; Temperature: -55°C+125°C; Weight: NA; Datasheet: Y:\MIS_DATABASE\DATASHEETS\DISCRETES\INDUCTORS\BLM18E.PDF
J25-J29 = HEADER_2X1: CON HDR 2X1 2.54MM PITCH ST TH; ASSEMBLY_INSTRUCTION: DNI; Alternate_mfr_name_A: SULLINS ELECTRONICS; Alternate_mfr_name_B: SAMTEC; Alternate_mfr_name_C: HANTRONIX; Alternate_mfr_part_number_A: PZC02SAAN; Alternate_mfr_part_number_B: TLW-102-06-G-S; Alternate_mfr_part_number_C: HDM20216L; Chkd/date: SHREESHAIL/140206; Crtd /date: MAZHAR/280405; Custom_Duty: 24%; Customs_HS_Code: 85369090; Distributor_name: DIGIKEY; Distributor_part_number: WM4000-ND; Height: 10.79MM; Mfr_name: MOLEX; Mfr_part_number: 22-03-2021; Mistral Part No: 150009030246-R; Package: THRU-HOLE; Part_type: CONNECTOR\HEADERS; Project: FPGA EXTENDER CARD; RoHS: RoHS; Datasheet: Y:\MIS_DATABASE\DATASHEETS\CONNECTORS\HEADER_X4030.PDF
J34 = CON_PMC_20X2_F: CON PMC 20X2 0.50MM PITCH FEMALE ST SMD; Chkd/date: USMAN/021214; Crtd /date: CHAITHANYA/031111; Custom_Duty: 24%; Customs_HS_Code: 85369090; Distributor_name: DIGIKEY; Distributor_part_number: QSH-020-01-L-D-DP-A-ND; Height: 3.25MM; Mfr_name: SAMTEC; Mfr_part_number: QSH-020-01-L-D-DP-A; Mistral Part No: 150011110006-R; Package: SMD; Part_type: CONNECTOR\PMC; Project: LLTR; RoHS: RoHS; Temperature: -55°C+125°C; Tolerance: NA; Voltage: NA; Wattage: NA; Weight: NA; Datasheet: Y:\MIS_DATABASE\DATASHEETS\CONNECTORS\QSH-SERIES.PDF
J48 = HEADER_3X1: CON HDR 3X1 2.54MM PITCH ST TH; Chkd/date: MAZHAR/100311; Crtd /date: BAVISH/160211; Custom_Duty: 24%; Customs_HS_Code: 85369090; Distributor_name: DIGIKEY; Distributor_part_number: A26545-ND; Height: 10.74MM; Mfr_name: TYCO ELECTRONICS; Mfr_part_number: 87224-3; Mistral Part No: 150011020004-R; Package: THRU-HOLE; Part_type: CONNECTOR\HEADERS; Project: OMAPL1_PEC20; RoHS: RoHS; Temperature: NA; Tolerance: NA; Voltage: NA; Wattage: NA; Weight: NA; Datasheet: Y:\MIS_DATABASE\DATASHEETS\CONNECTORS\87224.PDF
R773-R775 = RESISTOR: RES 100E 1/16W 0.1% 0402; Chkd/date: SUHAS/290910; Crtd /date: MUDDU/020910; Custom_Duty: 15%; Customs_HS_Code: 85332119; Distributor_name: DIGIKEY; Distributor_part_number: TNP100DACT-ND; Height: 0.40MM; Mfr_name: VISHAY; Mfr_part_number: TNPW0402100RBEED; Mistral Part No: 110010090013-P; Package: 0402; Part_type: RESISTORS\FIXED; Project: FLR PSPU; RoHS: Pb-Free; Temperature: -55°C+125°C; Tolerance: 0.1%; Voltage: 25V; Wattage: 1/16W; Weight: 0.65g/1000pcs; Datasheet: Y:\MIS_DATABASE\DATASHEETS\RESISTORS\VISHAY_TNPW_0.1%.PDF
U106 = SN74LVC1G08DBVRE4_SOT23-5: IC SINGLE 2-INPUT POSITIVE AND GATE SOT23-5; Chkd/date: SUHAS/221010; Crtd /date: USMAN/151008; Custom_Duty: 15%; Customs_HS_Code: 85423100; Distributor_name: DIGIKEY; Distributor_part_number: SN74LVC1G08DBVRE4-ND; Height: 1.45MM; Mfr_name: TEXAS INSTRUMENTS; Mistral Part No: 141009060026-R; Part_type: ICS\DIGITAL\GATES; Project: KHAN_MAIN; RoHS: Sb/ Br FREE; Temperature: -40°C+85°C; Datasheet: Y:\MIS_DATABASE\DATASHEETS\ICS\DIGITAL\GATES\SN74LVC1G08.PDF
U140 = SN74LVC1G07DBVR_SOT23-5: IC SINGLE BUFFER/DRIVER SC-70; Chkd/date: VASANTHA/150714; Crtd /date: NAVEED/160614; Custom_Duty: 15%; Customs_HS_Code: 85423100; Distributor_name: DIGIKEY; Distributor_part_number: 296-8486-1-ND; Height: 1.10MM; Mfr_name: TEXAS INSTRUMENTS; Mfr_part_number: SN74LVC1G07DCKR; Mistral Part No: 141014060023-R; Part_type: ICS\INTERFACE\LINE DRIVER; Project: AEGIS_POM; RoHS: Sb/ Br FREE; Temperature: -40°C+85°C; Tolerance: NA; Voltage: NA; Wattage: NA; Weight: NA; Datasheet: Y:\MIS_DATABASE\DATASHEETS\ICS\INTERFACE\SN74LVC1G07.PDF
C313 C314 C317 C321 = CAP: CAP CERAMIC 100pF 25V 10% NP0 0402; Chkd/date: NAVEED/070814; Crtd /date: VASANTHA/300714; Custom_Duty: 15%; Customs_HS_Code: 85322990; Distributor_name: DIGIKEY; Distributor_part_number: 399-7748-1-ND; Height: 0.55MM; Mfr_name: KEMET; Mfr_part_number: C0402C101K3GACTU; Mistral Part No: 120014070037-R; Package: 0402; Part_type: CAPACITORS\CERAMIC; Project: AEGIS_POM; RoHS: RoHS; Temperature: NA; Tolerance: 10%; Voltage: 25V; Wattage: NA; Weight: NA; Datasheet: Y:\MIS_DATABASE\DATASHEETS\CAPACITORS\KEMET-C08.PDF
C352 C353 C752 C754 = CAP: CAP CERAMIC 3.3uF 10V 10% X5R 0603; Chkd/date: NAVEED/070814; Crtd /date: VASANTHA/310714; Custom_Duty: 15%; Customs_HS_Code: 85322990; Distributor_name: DIGIKEY; Distributor_part_number: 445-5168-1-ND; Height: 0.90MM; Mfr_name: TDK CORPORATION; Mfr_part_number: C1608X5R1A335K080AC; Mistral Part No: 120014070039-R; Package: 0603; Part_type: CAPACITORS\CERAMIC; Project: AEGIS_POM; RoHS: RoHS; Temperature: -55°C+85°C; Tolerance: 10%; Voltage: 10V; Wattage: NA; Weight: NA; Datasheet: Y:\MIS_DATABASE\DATASHEETS\CAPACITORS\TDK_CAP.PDF
P2 P3 = CON_DSUB_9_M: CON DSUB 9POS MALE RT TH; Chkd/date: RAGESH/140311; Crtd /date: MAZHAR/231007; Custom_Duty: 24%; Customs_HS_Code: 85369090; Distributor_name: DIGIKEY; Distributor_part_number: 182-09ME-ND; Height: 12.55MM; Mfr_name: NORCOMP; Mfr_part_number: 182-009-113R531; Mistral Part No: 150009030096-R; Package: THRU-HOLE; Part_type: CONNECTOR\DSUB; Project: SMART VIEW_IP CAMERA; RoHS: RoHS; Temperature: -55° C to +105° C; Datasheet: Y:\MIS_DATABASE\DATASHEETS\CONNECTORS\182-009.PDF
R539 R540 R544 R545 = RESISTOR: RES 33E 1/16W 5% 0402; Alternate_mfr_name_A: AVX CORPORATION; Alternate_mfr_name_B: ROHM; Alternate_mfr_name_C: YAGEO AMERICA; Alternate_mfr_name_D: YAGEO AMERICA; Alternate_mfr_part_number_A: CR05-330J-H; Alternate_mfr_part_number_B: MCR01MZPJ330; Alternate_mfr_part_number_C: 9C04021A33R0JLHF3; Alternate_mfr_part_number_D: RC0402JR-0733RL; Chkd/date: SHREESHAIL/200406; Crtd /date: GEETHA/190406; Custom_Duty: 15%; Customs_HS_Code: 85332119; Distributor_name: DIGIKEY; Distributor_name_A: NA; Distributor_name_B: DIGIKEY; Distributor_name_C: DIGIKEY; Distributor_name_D: DIGIKEY; Distributor_part_number: P33JCT-ND; Distributor_part_number_A: NA; Distributor_part_number_B: RHM33JCT-ND; Distributor_part_number_C: 311-33JCT-ND; Distributor_part_number_D: 311-33JRCT-ND; Height: 0.40MM; Mfr_name: PANASONIC-ECG; Mfr_part_number: ERJ-2GEJ330X; Mistral Part No: 110009030699-R; Package: 0402; Part_type: RESISTORS\FIXED; Project: RED EYE; RoHS: RoHS; Tolerance: 5%; Wattage: 1/16W; Datasheet: Y:\MIS_DATABASE\DATASHEETS\RESISTORS\ERJ12.PDF
R580 R581 = RESISTOR: RES 120E 1/16W 1% 0402; Chkd/date: NAVEED/070814; Crtd /date: VASANTHA/300714; Custom_Duty: 15%; Customs_HS_Code: 85332119; Distributor_name: DIGIKEY; Distributor_part_number: 541-120LCT-ND; Height: 0.40MM; Mfr_name: VISHAY; Mfr_part_number: CRCW0402120RFKED; Mistral Part No: 110014070060-R; Package: 0402; Part_type: RESISTORS\FIXED; Project: AEGIS_POM; RoHS: RoHS; Temperature: NA; Tolerance: 1%; Voltage: NA; Wattage: 1/16W; Weight: NA; Datasheet: Y:\MIS_DATABASE\DATASHEETS\RESISTORS\CRCW0603.PDF
R582 R583 = RESISTOR: RES 0.0E 1/10W JUMP 0603; Chkd/date: VASANTHA/061014; Crtd /date: NAVEED/220714; Custom_Duty: 15%; Customs_HS_Code: 85332119; Distributor_name: DIGIKEY; Distributor_part_number: P0.0GCT-ND; Height: 0.55MM; Mechanical part status: DS CHANGED WEIGHT & TEMP ADDED; Mfr_name: PANASONIC-ECG; Mfr_part_number: ERJ-3GEY0R00V; Mistral Part No: 110014070017-R; Package: 0603; Part_type: RESISTORS\FIXED; Project: DLRU; RoHS: RoHS; Temperature: -55°C+155°C; Tolerance: NA; Voltage: NA; Wattage: 1/10W; Weight: 2/1000g; Datasheet: Y:\MIS_DATABASE\DATASHEETS\RESISTORS\PAN-ERJ-3GE.PDF
U98 U100 = ISO1050DUB_SOP8: IC ISOLATED CAN TRANSCEIVER SOP8; Chkd/date: RAGESH/111110; Crtd /date: MAZHAR/070110; Custom_Duty: 15%; Customs_HS_Code: 85423100; Height: 4.91MM; Mfr_name: TEXAS INSTRUMENTS; Mistral Part No: 141010010003-R; Package: SOP8; Part_type: ICS\INTERFACE\LINE DRIVER; Project: OMAPL138; RoHS: RoHS; Temperature: -55°C to 105°C; Datasheet: Y:\MIS_DATABASE\DATASHEETS\ICS\INTERFACE\ISO1050.PDF
U104 U105 = PSM712_SOT23-3: IC TVS ARRAY DATALINE 600W 43V SOT23; Chkd/date: NAVEED/070814; Crtd /date: VASANTHA/300714; Custom_Duty: 15%; Customs_HS_Code: 85423100; Distributor_name: NA; Distributor_part_number: NA; Height: 1.21MM; Mfr_name: PROYEK; Mistral Part No: 140114070012-R; Package: SOT23-3; Part_type: ICS\ANALOG\ACTIVE FILTER; Project: AEGIS_POM; RoHS: RoHS; Temperature: -55°C+150°C; Tolerance: NA; Voltage: 43V; Wattage: NA; Weight: NA; Datasheet: Y:\MIS_DATABASE\DATASHEETS\ICS\MISC\PSM712.PDF
U118 U119 = R1Z-3.305_HP_SMD10: IC R1Z DC/DC CONVERTER SMD6; Chkd/date: NAVEED/290914; Crtd /date: VASANTHA/010814; Custom_Duty: 15%; Customs_HS_Code: 85423100; Distributor_name: MOUSER; Distributor_part_number: 919-R1Z-3.305/HP; Height: 9.00MM; Mfr_name: RECOM; Mistral Part No: 142014080002-R; Package: SMD10; Part_type: ICS\POWER\DC-DC CONVERTER; Project: AEGIS_POM; RoHS: RoHS; Temperature: -40°C+70°C; Tolerance: NA; Voltage: NA; Wattage: NA; Weight: NA; Datasheet: Y:\MIS_DATABASE\DATASHEETS\ICS\POWER\R1Z.PDF

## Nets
DGND: C15.2 C19.2 C21.2 C65.1 C68.1 C83.2 C84.2 C313.2 C314.2 C317.2 C318.1 C320.1 C321.2 C357.2 C358.2 C360.2 C361.2 C362.2 C368.2 C703.1 C708.2 C709.2 C752.2 C754.2 C762.2 C763.1 C775.2 J2.2 J2.3 J2.6 J2.9 J2.18 J2.19 J2.22 J2.37 J2.42 J2.47 J2.60 J2.63 J2.64 J2.77 J2.83 J2.87 J2.92 J2.95 J2.97 J34.41(GND1) J34.42(GND2) J34.43(GND3) J34.44(GND4) R73.2 R571.1 R572.1 R573.1 R574.1 R575.1 R576.1 R637.1 R638.1 R829.1 R839.1 R840.1 R841.1 U8.6(GND) U8.9(PAD) U98.4(GND1) U100.4(GND1) U106.3(GND) U118.1(-VIN) U119.1(-VIN) U125.8(GND1) U125.9(GND2) U126.8(GND1) U126.9(GND2) U128.8(GND1) U128.9(GND2) U140.3(GND) ; also on sheet 1 11 12 13 14 15 16 17 18 19 20 21 22 23 24 25 26 27 28 29 33 34 35 36 37 38 39 40 41 42 43 44 45 46 47 48 49 50
GND_CAN0: C347.2 C353.2 C753.2 P2.3 P2.5 P2.6 R582.2 U100.5(GND2) U105.3 U118.4(-VOUT_1) U118.5(-VOUT_2)
GND_CAN1: C345.2 C352.2 C755.2 P3.3 P3.5 P3.6 R583.2 U98.5(GND2) U104.3 U119.4(-VOUT_1) U119.5(-VOUT_2)
GNDSHLD0: P2.10 P2.11 R582.1
GNDSHLD1: P3.10 P3.11 R583.1
VCC1V8_WLAN: C15.1 C65.2 C68.2 C368.1 C762.1 FB8.2 FB9.2 J2.8 R52.1 R53.1 R54.1 R55.1 R56.1 R57.1 R58.1 R69.1 R138.2 R139.2 U125.16(VCCB) U126.16(VCCB) U128.16(VCCB)
VCC3V3_DC_CONN: C752.1 C754.1 U118.2(+VIN) U119.2(+VIN) ; also on sheet 26 50
VCC3V3_DCIN: C318.2 C320.2 C703.2 C775.1 FB7.1 FB48.1 U98.1(VCC1) U100.1(VCC1) U106.5(VCC) U140.5(VCC) ; also on sheet 11 17 18 19 20 21 22 23 24 25 26 27 28 29 33 34 35 36 37 38 43 44 45 46 47 48 50
VCC3V3_MLB: C708.1 C709.1 FB48.2 J34.37 J34.38 J34.39 R854.2
VCC3V3_WLAN: C83.1 C84.1 C763.2 FB7.2 R609.1 R830.2 R838.2 R842.2 R843.2 U125.1(VCCA) U126.1(VCCA) U128.1(VCCA) ; also on sheet 24
VCC5V0_DCDC: C19.1 U8.1(IN1) U8.2(IN2) ; also on sheet 21 22 27 44 46 48 49 50
VCC12V0_DC_IN: FL11.1 ; also on sheet 1 26 33 34 47 48 50
VCC12V0_MLB: C357.1 C358.1 C360.1 FL11.2 J34.40
BT_EN: U128.6(2A1) ; also on sheet 35
BUF_I2C1_SCL: R579.2 ; also on sheet 33
BUF_I2C1_SDA: R578.2 ; also on sheet 33
COM8_AUD_CLK: U125.4(1A1) ; also on sheet 24
COM8_AUD_FSYNC: U125.5(1A2) ; also on sheet 24
COM8_MCASP2AXR1: U128.4(1A1) ; also on sheet 24
COM8_MCASP2AXR4: U125.6(2A1) ; also on sheet 24
COM8_MMC1_CLK: J2.20 R58.2 ; also on sheet 24
COM8_MMC1_CMD: J2.24 R57.2 ; also on sheet 24
COM8_MMC1_DAT0: J2.26 R56.2 ; also on sheet 24
COM8_MMC1_DAT1: J2.28 R55.2 ; also on sheet 24
COM8_MMC1_DAT2: J2.30 R54.2 ; also on sheet 24
COM8_MMC1_DAT3: J2.32 R53.2 ; also on sheet 24
COM_AUD_CLK: J2.52 R51.1
COM_AUD_FSYNC: J2.54 R50.1
COM_AUD_IN: J2.56 R49.1
COM_AUD_OUT: J2.58 R48.1
COM_BTRST: J2.89 R590.2
COM_BTUARTCTS: J2.70 R61.1
COM_BTUARTDEBUG: J2.76 TP31.1(TP)
COM_BTUARTRTS: J2.72 R60.1
COM_BTUARTRX: J2.68 R62.1
COM_BTUARTTX: J2.66 R63.1
COM_GPIO9: J2.78 TP30.1(TP)
COM_GPIO10: J2.100 TP33.1(TP)
COM_GPIO11: J2.96 TP35.1(TP)
COM_GPIO12: J2.98 TP34.1(TP)
COM_SLOW_CLK: J2.1 R593.2
COM_WL_IRQ: J2.34 R52.2 R605.1
COM_WL_RS232_RX: J2.13 TP25.1(TP)
COM_WL_RS232_TX: J2.11 TP26.1(TP)
COM_WL_RST: J2.4 R59.1
COM_WL_UART_DBG: J2.15 TP23.1(TP)
LDO1_1V8: FB9.1 ; also on sheet 13 18 23 24 36 48
LDO2_1V8: FB8.1 ; also on sheet 23 24 48
MLB_RSTn: U106.1(A) ; also on sheet 47
MLB_RSTn_AND: J34.25 R854.1 U140.4(Y)
SOC_DCAN0_RX: C314.1 J26.2 R545.1 U1.R5(DCAN0_RX/GPIO1_57)
SOC_DCAN0_TX: R544.1 U1.P5(DCAN0_TX/GPIO1_56)
SOC_DCAN1_RX: C313.1 J25.2 R540.1 U1.H21(QSPI_CSn3/DCAN1_RX/PR1_UART0_RTSN/GPIO1_67/USB1_EXT_TRIGGER)
SOC_DCAN1_TX: R539.1 U1.H22(QSPI_CSn2/DCAN1_TX/PR1_UART0_CTSN/GPIO1_66/USB0_EXT_TRIGGER)
SOC_MLB_GPIO2: J34.24 ; also on sheet 12
SOC_MLB_PCLKN: J27.2 J34.17 R572.2 R773.1 U1.L23(MLBP_CLK_N)
SOC_MLB_PCLKP: J27.1 J34.19 R571.2 R773.2 U1.M23(MLBP_CLK_P)
SOC_MLB_PDATDN: J28.2 J34.9 R574.2 R775.1 U1.K22(MLBP_DAT_N)
SOC_MLB_PDATDP: J28.1 J34.11 R573.2 R775.2 U1.K23(MLBP_DAT_P)
SOC_MLB_PSIGN: J29.2 J34.1 R576.2 R774.1 U1.M24(MLBP_SIG_N)
SOC_MLB_PSIGP: J29.1 J34.3 R575.2 R774.2 U1.L24(MLBP_SIG_P)
SOC_MLBCLK: J34.2 J48.3 U1.AA24(GPMC_WAIT1/MLB_CLK/GPIO0_23)
SOC_MLBDAT: J34.10 J48.1 U1.W24(GPMC_CSn1/MLB_DAT/GPIO0_27)
SOC_MLBSIG: J34.6 J48.2 U1.AA25(GPMC_DIR/MLB_SIG/GPIO0_25)
SOC_RESETSTATz: U106.2(B) ; also on sheet 11 17 18 21 22 23 25 26 33 45 46
SOC_UART1_CTSn: U126.7(2A2) ; also on sheet 28
SOC_UART1_RTSn: U126.5(1A2) ; also on sheet 28
SOC_UART1_RXD: U126.6(2A1) ; also on sheet 28
SOC_UART1_TXD: U126.4(1A1) ; also on sheet 28
VCAN0: C347.1 C353.1 C753.1 P2.9 U100.8(VCC2) U118.7(+VOUT)
VCAN1: C345.1 C352.1 C755.1 P3.9 U98.8(VCC2) U119.7(+VOUT)
VCOM_BAT: C21.1 C27.1 FB2.1 R82.1 U8.3(OUT1) U8.4(OUT2)
VCOM_BAT_FB: C361.1 C362.1 FB2.2 J2.5 J2.7
VCOM_BATEN: R69.2 R609.2 U8.8(EN)
VCOM_BATFB: C27.2 R73.1 R82.2 U8.5(NR/FB)
WL_BT_EN: R139.1 R590.1 R637.2 U128.11(2B1)
WL_MCASP2_ACLKR: R51.2 U125.13(1B1)
WL_MCASP2_AXR1: R49.2 U128.13(1B1)
WL_MCASP2_AXR4: R48.2 R829.2 U125.11(2B1)
WL_MCASP2_FSR: R50.2 U125.12(1B2)
WL_UART1_CTSn: R60.2 U126.10(2B2)
WL_UART1_RTSn: R61.2 U126.12(1B2)
WL_UART1_RXD: R63.2 U126.11(2B1)
WL_UART1_TXD: R62.2 U126.13(1B1)
WL_WLAN_CLK: R593.1 U128.10(2B2)
WL_WLAN_EN: R59.2 R138.1 R638.2 U128.12(1B2)
WL_WLAN_IRQ: R605.2 U125.10(2B2)
WLAN_EN: U128.5(1A2) ; also on sheet 35
WLAN_IRQ: U125.7(2A2) ; also on sheet 12
WLAN_SLOW_CLK: U128.7(2A2) ; also on sheet 17 49
WLAN_TRANS_EN: R830.1 U125.14(~{2OE}) U125.15(~{1OE}) U126.14(~{2OE}) U126.15(~{1OE}) U128.14(~{2OE}) U128.15(~{1OE}) ; also on sheet 24 33
N17104917: J2.35 TP17.1(TP)
N17104924: J2.39 TP18.1(TP)
N17105134: J2.62 TP14.1(TP)
N17105148: J2.48 TP15.1(TP)
N17105158: J2.50 TP16.1(TP)
N19351417: J34.33 R579.1
N19351424: J34.35 R578.1
N19354929: U106.4(Y) U140.2(A)
N19355586: J34.16 TP174.1(TP)
N19356463: J34.34 TP179.1(TP)
N19508261: P3.7 R580.1 U98.7(CANH) U104.1
N19508263: P3.2 R580.2 U98.6(CANL) U104.2
N19508331: R540.2 U98.2(RXD)
N19508333: C317.1 J25.1 R539.2 U98.3(TXD)
N19510567: P2.7 R581.1 U100.7(CANH) U105.1
N19510569: P2.2 R581.2 U100.6(CANL) U105.2
N19510637: R545.2 U100.2(RXD)
N19510639: C321.1 J26.1 R544.2 U100.3(TXD)
N23455572: R839.2 U126.3(2DIR)
N23499910: R840.2 U125.3(2DIR)
N23499916: R841.2 R842.1 U125.2(1DIR)
N23506369: R843.1 U128.2(1DIR) U128.3(2DIR)
N23636920: R838.1 U126.2(1DIR)

Not connected (* = marked no-connect by the designer): J2 10* 12* 14* 16* 17* 21* 23* 25* 27* 29* 31* 33* 36* 38* 40* 41* 43* 44* 45* 46* 49* 51* 53* 55* 57* 59* 61* 65* 67* 69* 71* 73* 74* 75* 79* 80* 81* 82* 84* 85* 86* 88* 90* 91* 93* 94* 99*; J34 4* 5* 7* 8* 12* 13* 14* 15* 18* 20* 21* 22* 23* 26* 27* 28* 29* 30* 31* 32* 36*; P2 1* 4* 8*; P3 1* 4* 8*; U8 7(NC)*; U118 10(NC)*; U119 10(NC)*; U140 1(NC)*

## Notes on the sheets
sheet 30
- COM8  CONNECTOR
- COM8  LEVEL TRANSLATOR1
- TO MAKE EMMC DEFAULT ,
  TRANSLATOR IS DISABLED
- COM8  LEVEL TRANSLATOR2
- NOTE:
  MMC1 IS BY DEFAULT CONNECTED TO EMMC.
  IF COM8 TO BE USED RESISTOR RA6, R387,
  R388 & R822 SHOULD BE DNI AND MOUNT
  RA15, R713, R714, R393 SHOULD BE MOUNTED
- CONNECTION ON COM8 IS FOLLOWED AS PER
  AM437x GP EVM. THESE ARE GPIOS ARE NOT USED
  IN AM437x GP EVM, SO WE PROVIDED AS TEST POINTS
- COM8 VBAT GENERATION
- COM8  LEVEL TRANSLATOR3
sheet 31
- MLB CONNECTOR
- This GPIO was followed as per JC5 EVM
  We freed up from SOC GPIO
sheet 32
- DCAN0
- DCAN0 POWER
- DCAN1
- DCAN1 POWER
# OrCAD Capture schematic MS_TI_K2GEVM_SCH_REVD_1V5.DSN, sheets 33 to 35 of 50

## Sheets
33 32. AUDIO EXP CON: size C; title: AUDIO EXP CONNECTOR
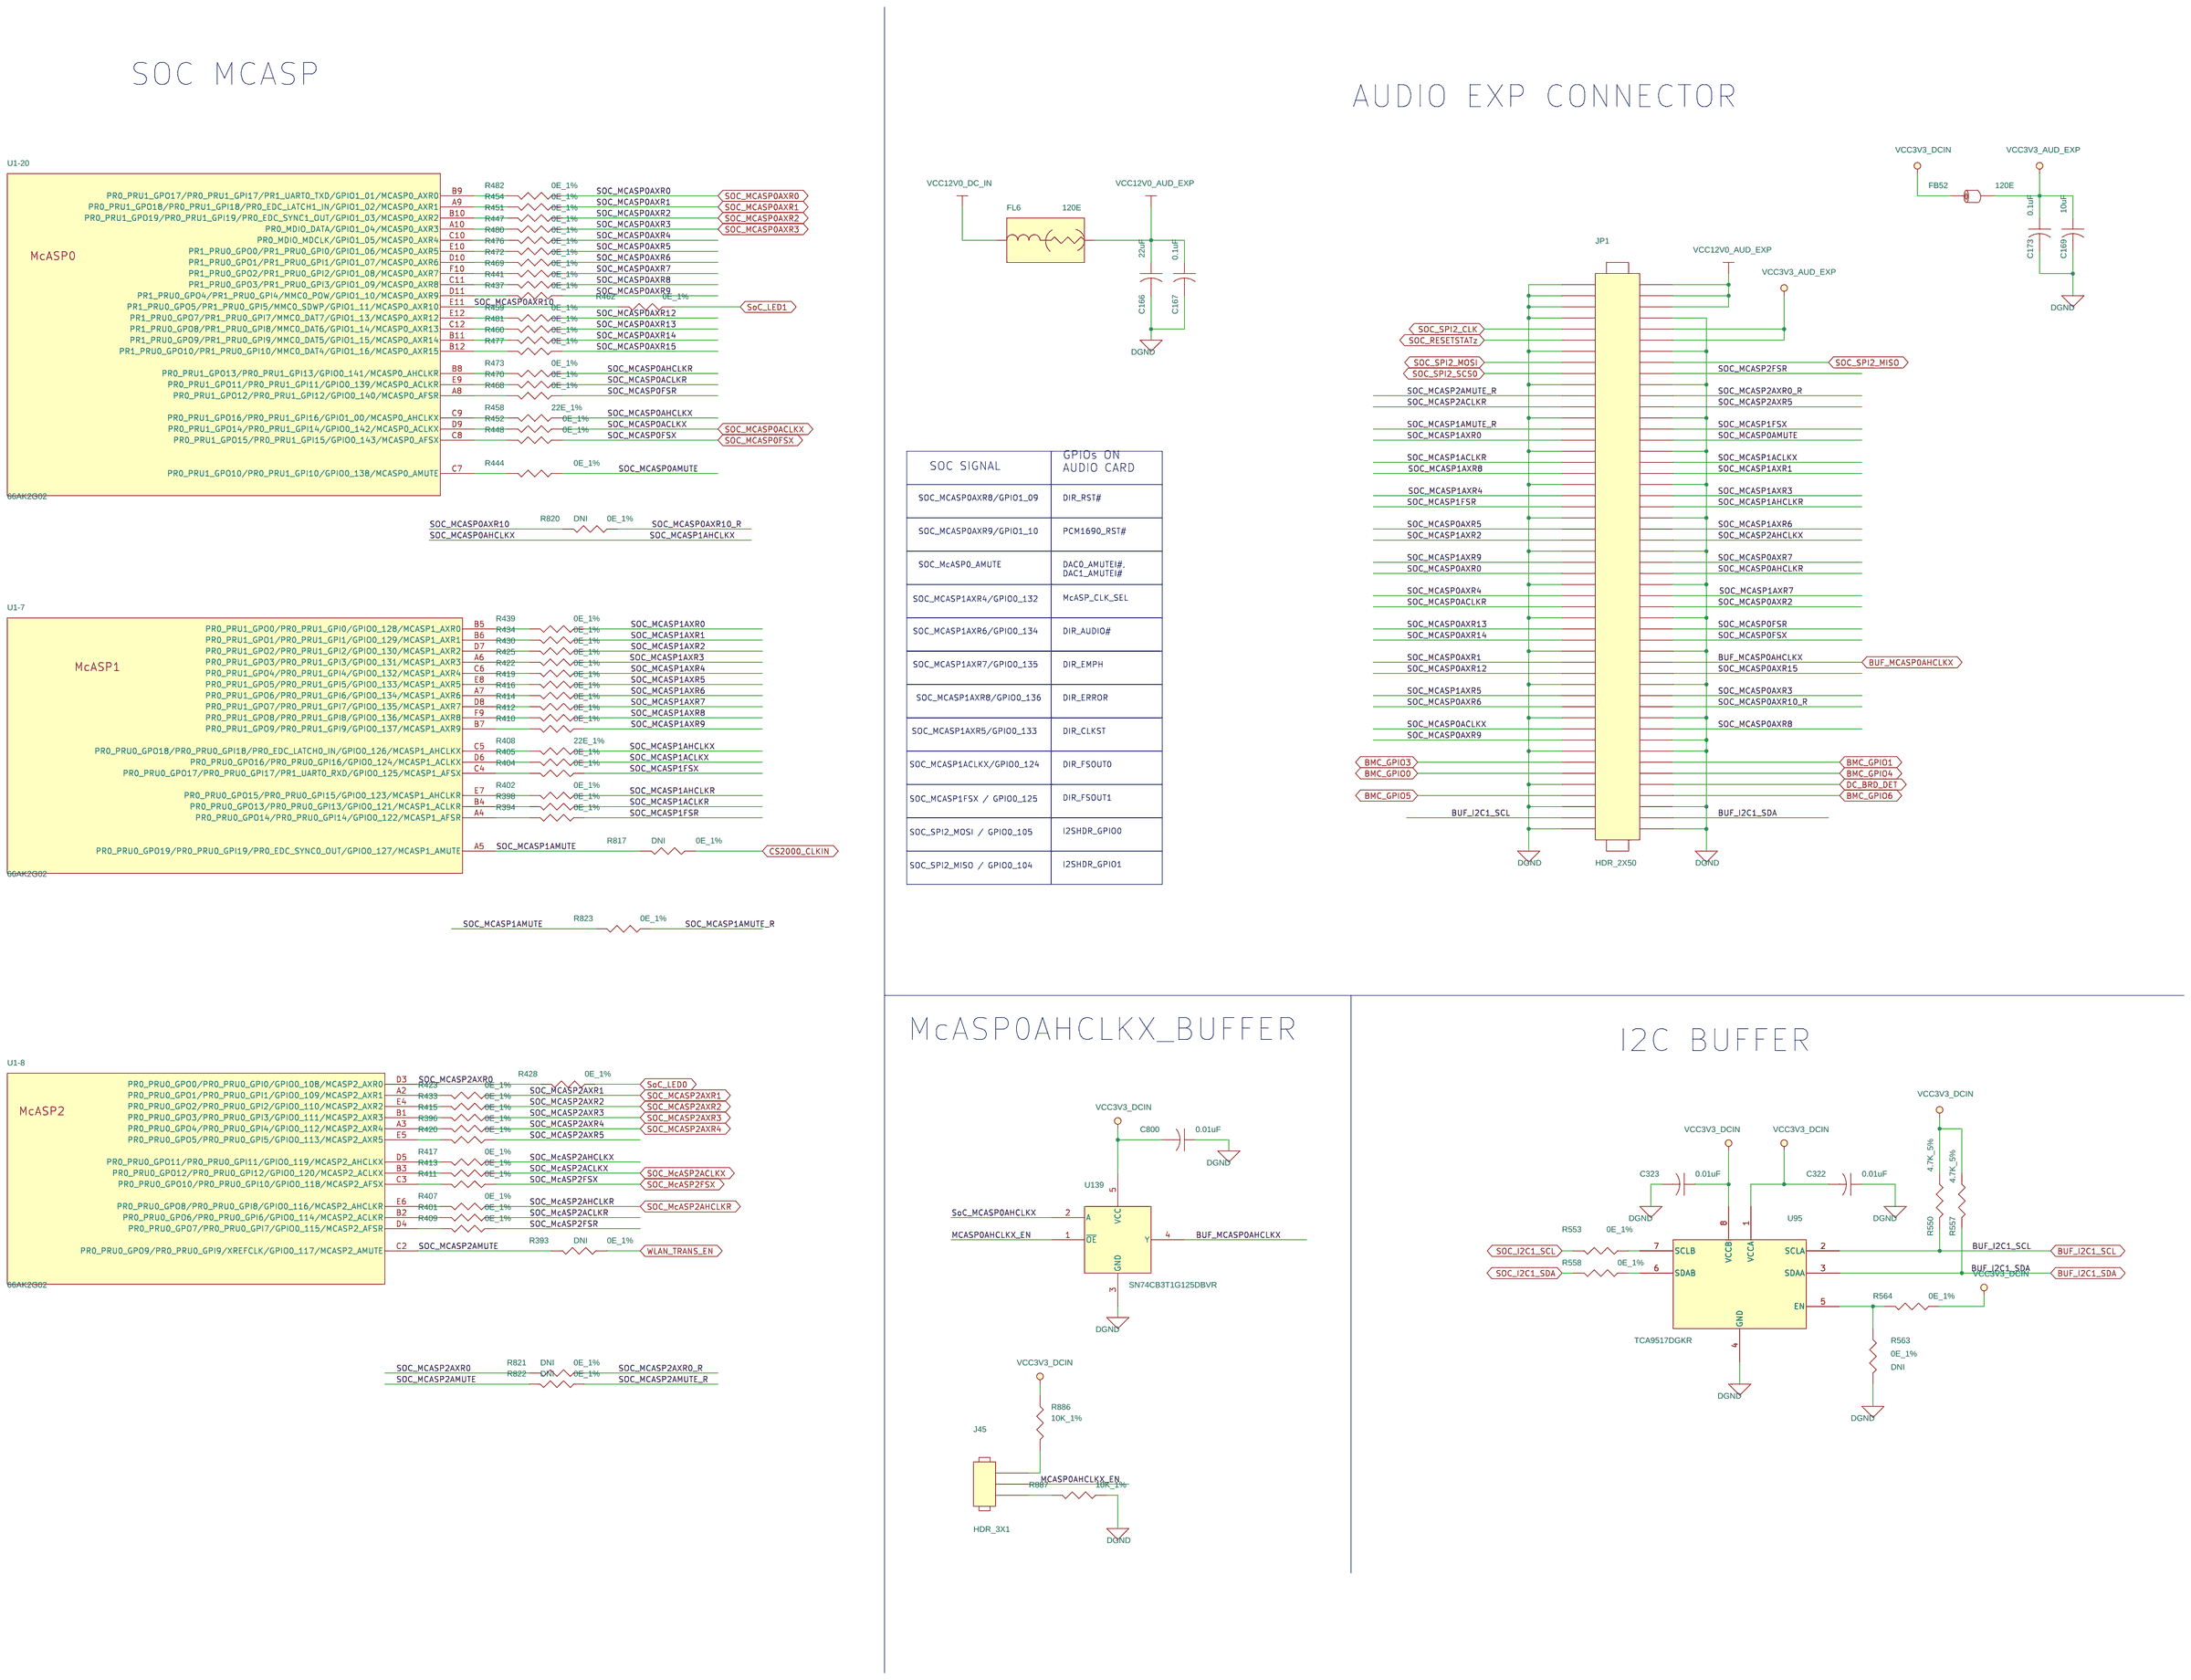
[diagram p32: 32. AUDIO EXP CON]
34 33. SERIAL & EHRPWM EXP CON: size C; title: SERIAL & EHRPWM EXP CONNECTOR
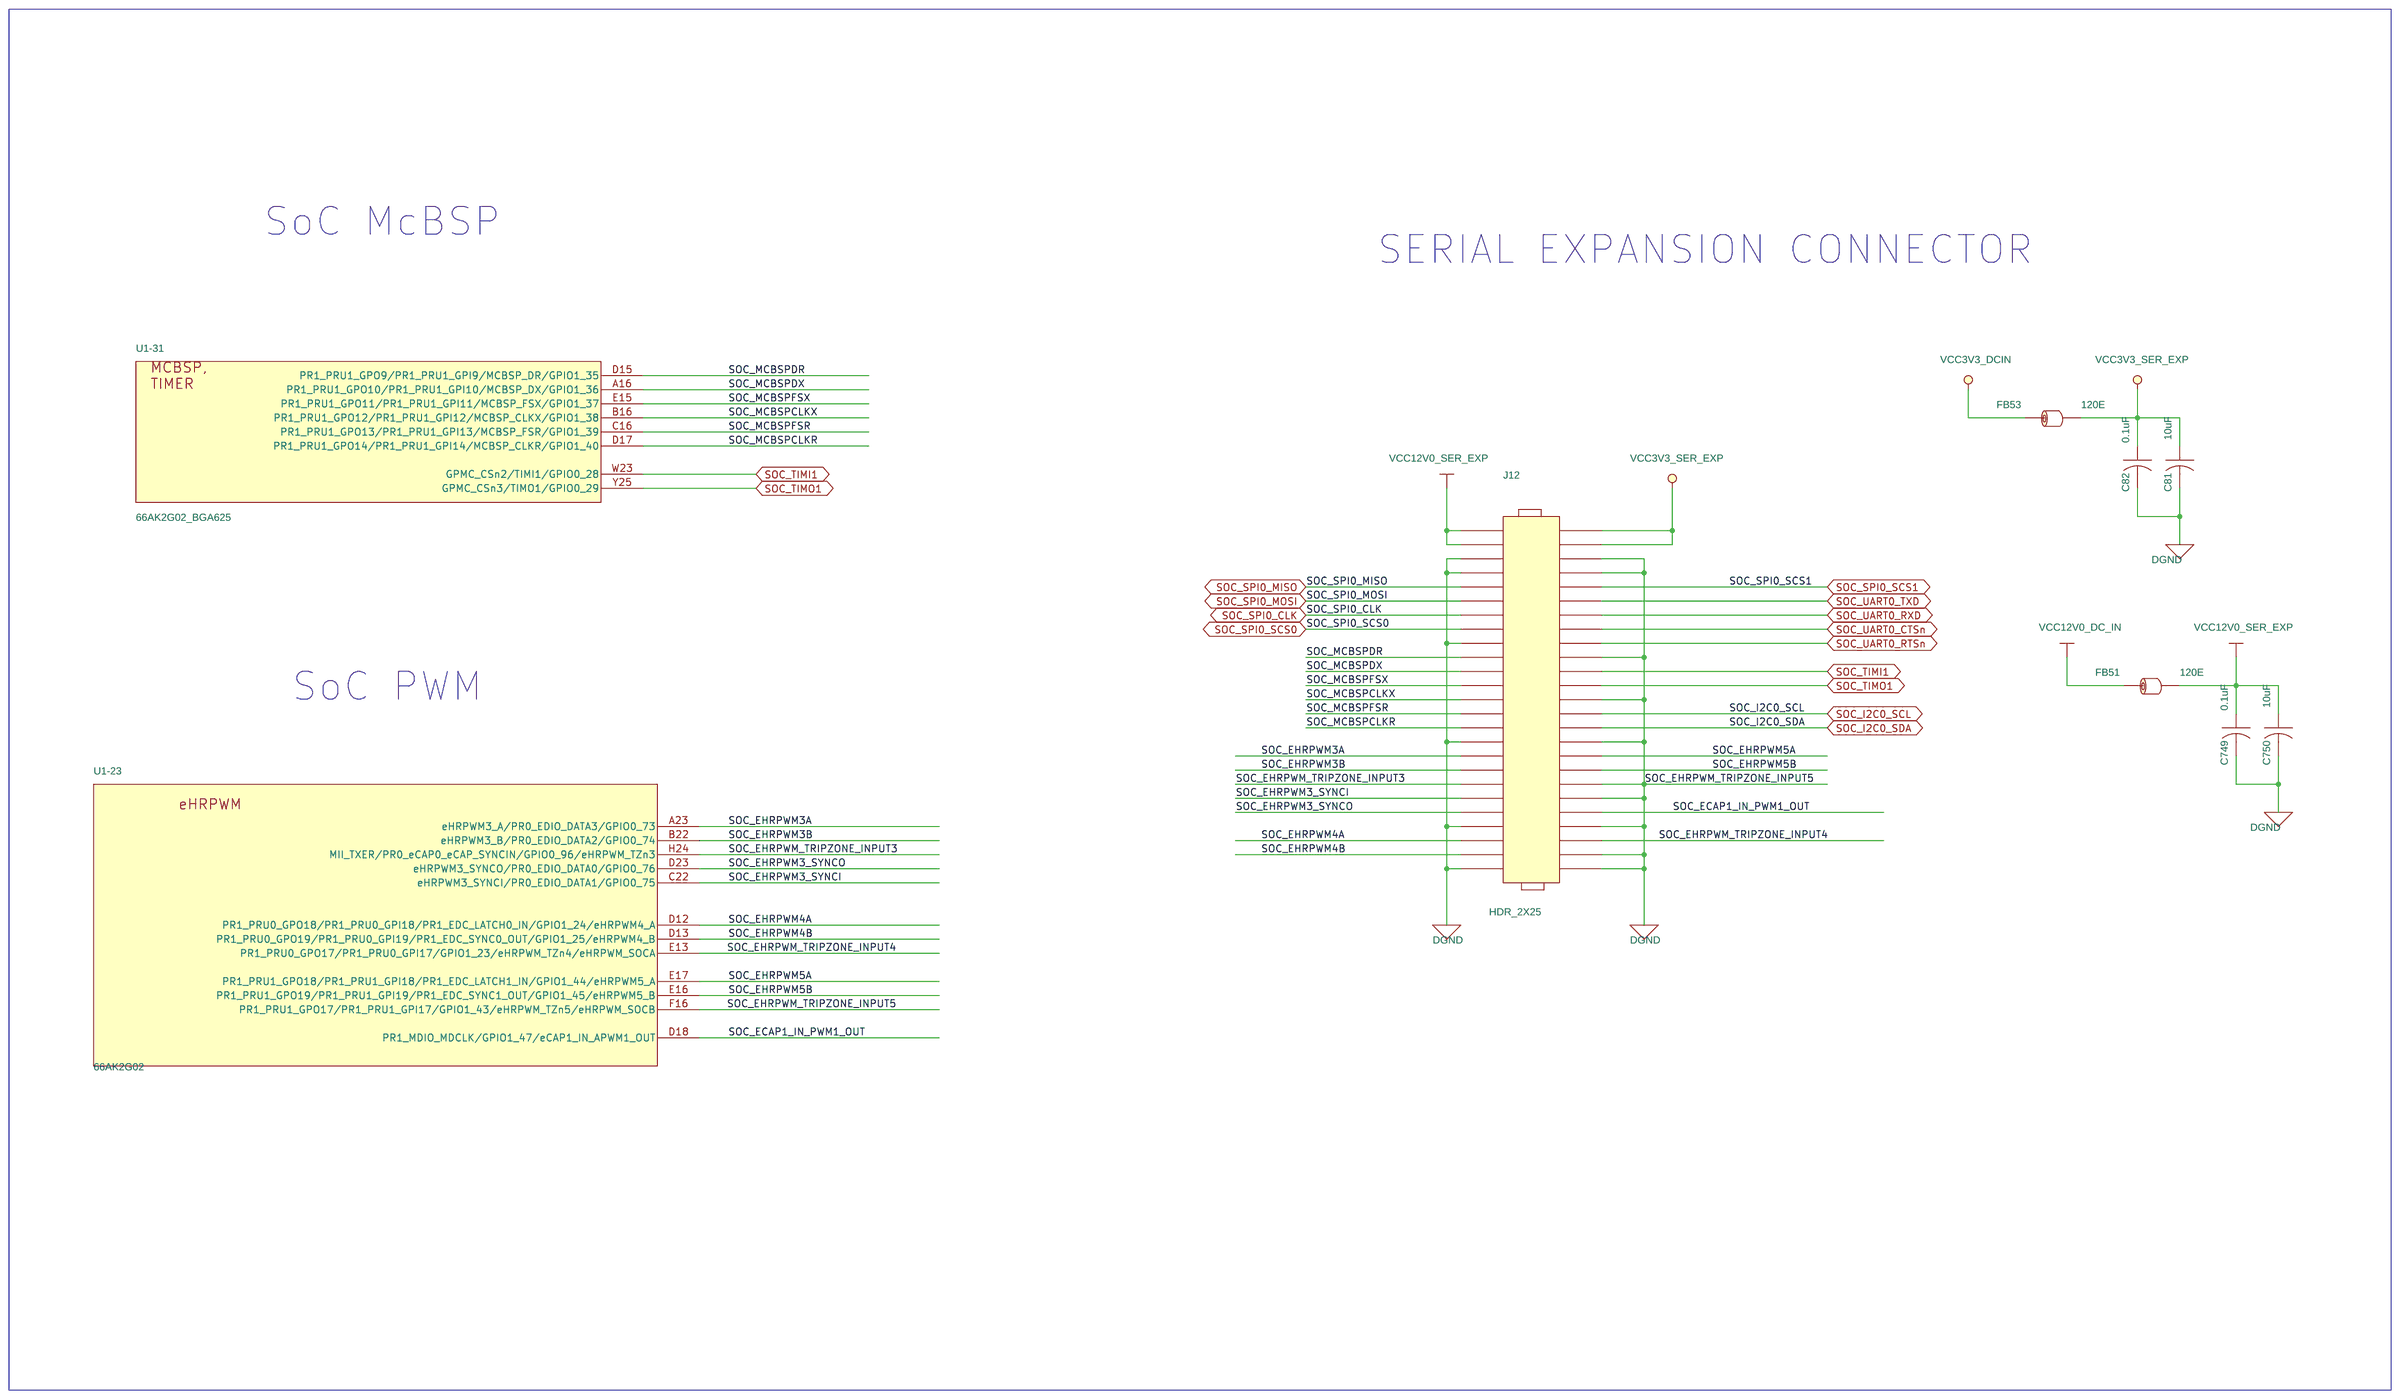
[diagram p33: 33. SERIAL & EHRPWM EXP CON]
35 34. SERIAL CONTROL INTERFACE: size C; title: SERIAL CONTROL INTERFACE

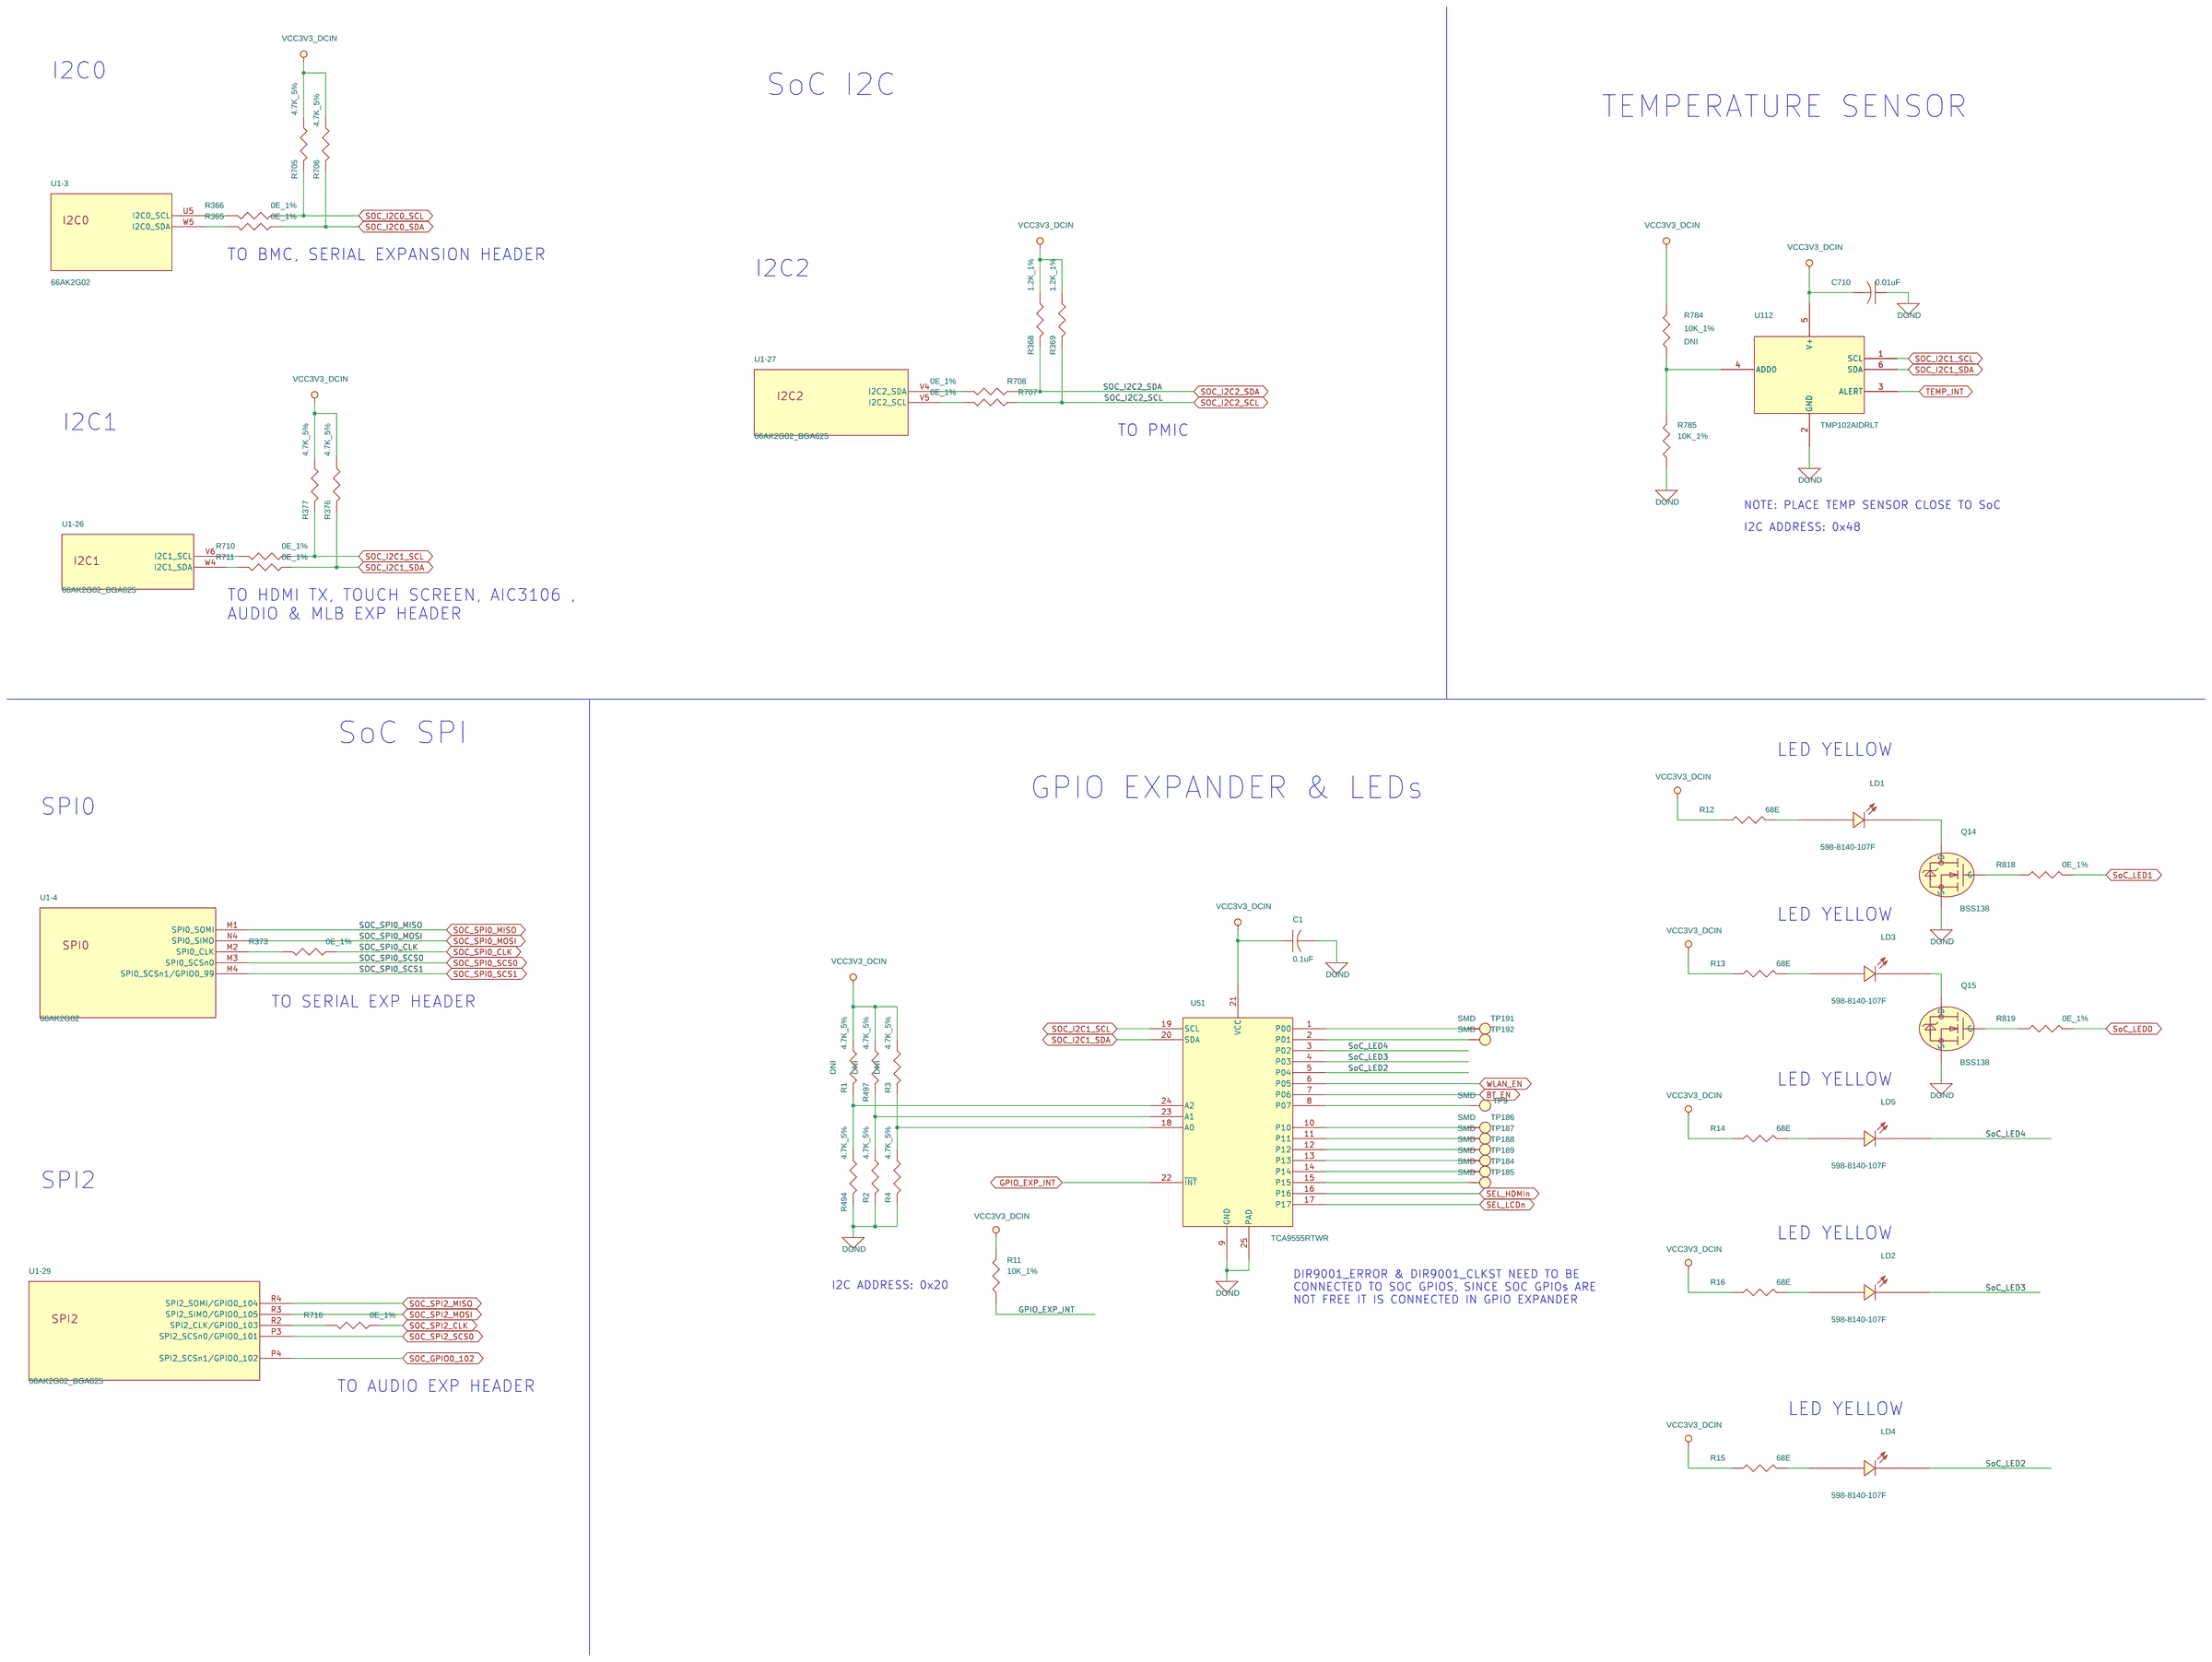
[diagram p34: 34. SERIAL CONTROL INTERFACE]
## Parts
sheet 18. NAND FLASH & MICRO SD CARD
U1  66AK2G02_BGA625  [BGASKT625_31-49_1270x1270]  (sections -1,-10,-11,-12,-13,-14,-15,-16,-17,-18,-19,-2,-20,-21,-22,-23,-24,-25,-26,-27,-28,-29,-3,-30,-31,-32,-33,-34,-35,-36,-37,-38,-4,-5,-6,-7,-8,-9)
sheet 32. AUDIO EXP CON
C166  22uF  [CAP1210]
C167  0.1uF  [CAP0402]
C169  10uF  [CAP0805]
C173  0.1uF  [CAP0402]
C322  0.01uF  [CAP0402]
C323  0.01uF  [CAP0402]
C800  0.01uF  [CAP0402]
FB52  120E  [IND0402]
FL6  120E  [EMIFIL_BLM18R_0603]
J45  HDR_3X1  [HDR_3X1_100_S_T]
JP1  HDR_2X50  [HDR_2X50_100_S_T]
R393  0E_1%  [RES0402]
R394  0E_1%  [RES0402]
R396  0E_1%  [RES0402]
R398  0E_1%  [RES0402]
R401  0E_1%  [RES0402]
R402  0E_1%  [RES0402]
R404  0E_1%  [RES0402]
R405  0E_1%  [RES0402]
R407  0E_1%  [RES0402]
R408  22E_1%  [RES0402]
R409  0E_1%  [RES0402]
R410  0E_1%  [RES0402]
R411  0E_1%  [RES0402]
R412  0E_1%  [RES0402]
R413  0E_1%  [RES0402]
R414  0E_1%  [RES0402]
R415  0E_1%  [RES0402]
R416  0E_1%  [RES0402]
R417  0E_1%  [RES0402]
R419  0E_1%  [RES0402]
R420  0E_1%  [RES0402]
R422  0E_1%  [RES0402]
R423  0E_1%  [RES0402]
R425  0E_1%  [RES0402]
R428  0E_1%  [RES0402]
R430  0E_1%  [RES0402]
R433  0E_1%  [RES0402]
R434  0E_1%  [RES0402]
R437  0E_1%  [RES0402]
R439  0E_1%  [RES0402]
R441  0E_1%  [RES0402]
R444  0E_1%  [RES0402]
R447  0E_1%  [RES0402]
R448  0E_1%  [RES0402]
R451  0E_1%  [RES0402]
R452  0E_1%  [RES0402]
R454  0E_1%  [RES0402]
R458  22E_1%  [RES0402]
R459  0E_1%  [RES0402]
R460  0E_1%  [RES0402]
R462  0E_1%  [RES0402]
R468  0E_1%  [RES0402]
R469  0E_1%  [RES0402]
R470  0E_1%  [RES0402]
R472  0E_1%  [RES0402]
R473  0E_1%  [RES0402]
R476  0E_1%  [RES0402]
R477  0E_1%  [RES0402]
R480  0E_1%  [RES0402]
R481  0E_1%  [RES0402]
R482  0E_1%  [RES0402]
R550  4.7K_5%  [RES0402]
R553  0E_1%  [RES0402]
R557  4.7K_5%  [RES0402]
R558  0E_1%  [RES0402]
R563  0E_1%  [RES0402]
R564  0E_1%  [RES0402]
R817  0E_1%  [RES0402]
R820  0E_1%  [RES0402]
R821  0E_1%  [RES0402]
R822  0E_1%  [RES0402]
R823  0E_1%  [RES0402]
R886  10K_1%  [RES0402]
R887  10K_1%  [RES0402]
U95  TCA9517DGKR  [VSSOP8_25-59_120X120]
U139  SN74CB3T1G125DBVR  [SOT23-5]
sheet 33. SERIAL & EHRPWM EXP CON
C81  10uF  [CAP0805]
C82  0.1uF  [CAP0402]
C749  0.1uF  [CAP0402]
C750  10uF  [CAP0805]
FB51  120E  [IND0402]
FB53  120E  [IND0402]
J12  HDR_2X25  [HDR_2x25_100_S_T]
sheet 34. SERIAL CONTROL INTERFACE
C1  0.1uF  [CAP0402]
C710  0.01uF  [CAP0402]
LD1  598-8140-107F  [LED_0805]
LD2  598-8140-107F  [LED_0805]
LD3  598-8140-107F  [LED_0805]
LD4  598-8140-107F  [LED_0805]
LD5  598-8140-107F  [LED_0805]
Q14  BSS138  [TO_SOT23-123]
Q15  BSS138  [TO_SOT23-123]
R1  4.7K_5%  [RES0402]
R2  4.7K_5%  [RES0402]
R3  4.7K_5%  [RES0402]
R4  4.7K_5%  [RES0402]
R11  10K_1%  [RES0402]
R12  68E  [RES0402]
R13  68E  [RES0402]
R14  68E  [RES0402]
R15  68E  [RES0402]
R16  68E  [RES0402]
R365  0E_1%  [RES0402]
R366  0E_1%  [RES0402]
R368  1.2K_1%  [RES0603]
R369  1.2K_1%  [RES0603]
R373  0E_1%  [RES0402]
R376  4.7K_5%  [RES0402]
R377  4.7K_5%  [RES0402]
R494  4.7K_5%  [RES0402]
R497  4.7K_5%  [RES0402]
R705  4.7K_5%  [RES0402]
R706  4.7K_5%  [RES0402]
R707  0E_1%  [RES0402]
R708  0E_1%  [RES0402]
R710  0E_1%  [RES0402]
R711  0E_1%  [RES0402]
R716  0E_1%  [RES0402]
R784  10K_1%  [RES0402]
R785  10K_1%  [RES0402]
R818  0E_1%  [RES0402]
R819  0E_1%  [RES0402]
TP9  SMD  [TP40_SMD]
TP184  SMD  [TP40_SMD]
TP185  SMD  [TP40_SMD]
TP186  SMD  [TP40_SMD]
TP187  SMD  [TP40_SMD]
TP188  SMD  [TP40_SMD]
TP189  SMD  [TP40_SMD]
TP191  SMD  [TP40_SMD]
TP192  SMD  [TP40_SMD]
U51  TCA9555RTWR  [QFN24_19-68_165X165]
U112  TMP102AIDRLT  [SOT563-6]

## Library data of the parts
U1 = 66AK2G02_BGA625: IC ARM CORTEX AND DSP 32 BIT MICROPROCESSOR BGA625; Chkd/date: NAVEED/141114; Color: Default; Crtd /date: VASANTHA/081014; Custom_Duty: 15%; Customs_HS_Code: 85423100; Distributor_name: NA; Distributor_part_number: NA; Height: 1.70MM; Location X-Coordinate: 0; Location Y-Coordinate: 0; Mfr_name: TEXAS INSTRUMENTS; Mfr_part_number: 66AK2G02; Mistral Part No: 141014100003; Package: BGA625; Part_type: ICS\DIGITAL\MICROPROCESSOR; Power Pins Visible: False; Primitive: DEFAULT; Project: GALILEO_EVM; Tolerance: NA; Voltage: NA; Wattage: NA; Weight: NA; Datasheet: Y:\MIS_DATABASE\DATASHEETS\ICS\DIGITAL\MICROCONTROLLER\SG-BGA-6094.PDF    Y:\MIS_DATABASE\DATASHEETS\ICS\DIGITAL\MICROCONTROLLER\SG-BGA_FP.PDF
C166 = CAP: CAP CERAMIC 22uF 25V 10% X7R 1210; Chkd/date: BAVISH/040311; Crtd /date: MAZHAR/190111; Custom_Duty: 15%; Customs_HS_Code: 85322990; Distributor_name: DIGIKEY; Distributor_part_number: 490-5313-1-ND; Height: 2.70MM; Mfr_name: MURATA; Mfr_part_number: GRM32ER71E226KE15L; Mistral Part No: 120011010016-R; Package: 1210; Part_type: CAPACITORS\CERAMIC; Project: ITS-PWR_CARD; RoHS: RoHS; Temperature: -55°C+125°C; Tolerance: 10%; Voltage: 25V; Wattage: NA; Weight: NA; Datasheet: Y:\MIS_DATABASE\DATASHEETS\CAPACITORS\GRM32,43,55.PDF
C167 = CAP: CAP CERAMIC 0.1uF 50V 10% X7R 0402; Alternate_mfr_name_A: TDK CORPORATION; Alternate_mfr_part_number_A: CGA2B3X7R1H104K; Chkd/date: BAVISH/081111; Crtd /date: CHAITHANYA/051011; Custom_Duty: 15%; Customs_HS_Code: 85322990; Distributor_name: DIGIKEY; Distributor_name_A: DIGIKEY; Distributor_part_number: 445-5932-1-ND; Distributor_part_number_A: 445-6899-1-ND; Height: 0.55MM; Mfr_name: TDK CORPORATION; Mfr_part_number: C1005X7R1H104K; Mistral Part No: 120011100014-R; Package: 0402; Part_type: CAPACITORS\CERAMIC; Project: VP-4000-BASE-BOARD; RoHS: RoHS; Temperature: -55°C+125°C; Tolerance: 10%; Voltage: 50V; Wattage: NA; Weight: NA; Datasheet: Y:\MIS_DATABASE\DATASHEETS\CAPACITORS\C1005X7.PDF
C81 C169 C750 = CAP: CAP CERAMIC 10uF 16V 10% X5R 0805; Alternate_mfr_name_A: TAIYO YUDEN; Alternate_mfr_part_number_A: EMK212BJ106KG-T; Chkd/date: RAVI/020511; Crtd /date: BAVISH/290411; Custom_Duty: 15%; Customs_HS_Code: 85322990; Distributor_name: DIGIKEY; Distributor_name_A: DIGIKEY; Distributor_part_number: 478-5165-1-ND; Distributor_part_number_A: 587-1295-1-ND; Height: 1.40MM; Mfr_name: AVX CORPORATION; Mfr_part_number: 0805YD106KAT2A; Mistral Part No: 120011040011-R; Package: 0805; Part_type: CAPACITORS\CERAMIC; Project: AOD_POD-RF; RoHS: RoHS; Temperature: -55°C+85°C; Tolerance: 10%; Voltage: 16V; Wattage: NA; Weight: NA; Datasheet: Y:\MIS_DATABASE\DATASHEETS\CAPACITORS\AVX_CERAMIC.PDF
C1 C82 C173 C749 = CAP: CAP CERAMIC 0.1uF 16V 10% X7R 0402; Alternate_mfr_name_A: KEMET; Alternate_mfr_part_number_A: C0402C104K4RACT; Chkd/date: MAZHAR/281108; Crtd /date: MAZHAR/030907; Custom_Duty: 15%; Customs_HS_Code: 85322990; Distributor_name: DIGIKEY; Distributor_name_A: DIGIKEY; Distributor_part_number: 490-3261-1-ND; Distributor_part_number_A: 399-3521-1-ND; Height: 0.55MM; Mfr_name: MURATA; Mfr_part_number: GRM155R71C104KA88D; Mistral Part No: 120009030060-R; Package: 0402; Part_type: CAPACITORS\CERAMIC; Project: SMART VIEW_IP CAMERA; Tolerance: 10%; Voltage: 16V; Datasheet: Y:\MIS_DATABASE\DATASHEETS\CAPACITORS\GRM188SERIES.PDF
C322 C323 C710 C800 = CAP: CAP CERAMIC 0.01uF 16V 10% X7R 0402; Alternate_mfr_name_A: AVX CORPORATION; Alternate_mfr_name_B: KEMET; Alternate_mfr_name_D: TDK CORPORATION; Alternate_mfr_part_number_A: 0402YC103KAT2A; Alternate_mfr_part_number_B: C0402C103K4RACTU; Alternate_mfr_part_number_D: C1005X7R1C103K; Chkd/date: SHREESHAIL/180506; Crtd /date: MAZHAR/110506; Custom_Duty: 15%; Customs_HS_Code: 85322990; Distributor_name: DIGIKEY; Distributor_name_A: DIGIKEY; Distributor_name_B: DIGIKEY; Distributor_name_D: DIGIKEY; Distributor_part_number: PCC103BQCT-ND; Distributor_part_number_A: 478-1114-1-ND; Distributor_part_number_B: 399-1038-1-ND; Distributor_part_number_D: 445-1262-1-ND; Height: 0.55MM; Mfr_name: PANASONIC-ECG; Mfr_part_number: ECJ-0EB1C103K; Mistral Part No: 120009030032-R; Package: 0402; Part_type: CAPACITORS\CERAMIC; Project: VOCERA; RoHS: RoHS; Tolerance: 10%; Voltage: 16V; Datasheet: Y:\MIS_DATABASE\DATASHEETS\CAPACITORS\PAN-ECJ.PDF
FB51-FB53 = INDUCTOR_FERRITE: IND BEAD CHIP 120E 1.2A 0402; Chkd/date: ASHOK/240212; Crtd /date: BAVISH/060711; Custom_Duty: 24%; Customs_HS_Code: 85437099; Distributor_name: DIGIKEY; Distributor_part_number: 445-2981-1-ND; Height: 0.55MM; Mfr_name: TDK CORPORATION; Mfr_part_number: MPZ1005S121C; Mistral Part No: 130011070007-R; Package: 0402; Part_type: INDUCTOR; Project: SVDU; RoHS: RoHS; Temperature: -40°C+85°C; Tolerance: NA; Voltage: NA; Wattage: NA; Weight: 1mg; Datasheet: Y:\MIS_DATABASE\DATASHEETS\DISCRETES\INDUCTORS\MPZ1005.PDF
FL6 = EMIFILTER_IND: FERRITE BEAD 120E 2A 0603; Chkd/date: RAGESH/111010; Crtd /date: MUDDU/190610; Custom_Duty: 24%; Customs_HS_Code: 85437099; Distributor_name: DIGIKEY; Distributor_part_number: 490-3991-1-ND; Height: 0.95MM; Mfr_name: MURATA; Mfr_part_number: BLM18EG121SN1D; Mistral Part No: 130010060030-R; Package: 0603; Part_type: MISC\FILTER; Project: CENTAURUS; Temperature: -55°C+125°C; Weight: NA; Datasheet: Y:\MIS_DATABASE\DATASHEETS\DISCRETES\INDUCTORS\BLM18E.PDF
J45 = HEADER_3X1: CON HDR 3X1 2.54MM PITCH ST TH; Chkd/date: MAZHAR/100311; Crtd /date: BAVISH/160211; Custom_Duty: 24%; Customs_HS_Code: 85369090; Distributor_name: DIGIKEY; Distributor_part_number: A26545-ND; Height: 10.74MM; Mfr_name: TYCO ELECTRONICS; Mfr_part_number: 87224-3; Mistral Part No: 150011020004-R; Package: THRU-HOLE; Part_type: CONNECTOR\HEADERS; Project: OMAPL1_PEC20; RoHS: RoHS; Temperature: NA; Tolerance: NA; Voltage: NA; Wattage: NA; Weight: NA; Datasheet: Y:\MIS_DATABASE\DATASHEETS\CONNECTORS\87224.PDF
JP1 = HEADER_50X2: CON HDR 2X50 2.54MM PITCH ST TH; Chkd/date: NAVEED/241114; Crtd /date: VASANTHA/281014; Custom_Duty: 24%; Customs_HS_Code: 85369090; Distributor_name: DIGIKEY; Distributor_part_number: SAM1082-50-ND; Height: 8.38MM; Mfr_name: SAMTEC; Mfr_part_number: TSW-150-26-T-D; Mistral Part No: 150014100037-R; Package: THRU-HOLE; Part_type: CONNECTOR\HEADERS; Project: GALILEO_EVM; RoHS: RoHS; Temperature: -55°C+105°C; Tolerance: NA; Voltage: NA; Wattage: NA; Weight: NA; Datasheet: Y:\MIS_DATABASE\DATASHEETS\CONNECTORS\X-TSW-SERIES.PDF
R393 R563 R817 R820-R822 = RESISTOR: RES 0E 1/16W 1% 0402; Chkd/date: MAZHAR/220709; Crtd /date: USMAN/270109; Custom_Duty: 15%; Customs_HS_Code: 85332119; Distributor_name: NA; Distributor_part_number: NA; Height: 0.40MM; Loading: DNI; Mfr_name: YAGEO AMERICA; Mfr_part_number: RC0402FR-070RL; Mistral Part No: 110009030085-P; Package: 0402; Part_type: RESISTORS\FIXED; Project: OMAP_EVM; RoHS: Pb-Free; Tolerance: 1%; Wattage: 1/16W; Datasheet: Y:\MIS_DATABASE\DATASHEETS\RESISTORS\CRCW0603.PDF
R365 R366 R373 R394 R396 R398 R401 R402 R404 R405 R407 R409-R417 R419 R420 R422 R423 R425 R428 R430 R433 R434 R437 R439 R441 R444 R447 R448 R451 R452 R454 R459 R460 R462 R468-R470 R472 R473 R476 R477 R480-R482 R553 R558 R564 R707 R708 R710 R711 R716 R818 R819 R823 = RESISTOR: RES 0E 1/16W 1% 0402; Chkd/date: MAZHAR/220709; Crtd /date: USMAN/270109; Custom_Duty: 15%; Customs_HS_Code: 85332119; Distributor_name: NA; Distributor_part_number: NA; Height: 0.40MM; Mfr_name: YAGEO AMERICA; Mfr_part_number: RC0402FR-070RL; Mistral Part No: 110009030085-P; Package: 0402; Part_type: RESISTORS\FIXED; Project: OMAP_EVM; RoHS: Pb-Free; Tolerance: 1%; Wattage: 1/16W; Datasheet: Y:\MIS_DATABASE\DATASHEETS\RESISTORS\CRCW0603.PDF
R408 R458 = RESISTOR: RES 22E 1/16W 1% 0402; Alternate_mfr_name_A: VISHAY; Alternate_mfr_part_number_A: CRCW040222R0FKED; Chkd/date: SUHAS/290910; Crtd /date: MAZHAR/090909; Custom_Duty: 15%; Customs_HS_Code: 85332119; Distributor_name: DIGIKEY; Distributor_name_A: DIGIKEY; Distributor_part_number: 311-22.0LRCT-ND; Distributor_part_number_A: 541-22.0LCT-ND; Height: 0.40MM; Mfr_name: YAGEO AMERICA; Mfr_part_number: RC0402FR-0722RL; Mistral Part No: 110009090004-P; Package: 0402; Part_type: RESISTORS\FIXED; Project: VMEFMCD; Remarks: In alternate datasheet it is RoHS COMPLIANT. Y:\MIS_DATABASE\DATASHEETS\RESISTORS\CRCW0402.PDF; RoHS: Pb-Free; Temperature: -55°C+155°C; Tolerance: 1%; Voltage: 50V; Wattage: 1/16W; Weight: 0.8g/1000pcs; Datasheet: Y:\MIS_DATABASE\DATASHEETS\RESISTORS\YAGEO-RC0402.PDF
R2 R4 R376 R377 R494 R550 R557 R705 R706 = RESISTOR: RES 4.7K 1/16W 5% 0402; Chkd/date: VASANTHA/190614; Crtd /date: NAVEED/160614; Custom_Duty: 15%; Customs_HS_Code: 85332119; Distributor_name: DIGIKEY; Distributor_part_number: RMCF0402JT4K70CT-ND; Height: 0.40MM; Mfr_name: STACKPOLE ELECTRONICS; Mfr_part_number: RMCF0402JT4K70; Mistral Part No: 110014060028-R; Package: 0402; Part_type: RESISTORS\FIXED; Project: AEGIS_POM; RoHS: RoHS; Temperature: -55°C+155°C; Tolerance: 5%; Voltage: NA; Wattage: 1/16W; Weight: NA; Datasheet: Y:\MIS_DATABASE\DATASHEETS\RESISTORS\RMCF-SERIES1.PDF
R11 R785 R886 R887 = RESISTOR: RES 10K 1/16W 1% 0402; Alternate_mfr_name_A: AVX CORPORATION; Alternate_mfr_name_B: PANASONIC-ECG-ECG; Alternate_mfr_name_C: YAGEO AMERICA; Alternate_mfr_name_D: VISHAY; Alternate_mfr_part_number_A: CR05-103F-H; Alternate_mfr_part_number_B: ERJ-2RKF1002X; Alternate_mfr_part_number_C: 9C04021A1002FLHF3; Alternate_mfr_part_number_D: CRCW040210K0FKED; Chkd/date: SHREESHAIL/310506; Crtd /date: GEETHA/290506; Custom_Duty: 15%; Customs_HS_Code: 85332119; Distributor_name: DIGIKEY; Distributor_name_A: NA; Distributor_name_B: DIGIKEY; Distributor_name_C: DIGIKEY; Distributor_name_D: DIGIKEY; Distributor_part_number: 311-10.0KLRTR-ND; Distributor_part_number_A: NA; Distributor_part_number_B: P10.0KLCT-ND; Distributor_part_number_C: 311-10.0KLCT-ND; Distributor_part_number_D: 541-10.0KLCT-ND; Height: 0.40MM; Mfr_name: YAGEO AMERICA; Mfr_part_number: RC0402FR-0710KL; Mistral Part No: 110009030220-P; Package: 0402; Part_type: RESISTORS\FIXED; Project: VOCERA; RoHS: Pb-Free; Tolerance: 1%; Wattage: 1/16W; Datasheet: Y:\MIS_DATABASE\DATASHEETS\RESISTORS\YAGEO-RC0402.PDF
U95 = TCA9517DGKR_VSSOP8: IC 2-CHANNEL I2C BUS REPEATER VSSOP8; Chkd/date: USMAN/161213; Crtd /date: USMAN/161213; Custom_Duty: 15%; Customs_HS_Code: 85423100; Distributor_name: DIGIKEY; Distributor_part_number: 296-35972-1-ND; Height: 1.10MM; Mfr_name: TEXAS INSTRUMENTS; Mistral Part No: 141013120007-R; Package: VSSOP8; Part_type: ICS\DIGITAL\BUSTRANSCEIVER; Project: DMP; RoHS: RoHS; Temperature: -40°C+85°C; Tolerance: NA; Voltage: NA; Wattage: NA; Weight: NA; Datasheet: Y:\MIS_DATABASE\DATASHEETS\ICS\DIGITAL\BUSTRANSCEIVER\TCA9517D.PDF
U139 = SN74LVC1G125_SOT23-5: IC SWITCH BUS FET HIGH SPEED WITH LEVEL SHIFTER SOT23-5; Chkd/date: NAVEED/090415; Crtd /date: JEBRAN/010415; Custom_Duty: 15%; Customs_HS_Code: 85423100; Distributor_name: DIGIKEY; Distributor_part_number: 296-19150-1-ND; Height: 1.45MM; Mfr_name: TEXAS INSTRUMENTS; Mistral Part No: 141015040002-R; Part_type: ICS\DIGITAL\COMBINATIONAL; Project: GALILEO EVM; RoHS: RoHS; Temperature: -40°C+85°C; Tolerance: NA; Voltage: NA; Wattage: NA; Weight: NA; Datasheet: Y:\MIS_DATABASE\DATASHEETS\ICS\DIGITAL\COMBINATIONAL\SN74CB3T1G125DBVR.PDF
J12 = HEADER_25X2: CON HDR 2X25 2.54MM PITCH ST TH; Chkd/date: NAVEED/080415; Crtd /date: JEBRAN/300315; Custom_Duty: 24%; Customs_HS_Code: 85369090; Distributor_name: DIGIKEY; Distributor_part_number: SAM1082-25-ND; Height: 8.38MM; Mfr_name: SAMTEC; Mfr_part_number: TSW-125-26-T-D; Mistral Part No: 150015030016-R; Package: THRU-HOLE; Part_type: CONNECTOR\HEADERS; Project: GALILEO EVM; RoHS: RoHS; Temperature: -55°C+105°C; Tolerance: NA; Voltage: NA; Wattage: NA; Weight: NA; Datasheet: Y:\MIS_DATABASE\DATASHEETS\CONNECTORS\TSW-106-23-T-S.PDF
LD1-LD5 = LED_598-8170-107F: LED ALINGAP YELLOW CLEAR 0805 SMD; Chkd/date: BALACHANDAR/160514; Crtd /date: SARANYA/070514; Custom_Duty: 24%; Customs_HS_Code: 85437099; Distributor_name: DIGIKEY; Distributor_part_number: 350-2041-1-ND; Height: 0.70MM; Mfr_name: DIALIGHT; Mistral Part No: 130014050066-R; Package: 0805; Part_type: OPTO\LED; Project: AEGIS GP BETA2; RoHS: RoHS; Temperature: NA; Tolerance: NA; Voltage: NA; Wattage: NA; Weight: NA; Datasheet: Y:\MIS_DATABASE\DATASHEETS\DISCRETES\LEDS\598-SER.PDF
Q14 Q15 = MOSFET_BSS138: IC MOSFET N-CHANNEL 50V 200mA SOT23-3; Chkd/date: SUHAS/191010; Crtd /date: USMAN/240709; Custom_Duty: 15%; Customs_HS_Code: 85423100; Distributor_name: DIGIKEY; Distributor_part_number: BSS138CT-ND; Height: 1.20MM; Mfr_name: DIODES INC; Mfr_part_number: BSS138-7-F; Mistral Part No: 142009070019-R; Package: SOT23-3; Part_type: ICS\POWER\MOSFET; Project: KHAN_MAIN; RoHS: RoHS; Temperature: -55°C+150°C; Voltage: 50V; Wattage: 300mW; Weight: 0.008g; Datasheet: Y:\MIS_DATABASE\DATASHEETS\DISCRETES\TRANSISTORS_FETS\BSS138.PDF
R1 R3 R497 = RESISTOR: RES 4.7K 1/16W 5% 0402; Chkd/date: VASANTHA/190614; Crtd /date: NAVEED/160614; Custom_Duty: 15%; Customs_HS_Code: 85332119; Distributor_name: DIGIKEY; Distributor_part_number: RMCF0402JT4K70CT-ND; Height: 0.40MM; LOADING: DNI; Mfr_name: STACKPOLE ELECTRONICS; Mfr_part_number: RMCF0402JT4K70; Mistral Part No: 110014060028-R; Package: 0402; Part_type: RESISTORS\FIXED; Project: AEGIS_POM; RoHS: RoHS; Temperature: -55°C+155°C; Tolerance: 5%; Voltage: NA; Wattage: 1/16W; Weight: NA; Datasheet: Y:\MIS_DATABASE\DATASHEETS\RESISTORS\RMCF-SERIES1.PDF
R12-R16 = RESISTOR: RES 68E 1/16W 5% 0402; Chkd/date: SHREESHAIL/210406; Crtd /date: GEETHA/200406; Custom_Duty: 15%; Customs_HS_Code: 85332119; Distributor_name: DIGIKEY; Distributor_part_number: P68JCT-ND; Height: 0.40MM; Mfr_name: PANASONIC-ECG; Mfr_part_number: ERJ-2GEJ680X; Mistral Part No: 110009031078-R; Package: 0402; Part_type: RESISTORS\FIXED; Project: RED EYE; RoHS: RoHS; Tolerance: 5%; Wattage: 1/16W; Datasheet: Y:\MIS_DATABASE\DATASHEETS\RESISTORS\ERJ12.PDF
R368 R369 = RESISTOR: RES 1.2K 1/10W 1% 0603; Chkd/date: MAZHAR/041208; Crtd /date: USMAN/180708; Custom_Duty: 15%; Customs_HS_Code: 85332119; Distributor_name: DIGIKEY; Distributor_part_number: P1.20KHCT-ND; Height: 0.55MM; Mfr_name: PANASONIC-ECG; Mfr_part_number: ERJ-3EKF1201V; Mistral Part No: 110009030109-R; Package: 0603; Part_type: RESISTORS\FIXED; Project: REVA-IBMS; RoHS: RoHS; Tolerance: 1%; Wattage: 1/10W; Datasheet: Y:\MIS_DATABASE\DATASHEETS\RESISTORS\PAN_ERJ.PDF
R784 = RESISTOR: RES 10K 1/16W 1% 0402; Alternate_mfr_name_A: AVX CORPORATION; Alternate_mfr_name_B: PANASONIC-ECG-ECG; Alternate_mfr_name_C: YAGEO AMERICA; Alternate_mfr_name_D: VISHAY; Alternate_mfr_part_number_A: CR05-103F-H; Alternate_mfr_part_number_B: ERJ-2RKF1002X; Alternate_mfr_part_number_C: 9C04021A1002FLHF3; Alternate_mfr_part_number_D: CRCW040210K0FKED; Chkd/date: SHREESHAIL/310506; Crtd /date: GEETHA/290506; Custom_Duty: 15%; Customs_HS_Code: 85332119; Distributor_name: DIGIKEY; Distributor_name_A: NA; Distributor_name_B: DIGIKEY; Distributor_name_C: DIGIKEY; Distributor_name_D: DIGIKEY; Distributor_part_number: 311-10.0KLRTR-ND; Distributor_part_number_A: NA; Distributor_part_number_B: P10.0KLCT-ND; Distributor_part_number_C: 311-10.0KLCT-ND; Distributor_part_number_D: 541-10.0KLCT-ND; Height: 0.40MM; Loading: DNI; Mfr_name: YAGEO AMERICA; Mfr_part_number: RC0402FR-0710KL; Mistral Part No: 110009030220-P; Package: 0402; Part_type: RESISTORS\FIXED; Project: VOCERA; RoHS: Pb-Free; Tolerance: 1%; Wattage: 1/16W; Datasheet: Y:\MIS_DATABASE\DATASHEETS\RESISTORS\YAGEO-RC0402.PDF
TP9 TP184-TP189 TP191 TP192 = TESTPOINT: TESTPOINT 40 SMD; Chkd/date: MAZHAR/190505; Crtd /date: MAZHAR/190505; Distributor_name: NA; Distributor_part_number: NA; Height: NA; Mfr_name: LOCAL; Mistral Part No: 130009030933; Part_type: MISC\TESTPOINT; Project: RAINIER-3
U51 = TCA9555RTWR_WQFN24: IC I/O EXPANDER I2C BUS 16-BIT WQFN24; Chkd/date: USMAN/120913; Crtd /date: VIJAYALAKSHMI/200813; Distributor_name: DIGIKEY; Distributor_part_number: 296-24857-1-ND; Height: 0.80MM; Mfr_name: TEXAS INSTRUMENTS; Mistral Part No: 141013080010-R; Package: WQFN24; Part_type: ICS\DIGITAL\BUSTRANSCEIVER; Project: RTM; RoHS: RoHS; Temperature: -40°C+85°C; Tolerance: NA; Voltage: NA; Wattage: NA; Weight: NA; Datasheet: Y:\MIS_DATABASE\DATASHEETS\ICS\DIGITAL\BUSTRANSCEIVER\TCA9555X.PDF
U112 = TMP102AIDRLT_SOT563-6: IC DIGITAL TEMPERATURE SENSOR WITH SERIAL INTERFACE SOT563-6; Chkd/date: RAGESH/060411; Crtd /date: USMAN/060709; Custom_Duty: 15%; Customs_HS_Code: 85423100; Distributor_name: DIGIKEY; Distributor_part_number: 296-22055-1-ND; Height: 0.60MM; Mfr_name: TEXAS INSTRUMENTS; Mistral Part No: 141009070003-R; Part_type: ICS\DIGITAL\PERIPHERAL; Project: FMC-A100; RoHS: RoHS; Temperature: -55°C+150°C; Weight: NA; Datasheet: Y:\MIS_DATABASE\DATASHEETS\ICS\DIGITAL\PERIPHERAL\TMP102AIDRL.PDF

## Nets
DGND: C1.2 C81.2 C82.2 C166.2 C167.2 C169.2 C173.2 C322.1 C323.2 C710.1 C749.2 C750.2 C800.1 J12.5 J12.6 J12.7 J12.8 J12.17 J12.20 J12.26 J12.31 J12.32 J12.40 J12.43 J12.44 J12.48 J12.49 J12.50 JP1.1 JP1.3 JP1.5 JP1.7 JP1.8 JP1.13 JP1.14 JP1.19 JP1.20 JP1.25 JP1.26 JP1.31 JP1.32 JP1.37 JP1.38 JP1.43 JP1.44 JP1.49 JP1.50 JP1.55 JP1.56 JP1.61 JP1.62 JP1.67 JP1.68 JP1.73 JP1.74 JP1.79 JP1.80 JP1.84 JP1.85 JP1.86 JP1.91 JP1.95 JP1.96 JP1.99 JP1.100 Q14.2(S) Q15.2(S) R2.2 R4.2 R494.2 R563.2 R785.1 R887.2 U51.9(GND) U51.25(PAD) U95.4(GND) U112.2(GND) U139.3(GND) ; also on sheet 1 11 12 13 14 15 16 17 18 19 20 21 22 23 24 25 26 27 28 29 30 31 32 36 37 38 39 40 41 42 43 44 45 46 47 48 49 50
VCC3V3_AUD_EXP: C169.1 C173.1 FB52.2 JP1.10 JP1.12
VCC3V3_DCIN: C1.1 C322.2 C323.1 C710.2 C800.2 FB52.1 FB53.1 R1.1 R3.1 R11.2 R12.1 R13.1 R14.1 R15.1 R16.1 R368.1 R369.1 R376.1 R377.1 R497.1 R550.1 R557.1 R564.1 R705.1 R706.1 R784.2 R886.2 U51.21(VCC) U95.1(VCCA) U95.8(VCCB) U112.5(V+) U139.5(VCC) ; also on sheet 11 17 18 19 20 21 22 23 24 25 26 27 28 29 30 31 32 36 37 38 43 44 45 46 47 48 50
VCC3V3_SER_EXP: C81.1 C82.1 FB53.2 J12.2 J12.4
VCC12V0_AUD_EXP: C166.1 C167.1 FL6.2 JP1.2 JP1.4 JP1.6
VCC12V0_DC_IN: FB51.1 FL6.1 ; also on sheet 1 26 31 47 48 50
VCC12V0_SER_EXP: C749.1 C750.1 FB51.2 J12.1 J12.3
BMC_GPIO0: JP1.89 ; also on sheet 45
BMC_GPIO1: JP1.88 ; also on sheet 45
BMC_GPIO3: JP1.87 ; also on sheet 45
BMC_GPIO4: JP1.90 ; also on sheet 45
BMC_GPIO5: JP1.93 ; also on sheet 45
BMC_GPIO6: JP1.94 ; also on sheet 45
BT_EN: U51.7(P06) ; also on sheet 30
BUF_I2C1_SCL: JP1.97 R550.2 U95.2(SCLA) ; also on sheet 31
BUF_I2C1_SDA: JP1.98 R557.2 U95.3(SDAA) ; also on sheet 31
BUF_MCASP0AHCLKX: JP1.70 U139.4(Y) ; also on sheet 22
CS2000_CLKIN: R817.1 ; also on sheet 29 37
DC_BRD_DET: JP1.92 ; also on sheet 12 22 45
GPIO_EXP_INT: R11.1 U51.22(~{INT}) ; also on sheet 12
MCASP0AHCLKX_EN: J45.2 U139.1(~{OE})
SEL_HDMIn: U51.16(P16) ; also on sheet 20
SEL_LCDn: U51.17(P17) ; also on sheet 20 21
SOC_ECAP1_IN_PWM1_OUT: J12.42 U1.D18(PR1_MDIO_MDCLK/GPIO1_47/eCAP1_IN_APWM1_OUT)
SOC_EHRPWM3_SYNCI: J12.39 U1.C22(eHRPWM3_SYNCI/PR0_EDIO_DATA1/GPIO0_75)
SOC_EHRPWM3_SYNCO: J12.41 U1.D23(eHRPWM3_SYNCO/PR0_EDIO_DATA0/GPIO0_76)
SOC_EHRPWM3A: J12.33 U1.A23(eHRPWM3_A/PR0_EDIO_DATA3/GPIO0_73)
SOC_EHRPWM3B: J12.35 U1.B22(eHRPWM3_B/PR0_EDIO_DATA2/GPIO0_74)
SOC_EHRPWM4A: J12.45 U1.D12(PR1_PRU0_GPO18/PR1_PRU0_GPI18/PR1_EDC_LATCH0_IN/GPIO1_24/eHRPWM4_A)
SOC_EHRPWM4B: J12.47 U1.D13(PR1_PRU0_GPO19/PR1_PRU0_GPI19/PR1_EDC_SYNC0_OUT/GPIO1_25/eHRPWM4_B)
SOC_EHRPWM5A: J12.34 U1.E17(PR1_PRU1_GPO18/PR1_PRU1_GPI18/PR1_EDC_LATCH1_IN/GPIO1_44/eHRPWM5_A)
SOC_EHRPWM5B: J12.36 U1.E16(PR1_PRU1_GPO19/PR1_PRU1_GPI19/PR1_EDC_SYNC1_OUT/GPIO1_45/eHRPWM5_B)
SOC_EHRPWM_TRIPZONE_INPUT3: J12.37 U1.H24(MII_TXER/PR0_eCAP0_eCAP_SYNCIN/GPIO0_96/eHRPWM_TZn3)
SOC_EHRPWM_TRIPZONE_INPUT4: J12.46 U1.E13(PR1_PRU0_GPO17/PR1_PRU0_GPI17/GPIO1_23/eHRPWM_TZn4/eHRPWM_SOCA)
SOC_EHRPWM_TRIPZONE_INPUT5: J12.38 U1.F16(PR1_PRU1_GPO17/PR1_PRU1_GPI17/GPIO1_43/eHRPWM_TZn5/eHRPWM_SOCB)
SOC_GPIO0_102: U1.P4(SPI2_SCSn1/GPIO0_102) ; also on sheet 45
SOC_I2C0_SCL: J12.28 R366.1 R705.2 ; also on sheet 17 26 45
SOC_I2C0_SDA: J12.30 R365.1 R706.2 ; also on sheet 17 26 45
SOC_I2C1_SCL: R377.2 R553.2 R710.1 U51.19(SCL) U112.1(SCL) ; also on sheet 21 22 23 37
SOC_I2C1_SDA: R376.2 R558.2 R711.1 U51.20(SDA) U112.6(SDA) ; also on sheet 21 22 23 37
SOC_I2C2_SCL: R369.2 R707.1 ; also on sheet 12 49
SOC_I2C2_SDA: R368.2 R708.1 ; also on sheet 12 49
SoC_LED0: R428.1 R819.2
SoC_LED1: R462.1 R818.2
SoC_LED2: LD4.1 U51.5(P04)
SoC_LED3: LD2.1 U51.4(P03)
SoC_LED4: LD5.1 U51.3(P02)
SOC_MCASP0ACLKR: JP1.59 R470.1
SOC_MCASP0ACLKX: JP1.81 R452.1 ; also on sheet 22
SOC_MCASP0AHCLKR: JP1.54 R473.1
SOC_MCASP0AHCLKX: R408.1 R458.1 U139.2(A)
SOC_MCASP0AMUTE: JP1.30 R444.1
SOC_MCASP0AXR0: JP1.53 R482.1 ; also on sheet 22
SOC_MCASP0AXR1: JP1.69 R454.1 ; also on sheet 22
SOC_MCASP0AXR2: JP1.60 R451.1 ; also on sheet 22
SOC_MCASP0AXR3: JP1.76 R447.1 ; also on sheet 22
SOC_MCASP0AXR4: JP1.57 R480.1
SOC_MCASP0AXR5: JP1.45 R476.1
SOC_MCASP0AXR6: JP1.77 R472.1
SOC_MCASP0AXR7: JP1.52 R469.1
SOC_MCASP0AXR8: JP1.82 R441.1
SOC_MCASP0AXR9: JP1.83 R437.1
SOC_MCASP0AXR10: R462.2 R820.2 U1.E11(PR1_PRU0_GPO5/PR1_PRU0_GPI5/MMC0_SDWP/GPIO1_11/MCASP0_AXR10)
SOC_MCASP0AXR10_R: JP1.78 R820.1
SOC_MCASP0AXR12: JP1.71 R459.1
SOC_MCASP0AXR13: JP1.63 R481.1
SOC_MCASP0AXR14: JP1.65 R460.1
SOC_MCASP0AXR15: JP1.72 R477.1
SOC_MCASP0FSR: JP1.64 R468.1
SOC_MCASP0FSX: JP1.66 R448.1 ; also on sheet 22
SOC_MCASP1ACLKR: JP1.33 R398.1
SOC_MCASP1ACLKX: JP1.34 R405.1
SOC_MCASP1AHCLKR: JP1.42 R402.1
SOC_MCASP1AMUTE: R817.2 R823.2 U1.A5(PR0_PRU0_GPO19/PR0_PRU0_GPI19/PR0_EDC_SYNC0_OUT/GPIO0_127/MCASP1_AMUTE)
SOC_MCASP1AMUTE_R: JP1.27 R823.1
SOC_MCASP1AXR0: JP1.29 R439.1
SOC_MCASP1AXR1: JP1.36 R434.1
SOC_MCASP1AXR2: JP1.47 R430.1
SOC_MCASP1AXR3: JP1.40 R425.1
SOC_MCASP1AXR4: JP1.39 R422.1
SOC_MCASP1AXR5: JP1.75 R419.1
SOC_MCASP1AXR6: JP1.46 R416.1
SOC_MCASP1AXR7: JP1.58 R414.1
SOC_MCASP1AXR8: JP1.35 R412.1
SOC_MCASP1AXR9: JP1.51 R410.1
SOC_MCASP1FSR: JP1.41 R394.1
SOC_MCASP1FSX: JP1.28 R404.1
SOC_MCASP2ACLKR: JP1.23 R401.1
SOC_McASP2ACLKX: R413.1 ; also on sheet 24
SOC_McASP2AHCLKR: R407.1 ; also on sheet 37
SOC_MCASP2AHCLKX: JP1.48 R417.1
SOC_MCASP2AMUTE: R393.2 R822.2 U1.C2(PR0_PRU0_GPO9/PR0_PRU0_GPI9/XREFCLK/GPIO0_117/MCASP2_AMUTE)
SOC_MCASP2AMUTE_R: JP1.21 R822.1
SOC_MCASP2AXR0: R428.2 R821.2 U1.D3(PR0_PRU0_GPO0/PR0_PRU0_GPI0/GPIO0_108/MCASP2_AXR0)
SOC_MCASP2AXR0_R: JP1.22 R821.1
SOC_MCASP2AXR1: R423.1 ; also on sheet 24
SOC_MCASP2AXR2: R433.1 ; also on sheet 24
SOC_MCASP2AXR3: R415.1 ; also on sheet 24
SOC_MCASP2AXR4: R396.1 ; also on sheet 24
SOC_MCASP2AXR5: JP1.24 R420.1
SOC_MCASP2FSR: JP1.18 R409.1
SOC_McASP2FSX: R411.1 ; also on sheet 24
SOC_MCBSPCLKR: J12.29 U1.D17(PR1_PRU1_GPO14/PR1_PRU1_GPI14/MCBSP_CLKR/GPIO1_40)
SOC_MCBSPCLKX: J12.25 U1.B16(PR1_PRU1_GPO12/PR1_PRU1_GPI12/MCBSP_CLKX/GPIO1_38)
SOC_MCBSPDR: J12.19 U1.D15(PR1_PRU1_GPO9/PR1_PRU1_GPI9/MCBSP_DR/GPIO1_35)
SOC_MCBSPDX: J12.21 U1.A16(PR1_PRU1_GPO10/PR1_PRU1_GPI10/MCBSP_DX/GPIO1_36)
SOC_MCBSPFSR: J12.27 U1.C16(PR1_PRU1_GPO13/PR1_PRU1_GPI13/MCBSP_FSR/GPIO1_39)
SOC_MCBSPFSX: J12.23 U1.E15(PR1_PRU1_GPO11/PR1_PRU1_GPI11/MCBSP_FSX/GPIO1_37)
SOC_RESETSTATz: JP1.11 ; also on sheet 11 17 18 21 22 23 25 26 31 45 46
SOC_SPI0_CLK: J12.13 R373.1
SOC_SPI0_MISO: J12.9 U1.M1(SPI0_SOMI)
SOC_SPI0_MOSI: J12.11 U1.N4(SPI0_SIMO)
SOC_SPI0_SCS0: J12.15 U1.M3(SPI0_SCSn0)
SOC_SPI0_SCS1: J12.10 U1.M4(SPI0_SCSn1/GPIO0_99)
SOC_SPI2_CLK: JP1.9 R716.1
SOC_SPI2_MISO: JP1.16 U1.R4(SPI2_SOMI/GPIO0_104)
SOC_SPI2_MOSI: JP1.15 U1.R3(SPI2_SIMO/GPIO0_105)
SOC_SPI2_SCS0: JP1.17 U1.P3(SPI2_SCSn0/GPIO0_101)
SOC_TIMI1: J12.22 U1.W23(GPMC_CSn2/TIMI1/GPIO0_28)
SOC_TIMO1: J12.24 U1.Y25(GPMC_CSn3/TIMO1/GPIO0_29)
SOC_UART0_CTSn: J12.16 ; also on sheet 28
SOC_UART0_RTSn: J12.18 ; also on sheet 28
SOC_UART0_RXD: J12.14 ; also on sheet 28
SOC_UART0_TXD: J12.12 ; also on sheet 28
TEMP_INT: U112.3(ALERT) ; also on sheet 12
WLAN_EN: U51.6(P05) ; also on sheet 30
WLAN_TRANS_EN: R393.1 ; also on sheet 24 30
N18067178: R558.1 U95.6(SDAB)
N18067322: R563.1 R564.2 U95.5(EN)
N19367736: R482.2 U1.B9(PR0_PRU1_GPO17/PR0_PRU1_GPI17/PR1_UART0_TXD/GPIO1_01/MCASP0_AXR0)
N19367738: R454.2 U1.A9(PR0_PRU1_GPO18/PR0_PRU1_GPI18/PR0_EDC_LATCH1_IN/GPIO1_02/MCASP0_AXR1)
N19367748: R451.2 U1.B10(PR0_PRU1_GPO19/PR0_PRU1_GPI19/PR0_EDC_SYNC1_OUT/GPIO1_03/MCASP0_AXR2)
N19367766: R447.2 U1.A10(PR0_MDIO_DATA/GPIO1_04/MCASP0_AXR3)
N19367768: R480.2 U1.C10(PR0_MDIO_MDCLK/GPIO1_05/MCASP0_AXR4)
N19367778: R476.2 U1.E10(PR1_PRU0_GPO0/PR1_PRU0_GPI0/GPIO1_06/MCASP0_AXR5)
N19367788: R472.2 U1.D10(PR1_PRU0_GPO1/PR1_PRU0_GPI1/GPIO1_07/MCASP0_AXR6)
N19367798: R469.2 U1.F10(PR1_PRU0_GPO2/PR1_PRU0_GPI2/GPIO1_08/MCASP0_AXR7)
N19367816: R441.2 U1.C11(PR1_PRU0_GPO3/PR1_PRU0_GPI3/GPIO1_09/MCASP0_AXR8)
N19367818: R437.2 U1.D11(PR1_PRU0_GPO4/PR1_PRU0_GPI4/MMC0_POW/GPIO1_10/MCASP0_AXR9)
N19367846: R459.2 U1.E12(PR1_PRU0_GPO7/PR1_PRU0_GPI7/MMC0_DAT7/GPIO1_13/MCASP0_AXR12)
N19367848: R481.2 U1.C12(PR1_PRU0_GPO8/PR1_PRU0_GPI8/MMC0_DAT6/GPIO1_14/MCASP0_AXR13)
N19367866: R460.2 U1.B11(PR1_PRU0_GPO9/PR1_PRU0_GPI9/MMC0_DAT5/GPIO1_15/MCASP0_AXR14)
N19367868: R477.2 U1.B12(PR1_PRU0_GPO10/PR1_PRU0_GPI10/MMC0_DAT4/GPIO1_16/MCASP0_AXR15)
N19367970: R444.2 U1.C7(PR0_PRU1_GPO10/PR0_PRU1_GPI10/GPIO0_138/MCASP0_AMUTE)
N19368123: R468.2 U1.A8(PR0_PRU1_GPO12/PR0_PRU1_GPI12/GPIO0_140/MCASP0_AFSR)
N19368147: R448.2 U1.C8(PR0_PRU1_GPO15/PR0_PRU1_GPI15/GPIO0_143/MCASP0_AFSX)
N19368179: R470.2 U1.E9(PR0_PRU1_GPO11/PR0_PRU1_GPI11/GPIO0_139/MCASP0_ACLKR)
N19368226: R473.2 U1.B8(PR0_PRU1_GPO13/PR0_PRU1_GPI13/GPIO0_141/MCASP0_AHCLKR)
N19368266: R458.2 U1.C9(PR0_PRU1_GPO16/PR0_PRU1_GPI16/GPIO1_00/MCASP0_AHCLKX)
N19368284: R452.2 U1.D9(PR0_PRU1_GPO14/PR0_PRU1_GPI14/GPIO0_142/MCASP0_ACLKX)
N19368587: R439.2 U1.B5(PR0_PRU1_GPO0/PR0_PRU1_GPI0/GPIO0_128/MCASP1_AXR0)
N19368605: R434.2 U1.B6(PR0_PRU1_GPO1/PR0_PRU1_GPI1/GPIO0_129/MCASP1_AXR1)
N19368607: R430.2 U1.D7(PR0_PRU1_GPO2/PR0_PRU1_GPI2/GPIO0_130/MCASP1_AXR2)
N19368625: R425.2 U1.A6(PR0_PRU1_GPO3/PR0_PRU1_GPI3/GPIO0_131/MCASP1_AXR3)
N19368627: R422.2 U1.C6(PR0_PRU1_GPO4/PR0_PRU1_GPI4/GPIO0_132/MCASP1_AXR4)
N19368645: R419.2 U1.E8(PR0_PRU1_GPO5/PR0_PRU1_GPI5/GPIO0_133/MCASP1_AXR5)
N19368655: R416.2 U1.A7(PR0_PRU1_GPO6/PR0_PRU1_GPI6/GPIO0_134/MCASP1_AXR6)
N19368657: R414.2 U1.D8(PR0_PRU1_GPO7/PR0_PRU1_GPI7/GPIO0_135/MCASP1_AXR7)
N19368675: R412.2 U1.F9(PR0_PRU1_GPO8/PR0_PRU1_GPI8/GPIO0_136/MCASP1_AXR8)
N19368677: R410.2 U1.B7(PR0_PRU1_GPO9/PR0_PRU1_GPI9/GPIO0_137/MCASP1_AXR9)
N19368786: R405.2 U1.D6(PR0_PRU0_GPO16/PR0_PRU0_GPI16/GPIO0_124/MCASP1_ACLKX)
N19368850: R398.2 U1.B4(PR0_PRU0_GPO13/PR0_PRU0_GPI13/GPIO0_121/MCASP1_ACLKR)
N19368882: R402.2 U1.E7(PR0_PRU0_GPO15/PR0_PRU0_GPI15/GPIO0_123/MCASP1_AHCLKR)
N19368922: R408.2 U1.C5(PR0_PRU0_GPO18/PR0_PRU0_GPI18/PR0_EDC_LATCH0_IN/GPIO0_126/MCASP1_AHCLKX)
N19368946: R394.2 U1.A4(PR0_PRU0_GPO14/PR0_PRU0_GPI14/GPIO0_122/MCASP1_AFSR)
N19368978: R404.2 U1.C4(PR0_PRU0_GPO17/PR0_PRU0_GPI17/PR1_UART0_RXD/GPIO0_125/MCASP1_AFSX)
N19369157: R423.2 U1.A2(PR0_PRU0_GPO1/PR0_PRU0_GPI1/GPIO0_109/MCASP2_AXR1)
N19369167: R433.2 U1.E4(PR0_PRU0_GPO2/PR0_PRU0_GPI2/GPIO0_110/MCASP2_AXR2)
N19369177: R415.2 U1.B1(PR0_PRU0_GPO3/PR0_PRU0_GPI3/GPIO0_111/MCASP2_AXR3)
N19369187: R396.2 U1.A3(PR0_PRU0_GPO4/PR0_PRU0_GPI4/GPIO0_112/MCASP2_AXR4)
N19369197: R420.2 U1.E5(PR0_PRU0_GPO5/PR0_PRU0_GPI5/GPIO0_113/MCASP2_AXR5)
N19369349: R401.2 U1.B2(PR0_PRU0_GPO6/PR0_PRU0_GPI6/GPIO0_114/MCASP2_ACLKR)
N19369390: R413.2 U1.B3(PR0_PRU0_GPO12/PR0_PRU0_GPI12/GPIO0_120/MCASP2_ACLKX)
N19369435: R407.2 U1.E6(PR0_PRU0_GPO8/PR0_PRU0_GPI8/GPIO0_116/MCASP2_AHCLKR)
N19369467: R417.2 U1.D5(PR0_PRU0_GPO11/PR0_PRU0_GPI11/GPIO0_119/MCASP2_AHCLKX)
N19369503: R409.2 U1.D4(PR0_PRU0_GPO7/PR0_PRU0_GPI7/GPIO0_115/MCASP2_AFSR)
N19369544: R411.2 U1.C3(PR0_PRU0_GPO10/PR0_PRU0_GPI10/GPIO0_118/MCASP2_AFSX)
N19935028: R365.2 U1.W5(I2C0_SDA)
N19935032: R366.2 U1.U5(I2C0_SCL)
N19935171: R711.2 U1.W4(I2C1_SDA)
N19935173: R710.2 U1.V6(I2C1_SCL)
N19935221: R373.2 U1.M2(SPI0_CLK)
N19935328: R716.2 U1.R2(SPI2_CLK/GPIO0_103)
N19936677: R553.1 U95.7(SCLB)
N21103341: R708.2 U1.V4(I2C2_SDA)
N21103343: R707.2 U1.V5(I2C2_SCL)
N21505605: R1.2 R494.1 U51.24(A2)
N21505608: R2.1 R497.2 U51.23(A1)
N21505611: R3.2 R4.1 U51.18(A0)
N21505922: LD1.2 R12.2
N21506103: LD3.2 R13.2
N21506291: LD5.2 R14.2
N21506486: LD4.2 R15.2
N21507867: LD2.2 R16.2
N21508122: TP191.1(TP) U51.1(P00)
N21508129: TP192.1(TP) U51.2(P01)
N21508178: TP9.1(TP) U51.8(P07)
N21508185: TP186.1(TP) U51.10(P10)
N21508192: TP187.1(TP) U51.11(P11)
N21508199: TP188.1(TP) U51.12(P12)
N21508206: TP189.1(TP) U51.13(P13)
N21508213: TP184.1(TP) U51.14(P14)
N21508220: TP185.1(TP) U51.15(P15)
N21690505: R784.1 R785.2 U112.4(ADD0)
N22816314: Q15.1(G) R819.1
N22816317: LD3.1 Q15.3(D)
N22816577: LD1.1 Q14.3(D)
N22816587: Q14.1(G) R818.1
N25806665: J45.1 R886.1
N25806674: J45.3 R887.1

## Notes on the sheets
sheet 33
- SOC MCASP
- AUDIO EXP CONNECTOR
- GPIOs ON
  AUDIO CARD
- SOC SIGNAL
- SOC_MCASP0AXR8/GPIO1_09
- DIR_RST#
- SOC_MCASP0AXR9/GPIO1_10
- PCM1690_RST#
- SOC_McASP0_AMUTE
- DAC0_AMUTEI#,
  DAC1_AMUTEI#
- SOC_MCASP1AXR4/GPIO0_132
- McASP_CLK_SEL
- SOC_MCASP1AXR6/GPIO0_134
- DIR_AUDIO#
- SOC_MCASP1AXR7/GPIO0_135
- DIR_EMPH
- SOC_MCASP1AXR8/GPIO0_136
- DIR_ERROR
- SOC_MCASP1AXR5/GPIO0_133
- DIR_CLKST
- SOC_MCASP1ACLKX/GPIO0_124
- DIR_FSOUT0
- SOC_MCASP1FSX / GPIO0_125
- DIR_FSOUT1
- SOC_SPI2_MOSI / GPIO0_105
- I2SHDR_GPIO0
- SOC_SPI2_MISO / GPIO0_104
- I2SHDR_GPIO1
- McASP0AHCLKX_BUFFER
- I2C BUFFER
sheet 34
- SoC McBSP
- SERIAL EXPANSION CONNECTOR
- SoC PWM
sheet 35
- I2C0
- SoC I2C
- TEMPERATURE SENSOR
- TO BMC, SERIAL EXPANSION HEADER
- I2C2
- I2C1
- TO PMIC
- NOTE: PLACE TEMP SENSOR CLOSE TO SoC
- I2C ADDRESS: 0x48
- TO HDMI TX, TOUCH SCREEN, AIC3106 ,
  AUDIO & MLB EXP HEADER
- SoC SPI
- LED YELLOW
- GPIO EXPANDER & LEDs
- SPI0
- LED YELLOW
- TO SERIAL EXP HEADER
- LED YELLOW
- SPI2
- LED YELLOW
- DIR9001_ERROR & DIR9001_CLKST NEED TO BE
  CONNECTED TO SOC GPIOS, SINCE SOC GPIOs ARE
  NOT FREE IT IS CONNECTED IN GPIO EXPANDER
- I2C ADDRESS: 0x20
- TO AUDIO EXP HEADER
- LED YELLOW
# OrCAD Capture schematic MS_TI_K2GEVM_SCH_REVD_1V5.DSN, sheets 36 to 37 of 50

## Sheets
36 35. CLOCK DISTRIBUTION1: size C; title: CLOCK DISTRIBUTION 1
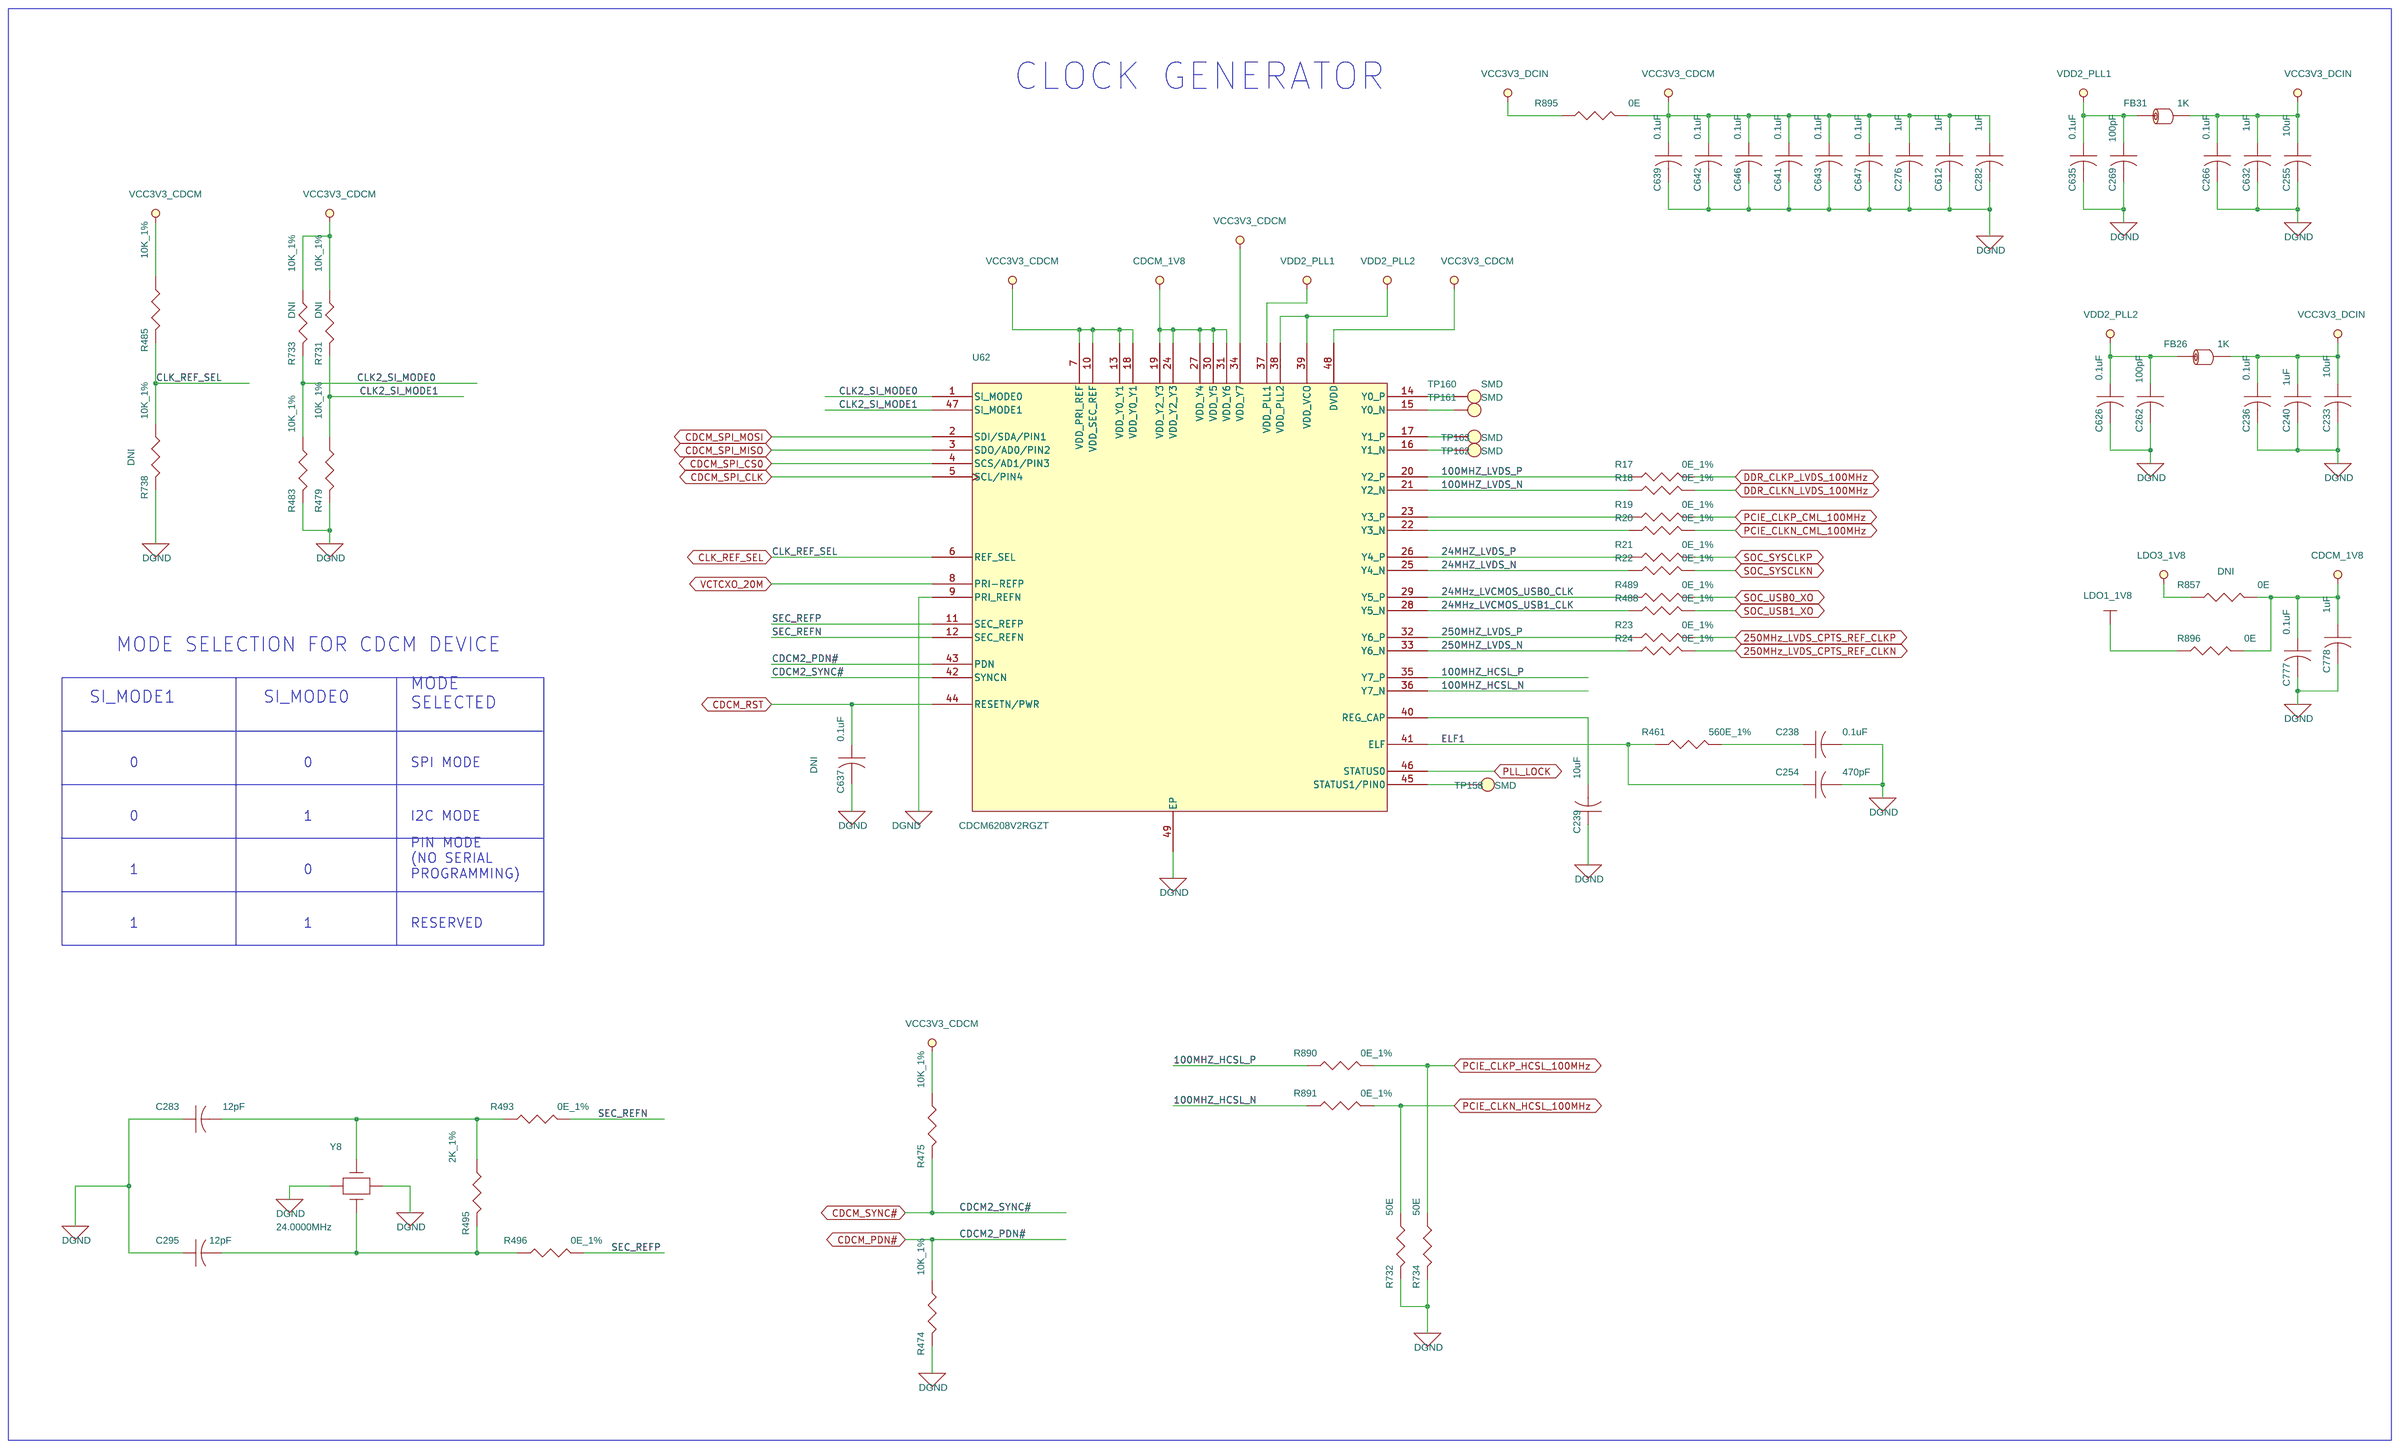
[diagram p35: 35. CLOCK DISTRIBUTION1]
37 36. CLOCK DISTRIBUTION 2: size C; title: CLOCK DISTRIBUTION 2

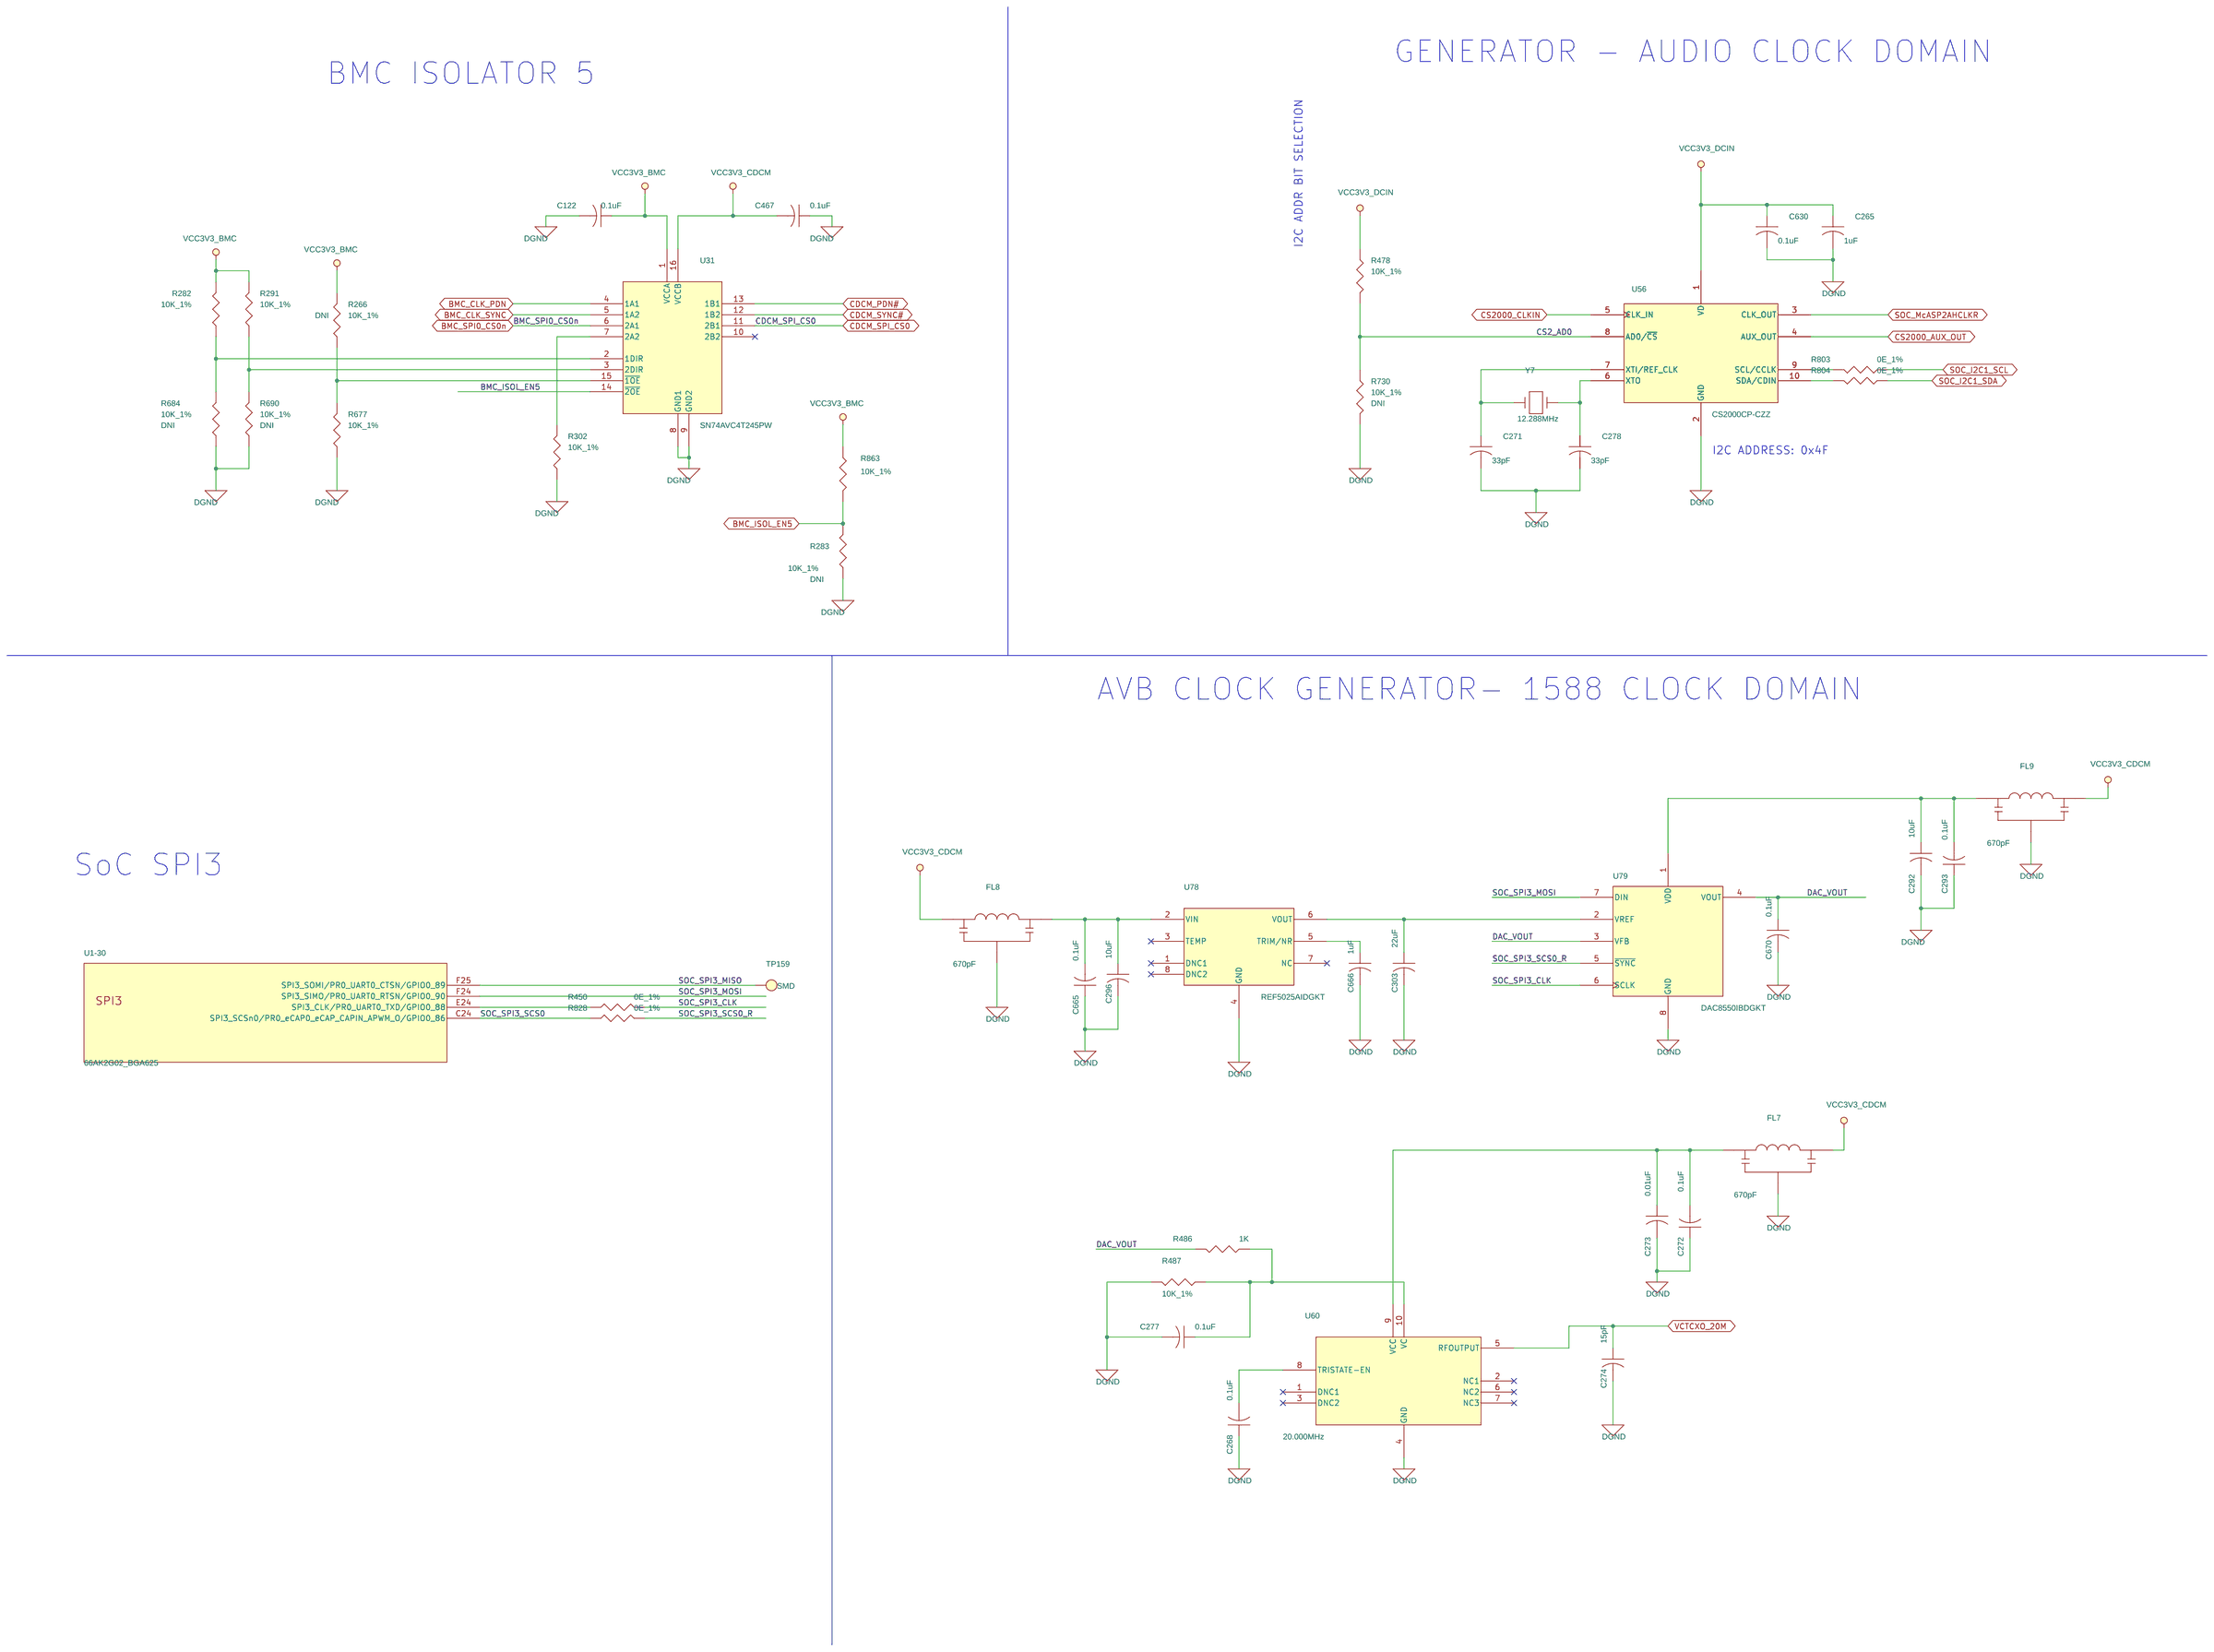
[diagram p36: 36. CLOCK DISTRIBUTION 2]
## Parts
sheet 18. NAND FLASH & MICRO SD CARD
U1  66AK2G02_BGA625  [BGASKT625_31-49_1270x1270]  (sections -1,-10,-11,-12,-13,-14,-15,-16,-17,-18,-19,-2,-20,-21,-22,-23,-24,-25,-26,-27,-28,-29,-3,-30,-31,-32,-33,-34,-35,-36,-37,-38,-4,-5,-6,-7,-8,-9)
sheet 35. CLOCK DISTRIBUTION1
C233  10uF  [CAP0805]
C236  0.1uF  [CAP0402]
C238  0.1uF  [CAP0402]
C239  10uF  [CAP0805]
C240  1uF  [CAP0402]
C254  470pF  [CAP0402]
C255  10uF  [CAP0805]
C262  100pF  [CAP0603]
C266  0.1uF  [CAP0402]
C269  100pF  [CAP0603]
C276  1uF  [CAP0402]
C282  1uF  [CAP0402]
C283  12pF  [CAP0402]
C295  12pF  [CAP0402]
C612  1uF  [CAP0402]
C626  0.1uF  [CAP0402]
C632  1uF  [CAP0402]
C635  0.1uF  [CAP0402]
C637  0.1uF  [CAP0402]
C639  0.1uF  [CAP0402]
C641  0.1uF  [CAP0402]
C642  0.1uF  [CAP0402]
C643  0.1uF  [CAP0402]
C646  0.1uF  [CAP0402]
C647  0.1uF  [CAP0402]
C777  0.1uF  [CAP0402]
C778  1uF  [CAP0402]
FB26  1K  [EMIFIL_BLM15H_0402]
FB31  1K  [EMIFIL_BLM15H_0402]
R17  0E_1%  [RES0402]
R18  0E_1%  [RES0402]
R19  0E_1%  [RES0402]
R20  0E_1%  [RES0402]
R21  0E_1%  [RES0402]
R22  0E_1%  [RES0402]
R23  0E_1%  [RES0402]
R24  0E_1%  [RES0402]
R461  560E_1%  [RES0402]
R474  10K_1%  [RES0402]
R475  10K_1%  [RES0402]
R479  10K_1%  [RES0402]
R483  10K_1%  [RES0402]
R485  10K_1%  [RES0402]
R488  0E_1%  [RES0402]
R489  0E_1%  [RES0402]
R493  0E_1%  [RES0402]
R495  2K_1%  [RES0402]
R496  0E_1%  [RES0402]
R731  10K_1%  [RES0402]
R732  50E  [RES0402]
R733  10K_1%  [RES0402]
R734  50E  [RES0402]
R738  10K_1%  [RES0402]
R857  0E  [RES0402]
R890  0E_1%  [RES0402]
R891  0E_1%  [RES0402]
R895  0E  [RES0402]
R896  0E  [RES0402]
TP158  SMD  [TP20_SMD]
TP160  SMD  [TP20_SMD]
TP161  SMD  [TP20_SMD]
TP162  SMD  [TP20_SMD]
TP163  SMD  [TP20_SMD]
U62  CDCM6208V2RGZT  [VQFN48_19-68_285X285]
Y8  24.0000MHz  [XTAL4_86-61X62-99_130X105_SMD]
sheet 36. CLOCK DISTRIBUTION 2
C122  0.1uF  [CAP0402]
C265  1uF  [CAP0402]
C268  0.1uF  [CAP0402]
C271  33pF  [CAP0402]
C272  0.1uF  [CAP0402]
C273  0.01uF  [CAP0402]
C274  15pF  [CAP0402]
C277  0.1uF  [CAP0402]
C278  33pF  [CAP0402]
C292  10uF  [CAP0805]
C293  0.1uF  [CAP0402]
C296  10uF  [CAP0805]
C303  22uF  [CAP0805]
C467  0.1uF  [CAP0402]
C630  0.1uF  [CAP0402]
C665  0.1uF  [CAP0402]
C666  1uF  [CAP0402]
C670  0.1uF  [CAP0402]
FL7  670pF  [EMIFIL_NFL21SP_0805]
FL8  670pF  [EMIFIL_NFL21SP_0805]
FL9  670pF  [EMIFIL_NFL21SP_0805]
R266  10K_1%  [RES0402]
R282  10K_1%  [RES0402]
R283  10K_1%  [RES0402]
R291  10K_1%  [RES0402]
R302  10K_1%  [RES0402]
R450  0E_1%  [RES0402]
R478  10K_1%  [RES0402]
R486  1K  [RES0402]
R487  10K_1%  [RES0402]
R677  10K_1%  [RES0402]
R684  10K_1%  [RES0402]
R690  10K_1%  [RES0402]
R730  10K_1%  [RES0402]
R803  0E_1%  [RES0402]
R804  0E_1%  [RES0402]
R828  0E_1%  [RES0402]
R863  10K_1%  [RES0402]
TP159  SMD  [TP40_SMD]
U31  SN74AVC4T245PW  [TSSOP16_25-59_205X180]
U56  CS2000CP-CZZ  [MSOP10_19-68_120X120]
U60  20.000MHz  [OSC10_E6718LF_280X200_SMD]
U78  REF5025AIDGKT  [MSOP8_25-59_125X125]
U79  DAC8550IBDGKT  [VSSOP8_25-59_120X120]
Y7  12.288MHz  [XTAL2_ATS-SM_460X190_SMD]

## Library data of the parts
U1 = 66AK2G02_BGA625: IC ARM CORTEX AND DSP 32 BIT MICROPROCESSOR BGA625; Chkd/date: NAVEED/141114; Color: Default; Crtd /date: VASANTHA/081014; Custom_Duty: 15%; Customs_HS_Code: 85423100; Distributor_name: NA; Distributor_part_number: NA; Height: 1.70MM; Location X-Coordinate: 0; Location Y-Coordinate: 0; Mfr_name: TEXAS INSTRUMENTS; Mfr_part_number: 66AK2G02; Mistral Part No: 141014100003; Package: BGA625; Part_type: ICS\DIGITAL\MICROPROCESSOR; Power Pins Visible: False; Primitive: DEFAULT; Project: GALILEO_EVM; Tolerance: NA; Voltage: NA; Wattage: NA; Weight: NA; Datasheet: Y:\MIS_DATABASE\DATASHEETS\ICS\DIGITAL\MICROCONTROLLER\SG-BGA-6094.PDF    Y:\MIS_DATABASE\DATASHEETS\ICS\DIGITAL\MICROCONTROLLER\SG-BGA_FP.PDF
C233 C239 C255 C292 C296 = CAP: CAP CERAMIC 10uF 16V 10% X5R 0805; Alternate_mfr_name_A: TAIYO YUDEN; Alternate_mfr_part_number_A: EMK212BJ106KG-T; Chkd/date: RAVI/020511; Crtd /date: BAVISH/290411; Custom_Duty: 15%; Customs_HS_Code: 85322990; Distributor_name: DIGIKEY; Distributor_name_A: DIGIKEY; Distributor_part_number: 478-5165-1-ND; Distributor_part_number_A: 587-1295-1-ND; Height: 1.40MM; Mfr_name: AVX CORPORATION; Mfr_part_number: 0805YD106KAT2A; Mistral Part No: 120011040011-R; Package: 0805; Part_type: CAPACITORS\CERAMIC; Project: AOD_POD-RF; RoHS: RoHS; Temperature: -55°C+85°C; Tolerance: 10%; Voltage: 16V; Wattage: NA; Weight: NA; Datasheet: Y:\MIS_DATABASE\DATASHEETS\CAPACITORS\AVX_CERAMIC.PDF
C122 C236 C238 C266 C268 C272 C277 C293 C467 C626 C630 C635 C639 C641-C643 C646 C647 C665 C670 C777 = CAP: CAP CERAMIC 0.1uF 16V 10% X7R 0402; Alternate_mfr_name_A: KEMET; Alternate_mfr_part_number_A: C0402C104K4RACT; Chkd/date: MAZHAR/281108; Crtd /date: MAZHAR/030907; Custom_Duty: 15%; Customs_HS_Code: 85322990; Distributor_name: DIGIKEY; Distributor_name_A: DIGIKEY; Distributor_part_number: 490-3261-1-ND; Distributor_part_number_A: 399-3521-1-ND; Height: 0.55MM; Mfr_name: MURATA; Mfr_part_number: GRM155R71C104KA88D; Mistral Part No: 120009030060-R; Package: 0402; Part_type: CAPACITORS\CERAMIC; Project: SMART VIEW_IP CAMERA; Tolerance: 10%; Voltage: 16V; Datasheet: Y:\MIS_DATABASE\DATASHEETS\CAPACITORS\GRM188SERIES.PDF
C240 C265 C276 C282 C612 C632 C666 C778 = CAP: CAP CERAMIC 1uF 10V 10% X5R 0402; Chkd/date: BALACHANDAR/160514; Crtd /date: SARANYA/060514; Custom_Duty: 15%; Customs_HS_Code: 85322990; Distributor_name: DIGIKEY; Distributor_part_number: 478-4596-1-ND; Height: 0.56MM; Mfr_name: AVX CORPORATION; Mfr_part_number: 0402ZD105KAT2A; Mistral Part No: 120014050010-R; Package: 0402; Part_type: CAPACITORS\CERAMIC; Project: AEGIS GP BETA2; RoHS: RoHS; Temperature: -55°C+85°C; Tolerance: 10%; Voltage: 10V; Wattage: NA; Weight: NA; Datasheet: Y:\MIS_DATABASE\DATASHEETS\CAPACITORS\AVX_MLC.PDF
C254 = CAP: CAP CERAMIC 470pF 50V 10% X7R 0402; Alternate_mfr_name_C: PANASONIC-ECG; Alternate_mfr_part_number_C: ECJ-0EB1H471K; Chkd/date: SHREESHAIL/280507; Crtd /date: MAZHAR/250706; Custom_Duty: 15%; Customs_HS_Code: 85322990; Distributor_name: DIGIKEY; Distributor_name_C: DIGIKEY; Distributor_part_number: 478-1097-1-ND; Distributor_part_number_C: PCC1717CT-ND; Height: 0.60MM; Mfr_name: AVX CORPORATION; Mfr_part_number: 04025C471KAT2A; Mistral Part No: 120009030451-R; Package: 0402; Part_type: CAPACITORS\CERAMIC; Project: POWERBOX; RoHS: RoHS; Tolerance: 10%; Voltage: 50V; Datasheet: Y:\MIS_DATABASE\DATASHEETS\CAPACITORS\AVX_MLC.PDF
C262 C269 = CAP: CAP CERAMIC 100pF 16V 10% X7R 0603; Chkd/date: SHREESHAIL/281105; Crtd /date: MAZHAR/040505; Custom_Duty: 15%; Customs_HS_Code: 85322990; Distributor_name: MOUSER; Distributor_part_number: 581-0603YC101KAT2A; Height: 0.90MM; Mfr_name: AVX CORPORATION; Mfr_part_number: 0603YC101KAT2A; Mistral Part No: 120009030166-R; Package: 0603; Part_type: CAPACITORS\CERAMIC; Project: RSC_REV1.0; RoHS: RoHS; Tolerance: 10%; Voltage: 16V; Datasheet: Y:\MIS_DATABASE\DATASHEETS\CAPACITORS\AVX_MLC.PDF
C283 C295 = CAP: CAP CERAMIC 12pF 50V 5% NP0 0402; Alternate_mfr_name_A: MURATA; Alternate_mfr_part_number_A: GJM1555C1H120JB01D; Chkd/date: SHREESHAIL/281105; Crtd /date: MAZHAR/040505; Custom_Duty: 15%; Customs_HS_Code: 85322990; Distributor_name: DIGIKEY; Distributor_name_A: DIGIKEY; Distributor_part_number: 478-1071-1-ND; Distributor_part_number_A: 490-3115-1-ND; Height: 0.60MM; Mfr_name: AVX CORPORATION; Mfr_part_number: 04025A120JAT2A; Mistral Part No: 120009030215-R; Package: 0402; Part_type: CAPACITORS\CERAMIC; Project: EPDA_CORE; RoHS: RoHS; Tolerance: 5%; Voltage: 50V; Datasheet: Y:\MIS_DATABASE\DATASHEETS\CAPACITORS\AVX_MLC.PDF
C637 = CAP: CAP CERAMIC 0.1uF 16V 10% X7R 0402; Alternate_mfr_name_A: KEMET; Alternate_mfr_part_number_A: C0402C104K4RACT; Chkd/date: MAZHAR/281108; Crtd /date: MAZHAR/030907; Custom_Duty: 15%; Customs_HS_Code: 85322990; Distributor_name: DIGIKEY; Distributor_name_A: DIGIKEY; Distributor_part_number: 490-3261-1-ND; Distributor_part_number_A: 399-3521-1-ND; Height: 0.55MM; Loading: DNI; Mfr_name: MURATA; Mfr_part_number: GRM155R71C104KA88D; Mistral Part No: 120009030060-R; Package: 0402; Part_type: CAPACITORS\CERAMIC; Project: SMART VIEW_IP CAMERA; Tolerance: 10%; Voltage: 16V; Datasheet: Y:\MIS_DATABASE\DATASHEETS\CAPACITORS\GRM188SERIES.PDF
FB26 FB31 = INDUCTOR_FERRITE: PASSIVE FILTER CHIP 1K 250mA 0402; Chkd/date: NAVEED/241114; Crtd /date: VASANTHA/281014; Custom_Duty: 24%; Customs_HS_Code: 85437099; Distributor_name: DIGIKEY; Distributor_part_number: 490-4003-1-ND; Height: 0.55MM; Mfr_name: MURATA; Mfr_part_number: BLM15HD102SN1D; Mistral Part No: 130014100051-R; Package: 0402; Part_type: MISC\FILTER; Project: GALILEO_EVM; RoHS: RoHS; Temperature: -55°C+125°C; Tolerance: NA; Voltage: NA; Wattage: NA; Weight: NA; Datasheet: Y:\MIS_DATABASE\DATASHEETS\DISCRETES\INDUCTORS\BLM15H.PDF
R17-R24 R450 R488 R489 R493 R496 R803 R804 R828 R890 R891 = RESISTOR: RES 0E 1/16W 1% 0402; Chkd/date: MAZHAR/220709; Crtd /date: USMAN/270109; Custom_Duty: 15%; Customs_HS_Code: 85332119; Distributor_name: NA; Distributor_part_number: NA; Height: 0.40MM; Mfr_name: YAGEO AMERICA; Mfr_part_number: RC0402FR-070RL; Mistral Part No: 110009030085-P; Package: 0402; Part_type: RESISTORS\FIXED; Project: OMAP_EVM; RoHS: Pb-Free; Tolerance: 1%; Wattage: 1/16W; Datasheet: Y:\MIS_DATABASE\DATASHEETS\RESISTORS\CRCW0603.PDF
R461 = RESISTOR: RES 560E 1/16W 1% 0402; Alternate_mfr_name_A: AVX CORPORATION; Alternate_mfr_part_number_A: CR05-561F-H; Chkd/date: SHREESHAIL/24050; Crtd /date: MAZHAR/140906; Custom_Duty: 15%; Customs_HS_Code: 85332119; Distributor_name: DIGIKEY; Distributor_name_A: NA; Distributor_part_number: 311-560LRCT-ND; Distributor_part_number_A: NA; Height: 0.40MM; Mfr_name: YAGEO AMERICA; Mfr_part_number: RC0402FR-07560RL; Mistral Part No: 110009030986-P; Package: 0402; Part_type: RESISTORS\FIXED; Project: SVDO_RMB_MMA; RoHS: Pb-Free; Tolerance: 1%; Wattage: 1/16W; Datasheet: Y:\MIS_DATABASE\DATASHEETS\RESISTORS\YAGEO-RC0402.PDF
R282 R291 R302 R474 R475 R478 R479 R483 R485 R487 R677 R863 = RESISTOR: RES 10K 1/16W 1% 0402; Alternate_mfr_name_A: AVX CORPORATION; Alternate_mfr_name_B: PANASONIC-ECG-ECG; Alternate_mfr_name_C: YAGEO AMERICA; Alternate_mfr_name_D: VISHAY; Alternate_mfr_part_number_A: CR05-103F-H; Alternate_mfr_part_number_B: ERJ-2RKF1002X; Alternate_mfr_part_number_C: 9C04021A1002FLHF3; Alternate_mfr_part_number_D: CRCW040210K0FKED; Chkd/date: SHREESHAIL/310506; Crtd /date: GEETHA/290506; Custom_Duty: 15%; Customs_HS_Code: 85332119; Distributor_name: DIGIKEY; Distributor_name_A: NA; Distributor_name_B: DIGIKEY; Distributor_name_C: DIGIKEY; Distributor_name_D: DIGIKEY; Distributor_part_number: 311-10.0KLRTR-ND; Distributor_part_number_A: NA; Distributor_part_number_B: P10.0KLCT-ND; Distributor_part_number_C: 311-10.0KLCT-ND; Distributor_part_number_D: 541-10.0KLCT-ND; Height: 0.40MM; Mfr_name: YAGEO AMERICA; Mfr_part_number: RC0402FR-0710KL; Mistral Part No: 110009030220-P; Package: 0402; Part_type: RESISTORS\FIXED; Project: VOCERA; RoHS: Pb-Free; Tolerance: 1%; Wattage: 1/16W; Datasheet: Y:\MIS_DATABASE\DATASHEETS\RESISTORS\YAGEO-RC0402.PDF
R495 = RESISTOR: RES 2K 1/16W 1% 0402; Alternate_mfr_name_A: YAGEO AMERICA; Alternate_mfr_name_B: PANASONIC-ECG; Alternate_mfr_name_D: VENKEL; Alternate_mfr_part_number_A: RC0402FR-072KL; Alternate_mfr_part_number_B: ERJ-S02F2001X; Alternate_mfr_part_number_D: CR0402-16W-2001FT; Chkd/date: SHREESHAIL/210506; Crtd /date: MAZHAR/150506; Custom_Duty: 15%; Customs_HS_Code: 85332119; Distributor_name: DIGIKEY; Distributor_name_A: DIGIKEY; Distributor_name_B: DIGIKEY; Distributor_name_D: NA; Distributor_part_number: P2.00KLCT-ND; Distributor_part_number_A: 311-2KLRCT-ND; Distributor_part_number_B: ERJ-S02F2001X-ND; Distributor_part_number_D: NA; Height: 0.40MM; Mfr_name: PANASONIC-ECG; Mfr_part_number: ERJ-2RKF2001X; Mistral Part No: 110009030606-R; Package: 0402; Part_type: RESISTORS\FIXED; Project: VOCERA; RoHS: RoHS; Tolerance: 1%; Wattage: 1/16W; Datasheet: Y:\MIS_DATABASE\DATASHEETS\RESISTORS\ERJ-2R.PDF
R266 R283 R684 R690 R730 R731 R733 R738 = RESISTOR: RES 10K 1/16W 1% 0402; Alternate_mfr_name_A: AVX CORPORATION; Alternate_mfr_name_B: PANASONIC-ECG-ECG; Alternate_mfr_name_C: YAGEO AMERICA; Alternate_mfr_name_D: VISHAY; Alternate_mfr_part_number_A: CR05-103F-H; Alternate_mfr_part_number_B: ERJ-2RKF1002X; Alternate_mfr_part_number_C: 9C04021A1002FLHF3; Alternate_mfr_part_number_D: CRCW040210K0FKED; Chkd/date: SHREESHAIL/310506; Crtd /date: GEETHA/290506; Custom_Duty: 15%; Customs_HS_Code: 85332119; Distributor_name: DIGIKEY; Distributor_name_A: NA; Distributor_name_B: DIGIKEY; Distributor_name_C: DIGIKEY; Distributor_name_D: DIGIKEY; Distributor_part_number: 311-10.0KLRTR-ND; Distributor_part_number_A: NA; Distributor_part_number_B: P10.0KLCT-ND; Distributor_part_number_C: 311-10.0KLCT-ND; Distributor_part_number_D: 541-10.0KLCT-ND; Height: 0.40MM; Loading: DNI; Mfr_name: YAGEO AMERICA; Mfr_part_number: RC0402FR-0710KL; Mistral Part No: 110009030220-P; Package: 0402; Part_type: RESISTORS\FIXED; Project: VOCERA; RoHS: Pb-Free; Tolerance: 1%; Wattage: 1/16W; Datasheet: Y:\MIS_DATABASE\DATASHEETS\RESISTORS\YAGEO-RC0402.PDF
R732 R734 = RESISTOR: RES 50E 1/16W 5% 0402; Chkd/date: USMAN/030114; Crtd /date: USMAN/151013; Custom_Duty: 15%; Customs_HS_Code: 85332119; Distributor_name: MOUSER; Distributor_part_number: 603-AC0402JR-0750RL; Height: 0.37MM; Mfr_name: YAGEO; Mfr_part_number: AC0402JR-0750RL; Mistral Part No: 110013100004-R; Package: 0402; Part_type: RESISTORS\FIXED; Project: C-BAND_SYNTH; RoHS: RoHS; Temperature: -55°C+155°C; Tolerance: 5%; Voltage: NA; Wattage: 1/16W; Weight: NA; Datasheet: Y:\MIS_DATABASE\DATASHEETS\RESISTORS\AC_SERIES.PDF
R857 = RESISTOR: RES 0E 1/10W 5% 0402; Chkd/date: NAVEED/241114; Crtd /date: NAVEED/201014; Custom_Duty: 15%; Customs_HS_Code: 85332119; Distributor_name: DIGIKEY; Distributor_part_number: P0.0JCT-ND; Height: 0.40MM; Loading: DNI; Mfr_name: PANASONIC-ECG; Mfr_part_number: ERJ-2GE0R00X; Mistral Part No: 110014100008-R; Package: 0402; Part_type: RESISTORS\FIXED; Project: AEGIS POM; RoHS: RoHS; Tolerance: 5%; Wattage: 1/10W; Datasheet: Y:\MIS_DATABASE\DATASHEETS\RESISTORS\ERJ12.PDF
R895 R896 = RESISTOR: RES 0E 1/10W 5% 0402; Chkd/date: NAVEED/241114; Crtd /date: NAVEED/201014; Custom_Duty: 15%; Customs_HS_Code: 85332119; Distributor_name: DIGIKEY; Distributor_part_number: P0.0JCT-ND; Height: 0.40MM; Mfr_name: PANASONIC-ECG; Mfr_part_number: ERJ-2GE0R00X; Mistral Part No: 110014100008-R; Package: 0402; Part_type: RESISTORS\FIXED; Project: AEGIS POM; RoHS: RoHS; Tolerance: 5%; Wattage: 1/10W; Datasheet: Y:\MIS_DATABASE\DATASHEETS\RESISTORS\ERJ12.PDF
TP158 TP160-TP163 = TESTPOINT: TESTPOINT 20 SMD; Chkd/date: SHREESHAIL/171006; Crtd /date: MAZHAR/171006; Distributor_name: NA; Distributor_part_number: NA; Height: NA; Mfr_name: LOCAL; Mistral Part No: NA4; Part_type: MISC\TESTPOINT; Project: BT MODULE_CSRBC04
U62 = CDCM6208V_VQFN48: IC CLOCK GENERATER VQFN48; Chkd/date: USMAN/090114; Crtd /date: SARANYA/080114; Custom_Duty: 15%; Customs_HS_Code: 85423100; Distributor_name: DIGIKEY; Distributor_part_number: 296-30502-1-ND; Height: 1.00MM; Mfr_name: TEXAS INSTRUMENTS; Mistral Part No: 141014010002-R; Package: VQFN48; Part_type: ICS\DIGITAL\PERIPHERAL; Project: AMC; RoHS: RoHS; Temperature: -40°C+85°C; Tolerance: NA; Voltage: NA; Wattage: NA; Weight: NA; Datasheet: Y:\MIS_DATABASE\DATASHEETS\ICS\DIGITAL\CODEC\CDCM6208V.PDF
Y8 = CRY4_13: CRY 24MHz SMD; Chkd/date: NAVEED/070115; Crtd /date: VASANTHA/151214; Custom_Duty: 24%; Customs_HS_Code: 85439000; Distributor_name: DIGIKEY; Distributor_part_number: 644-1052-1-ND; Height: 0.60MM; Mfr_name: NDK; Mfr_part_number: NX3225SA-24.000MHZ-STD-CSR-1; Mistral Part No: 130014120021-R; Package: SMD; Part_type: CRYSTAL; Project: GALILEO_EVM; RoHS: RoHS; Temperature: -10°C+75°C; Tolerance: NA; Voltage: NA; Wattage: NA; Weight: NA; Datasheet: Y:\MIS_DATABASE\DATASHEETS\MISC\CRY_OSC\NX3225SA-STD-CSR-1.PDF
C271 C278 = CAP: CAP CERAMIC 33pF 50V 5% NP0 0402; Chkd/date: NAVEED/241114; Crtd /date: VASANTHA/101114; Custom_Duty: 15%; Customs_HS_Code: 85322990; Distributor_name: DIGIKEY; Distributor_part_number: 311-1020-1-ND; Height: 0.55MM; Mfr_name: YAGEO AMERICA; Mfr_part_number: CC0402JRNPO9BN330; Mistral Part No: 120014110006-R; Package: 0402; Part_type: CAPACITORS\CERAMIC; Project: GALILEO_EVM; RoHS: RoHS; Temperature: -55°C+125°C; Tolerance: 5%; Voltage: 50V; Wattage: NA; Weight: NA; Datasheet: Y:\MIS_DATABASE\DATASHEETS\CAPACITORS\YACC0603.PDF
C273 = CAP: CAP CERAMIC 0.01uF 16V 10% X7R 0402; Alternate_mfr_name_A: AVX CORPORATION; Alternate_mfr_name_B: KEMET; Alternate_mfr_name_D: TDK CORPORATION; Alternate_mfr_part_number_A: 0402YC103KAT2A; Alternate_mfr_part_number_B: C0402C103K4RACTU; Alternate_mfr_part_number_D: C1005X7R1C103K; Chkd/date: SHREESHAIL/180506; Crtd /date: MAZHAR/110506; Custom_Duty: 15%; Customs_HS_Code: 85322990; Distributor_name: DIGIKEY; Distributor_name_A: DIGIKEY; Distributor_name_B: DIGIKEY; Distributor_name_D: DIGIKEY; Distributor_part_number: PCC103BQCT-ND; Distributor_part_number_A: 478-1114-1-ND; Distributor_part_number_B: 399-1038-1-ND; Distributor_part_number_D: 445-1262-1-ND; Height: 0.55MM; Mfr_name: PANASONIC-ECG; Mfr_part_number: ECJ-0EB1C103K; Mistral Part No: 120009030032-R; Package: 0402; Part_type: CAPACITORS\CERAMIC; Project: VOCERA; RoHS: RoHS; Tolerance: 10%; Voltage: 16V; Datasheet: Y:\MIS_DATABASE\DATASHEETS\CAPACITORS\PAN-ECJ.PDF
C274 = CAP: CAP CERAMIC 15pF 50V 5% NP0 0402; Alternate_mfr_name_A: AVX CORPORATION; Alternate_mfr_name_B: KEMET; Alternate_mfr_name_D: MURATA; Alternate_mfr_part_number_A: 04025A150JAT2A; Alternate_mfr_part_number_B: C0402C150J5GACTU; Alternate_mfr_part_number_D: GRM1555C1H150JZ01D; Chkd/date: SHREESHAIL/220506; Crtd /date: MAZHAR/150506; Custom_Duty: 15%; Customs_HS_Code: 85322990; Distributor_name: DIGIKEY; Distributor_name_A: DIGIKEY; Distributor_name_B: DIGIKEY; Distributor_name_D: DIGIKEY; Distributor_part_number: PCC150CQCT-ND; Distributor_part_number_A: 478-1072-1-ND; Distributor_part_number_B: 399-1014-1-ND; Distributor_part_number_D: 490-1280-1-ND; Height: 0.55MM; Mfr_name: PANASONIC-ECG; Mfr_part_number: ECJ-0EC1H150J; Mistral Part No: 120009030233-R; Package: 0402; Part_type: CAPACITORS\CERAMIC; Project: VOCERA; RoHS: RoHS; Tolerance: 5%; Voltage: 50V; Datasheet: Y:\MIS_DATABASE\DATASHEETS\CAPACITORS\ECJ.PDF
C303 = CAP: CAP CERAMIC 22uF 16V 10% X5R 0805; Chkd/date: MAZHAR/291110; Crtd /date: BAVISH/271110; Custom_Duty: 15%; Customs_HS_Code: 85322990; Distributor_name: NA; Distributor_part_number: NA; Height: 1.45MM; Mfr_name: TDK CORPORATION; Mfr_part_number: C2012X5R1C226K; Mistral Part No: 120010110025-R; Package: 0805; Part_type: CAPACITORS\CERAMIC; Project: EM-FLS; RoHS: RoHS; Temperature: -55°C+85°C; Tolerance: 10%; Voltage: 16V; Wattage: NA; Weight: NA; Datasheet: Y:\MIS_DATABASE\DATASHEETS\CAPACITORS\C2012.PDF
FL7-FL9 = EMI_LC_FILTER: PASSIVE FILTER EMI 670pF 0805-3; Chkd/date: MAZHAR/030809; Crtd /date: MAZHAR/281107; Custom_Duty: 24%; Customs_HS_Code: 85437099; Distributor_name: DIGIKEY; Distributor_part_number: 490-4016-1-ND; Height: 0.95MM; Mfr_name: MURATA; Mfr_part_number: NFL21SP106X1C3D; Mistral Part No: 130009030799; Package: 0805; Part_type: MISC\FILTER; Project: MICODER-1; Datasheet: Y:\MIS_DATABASE\DATASHEETS\ICS\MISC\NFL21SP.PDF
R486 = RESISTOR: RES 1K 1/16W 5% 0402; Alternate_mfr_name_A: AVX CORPORATION; Alternate_mfr_name_C: YAGEO AMERICA; Alternate_mfr_part_number_A: CR05-102J-H; Alternate_mfr_part_number_C: RC0402JR-071KL; Chkd/date: SHREESHAIL/121205; Crtd /date: MAZHAR/230805; Custom_Duty: 15%; Customs_HS_Code: 85332119; Distributor_name: DIGIKEY; Distributor_name_A: NA; Distributor_name_C: DIGIKEY; Distributor_part_number: P1.0KJCT-ND; Distributor_part_number_A: NA; Distributor_part_number_C: 311-1.0KJRCT-ND; Height: 0.40MM; Mfr_name: PANASONIC-ECG; Mfr_part_number: ERJ-2GEJ102X; Mistral Part No: 110009030400-R; Package: 0402; Part_type: RESISTORS\FIXED; Project: HSE; RoHS: RoHS; Tolerance: 5%; Wattage: 1/16W; Datasheet: Y:\MIS_DATABASE\DATASHEETS\RESISTORS\ERJ12.PDF
TP159 = TESTPOINT: TESTPOINT 40 SMD; Chkd/date: MAZHAR/190505; Crtd /date: MAZHAR/190505; Distributor_name: NA; Distributor_part_number: NA; Height: NA; Mfr_name: LOCAL; Mistral Part No: 130009030933; Part_type: MISC\TESTPOINT; Project: RAINIER-3
U31 = SN74AVC4T245PW_TSSOP16: IC 4-BIT DUAL SUPPLY BUS TRANSCEIVER TSSOP16; Chkd/date: SHREESHAIL/030506; Crtd /date: MAZHAR/270406; Custom_Duty: 15%; Customs_HS_Code: 85423100; Distributor_name: MOUSER; Distributor_part_number: 595-SN74AVC4T245PW; Height: 1.20MM; Mfr_name: TEXAS INSTRUMENTS; Mistral Part No: 141009030111-R; Package: TSSOP16; Part_type: ICS\DIGITAL\COMBINATIONAL; Project: VOCERA; RoHS: Sb/ Br FREE; Datasheet: Y:\MIS_DATABASE\DATASHEETS\ICS\DIGITAL\BUSTRANSCEIVER\SN74AVC4T245.PDF
U56 = CS2000CP-CZZ_MSOP10: IC FRACTIONAL-N CLOCK SYNTHSIZER MSOP10; Chkd/date: NAVEED/241114; Crtd /date: VASANTHA/240914; Custom_Duty: 15%; Customs_HS_Code: 85423100; Distributor_name: DIGIKEY; Distributor_part_number: 598-1748-ND; Height: 1.10MM; Mfr_name: CIRRUS LOGIC; Mistral Part No: 140114090011-R; Package: MSOP10; Part_type: ICS\ANALOG\SYNTHESIZER; Project: GALILEO_EVM; RoHS: RoHS; Temperature: -10°C+70°C; Tolerance: NA; Voltage: NA; Wattage: NA; Weight: NA; Datasheet: Y:\MIS_DATABASE\DATASHEETS\ICS\SYNTHESIZER\CS2000CP.PDF
U60 = OSC_E6718LF: OSC 20.000MHz SMD; Chkd/date: NAVEED/070115; Crtd /date: JEBRAN/141114; Custom_Duty: 24%; Customs_HS_Code: 85437099; Distributor_name: NA; Distributor_part_number: NA; Height: 2.25MM; Mfr_name: RAKON; Mfr_part_number: E6718LF; Mistral Part No: 130014110017-R; Package: SMD; Part_type: OSCILLATORS; Project: GALILEO EVM; RoHS: RoHS; Temperature: -55°C+125°C; Tolerance: NA; Voltage: NA; Wattage: NA; Weight: NA; Datasheet: Y:\MIS_DATABASE\DATASHEETS\MISC\CRY_OSC\E6718LF.PDF
U78 = REF5025IDGKT_MSOP8: IC PRECISION VOLTAGE REFERENCE 2.5V MSOP8; Chkd/date: NAVEED/300315; Crtd /date: VASANTHA/240215; Custom_Duty: 15%; Customs_HS_Code: 85423100; Distributor_name: DIGIKEY; Distributor_part_number: 296-24498-1-ND; Height: 1.10MM; Mfr_name: TEXAS INSTRUMENTS; Mistral Part No: 142015020006-R; Package: MSOP8; Part_type: ICS\POWER\VOLTAGE REGULATOR; Project: GALILEO_EVM; RoHS: RoHS; Temperature: -40°C+125°C; Tolerance: NA; Voltage: 2.5V; Wattage: NA; Weight: NA; Datasheet: Y:\MIS_DATABASE\DATASHEETS\ICS\POWER\REF5025.PDF
U79 = DAC8550IBD_VSSOP8: IC DAC 16-BIT ULTRA-LOW GLITCH OUTPUT VOLTAGE VSSOP8; Chkd/date: NAVEED/281114; Crtd /date: VASANTHA/281014; Custom_Duty: 15%; Customs_HS_Code: 85423100; Distributor_name: DIGIKEY; Distributor_part_number: 296-19621-1-ND; Height: 1.10MM; Mfr_name: TEXAS INSTRUMENTS; Mistral Part No: 141014100017-R; Package: VSSOP8; Part_type: ICS\DTOA; Project: GALILEO_EVM; RoHS: RoHS; Temperature: -40°C+105°C; Tolerance: NA; Voltage: NA; Wattage: NA; Weight: NA; Datasheet: Y:\MIS_DATABASE\DATASHEETS\ICS\ATOD_DTOA\DAC8550X.PDF
Y7 = CRY: CRY 12.288MHz SMD; Chkd/date: NAVEED/070115; Crtd /date: VASANTHA/111114; Custom_Duty: 24%; Customs_HS_Code: 85439000; Distributor_name: DIGIKEY; Distributor_part_number: CTX511CT-ND; Height: 4.30MM; Mfr_name: CTS; Mfr_part_number: ATS122SM-1; Mistral Part No: 130014110010-R; Package: SMD; Part_type: CRYSTAL; Project: GALILEO_EVM; RoHS: RoHS; Temperature: -20°C+70°C; Tolerance: NA; Voltage: NA; Wattage: NA; Weight: NA; Datasheet: Y:\MIS_DATABASE\DATASHEETS\MISC\CRY_OSC\ATSXXX.PDF

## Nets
DGND: C122.2 C233.2 C236.2 C238.2 C239.1 C240.2 C254.2 C255.2 C262.2 C265.2 C266.2 C268.1 C269.2 C271.2 C272.1 C273.2 C274.2 C276.2 C277.2 C278.2 C282.2 C283.1 C292.2 C293.1 C295.1 C296.2 C303.2 C467.1 C612.2 C626.2 C630.2 C632.2 C635.2 C637.2 C639.2 C641.2 C642.2 C643.2 C646.2 C647.2 C665.1 C666.2 C670.2 C777.2 C778.2 FL7.2 FL8.2 FL9.2 R283.1 R302.1 R474.2 R479.2 R483.2 R487.2 R677.1 R684.1 R690.1 R730.2 R732.2 R734.2 R738.2 U31.8(GND1) U31.9(GND2) U56.2(GND) U60.4(GND) U62.9(PRI_REFN) U62.49(EP) U78.4(GND) U79.8(GND) Y8.2 Y8.4 ; also on sheet 1 11 12 13 14 15 16 17 18 19 20 21 22 23 24 25 26 27 28 29 30 31 32 33 34 35 38 39 40 41 42 43 44 45 46 47 48 49 50
VCC3V3_BMC: C122.1 R266.2 R282.2 R291.2 R863.1 U31.1(VCCA) ; also on sheet 13 28 29 38 45 46 47 50
VCC3V3_CDCM: C276.1 C282.1 C467.2 C612.1 C639.1 C641.1 C642.1 C643.1 C646.1 C647.1 FL7.1 FL8.1 FL9.1 R475.1 R485.1 R731.1 R733.1 R895.2 U31.16(VCCB) U62.7(VDD_PRI_REF) U62.10(VDD_SEC_REF) U62.13(VDD_Y0_Y1) U62.18(VDD_Y0_Y1) U62.34(VDD_Y7) U62.48(DVDD)
VCC3V3_DCIN: C233.1 C236.1 C240.1 C255.1 C265.1 C266.1 C630.1 C632.1 FB26.2 FB31.2 R478.1 R895.1 U56.1(VD) ; also on sheet 11 17 18 19 20 21 22 23 24 25 26 27 28 29 30 31 32 33 34 35 38 43 44 45 46 47 48 50
VDD2_PLL1: C269.1 C635.1 FB31.1 U62.37(VDD_PLL1)
VDD2_PLL2: C262.1 C626.1 FB26.1 U62.38(VDD_PLL2) U62.39(VDD_VCO)
24MHz_LVCMOS_USB0_CLK: R489.1 U62.29(Y5_P)
24MHz_LVCMOS_USB1_CLK: R488.1 U62.28(Y5_N)
24MHZ_LVDS_N: R22.1 U62.25(Y4_N)
24MHZ_LVDS_P: R21.1 U62.26(Y4_P)
100MHZ_HCSL_N: R891.1 U62.36(Y7_N)
100MHZ_HCSL_P: R890.1 U62.35(Y7_P)
100MHZ_LVDS_N: R18.1 U62.21(Y2_N)
100MHZ_LVDS_P: R17.1 U62.20(Y2_P)
250MHz_LVDS_CPTS_REF_CLKN: R24.2 ; also on sheet 11
250MHz_LVDS_CPTS_REF_CLKP: R23.2 ; also on sheet 11
250MHZ_LVDS_N: R24.1 U62.33(Y6_N)
250MHZ_LVDS_P: R23.1 U62.32(Y6_P)
BMC_CLK_PDN: U31.4(1A1) ; also on sheet 46
BMC_CLK_SYNC: U31.5(1A2) ; also on sheet 46
BMC_ISOL_EN5: R283.2 R863.2 U31.14(~{2OE}) ; also on sheet 47
BMC_SPI0_CS0n: U31.6(2A1) ; also on sheet 47
CDCM_1V8: C777.1 C778.1 R857.2 R896.2 U62.19(VDD_Y2_Y3) U62.24(VDD_Y2_Y3) U62.27(VDD_Y4) U62.30(VDD_Y5) U62.31(VDD_Y6)
CDCM_PDN#: R474.1 U31.13(1B1) U62.43(PDN)
CDCM_RST: C637.1 U62.44(RESETN/PWR) ; also on sheet 47
CDCM_SPI_CLK: U62.5(SCL/PIN4) ; also on sheet 47
CDCM_SPI_CS0: U31.11(2B1) U62.4(SCS/AD1/PIN3)
CDCM_SPI_MISO: U62.3(SDO/AD0/PIN2) ; also on sheet 47
CDCM_SPI_MOSI: U62.2(SDI/SDA/PIN1) ; also on sheet 47
CDCM_SYNC#: R475.2 U31.12(1B2) U62.42(SYNCN)
CLK2_SI_MODE0: R483.1 R733.2 U62.1(SI_MODE0)
CLK2_SI_MODE1: R479.1 R731.2 U62.47(SI_MODE1)
CLK_REF_SEL: R485.2 R738.1 U62.6(REF_SEL) ; also on sheet 47
CS2_AD0: R478.2 R730.1 U56.8(AD0/~{CS})
CS2000_AUX_OUT: U56.4(AUX_OUT) ; also on sheet 12
CS2000_CLKIN: U56.5(CLK_IN) ; also on sheet 29 33
DAC_VOUT: C670.1 R486.2 U79.3(VFB) U79.4(VOUT)
DDR_CLKN_LVDS_100MHz: R18.2 ; also on sheet 16
DDR_CLKP_LVDS_100MHz: R17.2 ; also on sheet 16
ELF1: C254.1 R461.1 U62.41(ELF)
LDO1_1V8: R896.1 ; also on sheet 13 18 23 24 30 48
LDO3_1V8: R857.1 ; also on sheet 18 48
PCIE_CLKN_CML_100MHz: R20.2 ; also on sheet 26
PCIE_CLKN_HCSL_100MHz: R732.1 R891.2 ; also on sheet 26
PCIE_CLKP_CML_100MHz: R19.2 ; also on sheet 26
PCIE_CLKP_HCSL_100MHz: R734.1 R890.2 ; also on sheet 26
PLL_LOCK: U62.46(STATUS0) ; also on sheet 46
SEC_REFN: R493.2 U62.12(SEC_REFN)
SEC_REFP: R496.2 U62.11(SEC_REFP)
SOC_I2C1_SCL: R803.1 ; also on sheet 21 22 23 33 35
SOC_I2C1_SDA: R804.1 ; also on sheet 21 22 23 33 35
SOC_McASP2AHCLKR: U56.3(CLK_OUT) ; also on sheet 33
SOC_SPI3_CLK: R450.2 U79.6(SCLK)
SOC_SPI3_MISO: TP159.1(TP) U1.F25(SPI3_SOMI/PR0_UART0_CTSN/GPIO0_89)
SOC_SPI3_MOSI: U1.F24(SPI3_SIMO/PR0_UART0_RTSN/GPIO0_90) U79.7(DIN)
SOC_SPI3_SCS0: R828.1 U1.C24(SPI3_SCSn0/PR0_eCAP0_eCAP_CAPIN_APWM_O/GPIO0_86)
SOC_SPI3_SCS0_R: R828.2 U79.5(~{SYNC})
SOC_SYSCLKN: R22.2 ; also on sheet 11
SOC_SYSCLKP: R21.2 ; also on sheet 11
SOC_USB0_XO: R489.2 ; also on sheet 11
SOC_USB1_XO: R488.2 ; also on sheet 11
VCTCXO_20M: C274.1 U60.5(RFOUTPUT) U62.8(PRI-REFP)
N16958621: C239.2 U62.40(REG_CAP)
N16958654: TP158.1(TP) U62.45(STATUS1/PIN0)
N16974283: C238.1 R461.2
N17012640: C278.1 U56.6(XTO) Y7.2
N17012642: C271.1 U56.7(XTI/REF_CLK) Y7.1
N17277948: C296.1 C665.2 FL8.3 U78.2(VIN)
N17278529: C666.1 U78.5(TRIM/NR)
N17278696: C303.1 U78.6(VOUT) U79.2(VREF)
N17279260: C292.1 C293.2 FL9.3 U79.1(VDD)
N17280261: C272.2 C273.1 FL7.3 U60.9(VCC)
N17291112: C277.1 R486.1 R487.1 U60.10(VC)
N19738237: R266.1 R677.2 U31.15(~{1OE})
N19776321: R450.1 U1.E24(SPI3_CLK/PR0_UART0_TXD/GPIO0_88)
N21135598: TP160.1(TP) U62.14(Y0_P)
N21135600: TP161.1(TP) U62.15(Y0_N)
N21170847: R302.2 U31.7(2A2)
N21170992: R282.1 R684.2 U31.2(1DIR)
N21171020: R291.1 R690.2 U31.3(2DIR)
N21185356: C283.2 R493.1 R495.2 Y8.1
N21185385: C295.2 R495.1 R496.1 Y8.3
N21231083: C268.2 U60.8(TRISTATE-EN)
N22048902: R19.1 U62.23(Y3_P)
N22048912: R20.1 U62.22(Y3_N)
N22048972: TP162.1(TP) U62.16(Y1_N)
N22048974: TP163.1(TP) U62.17(Y1_P)
N22367180: R803.2 U56.9(SCL/CCLK)
N22367188: R804.2 U56.10(SDA/CDIN)

Not connected (* = marked no-connect by the designer): U31 10(2B2)*; U60 1(DNC1)* 2(NC1)* 3(DNC2)* 6(NC2)* 7(NC3)*; U78 1(DNC1)* 3(TEMP)* 7(NC)* 8(DNC2)*

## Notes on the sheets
sheet 36
- CLOCK GENERATOR
- MODE SELECTION FOR CDCM DEVICE
- MODE
  SELECTED
- SI_MODE1
- SI_MODE0
- 0
- 0
- SPI MODE
- 0
- 1
- I2C MODE
- PIN MODE
  (NO SERIAL
  PROGRAMMING)
- 1
- 0
- 1
- 1
- RESERVED
sheet 37
- GENERATOR - AUDIO CLOCK DOMAIN
- BMC ISOLATOR 5
- I2C ADDR BIT SELECTION
- I2C ADDRESS: 0x4F
- AVB CLOCK GENERATOR- 1588 CLOCK DOMAIN
- SoC SPI3
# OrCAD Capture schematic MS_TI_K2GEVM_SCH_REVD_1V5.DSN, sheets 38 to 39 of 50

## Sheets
38 37. EMU & MIPI CON: size C; title: EMU & MIPI60 CONNECTOR
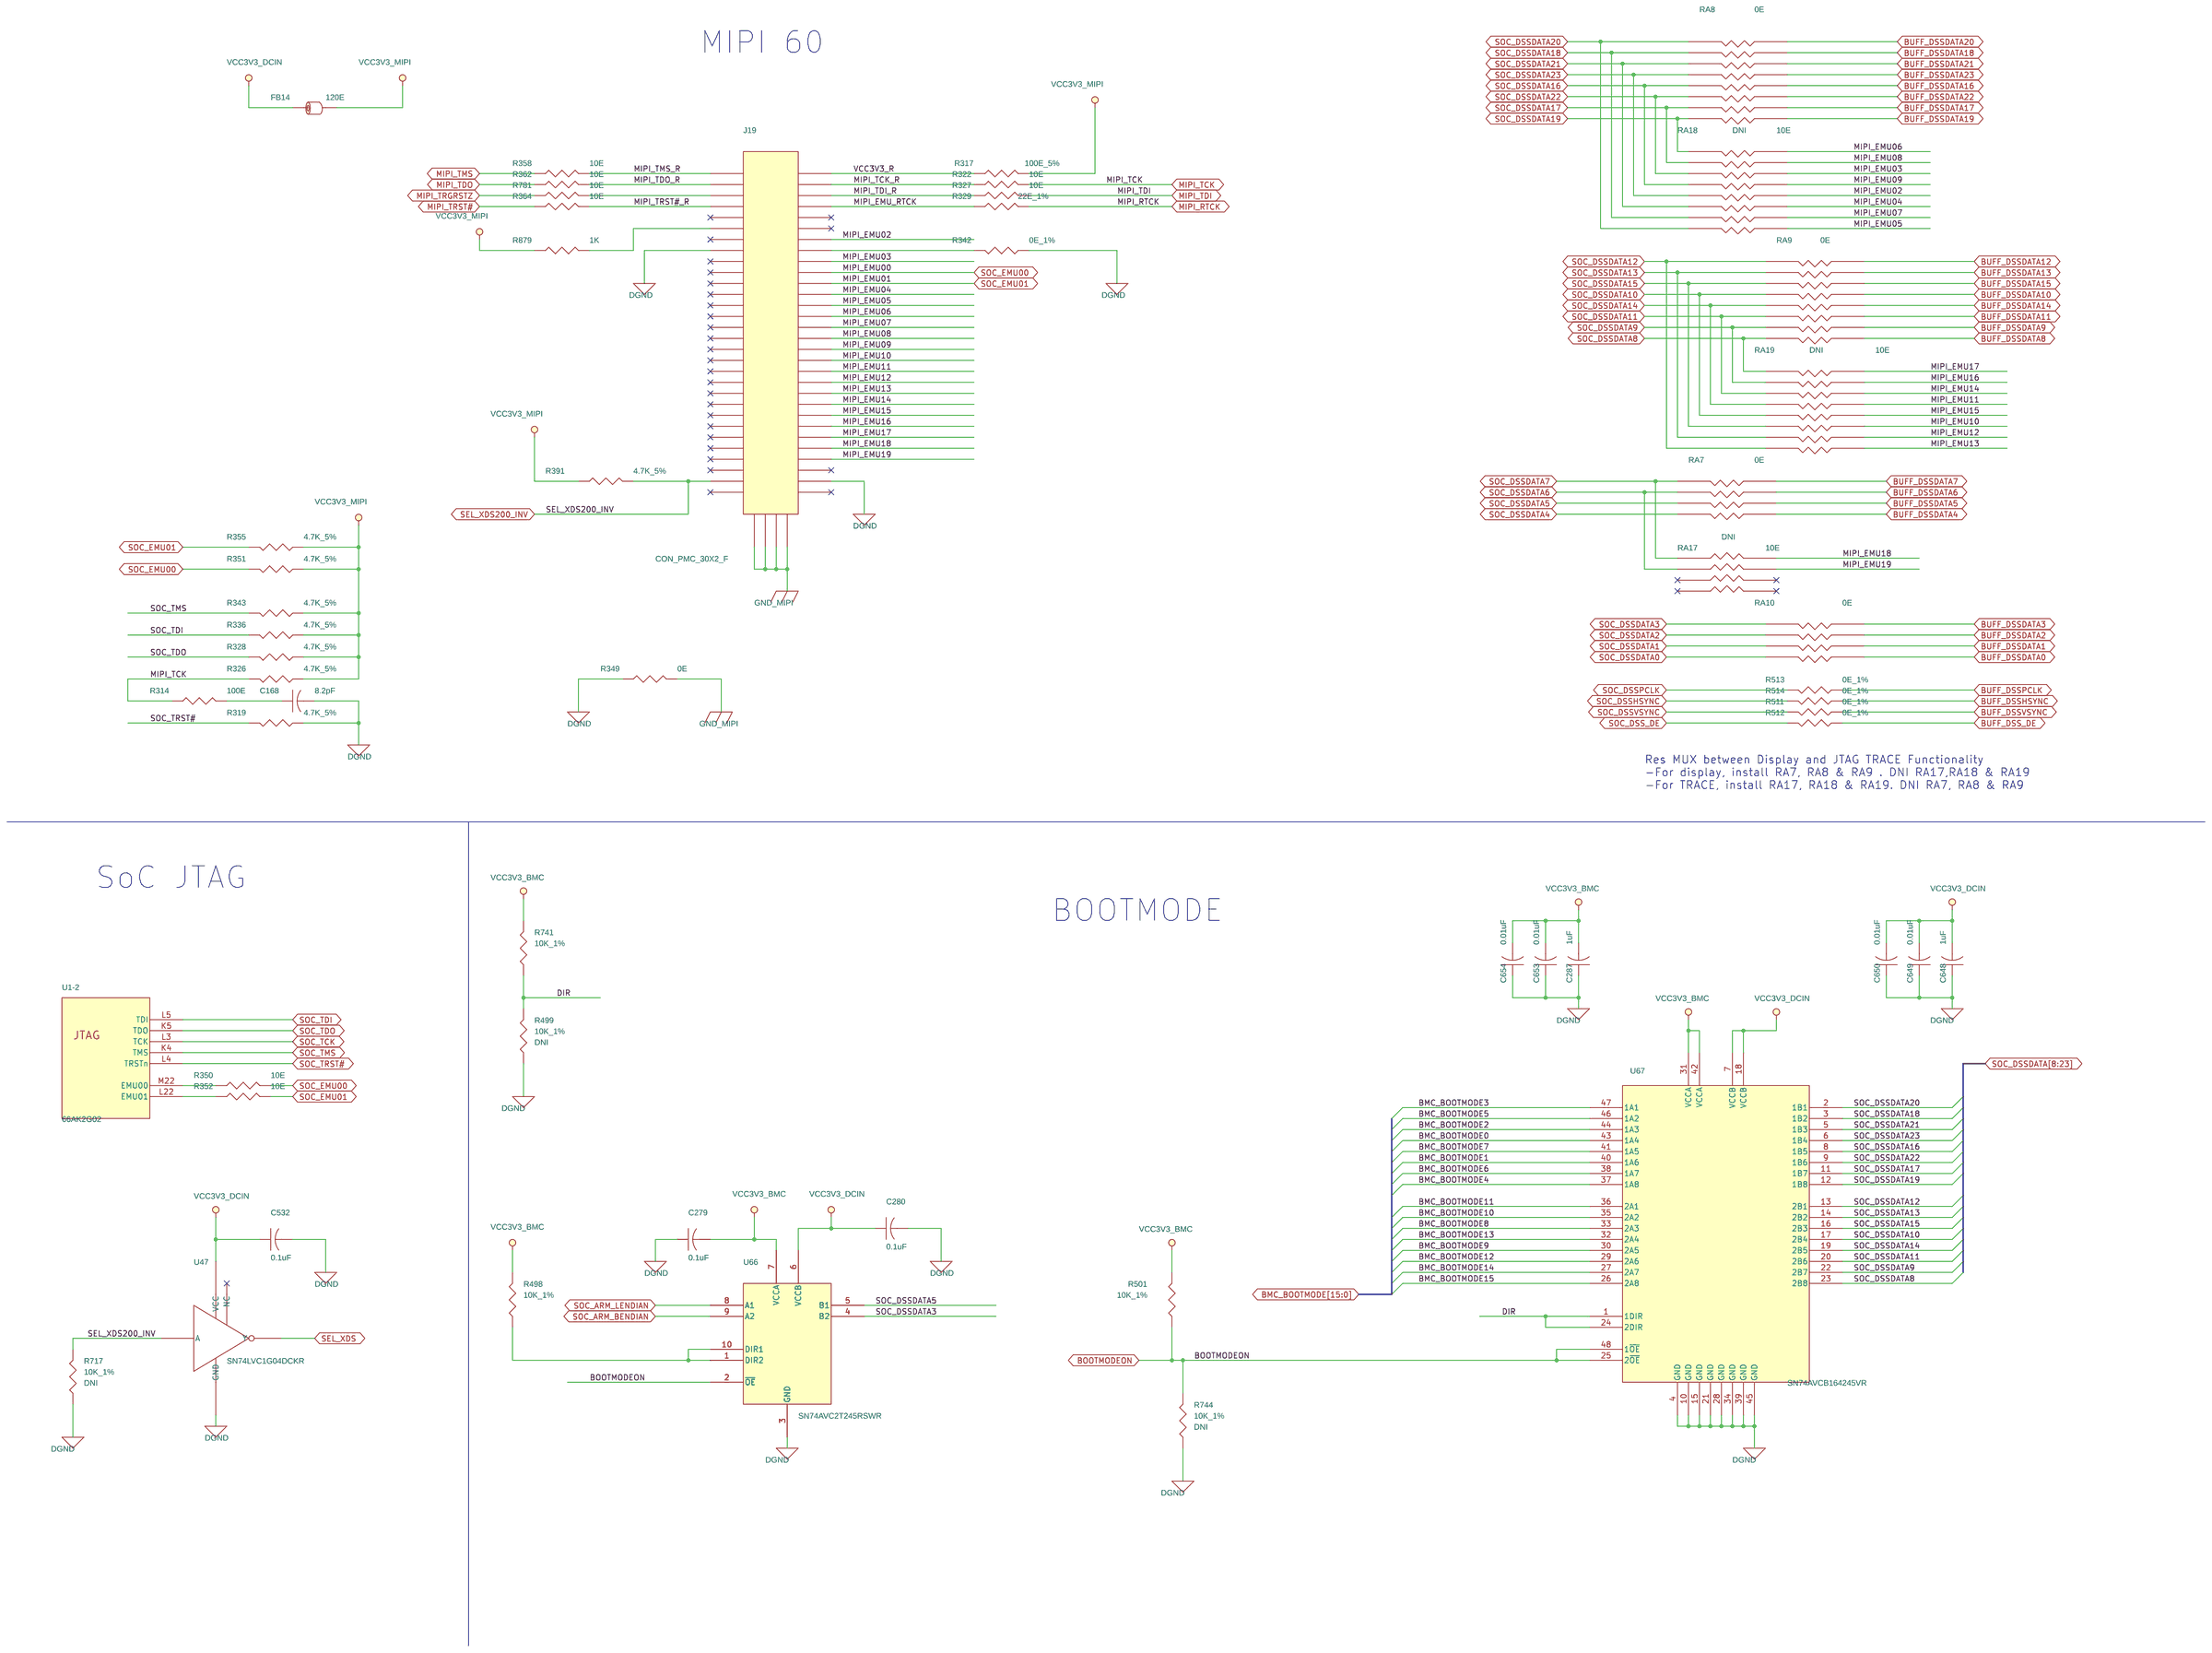
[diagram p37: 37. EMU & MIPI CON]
39 38. JTAG_XDS200_1: size C; title: XDS200

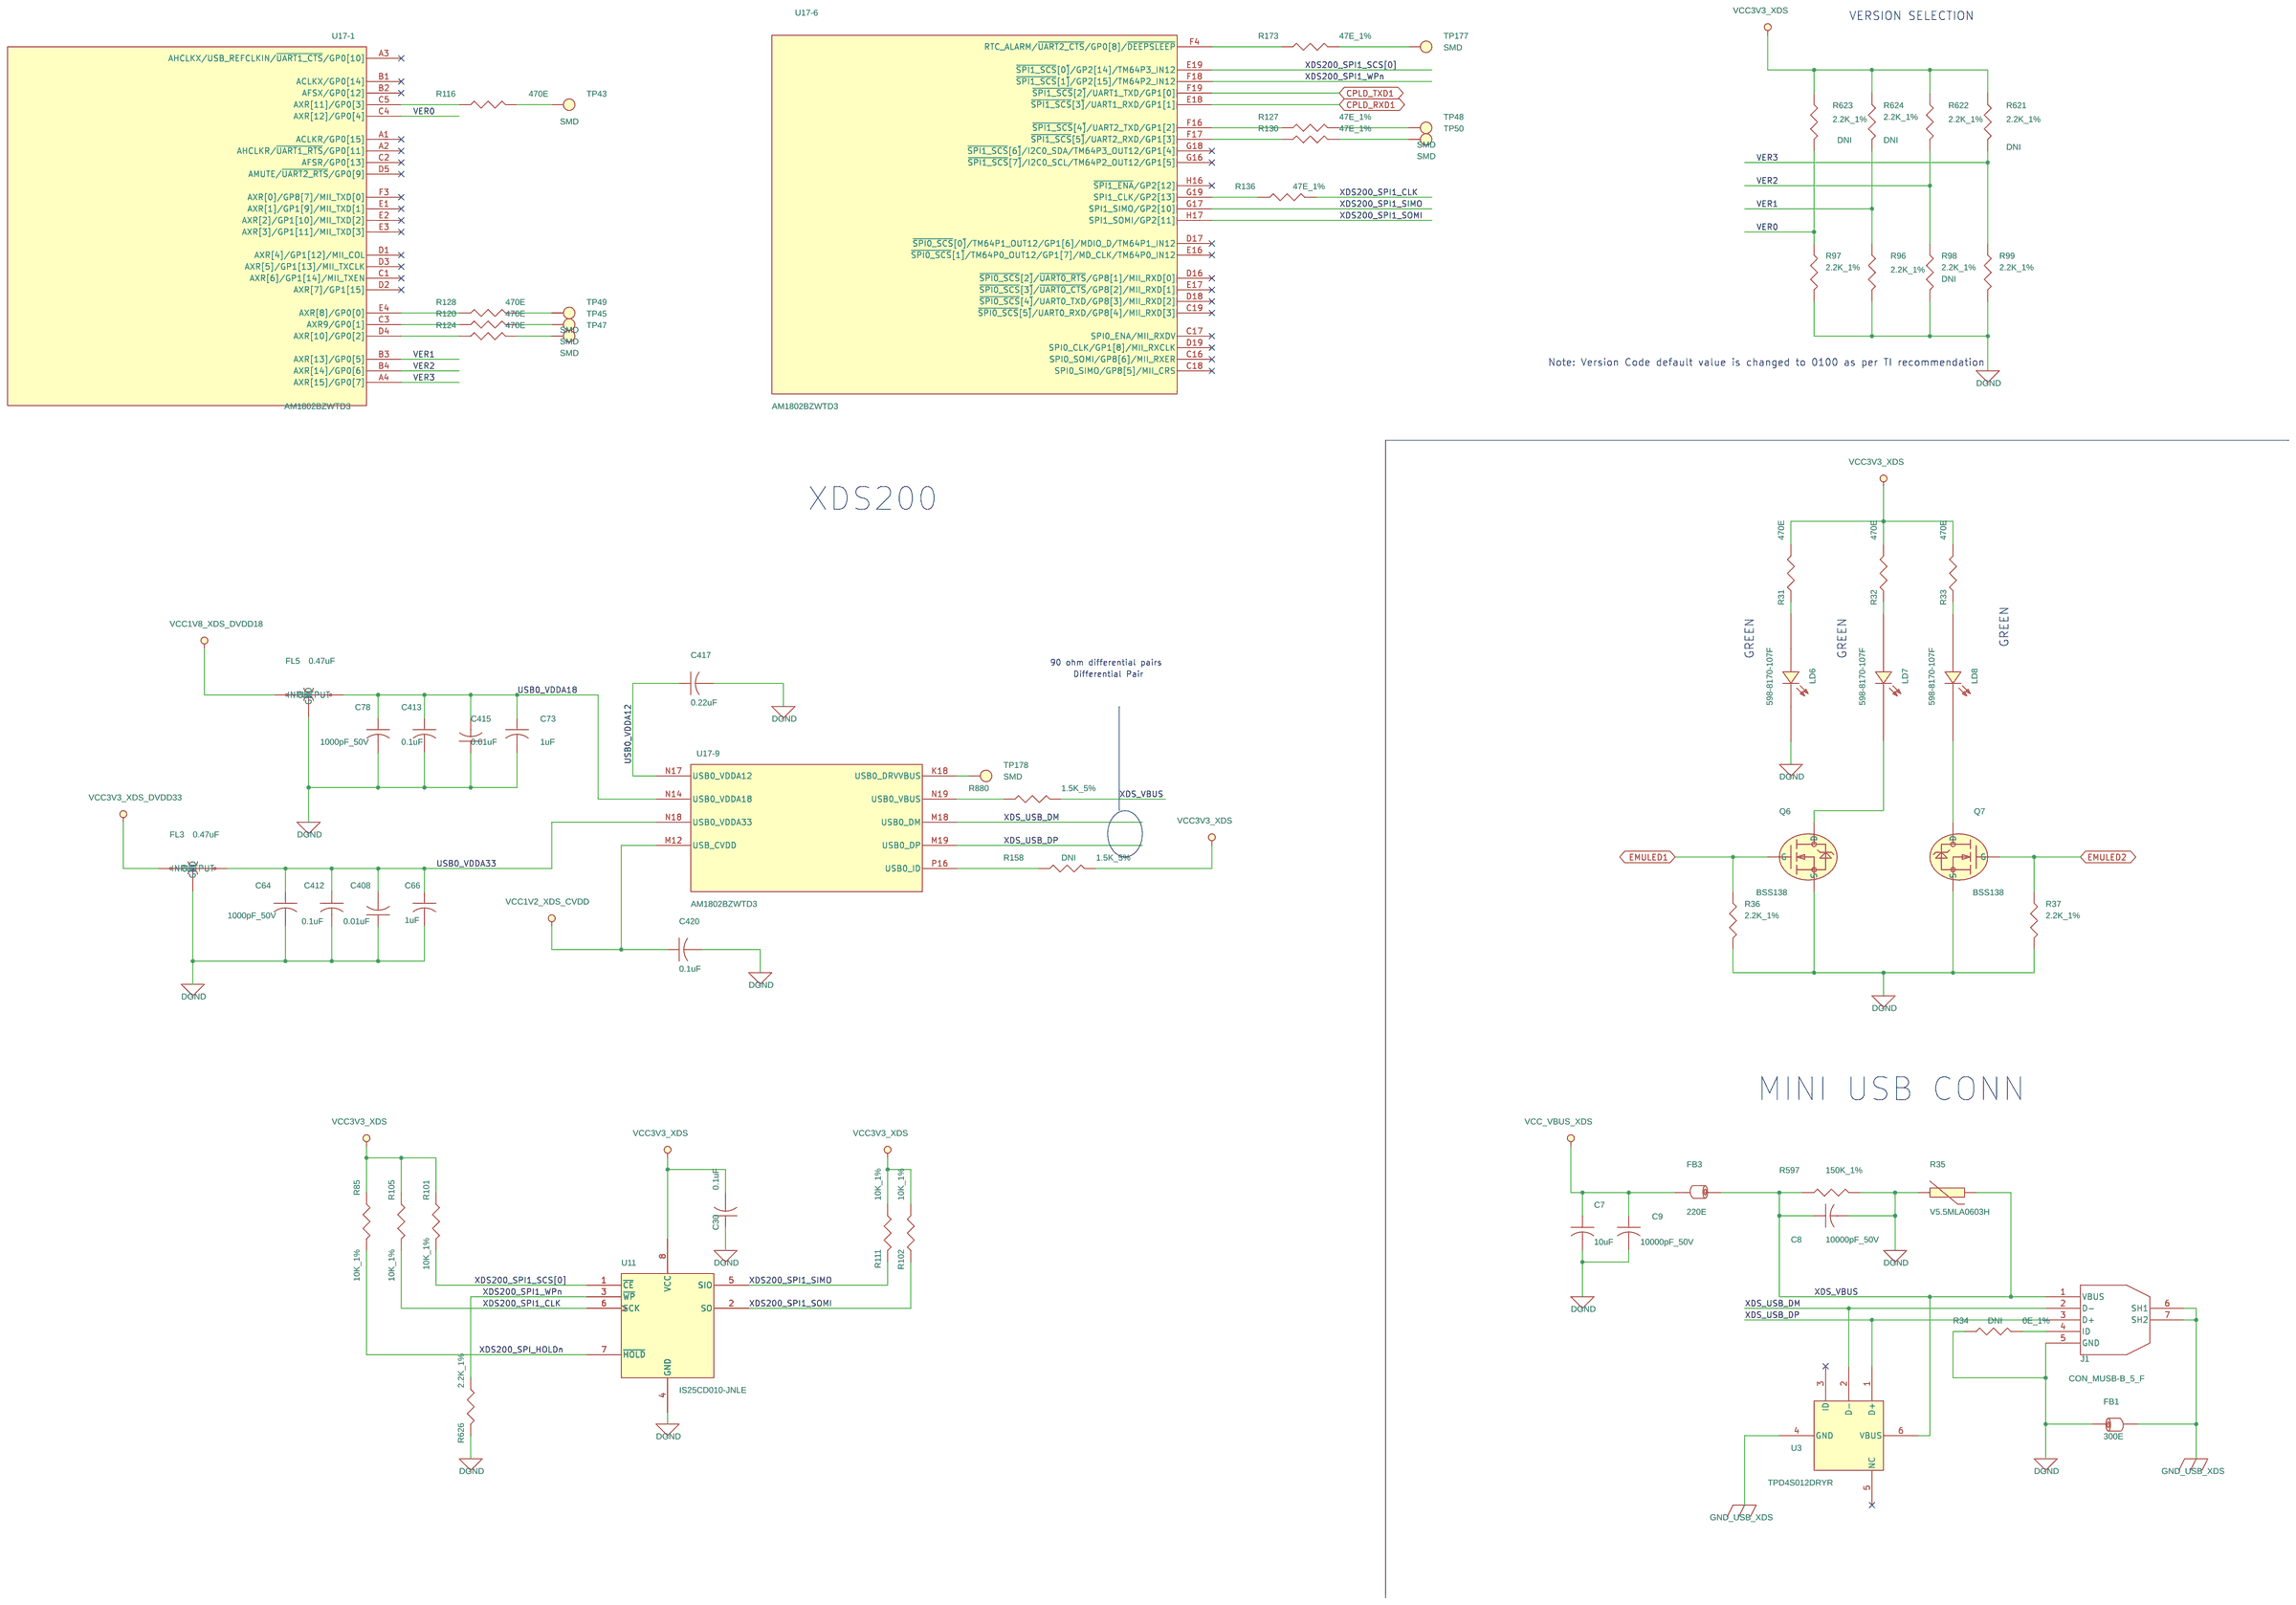
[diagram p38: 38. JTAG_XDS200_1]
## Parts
sheet 18. NAND FLASH & MICRO SD CARD
U1  66AK2G02_BGA625  [BGASKT625_31-49_1270x1270]  (sections -1,-10,-11,-12,-13,-14,-15,-16,-17,-18,-19,-2,-20,-21,-22,-23,-24,-25,-26,-27,-28,-29,-3,-30,-31,-32,-33,-34,-35,-36,-37,-38,-4,-5,-6,-7,-8,-9)
sheet 37. EMU & MIPI CON
C168  8.2pF  [CAP0402]
C279  0.1uF  [CAP0402]
C280  0.1uF  [CAP0402]
C287  1uF  [CAP0402]
C532  0.1uF  [CAP0402]
C648  1uF  [CAP0402]
C649  0.01uF  [CAP0402]
C650  0.01uF  [CAP0402]
C653  0.01uF  [CAP0402]
C654  0.01uF  [CAP0402]
FB14  120E  [IND0402]
J19  CON_PMC_30X2_F  [CON_PMC30X2_HQCD-030_S_S_S]
R314  100E  [RES0402]
R317  100E_5%  [RES0402]
R319  4.7K_5%  [RES0402]
R322  10E  [RES0402]
R326  4.7K_5%  [RES0402]
R327  10E  [RES0402]
R328  4.7K_5%  [RES0402]
R329  22E_1%  [RES0402]
R336  4.7K_5%  [RES0402]
R342  0E_1%  [RES0402]
R343  4.7K_5%  [RES0402]
R349  0E  [RES0402]
R350  10E  [RES0402]
R351  4.7K_5%  [RES0402]
R352  10E  [RES0402]
R355  4.7K_5%  [RES0402]
R358  10E  [RES0402]
R362  10E  [RES0402]
R364  10E  [RES0402]
R391  4.7K_5%  [RES0402]
R498  10K_1%  [RES0402]
R499  10K_1%  [RES0402]
R501  10K_1%  [RES0402]
R511  0E_1%  [RES0402]
R512  0E_1%  [RES0402]
R513  0E_1%  [RES0402]
R514  0E_1%  [RES0402]
R717  10K_1%  [RES0402]
R741  10K_1%  [RES0402]
R744  10K_1%  [RES0402]
R781  10E  [RES0402]
R879  1K  [RES0402]
RA7  0E  [RESA_0402-4]
RA8  0E  [RESA_0402-8]
RA9  0E  [RESA_0402-8]
RA10  0E  [RESA_0402-4]
RA17  10E  [RESA_0402-4]
RA18  10E  [RESA_0402-8]
RA19  10E  [RESA_0402-8]
U47  SN74LVC1G04DCKR  [SC70-5]
U66  SN74AVC2T245RSWR  [QFN10_15-74_75X60]
U67  SN74AVCB164245VR  [TVSOP48_15-74_385X180]
sheet 38. JTAG_XDS200_1
C7  10uF  [CAP1210]
C8  10000pF_50V  [CAP0402]
C9  10000pF_50V  [CAP0402]
C30  0.1uF  [CAP0402]
C64  1000pF_50V  [CAP0402]
C66  1uF  [CAP0402]
C73  1uF  [CAP0402]
C78  1000pF_50V  [CAP0402]
C408  0.01uF  [CAP0402]
C412  0.1uF  [CAP0402]
C413  0.1uF  [CAP0402]
C415  0.01uF  [CAP0402]
C417  0.22uF  [CAP0402]
C420  0.1uF  [CAP0402]
FB1  300E  [IND0603]
FB3  220E  [IND0603]
FL3  0.47uF  [EMIFIL_NFM18PS_0603]
FL5  0.47uF  [EMIFIL_NFM18PS_0603]
J1  CON_MUSB-B_5_F  [CON_USBB5_54819-0511_S_R_T]
LD6  598-8170-107F  [LED_0805]
LD7  598-8170-107F  [LED_0805]
LD8  598-8170-107F  [LED_0805]
Q6  BSS138  [TO_SOT23-123]
Q7  BSS138  [TO_SOT23-123]
R31  470E  [RES0402]
R32  470E  [RES0402]
R33  470E  [RES0402]
R34  0E_1%  [RES0402]
R35  V5.5MLA0603H  [VAR0603]
R36  2.2K_1%  [RES0402]
R37  2.2K_1%  [RES0402]
R85  10K_1%  [RES0402]
R96  2.2K_1%  [RES0402]
R97  2.2K_1%  [RES0402]
R98  2.2K_1%  [RES0402]
R99  2.2K_1%  [RES0402]
R101  10K_1%  [RES0402]
R102  10K_1%  [RES0402]
R105  10K_1%  [RES0402]
R111  10K_1%  [RES0402]
R116  470E  [RES0402]
R120  470E  [RES0402]
R124  470E  [RES0402]
R127  47E_1%  [RES0402]
R128  470E  [RES0402]
R130  47E_1%  [RES0402]
R136  47E_1%  [RES0402]
R158  1.5K_5%  [RES0402]
R173  47E_1%  [RES0402]
R597  150K_1%  [RES0402]
R621  2.2K_1%  [RES0402]
R622  2.2K_1%  [RES0402]
R623  2.2K_1%  [RES0402]
R624  2.2K_1%  [RES0402]
R626  2.2K_1%  [RES0402]
R880  1.5K_5%  [RES0402]
TP43  SMD  [TP40_SMD]
TP45  SMD  [TP40_SMD]
TP47  SMD  [TP40_SMD]
TP48  SMD  [TP40_SMD]
TP49  SMD  [TP40_SMD]
TP50  SMD  [TP40_SMD]
TP177  SMD  [TP40_SMD]
TP178  SMD  [TP40_SMD]
U3  TPD4S012DRYR  [SON6_19-68_60X45]
U11  IS25CD010-JNLE  [SOIC8]
sheet 39. JTAG_XDS200_2
U17  AM1802BZWTD3  [BGA361_31-49_635X635]  (sections -1,-10,-11,-12,-13,-14,-2,-3,-4,-5,-6,-7,-8,-9)

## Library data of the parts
U1 = 66AK2G02_BGA625: IC ARM CORTEX AND DSP 32 BIT MICROPROCESSOR BGA625; Chkd/date: NAVEED/141114; Color: Default; Crtd /date: VASANTHA/081014; Custom_Duty: 15%; Customs_HS_Code: 85423100; Distributor_name: NA; Distributor_part_number: NA; Height: 1.70MM; Location X-Coordinate: 0; Location Y-Coordinate: 0; Mfr_name: TEXAS INSTRUMENTS; Mfr_part_number: 66AK2G02; Mistral Part No: 141014100003; Package: BGA625; Part_type: ICS\DIGITAL\MICROPROCESSOR; Power Pins Visible: False; Primitive: DEFAULT; Project: GALILEO_EVM; Tolerance: NA; Voltage: NA; Wattage: NA; Weight: NA; Datasheet: Y:\MIS_DATABASE\DATASHEETS\ICS\DIGITAL\MICROCONTROLLER\SG-BGA-6094.PDF    Y:\MIS_DATABASE\DATASHEETS\ICS\DIGITAL\MICROCONTROLLER\SG-BGA_FP.PDF
C168 = CAP: CAP CERAMIC 8.2pF 50V 5% C0G 0402; Chkd/date: SUHAS/200411; Crtd /date: MAZHAR/120411; Custom_Duty: 15%; Customs_HS_Code: 85322990; Distributor_name: DIGIKEY; Distributor_part_number: 712-1293-1-ND; Height: 0.55MM; Mfr_name: JOHANSON TECHNOLOGY; Mfr_part_number: 500R07S8R2CV4T; Mistral Part No: 120011040005-R; Package: 0402; Part_type: CAPACITORS\CERAMIC; Project: IDMATEK2; RoHS: RoHS; Temperature: -55°C+125°C; Tolerance: 5%; Voltage: 50V; Weight: NA; Datasheet: Y:\MIS_DATABASE\DATASHEETS\CAPACITORS\500R07S.PDF
C30 C279 C280 C412 C413 C420 C532 = CAP: CAP CERAMIC 0.1uF 16V 10% X7R 0402; Alternate_mfr_name_A: KEMET; Alternate_mfr_part_number_A: C0402C104K4RACT; Chkd/date: MAZHAR/281108; Crtd /date: MAZHAR/030907; Custom_Duty: 15%; Customs_HS_Code: 85322990; Distributor_name: DIGIKEY; Distributor_name_A: DIGIKEY; Distributor_part_number: 490-3261-1-ND; Distributor_part_number_A: 399-3521-1-ND; Height: 0.55MM; Mfr_name: MURATA; Mfr_part_number: GRM155R71C104KA88D; Mistral Part No: 120009030060-R; Package: 0402; Part_type: CAPACITORS\CERAMIC; Project: SMART VIEW_IP CAMERA; Tolerance: 10%; Voltage: 16V; Datasheet: Y:\MIS_DATABASE\DATASHEETS\CAPACITORS\GRM188SERIES.PDF
C66 C73 C287 C648 = CAP: CAP CERAMIC 1uF 10V 10% X5R 0402; Chkd/date: BALACHANDAR/160514; Crtd /date: SARANYA/060514; Custom_Duty: 15%; Customs_HS_Code: 85322990; Distributor_name: DIGIKEY; Distributor_part_number: 478-4596-1-ND; Height: 0.56MM; Mfr_name: AVX CORPORATION; Mfr_part_number: 0402ZD105KAT2A; Mistral Part No: 120014050010-R; Package: 0402; Part_type: CAPACITORS\CERAMIC; Project: AEGIS GP BETA2; RoHS: RoHS; Temperature: -55°C+85°C; Tolerance: 10%; Voltage: 10V; Wattage: NA; Weight: NA; Datasheet: Y:\MIS_DATABASE\DATASHEETS\CAPACITORS\AVX_MLC.PDF
C408 C415 C649 C650 C653 C654 = CAP: CAP CERAMIC 0.01uF 16V 10% X7R 0402; Alternate_mfr_name_A: AVX CORPORATION; Alternate_mfr_name_B: KEMET; Alternate_mfr_name_D: TDK CORPORATION; Alternate_mfr_part_number_A: 0402YC103KAT2A; Alternate_mfr_part_number_B: C0402C103K4RACTU; Alternate_mfr_part_number_D: C1005X7R1C103K; Chkd/date: SHREESHAIL/180506; Crtd /date: MAZHAR/110506; Custom_Duty: 15%; Customs_HS_Code: 85322990; Distributor_name: DIGIKEY; Distributor_name_A: DIGIKEY; Distributor_name_B: DIGIKEY; Distributor_name_D: DIGIKEY; Distributor_part_number: PCC103BQCT-ND; Distributor_part_number_A: 478-1114-1-ND; Distributor_part_number_B: 399-1038-1-ND; Distributor_part_number_D: 445-1262-1-ND; Height: 0.55MM; Mfr_name: PANASONIC-ECG; Mfr_part_number: ECJ-0EB1C103K; Mistral Part No: 120009030032-R; Package: 0402; Part_type: CAPACITORS\CERAMIC; Project: VOCERA; RoHS: RoHS; Tolerance: 10%; Voltage: 16V; Datasheet: Y:\MIS_DATABASE\DATASHEETS\CAPACITORS\PAN-ECJ.PDF
FB14 = INDUCTOR_FERRITE: IND BEAD CHIP 120E 1.2A 0402; Chkd/date: ASHOK/240212; Crtd /date: BAVISH/060711; Custom_Duty: 24%; Customs_HS_Code: 85437099; Distributor_name: DIGIKEY; Distributor_part_number: 445-2981-1-ND; Height: 0.55MM; Mfr_name: TDK CORPORATION; Mfr_part_number: MPZ1005S121C; Mistral Part No: 130011070007-R; Package: 0402; Part_type: INDUCTOR; Project: SVDU; RoHS: RoHS; Temperature: -40°C+85°C; Tolerance: NA; Voltage: NA; Wattage: NA; Weight: 1mg; Datasheet: Y:\MIS_DATABASE\DATASHEETS\DISCRETES\INDUCTORS\MPZ1005.PDF
J19 = CON_PMC_30X2_F: CON PMC 30X2 0.50MM PITCH FEMALE ST SMD; Chkd/date: MAZHAR/180208; Crtd /date: USMAN/051108; Custom_Duty: 24%; Customs_HS_Code: 85369090; Height: 3.25MM; Mfr_name: SAMTEC; Mfr_part_number: QSH-030-01-L-D-A; Mistral Part No: 150009030606; Package: SMD; Part_type: CONNECTOR\PMC; Project: KHAN_HSST; Datasheet: Y:\MIS_DATABASE\DATASHEETS\CONNECTORS\QSH.PDF
R314 = RESISTOR: RES 100E 1/16W 5% 0402; Alternate_mfr_name_A: AVX CORPORATION; Alternate_mfr_name_C: YAGEO AMERICA; Alternate_mfr_name_D: YAGEO AMERICA; Alternate_mfr_part_number_A: CR05-101J-H; Alternate_mfr_part_number_C: 9C04021A1000JLHF3; Alternate_mfr_part_number_D: RC0402JR-07100RL; Chkd/date: SHREESHAIL/210406; Crtd /date: GEETHA/200406; Custom_Duty: 15%; Customs_HS_Code: 85332119; Distributor_name: DIGIKEY; Distributor_name_A: NA; Distributor_name_C: DIGIKEY; Distributor_name_D: DIGIKEY; Distributor_part_number: P100JCT-ND; Distributor_part_number_A: NA; Distributor_part_number_C: 311-100JCT-ND; Distributor_part_number_D: 311-100JRCT-ND; Height: 0.40MM; Mfr_name: PANASONIC-ECG; Mfr_part_number: ERJ-2GEJ101X; Mistral Part No: 110009030164-R; Package: 0402; Part_type: RESISTORS\FIXED; Project: RED EYE; RoHS: RoHS; Tolerance: 5%; Wattage: 1/16W; Datasheet: Y:\MIS_DATABASE\DATASHEETS\RESISTORS\ERJ12.PDF
R317 = RESISTOR: RES 100E 1/16W 5% 0402; Chkd/date: VASANTHA/200614; Crtd /date: NAVEED/170614; Custom_Duty: 15%; Customs_HS_Code: 85332119; Distributor_name: DIGIKEY; Distributor_part_number: RMCF0402JT100RCT-ND; Height: 0.40MM; Mfr_name: STACKPOLE ELECTRONICS; Mfr_part_number: RMCF0402JT100R; Mistral Part No: 110014060039-R; Package: 0402; Part_type: RESISTORS\FIXED; Project: AEGIS_POM; RoHS: RoHS; Temperature: -55°C+155°C; Tolerance: 5%; Voltage: NA; Wattage: 1/16W; Weight: NA; Datasheet: Y:\MIS_DATABASE\DATASHEETS\RESISTORS\RMCF-SERIES1.PDF
R319 R326 R328 R336 R343 R351 R355 R391 = RESISTOR: RES 4.7K 1/16W 5% 0402; Chkd/date: VASANTHA/190614; Crtd /date: NAVEED/160614; Custom_Duty: 15%; Customs_HS_Code: 85332119; Distributor_name: DIGIKEY; Distributor_part_number: RMCF0402JT4K70CT-ND; Height: 0.40MM; Mfr_name: STACKPOLE ELECTRONICS; Mfr_part_number: RMCF0402JT4K70; Mistral Part No: 110014060028-R; Package: 0402; Part_type: RESISTORS\FIXED; Project: AEGIS_POM; RoHS: RoHS; Temperature: -55°C+155°C; Tolerance: 5%; Voltage: NA; Wattage: 1/16W; Weight: NA; Datasheet: Y:\MIS_DATABASE\DATASHEETS\RESISTORS\RMCF-SERIES1.PDF
R322 R327 R350 R352 R358 R362 R364 R781 = RESISTOR: RES 10E 1/16W 5% 0402; Alternate_mfr_name_A: VISHAY; Alternate_mfr_name_B: PANASONIC-ECG-ECG; Alternate_mfr_name_C: YAGEO AMERICA; Alternate_mfr_part_number_A: CRCW040210R0JNED; Alternate_mfr_part_number_B: ERJ-2GEJ100X; Alternate_mfr_part_number_C: RC0402JR-0710RL; Chkd/date: SHREESHAIL/121205; Crtd /date: MAZHAR/120505; Custom_Duty: 15%; Customs_HS_Code: 85332119; Distributor_name: DIGIKEY; Distributor_name_A: DIGIKEY; Distributor_name_B: DIGIKEY; Distributor_name_C: DIGIKEY; Distributor_part_number: 311-10JCT-ND; Distributor_part_number_A: 541-10JCT-ND; Distributor_part_number_B: P10JTR-ND; Distributor_part_number_C: 311-10JRCT-ND; Height: 0.40MM; Mfr_name: YAGEO AMERICA; Mfr_part_number: 9C04021A10R0JLHF3; Mistral Part No: 110009030193; Package: 0402; Part_type: RESISTORS\FIXED; Project: G4_SVGA; Tolerance: 5%; Wattage: 1/16W; Datasheet: Y:\MIS_DATABASE\DATASHEETS\RESISTORS\YAGEO_RES.PDF
R329 = RESISTOR: RES 22E 1/16W 1% 0402; Alternate_mfr_name_A: VISHAY; Alternate_mfr_part_number_A: CRCW040222R0FKED; Chkd/date: SUHAS/290910; Crtd /date: MAZHAR/090909; Custom_Duty: 15%; Customs_HS_Code: 85332119; Distributor_name: DIGIKEY; Distributor_name_A: DIGIKEY; Distributor_part_number: 311-22.0LRCT-ND; Distributor_part_number_A: 541-22.0LCT-ND; Height: 0.40MM; Mfr_name: YAGEO AMERICA; Mfr_part_number: RC0402FR-0722RL; Mistral Part No: 110009090004-P; Package: 0402; Part_type: RESISTORS\FIXED; Project: VMEFMCD; Remarks: In alternate datasheet it is RoHS COMPLIANT. Y:\MIS_DATABASE\DATASHEETS\RESISTORS\CRCW0402.PDF; RoHS: Pb-Free; Temperature: -55°C+155°C; Tolerance: 1%; Voltage: 50V; Wattage: 1/16W; Weight: 0.8g/1000pcs; Datasheet: Y:\MIS_DATABASE\DATASHEETS\RESISTORS\YAGEO-RC0402.PDF
R342 R511-R514 = RESISTOR: RES 0E 1/16W 1% 0402; Chkd/date: MAZHAR/220709; Crtd /date: USMAN/270109; Custom_Duty: 15%; Customs_HS_Code: 85332119; Distributor_name: NA; Distributor_part_number: NA; Height: 0.40MM; Mfr_name: YAGEO AMERICA; Mfr_part_number: RC0402FR-070RL; Mistral Part No: 110009030085-P; Package: 0402; Part_type: RESISTORS\FIXED; Project: OMAP_EVM; RoHS: Pb-Free; Tolerance: 1%; Wattage: 1/16W; Datasheet: Y:\MIS_DATABASE\DATASHEETS\RESISTORS\CRCW0603.PDF
R349 = RESISTOR: RES 0E 1/10W 5% 0402; Chkd/date: NAVEED/241114; Crtd /date: NAVEED/201014; Custom_Duty: 15%; Customs_HS_Code: 85332119; Distributor_name: DIGIKEY; Distributor_part_number: P0.0JCT-ND; Height: 0.40MM; Mfr_name: PANASONIC-ECG; Mfr_part_number: ERJ-2GE0R00X; Mistral Part No: 110014100008-R; Package: 0402; Part_type: RESISTORS\FIXED; Project: AEGIS POM; RoHS: RoHS; Tolerance: 5%; Wattage: 1/10W; Datasheet: Y:\MIS_DATABASE\DATASHEETS\RESISTORS\ERJ12.PDF
R85 R101 R102 R105 R111 R498 R501 R741 = RESISTOR: RES 10K 1/16W 1% 0402; Alternate_mfr_name_A: AVX CORPORATION; Alternate_mfr_name_B: PANASONIC-ECG-ECG; Alternate_mfr_name_C: YAGEO AMERICA; Alternate_mfr_name_D: VISHAY; Alternate_mfr_part_number_A: CR05-103F-H; Alternate_mfr_part_number_B: ERJ-2RKF1002X; Alternate_mfr_part_number_C: 9C04021A1002FLHF3; Alternate_mfr_part_number_D: CRCW040210K0FKED; Chkd/date: SHREESHAIL/310506; Crtd /date: GEETHA/290506; Custom_Duty: 15%; Customs_HS_Code: 85332119; Distributor_name: DIGIKEY; Distributor_name_A: NA; Distributor_name_B: DIGIKEY; Distributor_name_C: DIGIKEY; Distributor_name_D: DIGIKEY; Distributor_part_number: 311-10.0KLRTR-ND; Distributor_part_number_A: NA; Distributor_part_number_B: P10.0KLCT-ND; Distributor_part_number_C: 311-10.0KLCT-ND; Distributor_part_number_D: 541-10.0KLCT-ND; Height: 0.40MM; Mfr_name: YAGEO AMERICA; Mfr_part_number: RC0402FR-0710KL; Mistral Part No: 110009030220-P; Package: 0402; Part_type: RESISTORS\FIXED; Project: VOCERA; RoHS: Pb-Free; Tolerance: 1%; Wattage: 1/16W; Datasheet: Y:\MIS_DATABASE\DATASHEETS\RESISTORS\YAGEO-RC0402.PDF
R499 R717 R744 = RESISTOR: RES 10K 1/16W 1% 0402; Alternate_mfr_name_A: AVX CORPORATION; Alternate_mfr_name_B: PANASONIC-ECG-ECG; Alternate_mfr_name_C: YAGEO AMERICA; Alternate_mfr_name_D: VISHAY; Alternate_mfr_part_number_A: CR05-103F-H; Alternate_mfr_part_number_B: ERJ-2RKF1002X; Alternate_mfr_part_number_C: 9C04021A1002FLHF3; Alternate_mfr_part_number_D: CRCW040210K0FKED; Chkd/date: SHREESHAIL/310506; Crtd /date: GEETHA/290506; Custom_Duty: 15%; Customs_HS_Code: 85332119; Distributor_name: DIGIKEY; Distributor_name_A: NA; Distributor_name_B: DIGIKEY; Distributor_name_C: DIGIKEY; Distributor_name_D: DIGIKEY; Distributor_part_number: 311-10.0KLRTR-ND; Distributor_part_number_A: NA; Distributor_part_number_B: P10.0KLCT-ND; Distributor_part_number_C: 311-10.0KLCT-ND; Distributor_part_number_D: 541-10.0KLCT-ND; Height: 0.40MM; Loading: DNI; Mfr_name: YAGEO AMERICA; Mfr_part_number: RC0402FR-0710KL; Mistral Part No: 110009030220-P; Package: 0402; Part_type: RESISTORS\FIXED; Project: VOCERA; RoHS: Pb-Free; Tolerance: 1%; Wattage: 1/16W; Datasheet: Y:\MIS_DATABASE\DATASHEETS\RESISTORS\YAGEO-RC0402.PDF
R879 = RESISTOR: RES 1K 1/16W 5% 0402; Alternate_mfr_name_A: AVX CORPORATION; Alternate_mfr_name_C: YAGEO AMERICA; Alternate_mfr_part_number_A: CR05-102J-H; Alternate_mfr_part_number_C: RC0402JR-071KL; Chkd/date: SHREESHAIL/121205; Crtd /date: MAZHAR/230805; Custom_Duty: 15%; Customs_HS_Code: 85332119; Distributor_name: DIGIKEY; Distributor_name_A: NA; Distributor_name_C: DIGIKEY; Distributor_part_number: P1.0KJCT-ND; Distributor_part_number_A: NA; Distributor_part_number_C: 311-1.0KJRCT-ND; Height: 0.40MM; Mfr_name: PANASONIC-ECG; Mfr_part_number: ERJ-2GEJ102X; Mistral Part No: 110009030400-R; Package: 0402; Part_type: RESISTORS\FIXED; Project: HSE; RoHS: RoHS; Tolerance: 5%; Wattage: 1/16W; Datasheet: Y:\MIS_DATABASE\DATASHEETS\RESISTORS\ERJ12.PDF
RA7 RA10 = RESARR_ISO4: RES ARRAY 0E 31mW 0402; Chkd/date: SUHAS/270910; Crtd /date: USMAN/190209; Custom_Duty: 15%; Distributor_name: DIGIKEY; Distributor_part_number: Y10000CT-ND; Height: 0.55MM; Mfr_name: PANASONIC-ECG; Mfr_part_number: EXB-N8VR000X; Mistral Part No: 110009030002-R; Package: 0402; Part_type: RESISTORS\ARRAY; Project: AXON; RoHS: RoHS; Temperature: -55°C+125°C; Voltage: 50V; Wattage: 31mW; Weight: 3g/1000pcs; Datasheet: Y:\MIS_DATABASE\DATASHEETS\RESISTORS\EXB-X.PDF
RA8 RA9 = RESARR_ISO8_0402: RES ARRAY 8 0E 0402; Chkd/date: SHREESHAIL/121205; Crtd /date: MAZHAR/300505; Distributor_name: DIGIKEY; Distributor_part_number: Y1000CT-ND; Height: 0.55MM; Mfr_name: PANASONIC-ECG; Mfr_part_number: EXB-2HVR000V; Mistral Part No: 110009030004-R; Package: 0402; Part_type: RESISTORS\ARRAY; Project: V12SFP; RoHS: RoHS; Datasheet: Y:\MIS_DATABASE\DATASHEETS\RESISTORS\EXB-2HV.PDF
RA17 = RESARR_ISO4: RES ARRAY 10E 62.5mW 5% 0402-4; Chkd/date: MAZHAR/0141010; Crtd /date: BAVISH/092410; Custom_Duty: 15%; Customs_HS_Code: 85332119; Distributor_name: DIGIKEY; Distributor_part_number: CRA4S810DKR-ND; Height: 0.55MM; Loading: DNI; Mfr_name: VISHAY; Mfr_part_number: CRA04S08310R0JTD; Mistral Part No: 110010090048-R; Package: 0402-4; Part_type: RESISTORS\ARRAY; Project: PB BUG BASE; RoHS: RoHS; Temperature: -55°C+155°C; Tolerance: 5%; Wattage: 62.5mW; Weight: NA; Datasheet: Y:\MIS_DATABASE\DATASHEETS\RESISTORS\CRA04S-VISHAY.PDF
RA18 RA19 = RESARR_ISO8_0402: RES ARRAY 8 10E 1/16W 5% 0402; Alternate_mfr_name_A: MOUSER; Alternate_mfr_part_number_A: 667-EXB-2HV100JV; Chkd/date: SUHAS/270910; Crtd /date: USMAN/040908; Custom_Duty: 15%; Distributor_name: DIGIKEY; Distributor_part_number: Y1100CT-ND; Height: 0.55MM; Loading: DNI; Mfr_name: PANASONIC-ECG; Mfr_part_number: EXB-2HV100JV; Mistral Part No: 110009030008-R; Package: 0402; Part_type: RESISTORS\ARRAY; Project: CPB; RoHS: RoHS; Temperature: -55°C+125°C; Tolerance: 5%; Voltage: 25V; Wattage: 1/16W; Weight: 9g/1000pcs; Datasheet: Y:\MIS_DATABASE\DATASHEETS\RESISTORS\EXB-2HV.PDF
U47 = SN74LVC1G04DCKR_SC70-5: IC SINGLE INVERTER GATE SC70-5; Chkd/date: SUHAS/221010; Crtd /date: USMAN/150709; Custom_Duty: 15%; Customs_HS_Code: 85423100; Distributor_name: DIGIKEY; Distributor_part_number: 296-11600-1-ND; Height: 1.10MM; Mfr_name: TEXAS INSTRUMENTS; Mistral Part No: 141009070007-R; Part_type: ICS\DIGITAL\GATES; Project: BUG_BASE-II; RoHS: Sb/ Br FREE; Temperature: -40°C+85°C; Datasheet: Y:\MIS_DATABASE\DATASHEETS\ICS\DIGITAL\GATES\SN74LVC1G04-1.PDF
U66 = SN74AVC2T245RSWR_QFN10: IC DUAL-BIT DUAL SUPPLY BUS TRANSCEIVER QFN10; Chkd/date: SUHAS/031110; Crtd /date: USMAN/130309; Custom_Duty: 15%; Customs_HS_Code: 85423100; Distributor_name: DIGIKEY; Distributor_part_number: 296-23684-1-ND; Height: 0.55MM; Mfr_name: TEXAS INSTRUMENTS; Mistral Part No: 143009030061-R; Package: QFN10; Part_type: ICS\TELECOM\TRANSCEIVER; Project: AXON; RoHS: Sb/ Br FREE; Temperature: -40°C+85°C; Datasheet: Y:\MIS_DATABASE\DATASHEETS\ICS\DIGITAL\BUSTRANSCEIVER\SN74AVC2T245RSWR.PDF
U67 = SN74AVCB164245VR_TVSOP48: IC 16-BIT DUAL-SUPPLY BUS TRANSCEIVER TVSOP48; Chkd/date: SUHAS/031110; Crtd /date: USMAN/300808; Custom_Duty: 15%; Customs_HS_Code: 85423100; Distributor_name: DIGIKEY; Distributor_part_number: 296-15550-2-ND; Height: 1.20MM; Mfr_name: TEXAS INSTRUMENTS; Mistral Part No: 143009030062-R; Package: TVSOP48; Part_type: ICS\TELECOM\TRANSCEIVER; Project: MDC; Remarks: TBD Schematics symbol missing in database; RoHS: Sb/ Br FREE; Temperature: -40°C+85°C; Datasheet: Y:\MIS_DATABASE\DATASHEETS\ICS\DIGITAL\BUSTRANSCEIVER\SN74AVCB1642.PDF
C7 = CAP: CAP CERAMIC 10uF 25V 20% X7R 1210; Chkd/date: SHREESHAIL/200707; Crtd /date: MAZHAR/180707; Custom_Duty: 15%; Customs_HS_Code: 85322990; Distributor_name: DIGIKEY; Distributor_part_number: 445-1434-1-ND; Height: 2.80MM; Mfr_name: TDK CORPORATION; Mfr_part_number: C3225X7R1E106M; Mistral Part No: 120009030191-R; Package: 1210; Part_type: CAPACITORS\CERAMIC; Project: REVA-IBMS; RoHS: RoHS; Tolerance: 20%; Voltage: 25V; Datasheet: Y:\MIS_DATABASE\DATASHEETS\CAPACITORS\TDK_CAP.PDF
C8 C9 = CAP: CAP CERAMIC 10000pF 50V 10% X7R 0402; Chkd/date: NAVEED/241114; Crtd /date: VASANTHA/111114; Custom_Duty: 15%; Customs_HS_Code: 85322990; Distributor_name: DIGIKEY; Distributor_part_number: 311-1349-1-ND; Height: 0.55MM; Mfr_name: YAGEO; Mfr_part_number: CC0402KRX7R9BB103; Mistral Part No: 120014110009-R; Package: 0402; Part_type: CAPACITORS\CERAMIC; Project: GALILEO_EVM; RoHS: RoHS; Temperature: -55°C+125°C; Tolerance: 10%; Voltage: 50V; Wattage: NA; Weight: NA; Datasheet: Y:\MIS_DATABASE\DATASHEETS\CAPACITORS\YACC0603.PDF
C64 C78 = CAP: CAP CERAMIC 1000pF 50V 10% X7R 0402; Alternate_mfr_name_A: MURATA; Alternate_mfr_name_B: YAGEO; Alternate_mfr_name_D: YAGEO AMERICA; Alternate_mfr_part_number_A: GRM155R71H102KA01D; Alternate_mfr_part_number_B: CC0402KRX7R9BB102; Alternate_mfr_part_number_D: 04022R102K9B20D; Chkd/date: SHREESHAIL/280507; Crtd /date: MAZHAR/250706; Custom_Duty: 15%; Customs_HS_Code: 85322990; Distributor_name: NA; Distributor_name_A: DIGIKEY; Distributor_name_B: DIGIKEY; Distributor_name_D: DIGIKEY; Distributor_part_number: NA; Distributor_part_number_A: 490-1303-1-ND; Distributor_part_number_B: 311-1036-1-ND; Distributor_part_number_D: 311-1036-1-ND; Height: 0.63MM; Mfr_name: VENKEL; Mfr_part_number: C0402X7R500-102KNE; Mistral Part No: 120009030154-R; Package: 0402; Part_type: CAPACITORS\CERAMIC; Project: POWERBOX; RoHS: RoHS; Temperature: -55°C+125°C; Tolerance: 10%; Voltage: 50V; Wattage: NA; Weight: NA; Datasheet: Y:\MIS_DATABASE\DATASHEETS\CAPACITORS\C0402.PDF
C417 = CAP: CAP CERAMIC 0.22uF 10V 10% X5R 0402; Chkd/date: MAZHAR/151208; Crtd /date: MAZHAR/170907; Custom_Duty: 15%; Customs_HS_Code: 85322990; Distributor_name: DIGIKEY; Distributor_part_number: 490-3910-1-ND; Height: 0.55MM; Mfr_name: MURATA; Mfr_part_number: GRM155R61A224KE19D; Mistral Part No: 120009030090; Package: 0402; Part_type: CAPACITORS\CERAMIC; Project: SMART VIEW_NVR; Tolerance: 10%; Voltage: 10V; Datasheet: Y:\MIS_DATABASE\DATASHEETS\CAPACITORS\GRM188SERIES.PDF
FB1 = INDUCTOR_FERRITE: IND FERRITE CHIP 300E 500mA 0603; Chkd/date: VASANTHA/190614; Crtd /date: NAVEED/160614; Custom_Duty: 24%; Customs_HS_Code: 85437099; Distributor_name: DIGIKEY; Distributor_part_number: 445-2171-1-ND; Height: 0.75MM; Mfr_name: TDK CORPORATION; Mfr_part_number: MMZ1608R301A; Mistral Part No: 130014060028-R; Package: 0603; Part_type: INDUCTOR; Project: AEGIS_POM; RoHS: RoHS; Temperature: -55°C+125°C; Tolerance: NA; Voltage: NA; Wattage: NA; Weight: NA; Datasheet: Y:\MIS_DATABASE\DATASHEETS\DISCRETES\INDUCTORS\MMZSER.PDF
FB3 = INDUCTOR_FERRITE: IND BEAD CHIP 200E 20% 0603; Chkd/date: MAZHAR/161208; Crtd /date: USMAN/201108; Custom_Duty: 24%; Customs_HS_Code: 85437099; Distributor_name: DIGIKEY; Distributor_part_number: 445-1565-1-ND; Height: 0.95MM; Mfr_name: TDK CORPORATION; Mfr_part_number: MPZ1608S221A; Mistral Part No: 130009030553; Package: 0603; Part_type: INDUCTOR; Project: KHAN_HSST; Tolerance: 20%; Datasheet: Y:\MIS_DATABASE\DATASHEETS\DISCRETES\INDUCTORS\MPZ1608.PDF
FL3 FL5 = FILTER_NFM: PASSIVE FILTER EMI 0.47uF 2A 0603; Chkd/date: SHREESHAIL/040906; Crtd /date: SHREESHAIL/040906; Custom_Duty: 24%; Customs_HS_Code: 85437099; Distributor_name: MOUSER; Distributor_part_number: 81-NFM18PS474R0J3D; Height: 0.70MM; Mfr_name: MURATA; Mfr_part_number: NFM18PS474R0J3; Mistral Part No: 130009030747-R; Package: 0603; Part_type: MISC\FILTER; Project: SVDO_RMB_MMA; RoHS: RoHS; Tolerance: -20%TO +20%; Datasheet: Y:\MIS_DATABASE\DATASHEETS\MISC\FILTER\NFM-SERIES.PDF
J1 = CON_USB__B: CON MINI USB-B TYPE 5POS FEMALE RT TH; Chkd/date: USMAN/030712; Crtd /date: CHAITHANYA/020712; Custom_Duty: 24%; Customs_HS_Code: 85369090; Distributor_name: DIGIKEY; Distributor_part_number: WM17115-ND; Height: 3.95MM; Mfr_name: MOLEX; Mfr_part_number: 548190519; Mistral Part No: 150012070001-R; Package: THRU-HOLE; Part_type: CONNECTOR\USB; Project: IRIS; RoHS: RoHS; Temperature: NA; Tolerance: NA; Voltage: NA; Wattage: NA; Weight: NA; Datasheet: Y:\MIS_DATABASE\DATASHEETS\CONNECTORS\54819-0519.PDF
LD6-LD8 = LED_598-8170-107F: LED ALINGAP GREEN CLEAR 0805 SMD; Chkd/date: BALACHANDAR/160514; Crtd /date: SARANYA/070514; Custom_Duty: 24%; Customs_HS_Code: 85437099; Distributor_name: DIGIKEY; Distributor_part_number: 350-2044-1-ND; Height: 0.70MM; Mfr_name: DIALIGHT; Mistral Part No: 130014050065-R; Package: 0805; Part_type: OPTO\LED; Project: AEGIS GP BETA2; RoHS: RoHS; Temperature: NA; Tolerance: NA; Voltage: NA; Wattage: NA; Weight: NA; Datasheet: Y:\MIS_DATABASE\DATASHEETS\DISCRETES\LEDS\598-SER.PDF
Q6 Q7 = MOSFET_BSS138: IC MOSFET N-CHANNEL 50V 200mA SOT23-3; Chkd/date: SUHAS/191010; Crtd /date: USMAN/240709; Custom_Duty: 15%; Customs_HS_Code: 85423100; Distributor_name: DIGIKEY; Distributor_part_number: BSS138CT-ND; Height: 1.20MM; Mfr_name: DIODES INC; Mfr_part_number: BSS138-7-F; Mistral Part No: 142009070019-R; Package: SOT23-3; Part_type: ICS\POWER\MOSFET; Project: KHAN_MAIN; RoHS: RoHS; Temperature: -55°C+150°C; Voltage: 50V; Wattage: 300mW; Weight: 0.008g; Datasheet: Y:\MIS_DATABASE\DATASHEETS\DISCRETES\TRANSISTORS_FETS\BSS138.PDF
R31-R33 R116 R120 R124 R128 = RESISTOR: RES 470E 1/16W 5% 0402; Alternate_mfr_name_A: AVX CORPORATION; Alternate_mfr_name_C: YAGEO AMERICA; Alternate_mfr_part_number_A: CR05-471J-H; Alternate_mfr_part_number_C: 9C04021A4700JLHF3; Chkd/date: SHREESHAIL/24050; Crtd /date: MAZHAR/260706; Custom_Duty: 15%; Customs_HS_Code: 85332119; Distributor_name: DIGIKEY; Distributor_name_A: NA; Distributor_name_C: DIGIKEY; Distributor_part_number: P470JCT-ND; Distributor_part_number_A: NA; Distributor_part_number_C: 311-470JCT-ND; Height: 0.40MM; Mfr_name: PANASONIC-ECG; Mfr_part_number: ERJ-2GEJ471X; Mistral Part No: 110009030859-R; Package: 0402; Part_type: RESISTORS\FIXED; Project: POWERBOX; RoHS: RoHS; Tolerance: 5%; Wattage: 1/16W; Datasheet: Y:\MIS_DATABASE\DATASHEETS\RESISTORS\ERJ12.PDF
R34 = RESISTOR: RES 0E 1/16W 1% 0402; Chkd/date: MAZHAR/220709; Crtd /date: USMAN/270109; Custom_Duty: 15%; Customs_HS_Code: 85332119; Distributor_name: NA; Distributor_part_number: NA; Height: 0.40MM; Loading: DNI; Mfr_name: YAGEO AMERICA; Mfr_part_number: RC0402FR-070RL; Mistral Part No: 110009030085-P; Package: 0402; Part_type: RESISTORS\FIXED; Project: OMAP_EVM; RoHS: Pb-Free; Tolerance: 1%; Wattage: 1/16W; Datasheet: Y:\MIS_DATABASE\DATASHEETS\RESISTORS\CRCW0603.PDF
R35 = VARISTOR: VARISTOR MULTI ESD 5.5V 30A 0603; Chkd/date: SHREESHAIL/150607; Crtd /date: MAZHAR/150107; Distributor_name: DIGIKEY; Distributor_part_number: F2214CT-ND; Height: 0.90MM; Mfr_name: LITTLE FUSE; Mistral Part No: 110009031207-R; Package: 0603; Part_type: RESISTORS\VARIABLE; Project: OMAP2430_OSK; RoHS: RoHS; Voltage: 5.5V; Datasheet: Y:\MIS_DATABASE\DATASHEETS\RESISTORS\V5.5MLA.PDF
R36 R37 R96 R97 R99 R622 R626 = RESISTOR: RES 2.2K 1/16W 1% 0402; Chkd/date: NAVEED/241114; Crtd /date: VASANTHA/101114; Custom_Duty: 15%; Customs_HS_Code: 85332119; Distributor_name: DIGIKEY; Distributor_part_number: 311-2.20KLRCT-ND; Height: 0.40MM; Mfr_name: YAGEO AMERICA; Mfr_part_number: RC0402FR-072K2L; Mistral Part No: 110014110004-R; Package: 0402; Part_type: RESISTORS\FIXED; Project: GALILEO_EVM; RoHS: RoHS; Temperature: -55°C+155°C; Tolerance: 1%; Voltage: NA; Wattage: 1/16W; Weight: NA; Datasheet: Y:\MIS_DATABASE\DATASHEETS\RESISTORS\RC0402FR.PDF
R98 R621 R623 R624 = RESISTOR: RES 2.2K 1/16W 1% 0402; Chkd/date: NAVEED/241114; Crtd /date: VASANTHA/101114; Custom_Duty: 15%; Customs_HS_Code: 85332119; Distributor_name: DIGIKEY; Distributor_part_number: 311-2.20KLRCT-ND; Height: 0.40MM; Loading: DNI; Mfr_name: YAGEO AMERICA; Mfr_part_number: RC0402FR-072K2L; Mistral Part No: 110014110004-R; Package: 0402; Part_type: RESISTORS\FIXED; Project: GALILEO_EVM; RoHS: RoHS; Temperature: -55°C+155°C; Tolerance: 1%; Voltage: NA; Wattage: 1/16W; Weight: NA; Datasheet: Y:\MIS_DATABASE\DATASHEETS\RESISTORS\RC0402FR.PDF
R127 R130 R136 R173 = RESISTOR: RES 47E 1/16W 1% 0402; Chkd/date: VASANTHA/190614; Crtd /date: NAVEED/160614; Custom_Duty: 15%; Customs_HS_Code: 85332119; Distributor_name: DIGIKEY; Distributor_part_number: RMCF0402FT47R0CT-ND; Height: 0.40MM; Mfr_name: STACKPOLE ELECTRONICS; Mfr_part_number: RMCF0402FT47R0; Mistral Part No: 110014060027-R; Package: 0402; Part_type: RESISTORS\FIXED; Project: AEGIS_POM; RoHS: RoHS; Temperature: -55°C+155°C; Tolerance: 1%; Voltage: NA; Wattage: 1/16W; Weight: NA; Datasheet: Y:\MIS_DATABASE\DATASHEETS\RESISTORS\RMCF-SERIES1.PDF
R158 = RESISTOR: RES 1.5K 1/16W 5% 0402; Chkd/date: VASANTHA/200614; Crtd /date: NAVEED/170614; Custom_Duty: 15%; Customs_HS_Code: 85332119; Distributor_name: DIGIKEY; Distributor_part_number: RMCF0402JT1K50CT-ND; Height: 0.40MM; Loading: DNI; Mfr_name: STACKPOLE ELECTRONICS; Mfr_part_number: RMCF0402JT1K50C; Mistral Part No: 110014060038-R; Package: 0402; Part_type: RESISTORS\FIXED; Project: AEGIS_POM; RoHS: RoHS; Temperature: -55°C+155°C; Tolerance: 5%; Voltage: NA; Wattage: 1/16W; Weight: NA; Datasheet: Y:\MIS_DATABASE\DATASHEETS\RESISTORS\RMCF-SERIES1.PDF
R597 = RESISTOR: RES 150K 1/16W 1% 0402; Alternate_mfr_name_A: YAGEO AMERICA; Alternate_mfr_name_D: ROHM; Alternate_mfr_part_number_A: RC0402FR-07150KL; Alternate_mfr_part_number_D: MCR01MZPF1503; Chkd/date: SHREESHAIL/200906; Crtd /date: MAZHAR/190906; Custom_Duty: 15%; Customs_HS_Code: 85332119; Distributor_name: DIGIKEY; Distributor_name_A: DIGIKEY; Distributor_name_D: DIGIKEY; Distributor_part_number: P150KLCT-ND; Distributor_part_number_A: 311-150KLRCT-ND; Distributor_part_number_D: RHM150KLCT-ND; Height: 0.40MM; Mfr_name: PANASONIC-ECG; Mfr_part_number: ERJ-2RKF1503X; Mistral Part No: 110009030336-R; Package: 0402; Part_type: RESISTORS\FIXED; Project: SM2_AFE; RoHS: RoHS; Tolerance: 1%; Wattage: 1/16W; Datasheet: Y:\MIS_DATABASE\DATASHEETS\RESISTORS\PAN_ERJ.PDF
R880 = RESISTOR: RES 1.5K 1/16W 5% 0402; Chkd/date: VASANTHA/200614; Crtd /date: NAVEED/170614; Custom_Duty: 15%; Customs_HS_Code: 85332119; Distributor_name: DIGIKEY; Distributor_part_number: RMCF0402JT1K50CT-ND; Height: 0.40MM; Mfr_name: STACKPOLE ELECTRONICS; Mfr_part_number: RMCF0402JT1K50C; Mistral Part No: 110014060038-R; Package: 0402; Part_type: RESISTORS\FIXED; Project: AEGIS_POM; RoHS: RoHS; Temperature: -55°C+155°C; Tolerance: 5%; Voltage: NA; Wattage: 1/16W; Weight: NA; Datasheet: Y:\MIS_DATABASE\DATASHEETS\RESISTORS\RMCF-SERIES1.PDF
TP43 TP45 TP47-TP50 TP177 TP178 = TESTPOINT: TESTPOINT 40 SMD; Chkd/date: MAZHAR/190505; Crtd /date: MAZHAR/190505; Distributor_name: NA; Distributor_part_number: NA; Height: NA; Mfr_name: LOCAL; Mistral Part No: 130009030933; Part_type: MISC\TESTPOINT; Project: RAINIER-3
U3 = TPD4S012DRY_SON6: IC 4CH ESD SOLUTION SON6; Chkd/date: Vinitha/291211; Crtd /date: BAVISH/190811; Custom_Duty: 15%; Customs_HS_Code: 85423100; Distributor_name: DIGIKEY; Distributor_part_number: 296-24244-1-ND; Height: 0.60MM; Mfr_name: TEXAS INSTRUMENTS; Mistral Part No: 141011080022; Package: SON6; Part_type: ICS\INTERFACE; Project: ACRO_DM3730; RoHS: NA; Temperature: -40°C+85°C; Tolerance: NA; Voltage: NA; Wattage: NA; Weight: NA; Datasheet: Y:\MIS_DATABASE\DATASHEETS\ICS\INTERFACE\TPD4S012.PDF
U11 = IS25CD010-JNLE_SOIC8: IC FLASH 1MBIT 100MHZ SOIC8; Chkd/date: USMAN/021214; Crtd /date: VASANTHA/111114; Distributor_name: DIGIKEY; Distributor_part_number: 706-1199-ND; Height: 1.75MM; Mfr_name: ISSI; Mistral Part No: 141114110004-R; Part_type: ICS\DIGITAL\MEMORY; Project: GALILEO_EVM; Temperature: -40°C+105°C; Tolerance: NA; Voltage: NA; Wattage: NA; Weight: NA; Datasheet: Y:\MIS_DATABASE\DATASHEETS\ICS\MEMORY\IS25CD0.PDF
U17 = AM1802BZWTD3_BGA361: IC PROCESSOR SITARA ARM 300MHZ BGA361; Chkd/date: NAVEED/141114; Color: Default; Crtd /date: VASANTHA/121014; Custom_Duty: 15%; Customs_HS_Code: 85423100; Distributor_name: MOUSER; Distributor_part_number: 595-AM1802BZWTD3; Height: 1.30MM; Location X-Coordinate: 0; Location Y-Coordinate: 0; Mfr_name: TEXAS INSTRUMENTS; Mistral Part No: 141214100001-R; Package: BGA361; Part_type: ICS\DIGITAL\MICROPROCESSOR; Power Pins Visible: False; Primitive: DEFAULT; Project: GALILEO_EVM; RoHS: RoHS; SPLIT_INST: TRUE; Temperature: -40°C+90°C; Tolerance: NA; Voltage: NA; Wattage: NA; Weight: NA; Datasheet: Y:\MIS_DATABASE\DATASHEETS\ICS\DIGITAL\MICROCONTROLLER\AM1802.PDF

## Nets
DGND: C7.2 C8.2 C9.2 C30.1 C64.2 C66.2 C73.2 C78.2 C168.2 C279.1 C280.2 C287.1 C408.1 C412.2 C413.2 C415.1 C417.2 C420.2 C532.2 C648.1 C649.1 C650.1 C653.1 C654.1 FB1.1 FL3.2(GND) FL5.2(GND) J1.5(GND) J19.16 J19.57 LD6.1 Q6.2(S) Q7.2(S) R34.1 R35.1 R36.2 R37.2 R96.2 R97.2 R98.2 R99.2 R319.1 R342.1 R349.1 R499.1 R597.2 R626.2 R717.1 R744.1 U11.4(GND) U47.3(GND) U66.3(GND) U67.4(GND) U67.10(GND) U67.15(GND) U67.21(GND) U67.28(GND) U67.34(GND) U67.39(GND) U67.45(GND) ; also on sheet 1 11 12 13 14 15 16 17 18 19 20 21 22 23 24 25 26 27 28 29 30 31 32 33 34 35 36 37 40 41 42 43 44 45 46 47 48 49 50
GND_MIPI: J19.61 J19.62 J19.63 J19.64 R349.2
GND_USB_XDS: FB1.2 J1.6(SH1) J1.7(SH2) U3.4(GND)
VCC1V2_XDS_CVDD: C420.1 U17.M12(USB_CVDD) ; also on sheet 42
VCC1V8_XDS_DVDD18: FL5.1(INPUT) ; also on sheet 42
VCC3V3_BMC: C279.2 C287.2 C653.2 C654.2 R498.2 R501.2 R741.2 U66.7(VCCA) U67.31(VCCA) U67.42(VCCA) ; also on sheet 13 28 29 37 45 46 47 50
VCC3V3_DCIN: C280.1 C532.1 C648.2 C649.2 C650.2 FB14.1 U47.5(VCC) U66.6(VCCB) U67.7(VCCB) U67.18(VCCB) ; also on sheet 11 17 18 19 20 21 22 23 24 25 26 27 28 29 30 31 32 33 34 35 36 37 43 44 45 46 47 48 50
VCC3V3_MIPI: FB14.2 R317.2 R326.1 R328.1 R336.1 R343.1 R351.1 R355.1 R391.2 R879.1 ; also on sheet 43
VCC3V3_R: J19.1 R317.1
VCC3V3_XDS: C30.2 R31.2 R32.2 R33.2 R85.1 R101.1 R102.2 R105.1 R111.1 R158.2 R621.1 R622.1 R623.1 R624.1 U11.8(VCC) ; also on sheet 40 41 42 43 44
VCC3V3_XDS_DVDD33: FL3.1(INPUT) ; also on sheet 42
VCC_VBUS_XDS: C7.1 C9.1 FB3.2 ; also on sheet 44
BMC_BOOTMODE0: U67.43(1A4) ; also on sheet 45
BMC_BOOTMODE1: U67.40(1A6) ; also on sheet 45
BMC_BOOTMODE2: U67.44(1A3) ; also on sheet 45
BMC_BOOTMODE3: U67.47(1A1) ; also on sheet 45
BMC_BOOTMODE4: U67.37(1A8) ; also on sheet 45
BMC_BOOTMODE5: U67.46(1A2) ; also on sheet 45
BMC_BOOTMODE6: U67.38(1A7) ; also on sheet 45
BMC_BOOTMODE7: U67.41(1A5) ; also on sheet 45
BMC_BOOTMODE8: U67.33(2A3) ; also on sheet 45
BMC_BOOTMODE9: U67.30(2A5) ; also on sheet 45
BMC_BOOTMODE10: U67.35(2A2) ; also on sheet 45
BMC_BOOTMODE11: U67.36(2A1) ; also on sheet 45
BMC_BOOTMODE12: U67.29(2A6) ; also on sheet 45
BMC_BOOTMODE13: U67.32(2A4) ; also on sheet 45
BMC_BOOTMODE14: U67.27(2A7) ; also on sheet 45
BMC_BOOTMODE15: U67.26(2A8) ; also on sheet 45
BOOTMODEON: R501.1 R744.2 U66.2(~{OE}) U67.25(2~{OE}) U67.48(1~{OE}) ; also on sheet 46
BUFF_DSS_DE: R512.1 ; also on sheet 20
BUFF_DSSDATA0: RA10.8 ; also on sheet 20
BUFF_DSSDATA1: RA10.7 ; also on sheet 20
BUFF_DSSDATA2: RA10.6 ; also on sheet 20
BUFF_DSSDATA3: RA10.5 ; also on sheet 20
BUFF_DSSDATA4: RA7.8 ; also on sheet 20
BUFF_DSSDATA5: RA7.7 ; also on sheet 20
BUFF_DSSDATA6: RA7.6 ; also on sheet 20
BUFF_DSSDATA7: RA7.5 ; also on sheet 20
BUFF_DSSDATA8: RA9.16 ; also on sheet 20
BUFF_DSSDATA9: RA9.15 ; also on sheet 20
BUFF_DSSDATA10: RA9.12 ; also on sheet 20
BUFF_DSSDATA11: RA9.14 ; also on sheet 20
BUFF_DSSDATA12: RA9.9 ; also on sheet 20
BUFF_DSSDATA13: RA9.10 ; also on sheet 20
BUFF_DSSDATA14: RA9.13 ; also on sheet 20
BUFF_DSSDATA15: RA9.11 ; also on sheet 20
BUFF_DSSDATA16: RA8.13 ; also on sheet 20
BUFF_DSSDATA17: RA8.15 ; also on sheet 20
BUFF_DSSDATA18: RA8.10 ; also on sheet 20
BUFF_DSSDATA19: RA8.16 ; also on sheet 20
BUFF_DSSDATA20: RA8.9 ; also on sheet 20
BUFF_DSSDATA21: RA8.11 ; also on sheet 20
BUFF_DSSDATA22: RA8.14 ; also on sheet 20
BUFF_DSSDATA23: RA8.12 ; also on sheet 20
BUFF_DSSHSYNC: R514.1 ; also on sheet 20
BUFF_DSSPCLK: R513.1 ; also on sheet 20
BUFF_DSSVSYNC: R511.1 ; also on sheet 20
CPLD_RXD1: U17.E18(~{SPI1_SCS}[3~{]}/UART1_RXD/GP1[1]) ; also on sheet 43
CPLD_TXD1: U17.F19(~{SPI1_SCS}[2~{]}/UART1_TXD/GP1[0]) ; also on sheet 43
DIR: R499.2 R741.1 U67.1(1DIR) U67.24(2DIR)
EMULED1: Q6.1(G) R36.1 ; also on sheet 40
EMULED2: Q7.1(G) R37.1 ; also on sheet 40
MIPI_EMU02: J19.13 RA18.13
MIPI_EMU03: J19.17 RA18.11
MIPI_EMU04: J19.23 RA18.14
MIPI_EMU05: J19.25 RA18.16
MIPI_EMU06: J19.27 RA18.9
MIPI_EMU07: J19.29 RA18.15
MIPI_EMU08: J19.31 RA18.10
MIPI_EMU09: J19.33 RA18.12
MIPI_EMU10: J19.35 RA19.14
MIPI_EMU11: J19.37 RA19.12
MIPI_EMU12: J19.39 RA19.15
MIPI_EMU13: J19.41 RA19.16
MIPI_EMU14: J19.43 RA19.11
MIPI_EMU15: J19.45 RA19.13
MIPI_EMU16: J19.47 RA19.10
MIPI_EMU17: J19.49 RA19.9
MIPI_EMU18: J19.51 RA17.8
MIPI_EMU19: J19.53 RA17.7
MIPI_EMU_RTCK: J19.7 R329.1
MIPI_RTCK: R329.2 ; also on sheet 43
MIPI_TCK: R314.1 R322.2 R326.2 ; also on sheet 43
MIPI_TCK_R: J19.3 R322.1
MIPI_TDI: R327.2 ; also on sheet 43
MIPI_TDI_R: J19.5 R327.1
MIPI_TDO: R362.1 ; also on sheet 44
MIPI_TDO_R: J19.4 R362.2
MIPI_TMS: R358.1 ; also on sheet 43
MIPI_TMS_R: J19.2 R358.2
MIPI_TRGRSTZ: R781.1 ; also on sheet 43
MIPI_TRST#: R364.1 ; also on sheet 43
MIPI_TRST#_R: J19.8 R364.2
SEL_XDS: U47.4(Y) ; also on sheet 43 44
SEL_XDS200_INV: J19.58 R391.1 R717.2 U47.2(A) ; also on sheet 43
SOC_ARM_BENDIAN: U66.9(A2) ; also on sheet 46
SOC_ARM_LENDIAN: U66.8(A1) ; also on sheet 46
SOC_DSS_DE: R512.2 ; also on sheet 21
SOC_DSSDATA0: RA10.1 ; also on sheet 21
SOC_DSSDATA1: RA10.2 ; also on sheet 21
SOC_DSSDATA2: RA10.3 ; also on sheet 21
SOC_DSSDATA3: RA10.4 U66.4(B2) ; also on sheet 21
SOC_DSSDATA4: RA7.1 ; also on sheet 21
SOC_DSSDATA5: RA7.2 U66.5(B1) ; also on sheet 21
SOC_DSSDATA6: RA7.3 RA17.2 ; also on sheet 21
SOC_DSSDATA7: RA7.4 RA17.1 ; also on sheet 21
SOC_DSSDATA8: RA9.1 RA19.8 U67.23(2B8) ; also on sheet 21
SOC_DSSDATA9: RA9.2 RA19.7 U67.22(2B7) ; also on sheet 21
SOC_DSSDATA10: RA9.5 RA19.4 U67.17(2B4) ; also on sheet 21
SOC_DSSDATA11: RA9.3 RA19.6 U67.20(2B6) ; also on sheet 21
SOC_DSSDATA12: RA9.8 RA19.1 U67.13(2B1) ; also on sheet 21
SOC_DSSDATA13: RA9.7 RA19.2 U67.14(2B2) ; also on sheet 21
SOC_DSSDATA14: RA9.4 RA19.5 U67.19(2B5) ; also on sheet 21
SOC_DSSDATA15: RA9.6 RA19.3 U67.16(2B3) ; also on sheet 21
SOC_DSSDATA16: RA8.4 RA18.5 U67.8(1B5) ; also on sheet 21
SOC_DSSDATA17: RA8.2 RA18.7 U67.11(1B7) ; also on sheet 21
SOC_DSSDATA18: RA8.7 RA18.2 U67.3(1B2) ; also on sheet 21
SOC_DSSDATA19: RA8.1 RA18.8 U67.12(1B8) ; also on sheet 21
SOC_DSSDATA20: RA8.8 RA18.1 U67.2(1B1) ; also on sheet 21
SOC_DSSDATA21: RA8.6 RA18.3 U67.5(1B3) ; also on sheet 21
SOC_DSSDATA22: RA8.3 RA18.6 U67.9(1B6) ; also on sheet 21
SOC_DSSDATA23: RA8.5 RA18.4 U67.6(1B4) ; also on sheet 21
SOC_DSSHSYNC: R514.2 ; also on sheet 21
SOC_DSSPCLK: R513.2 ; also on sheet 21
SOC_DSSVSYNC: R511.2 ; also on sheet 21
SOC_EMU00: J19.19 R350.2 R351.2 ; also on sheet 44
SOC_EMU01: J19.21 R352.2 R355.2 ; also on sheet 44
SOC_TCK: U1.L3(TCK) ; also on sheet 44
SOC_TDI: R336.2 U1.L5(TDI) ; also on sheet 44
SOC_TDO: R328.2 U1.K5(TDO) ; also on sheet 44
SOC_TMS: R343.2 U1.K4(TMS) ; also on sheet 44
SOC_TRST#: R319.2 U1.L4(TRSTn) ; also on sheet 44
USB0_VDDA12: C417.1 U17.N17(USB0_VDDA12)
USB0_VDDA18: C73.1 C78.1 C413.1 C415.2 FL5.3(OUTPUT) U17.N14(USB0_VDDA18)
USB0_VDDA33: C64.1 C66.1 C408.2 C412.1 FL3.3(OUTPUT) U17.N18(USB0_VDDA33)
VER0: R97.1 R623.2 U17.C4(AXR[12]/GP0[4])
VER1: R96.1 R624.2 U17.B3(AXR[13]/GP0[5])
VER2: R98.1 R622.2 U17.B4(AXR[14]/GP0[6])
VER3: R99.1 R621.2 U17.A4(AXR[15]/GP0[7])
XDS200_SPI1_CLK: R105.2 R136.2 U11.6(SCK)
XDS200_SPI1_SCS[0]: R101.2 U11.1(~{CE}) U17.E19(~{SPI1_SCS}[0~{]}/GP2[14]/TM64P3_IN12)
XDS200_SPI1_SIMO: R111.2 U11.5(SIO) U17.G17(SPI1_SIMO/GP2[10])
XDS200_SPI1_SOMI: R102.1 U11.2(SO) U17.H17(SPI1_SOMI/GP2[11])
XDS200_SPI1_WPn: R626.1 U11.3(~{WP}) U17.F18(~{SPI1_SCS}[1~{]}/GP2[15]/TM64P2_IN12)
XDS200_SPI_HOLDn: R85.2 U11.7(~{HOLD})
XDS_USB_DM: J1.2(D-) U3.2(D-) U17.M18(USB0_DM)
XDS_USB_DP: J1.3(D+) U3.1(D+) U17.M19(USB0_DP)
XDS_VBUS: C8.1 FB3.1 J1.1(VBUS) R35.2 R597.1 R880.2 U3.6(VBUS)
N17119674: J1.4(ID) R34.2
N17150258: J19.12 R879.2
N17193198: LD7.2 R32.1
N17193212: LD8.1 Q7.3(D)
N17193213: LD7.1 Q6.3(D)
N17193222: LD6.2 R31.1
N17217348: J19.6 R781.2
N17217726: C168.1 R314.2
N17219428: J19.15 R342.2
N17224206: LD8.2 R33.1
N17253655: R116.2 TP43.1(TP)
N17253657: R116.1 U17.C5(AXR[11]/GP0[3])
N17253714: R128.2 TP49.1(TP)
N17253716: R128.1 U17.E4(AXR[8]/GP0[0])
N17253732: R120.1 U17.C3(AXR9/GP0[1])
N17253734: R120.2 TP45.1(TP)
N17253750: R124.1 U17.D4(AXR[10]/GP0[2])
N17253752: R124.2 TP47.1(TP)
N17255053: R127.1 U17.F16(~{SPI1_SCS}[4~{]}/UART2_TXD/GP1[2])
N17255055: R127.2 TP48.1(TP)
N17255071: R130.1 U17.F17(~{SPI1_SCS}[5~{]}/UART2_RXD/GP1[3])
N17255073: R130.2 TP50.1(TP)
N17255146: R136.1 U17.G19(SPI1_CLK/GP2[13])
N17255876: R158.1 U17.P16(USB0_ID)
N18168142: R498.1 U66.1(DIR2) U66.10(DIR1)
N21997071: R173.1 U17.F4(RTC_ALARM/~{UART2_CTS}/GP0[8]/~{DEEPSLEEP})
N21997073: R173.2 TP177.1(TP)
N22024660: TP178.1(TP) U17.K18(USB0_DRVVBUS)
N23851798: R352.1 U1.L22(EMU01)
N23851802: R350.1 U1.M22(EMU00)
N24769033: R880.1 U17.N19(USB0_VBUS)

Not connected (* = marked no-connect by the designer): J19 9* 10* 11* 14* 18* 20* 22* 24* 26* 28* 30* 32* 34* 36* 38* 40* 42* 44* 46* 48* 50* 52* 54* 55* 56* 59* 60*; RA17 3* 4* 5* 6*; U3 3(ID)* 5(NC)*; U17 A1(ACLKR/GP0[15])* A2(AHCLKR/~{UART1_RTS}/GP0[11])* A3(AHCLKX/USB_REFCLKIN/~{UART1_CTS}/GP0[10])* B1(ACLKX/GP0[14])* B2(AFSX/GP0[12])* C1(AXR[6]/GP1[14]/MII_TXEN)* C2(AFSR/GP0[13])* C16(SPI0_SOMI/GP8[6]/MII_RXER)* C17(SPI0_ENA/MII_RXDV)* C18(SPI0_SIMO/GP8[5]/MII_CRS)* C19(~{SPI0_SCS}[5~{]}/UART0_RXD/GP8[4]/MII_RXD[3])* D1(AXR[4]/GP1[12]/MII_COL)* D2(AXR[7]/GP1[15])* D3(AXR[5]/GP1[13]/MII_TXCLK)* D5(AMUTE/~{UART2_RTS}/GP0[9])* D16(~{SPI0_SCS}[2~{]}/~{UART0_RTS}/GP8[1]/MII_RXD[0])* D17(~{SPI0_SCS}[0~{]}/TM64P1_OUT12/GP1[6]/MDIO_D/TM64P1_IN12)* D18(~{SPI0_SCS}[4~{]}/UART0_TXD/GP8[3]/MII_RXD[2])* D19(SPI0_CLK/GP1[8]/MII_RXCLK)* E1(AXR[1]/GP1[9]/MII_TXD[1])* E2(AXR[2]/GP1[10]/MII_TXD[2])* E3(AXR[3]/GP1[11]/MII_TXD[3])* E16(~{SPI0_SCS}[1~{]}/TM64P0_OUT12/GP1[7]/MD_CLK/TM64P0_IN12)* E17(~{SPI0_SCS}[3~{]}/~{UART0_CTS}/GP8[2]/MII_RXD[1])* F3(AXR[0]/GP8[7]/MII_TXD[0])* G16(~{SPI1_SCS}[7~{]}/I2C0_SCL/TM64P2_OUT12/GP1[5])* G18(~{SPI1_SCS}[6~{]}/I2C0_SDA/TM64P3_OUT12/GP1[4])* H16(~{SPI1_ENA}/GP2[12])*; U47 1(NC)*

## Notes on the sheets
sheet 38
- MIPI 60
- Res MUX between Display and JTAG TRACE Functionality
  -For display, install RA7, RA8 & RA9 . DNI RA17,RA18 & RA19
  -For TRACE, install RA17, RA18 & RA19. DNI RA7, RA8 & RA9
- SoC JTAG
- BOOTMODE
sheet 39
- VERSION SELECTION
- Note: Version Code default value is changed to 0100 as per TI recommendation
- XDS200
- GREEN
- 90 ohm differential pairs
- GREEN
- GREEN
- Differential Pair
- MINI USB CONN
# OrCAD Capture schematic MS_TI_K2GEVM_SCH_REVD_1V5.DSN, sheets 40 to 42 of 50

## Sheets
40 39. JTAG_XDS200_2: size C; title: JTAG_XDS200_2
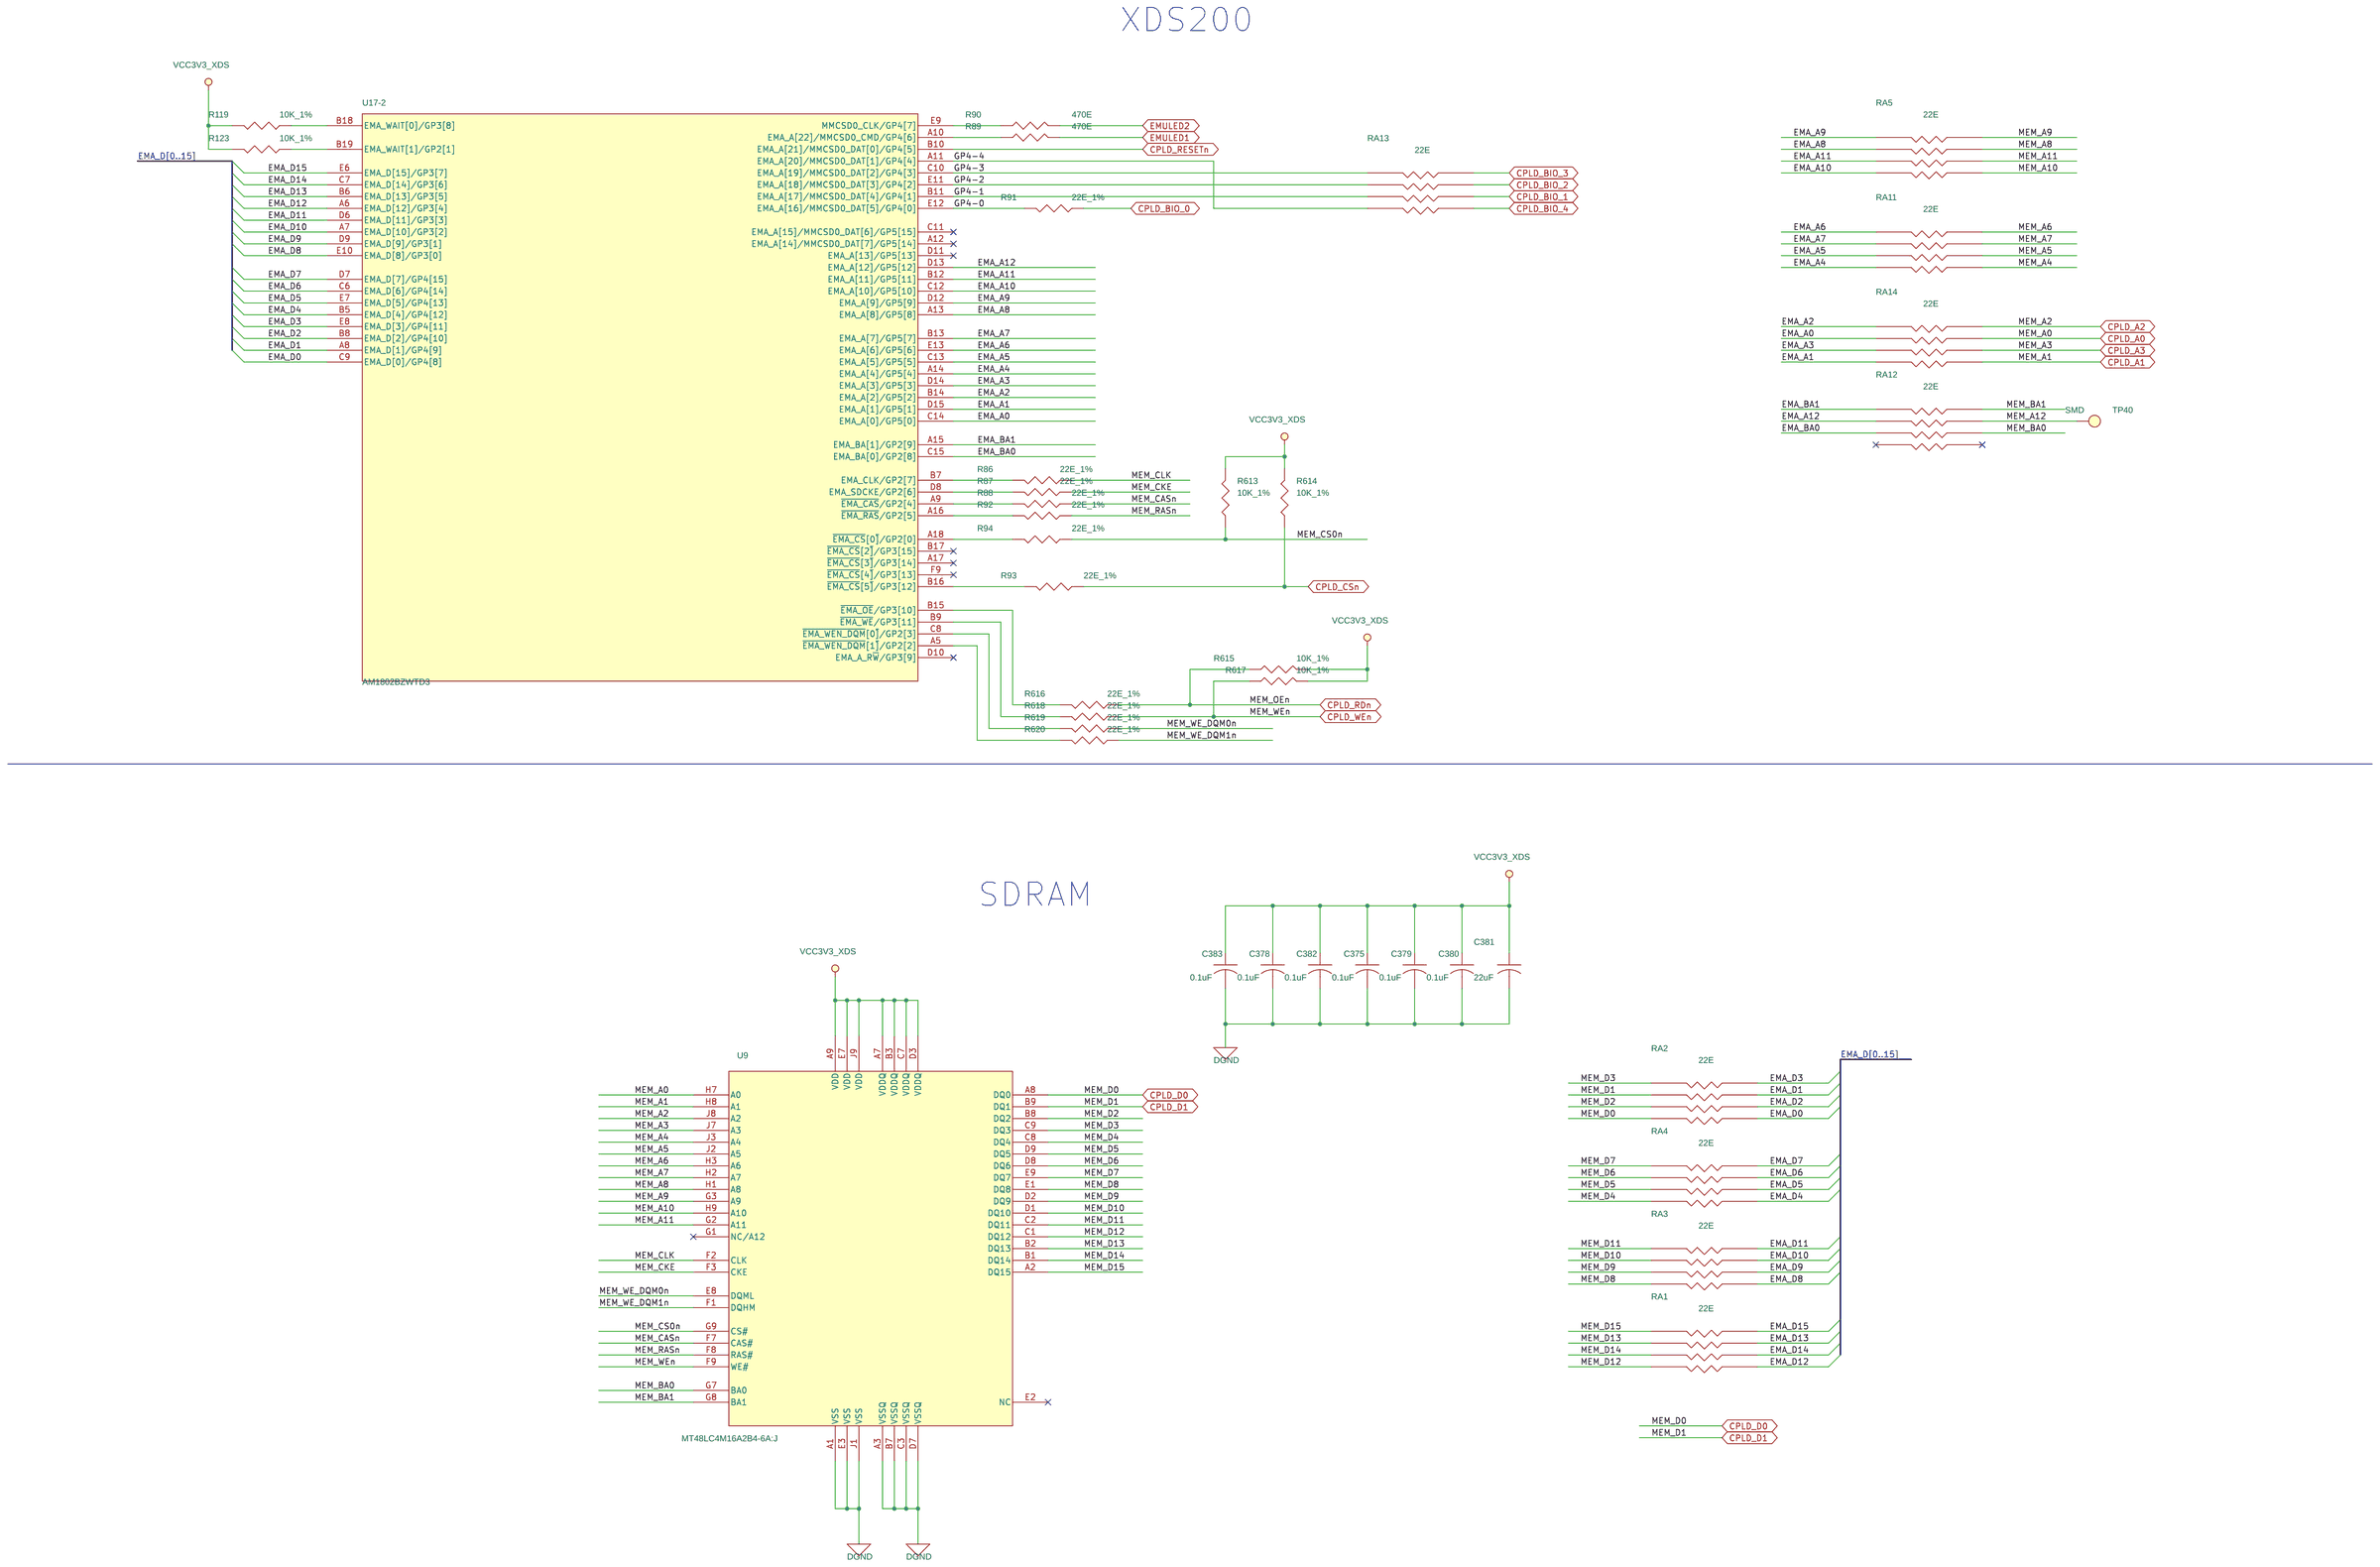
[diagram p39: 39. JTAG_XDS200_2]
41 40. JTAG_XDS200_3: size C; title: JTAG_XDS200_3
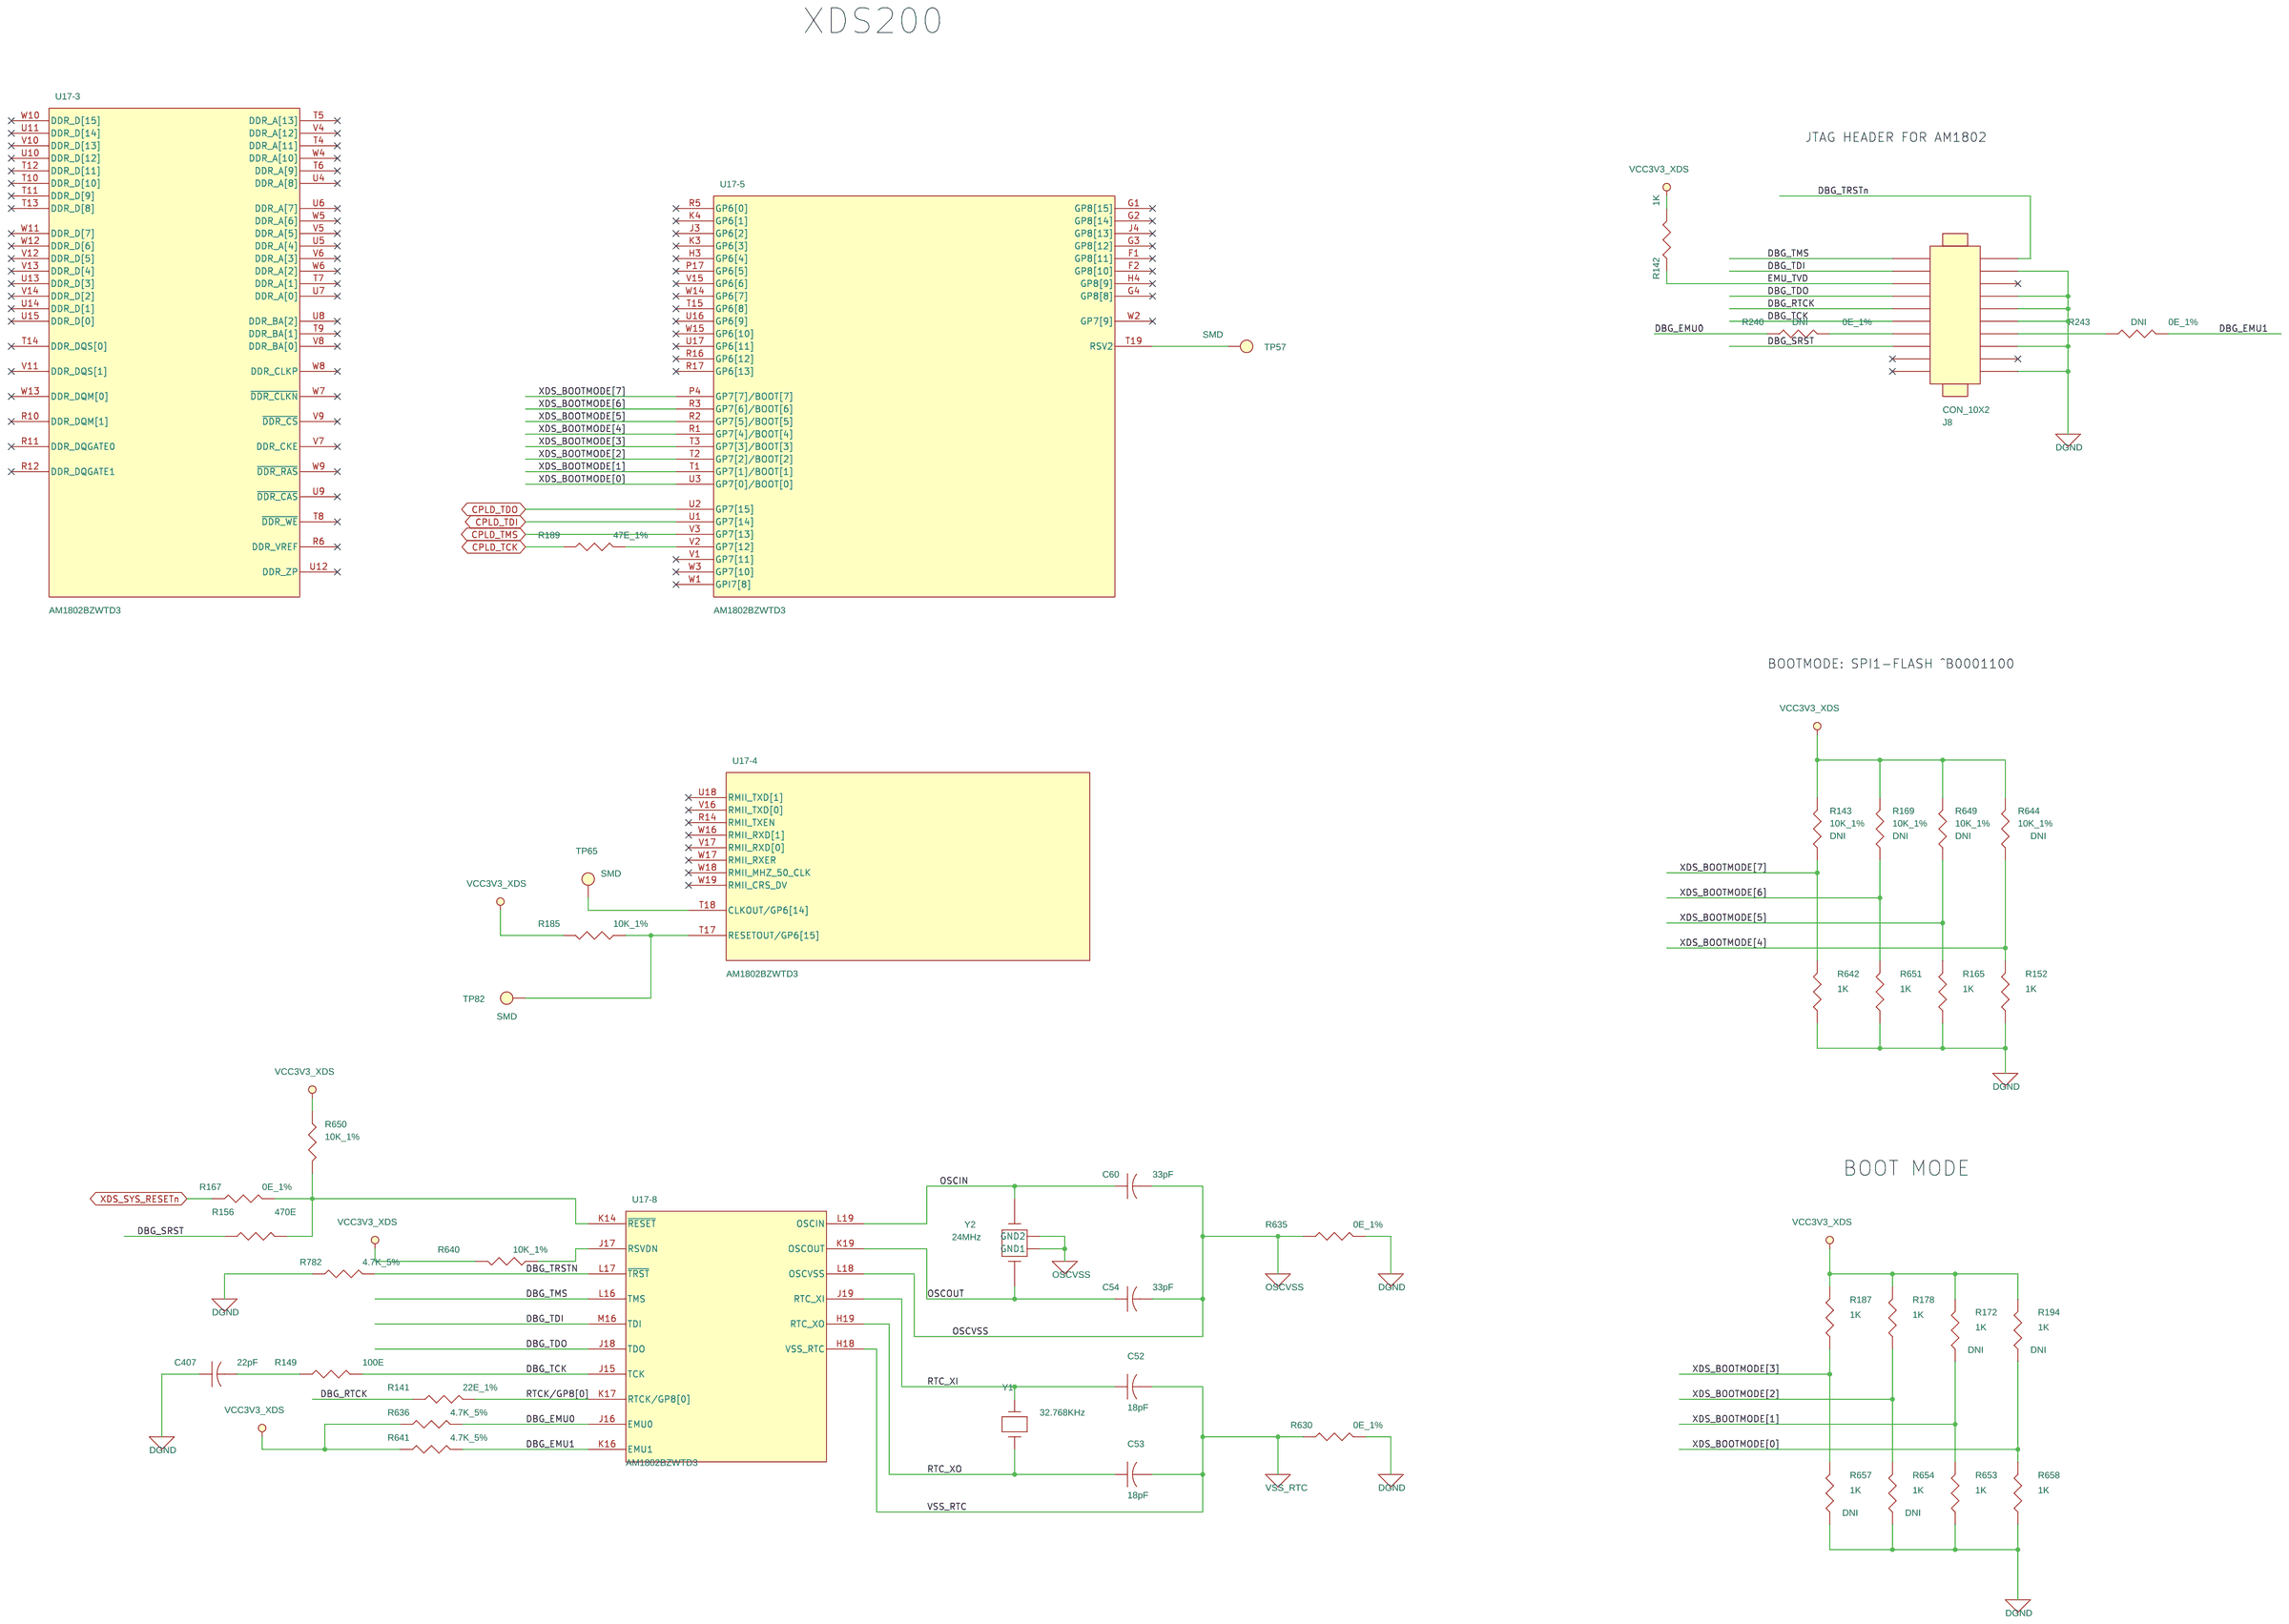
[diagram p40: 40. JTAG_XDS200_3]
42 41. JTAG_XDS200_4: size C; title: JTAG_XDS200_4

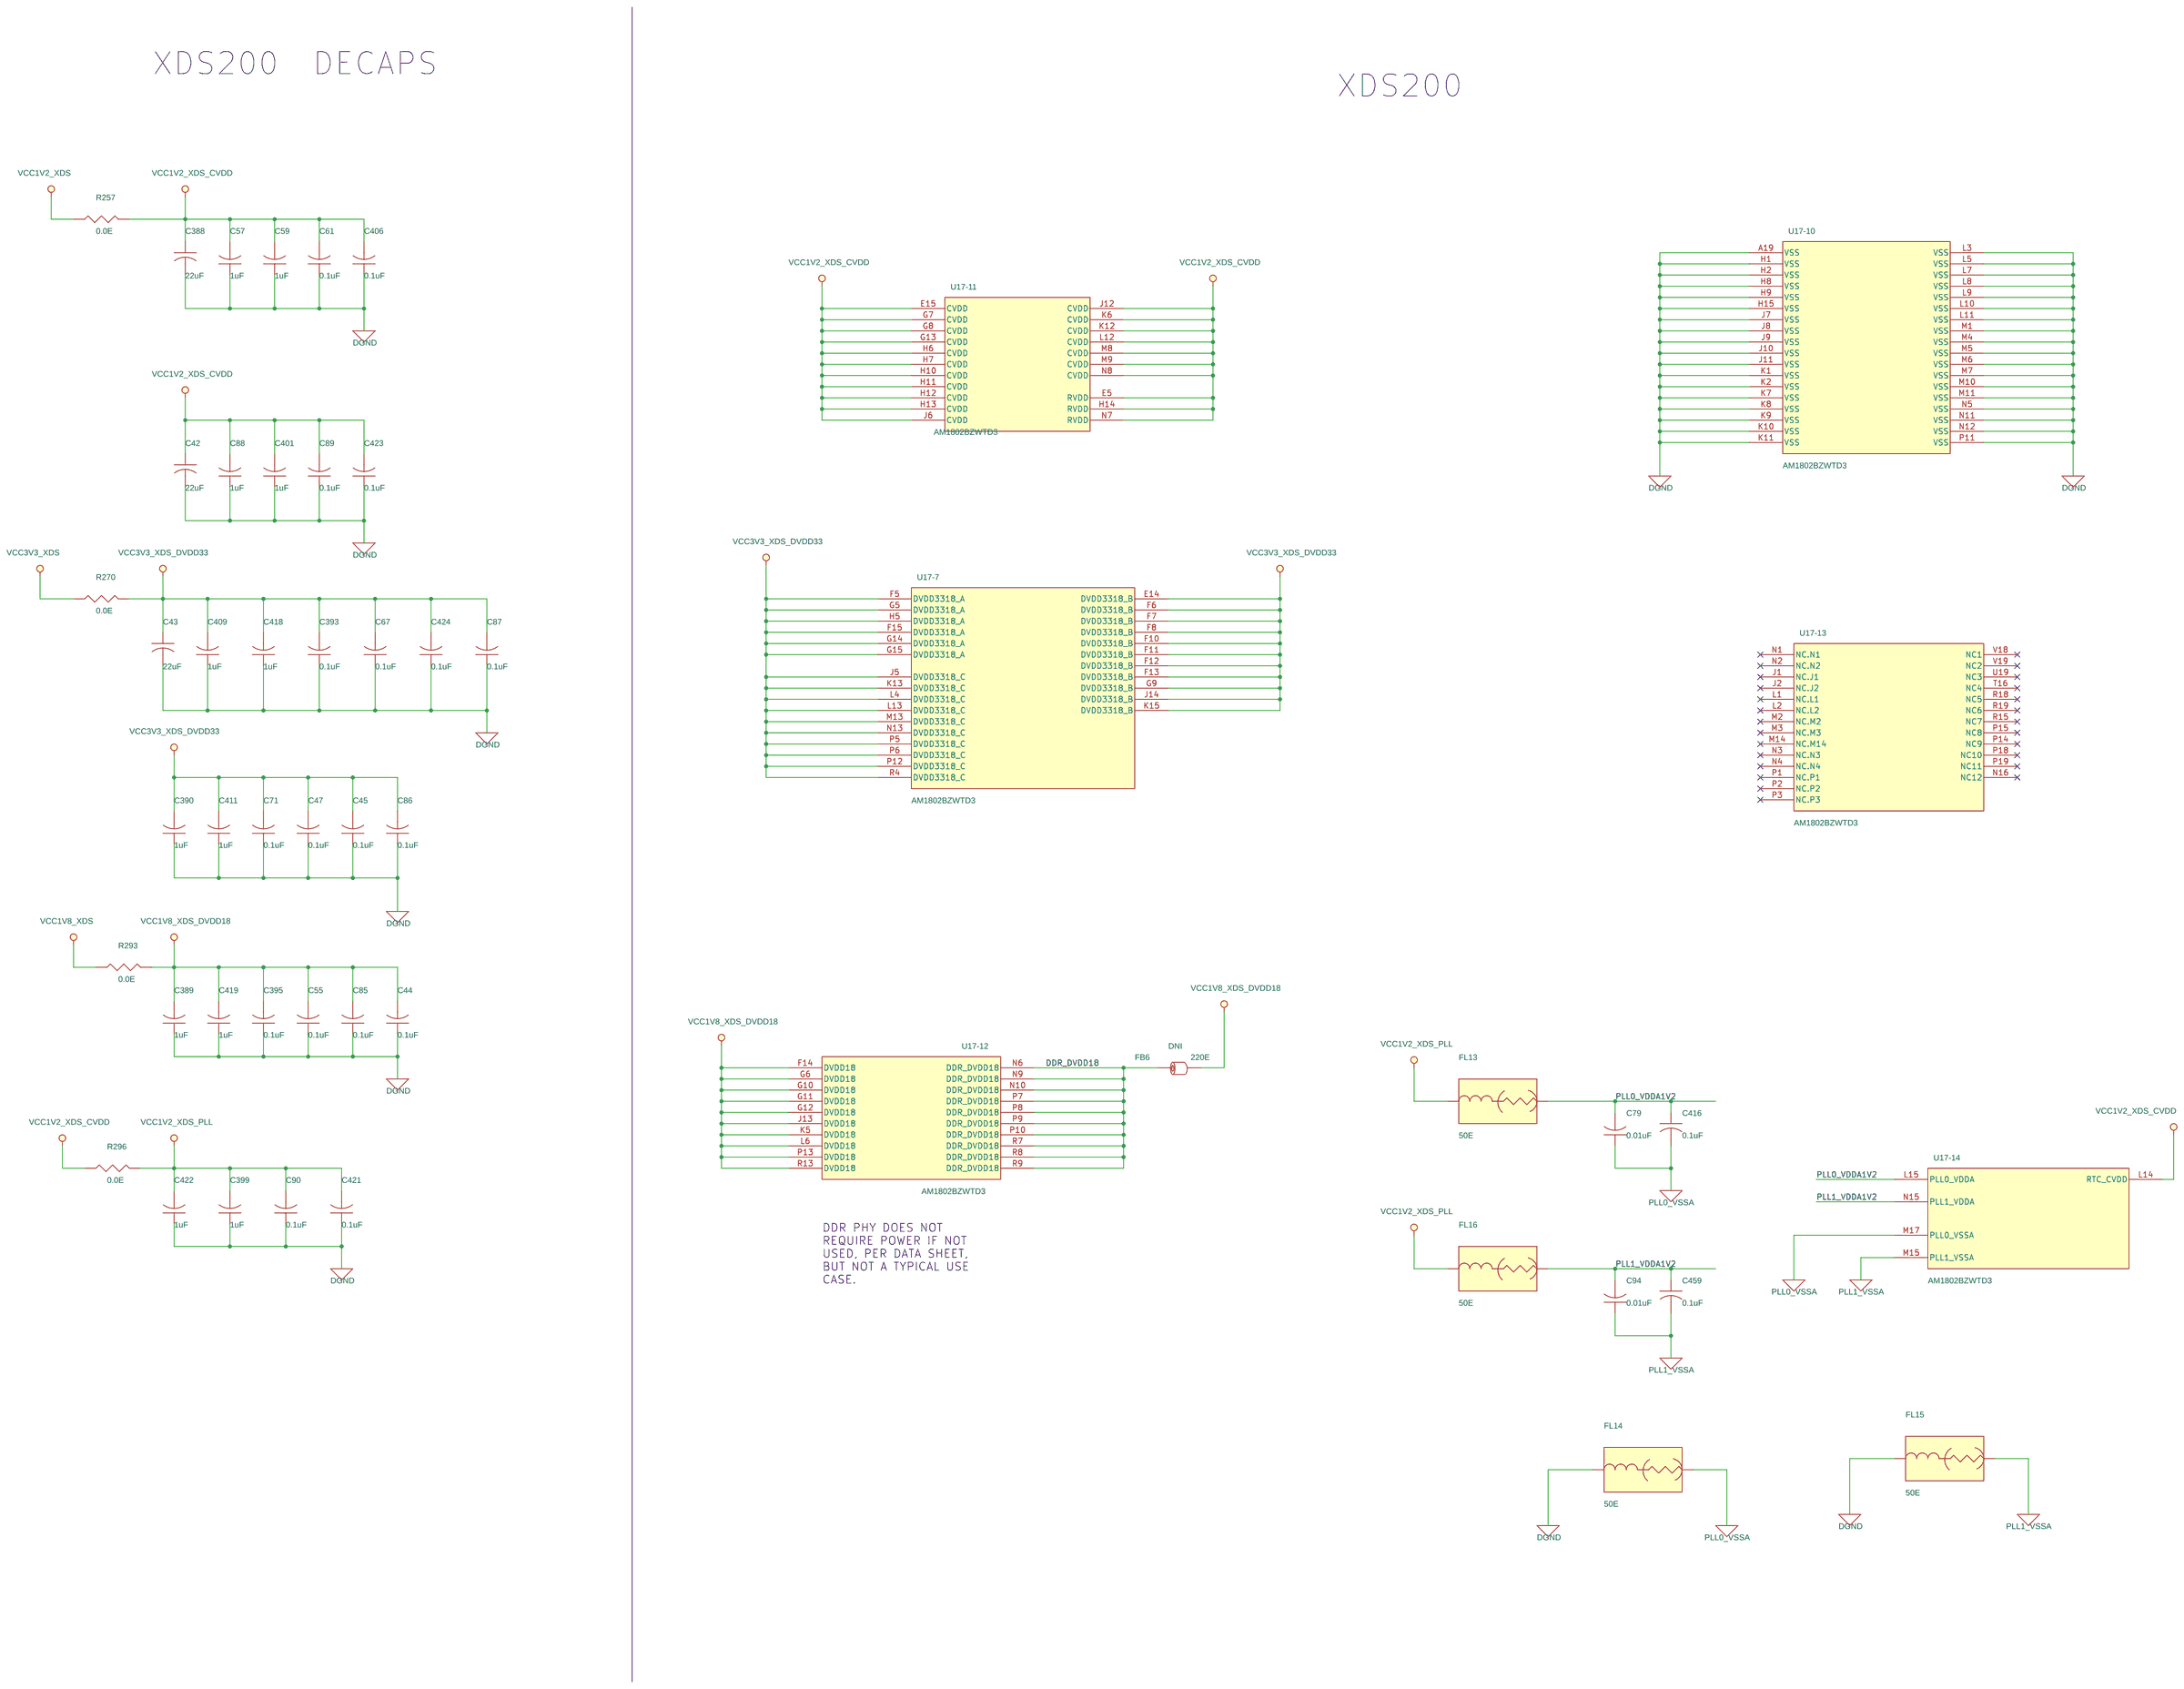
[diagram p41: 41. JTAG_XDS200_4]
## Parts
sheet 39. JTAG_XDS200_2
C375  0.1uF  [CAP0402]
C378  0.1uF  [CAP0402]
C379  0.1uF  [CAP0402]
C380  0.1uF  [CAP0402]
C381  22uF  [CAP0805]
C382  0.1uF  [CAP0402]
C383  0.1uF  [CAP0402]
R86  22E_1%  [RES0402]
R87  22E_1%  [RES0402]
R88  22E_1%  [RES0402]
R89  470E  [RES0402]
R90  470E  [RES0402]
R91  22E_1%  [RES0402]
R92  22E_1%  [RES0402]
R93  22E_1%  [RES0402]
R94  22E_1%  [RES0402]
R119  10K_1%  [RES0402]
R123  10K_1%  [RES0402]
R613  10K_1%  [RES0402]
R614  10K_1%  [RES0402]
R615  10K_1%  [RES0402]
R616  22E_1%  [RES0402]
R617  10K_1%  [RES0402]
R618  22E_1%  [RES0402]
R619  22E_1%  [RES0402]
R620  22E_1%  [RES0402]
RA1  22E  [RESA_0402-4]
RA2  22E  [RESA_0402-4]
RA3  22E  [RESA_0402-4]
RA4  22E  [RESA_0402-4]
RA5  22E  [RESA_0402-4]
RA11  22E  [RESA_0402-4]
RA12  22E  [RESA_0402-4]
RA13  22E  [RESA_0402-4]
RA14  22E  [RESA_0402-4]
TP40  SMD  [TP40_SMD]
U9  MT48LC4M16A2B4-6A:J  [VFBGA54_31-49_320X320]
U17  AM1802BZWTD3  [BGA361_31-49_635X635]  (sections -1,-10,-11,-12,-13,-14,-2,-3,-4,-5,-6,-7,-8,-9)
sheet 40. JTAG_XDS200_3
C52  18pF  [CAP0402]
C53  18pF  [CAP0402]
C54  33pF  [CAP0805]
C60  33pF  [CAP0805]
C407  22pF  [CAP0402]
J8  CON_10X2  [CON_10X2_FTR-110-51-S-D_P_S_S]
R141  22E_1%  [RES0402]
R142  1K  [RES0402]
R143  10K_1%  [RES0402]
R149  100E  [RES0402]
R152  1K  [RES0402]
R156  470E  [RES0402]
R165  1K  [RES0402]
R167  0E_1%  [RES0402]
R169  10K_1%  [RES0402]
R172  1K  [RES0402]
R178  1K  [RES0402]
R185  10K_1%  [RES0402]
R187  1K  [RES0402]
R189  47E_1%  [RES0402]
R194  1K  [RES0402]
R240  0E_1%  [RES0402]
R243  0E_1%  [RES0402]
R630  0E_1%  [RES0402]
R635  0E_1%  [RES0402]
R636  4.7K_5%  [RES0402]
R640  10K_1%  [RES0402]
R641  4.7K_5%  [RES0402]
R642  1K  [RES0402]
R644  10K_1%  [RES0402]
R649  10K_1%  [RES0402]
R650  10K_1%  [RES0402]
R651  1K  [RES0402]
R653  1K  [RES0402]
R654  1K  [RES0402]
R657  1K  [RES0402]
R658  1K  [RES0402]
R782  4.7K_5%  [RES0402]
TP57  SMD  [TP40_SMD]
TP65  SMD  [TP40_SMD]
TP82  SMD  [TP40_SMD]
Y1  32.768KHz  [XTAL_FC-135_130X65_SMD]
Y2  24MHz  [XTAL4_ABM8G_130X105_SMD]
sheet 41. JTAG_XDS200_4
C42  22uF  [CAP0805]
C43  22uF  [CAP0805]
C44  0.1uF  [CAP0402]
C45  0.1uF  [CAP0402]
C47  0.1uF  [CAP0402]
C55  0.1uF  [CAP0402]
C57  1uF  [CAP0402]
C59  1uF  [CAP0402]
C61  0.1uF  [CAP0402]
C67  0.1uF  [CAP0402]
C71  0.1uF  [CAP0402]
C79  0.01uF  [CAP0402]
C85  0.1uF  [CAP0402]
C86  0.1uF  [CAP0402]
C87  0.1uF  [CAP0402]
C88  1uF  [CAP0402]
C89  0.1uF  [CAP0402]
C90  0.1uF  [CAP0402]
C94  0.01uF  [CAP0402]
C388  22uF  [CAP0805]
C389  1uF  [CAP0402]
C390  1uF  [CAP0402]
C393  0.1uF  [CAP0402]
C395  0.1uF  [CAP0402]
C399  1uF  [CAP0402]
C401  1uF  [CAP0402]
C406  0.1uF  [CAP0402]
C409  1uF  [CAP0402]
C411  1uF  [CAP0402]
C416  0.1uF  [CAP0402]
C418  1uF  [CAP0402]
C419  1uF  [CAP0402]
C421  0.1uF  [CAP0402]
C422  1uF  [CAP0402]
C423  0.1uF  [CAP0402]
C424  0.1uF  [CAP0402]
C459  0.1uF  [CAP0402]
FB6  220E  [IND0603]
FL13  50E  [EMIFIL_BLM31P_1206]
FL14  50E  [EMIFIL_BLM31P_1206]
FL15  50E  [EMIFIL_BLM31P_1206]
FL16  50E  [EMIFIL_BLM31P_1206]
R257  0.0E  [RES0603]
R270  0.0E  [RES0603]
R293  0.0E  [RES0603]
R296  0.0E  [RES0603]

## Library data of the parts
C44 C45 C47 C55 C61 C67 C71 C85-C87 C89 C90 C375 C378-C380 C382 C383 C393 C395 C406 C416 C421 C423 C424 C459 = CAP: CAP CERAMIC 0.1uF 16V 10% X7R 0402; Alternate_mfr_name_A: KEMET; Alternate_mfr_part_number_A: C0402C104K4RACT; Chkd/date: MAZHAR/281108; Crtd /date: MAZHAR/030907; Custom_Duty: 15%; Customs_HS_Code: 85322990; Distributor_name: DIGIKEY; Distributor_name_A: DIGIKEY; Distributor_part_number: 490-3261-1-ND; Distributor_part_number_A: 399-3521-1-ND; Height: 0.55MM; Mfr_name: MURATA; Mfr_part_number: GRM155R71C104KA88D; Mistral Part No: 120009030060-R; Package: 0402; Part_type: CAPACITORS\CERAMIC; Project: SMART VIEW_IP CAMERA; Tolerance: 10%; Voltage: 16V; Datasheet: Y:\MIS_DATABASE\DATASHEETS\CAPACITORS\GRM188SERIES.PDF
C42 C43 C381 C388 = CAP: CAP CERAMIC 22uF 16V 10% X5R 0805; Chkd/date: MAZHAR/291110; Crtd /date: BAVISH/271110; Custom_Duty: 15%; Customs_HS_Code: 85322990; Distributor_name: NA; Distributor_part_number: NA; Height: 1.45MM; Mfr_name: TDK CORPORATION; Mfr_part_number: C2012X5R1C226K; Mistral Part No: 120010110025-R; Package: 0805; Part_type: CAPACITORS\CERAMIC; Project: EM-FLS; RoHS: RoHS; Temperature: -55°C+85°C; Tolerance: 10%; Voltage: 16V; Wattage: NA; Weight: NA; Datasheet: Y:\MIS_DATABASE\DATASHEETS\CAPACITORS\C2012.PDF
R86-R88 R91-R94 R141 R616 R618-R620 = RESISTOR: RES 22E 1/16W 1% 0402; Alternate_mfr_name_A: VISHAY; Alternate_mfr_part_number_A: CRCW040222R0FKED; Chkd/date: SUHAS/290910; Crtd /date: MAZHAR/090909; Custom_Duty: 15%; Customs_HS_Code: 85332119; Distributor_name: DIGIKEY; Distributor_name_A: DIGIKEY; Distributor_part_number: 311-22.0LRCT-ND; Distributor_part_number_A: 541-22.0LCT-ND; Height: 0.40MM; Mfr_name: YAGEO AMERICA; Mfr_part_number: RC0402FR-0722RL; Mistral Part No: 110009090004-P; Package: 0402; Part_type: RESISTORS\FIXED; Project: VMEFMCD; Remarks: In alternate datasheet it is RoHS COMPLIANT. Y:\MIS_DATABASE\DATASHEETS\RESISTORS\CRCW0402.PDF; RoHS: Pb-Free; Temperature: -55°C+155°C; Tolerance: 1%; Voltage: 50V; Wattage: 1/16W; Weight: 0.8g/1000pcs; Datasheet: Y:\MIS_DATABASE\DATASHEETS\RESISTORS\YAGEO-RC0402.PDF
R89 R90 R156 = RESISTOR: RES 470E 1/16W 5% 0402; Alternate_mfr_name_A: AVX CORPORATION; Alternate_mfr_name_C: YAGEO AMERICA; Alternate_mfr_part_number_A: CR05-471J-H; Alternate_mfr_part_number_C: 9C04021A4700JLHF3; Chkd/date: SHREESHAIL/24050; Crtd /date: MAZHAR/260706; Custom_Duty: 15%; Customs_HS_Code: 85332119; Distributor_name: DIGIKEY; Distributor_name_A: NA; Distributor_name_C: DIGIKEY; Distributor_part_number: P470JCT-ND; Distributor_part_number_A: NA; Distributor_part_number_C: 311-470JCT-ND; Height: 0.40MM; Mfr_name: PANASONIC-ECG; Mfr_part_number: ERJ-2GEJ471X; Mistral Part No: 110009030859-R; Package: 0402; Part_type: RESISTORS\FIXED; Project: POWERBOX; RoHS: RoHS; Tolerance: 5%; Wattage: 1/16W; Datasheet: Y:\MIS_DATABASE\DATASHEETS\RESISTORS\ERJ12.PDF
R119 R123 R185 R613-R615 R617 R640 R650 = RESISTOR: RES 10K 1/16W 1% 0402; Alternate_mfr_name_A: AVX CORPORATION; Alternate_mfr_name_B: PANASONIC-ECG-ECG; Alternate_mfr_name_C: YAGEO AMERICA; Alternate_mfr_name_D: VISHAY; Alternate_mfr_part_number_A: CR05-103F-H; Alternate_mfr_part_number_B: ERJ-2RKF1002X; Alternate_mfr_part_number_C: 9C04021A1002FLHF3; Alternate_mfr_part_number_D: CRCW040210K0FKED; Chkd/date: SHREESHAIL/310506; Crtd /date: GEETHA/290506; Custom_Duty: 15%; Customs_HS_Code: 85332119; Distributor_name: DIGIKEY; Distributor_name_A: NA; Distributor_name_B: DIGIKEY; Distributor_name_C: DIGIKEY; Distributor_name_D: DIGIKEY; Distributor_part_number: 311-10.0KLRTR-ND; Distributor_part_number_A: NA; Distributor_part_number_B: P10.0KLCT-ND; Distributor_part_number_C: 311-10.0KLCT-ND; Distributor_part_number_D: 541-10.0KLCT-ND; Height: 0.40MM; Mfr_name: YAGEO AMERICA; Mfr_part_number: RC0402FR-0710KL; Mistral Part No: 110009030220-P; Package: 0402; Part_type: RESISTORS\FIXED; Project: VOCERA; RoHS: Pb-Free; Tolerance: 1%; Wattage: 1/16W; Datasheet: Y:\MIS_DATABASE\DATASHEETS\RESISTORS\YAGEO-RC0402.PDF
RA1-RA5 RA11-RA14 = RESARR_ISO4: RES ARRAY 22E 31mW 5% 0402; Chkd/date: MAZHAR/291208; Crtd /date: USMAN/261108; Distributor_name: DIGIKEY; Distributor_part_number: Y7220CT-ND; Height: 0.45MM; Mfr_name: PANASONIC-ECG; Mfr_part_number: EXB-28V220JX; Mistral Part No: 110009030021-R; Package: 0402; Part_type: RESISTORS\ARRAY; Project: KHAN_MAIN; RoHS: RoHS; Tolerance: 5%; Wattage: 31mW; Datasheet: Y:\MIS_DATABASE\DATASHEETS\RESISTORS\EXB-2HV.PDF
TP40 TP57 TP65 TP82 = TESTPOINT: TESTPOINT 40 SMD; Chkd/date: MAZHAR/190505; Crtd /date: MAZHAR/190505; Distributor_name: NA; Distributor_part_number: NA; Height: NA; Mfr_name: LOCAL; Mistral Part No: 130009030933; Part_type: MISC\TESTPOINT; Project: RAINIER-3
U9 = MT48LC4M16A2B4_VFBGA54: IC SYNCHRONOUS DRAM VFBGA54; Chkd/date: NAVEED/230215; Crtd /date: VASANTHA/200215; Custom_Duty: 15%; Customs_HS_Code: 85423100; Distributor_name: DIGIKEY; Distributor_part_number: MT48LC4M16A2B4-6A:J-ND; Height: 1.00MM; Mfr_name: MICRON; Mistral Part No: 141015002002-R; Package: VFBGA54; Part_type: ICS\DIGITAL\MEMORY; Project: GALILEO_EVM; RoHS: RoHS; Temperature: -0°C+70°C; Tolerance: NA; Voltage: NA; Wattage: NA; Weight: NA; Datasheet: Y:\MIS_DATABASE\DATASHEETS\ICS\MEMORY\MT48LCXXX.PDF
U17 = AM1802BZWTD3_BGA361: IC PROCESSOR SITARA ARM 300MHZ BGA361; Chkd/date: NAVEED/141114; Color: Default; Crtd /date: VASANTHA/121014; Custom_Duty: 15%; Customs_HS_Code: 85423100; Distributor_name: MOUSER; Distributor_part_number: 595-AM1802BZWTD3; Height: 1.30MM; Location X-Coordinate: 0; Location Y-Coordinate: 0; Mfr_name: TEXAS INSTRUMENTS; Mistral Part No: 141214100001-R; Package: BGA361; Part_type: ICS\DIGITAL\MICROPROCESSOR; Power Pins Visible: False; Primitive: DEFAULT; Project: GALILEO_EVM; RoHS: RoHS; SPLIT_INST: TRUE; Temperature: -40°C+90°C; Tolerance: NA; Voltage: NA; Wattage: NA; Weight: NA; Datasheet: Y:\MIS_DATABASE\DATASHEETS\ICS\DIGITAL\MICROCONTROLLER\AM1802.PDF
C52 C53 = CAP: CAP CERAMIC 18pF 50V 5% NP0 0402; Chkd/date: SHREESHAIL/291105; Crtd /date: MAZHAR/040505; Custom_Duty: 15%; Customs_HS_Code: 85322990; Distributor_name: DIGIKEY; Distributor_part_number: 478-1073-1-ND; Height: 0.60MM; Mfr_name: AVX CORPORATION; Mfr_part_number: 04025A180JAT2A; Mistral Part No: 120009030241-R; Package: 0402; Part_type: CAPACITORS\CERAMIC; Project: TELEMATICS-02; RoHS: RoHS; Tolerance: 5%; Voltage: 50V; Datasheet: Y:\MIS_DATABASE\DATASHEETS\CAPACITORS\AVX_MLC.PDF
C54 C60 = CAP: CAP CERAMIC 33pF 50V 5% NP0 0805; Assembly instruction: <Assembly instruction>; Chkd/date: RAGESH/270910; Crtd /date: USMAN/070109; Custom_Duty: 15%; Customs_HS_Code: 85322990; Distributor_name: DIGIKEY; Distributor_part_number: 311-1105-1-ND; Height: 1.35MM; Mfr_name: YAGEO AMERICA; Mfr_part_number: CC0805JRNP09BN330; Mistral Part No: 120009030389; Package: 0805; Part_type: CAPACITORS\CERAMIC; Project: OMAP_EVM; RoHS: RoHS; Temperature: -55°C+125°C; Tolerance: 5%; Voltage: 50V; Weight: NA; Datasheet: Y:\MIS_DATABASE\DATASHEETS\CAPACITORS\CC_SERIES.PDF
C407 = CAP: CAP CERAMIC 22pF 25V 5% NP0 0402; Chkd/date: SHREESHAIL/291105; Crtd /date: MAZHAR/040505; Custom_Duty: 15%; Customs_HS_Code: 85322990; Distributor_name: DIGIKEY; Distributor_part_number: 04023A220JAT2A-ND; Height: 0.60MM; Mfr_name: AVX CORPORATION; Mfr_part_number: 04023A220JAT2A; Mistral Part No: 120009030322-R; Package: 0402; Part_type: CAPACITORS\CERAMIC; Project: TELEMATICS-02; RoHS: RoHS; Tolerance: 5%; Voltage: 25V; Datasheet: Y:\MIS_DATABASE\DATASHEETS\CAPACITORS\AVX_MLC.PDF
J8 = CON_10X2: CON 10X2 1.27MM PITCH MALE SMD; Chkd/date: BAVISH/050911; Crtd /date: CHAITHANYA/050811; Custom_Duty: 24%; Customs_HS_Code: 85369090; Distributor_name: DIGIKEY; Distributor_part_number: FTR-110-51-S-D-06-ND; Height: 7.37MM; Mfr_name: SAMTEC; Mfr_part_number: FTR-110-51-S-D-06; Mistral Part No: 150011090001-R; Package: SMD; Part_type: CONNECTOR\MISCELLANEOUS; Project: GEMYC; RoHS: RoHS; Temperature: -55°C+105°C; Tolerance: NA; Voltage: NA; Wattage: NA; Weight: NA; Datasheet: Y:\MIS_DATABASE\DATASHEETS\CONNECTORS\FTR-SERIES1.PDF
R142 R152 R165 R178 R187 R642 R651 R653 R658 = RESISTOR: RES 1K 1/16W 5% 0402; Alternate_mfr_name_A: AVX CORPORATION; Alternate_mfr_name_C: YAGEO AMERICA; Alternate_mfr_part_number_A: CR05-102J-H; Alternate_mfr_part_number_C: RC0402JR-071KL; Chkd/date: SHREESHAIL/121205; Crtd /date: MAZHAR/230805; Custom_Duty: 15%; Customs_HS_Code: 85332119; Distributor_name: DIGIKEY; Distributor_name_A: NA; Distributor_name_C: DIGIKEY; Distributor_part_number: P1.0KJCT-ND; Distributor_part_number_A: NA; Distributor_part_number_C: 311-1.0KJRCT-ND; Height: 0.40MM; Mfr_name: PANASONIC-ECG; Mfr_part_number: ERJ-2GEJ102X; Mistral Part No: 110009030400-R; Package: 0402; Part_type: RESISTORS\FIXED; Project: HSE; RoHS: RoHS; Tolerance: 5%; Wattage: 1/16W; Datasheet: Y:\MIS_DATABASE\DATASHEETS\RESISTORS\ERJ12.PDF
R143 R169 R644 R649 = RESISTOR: RES 10K 1/16W 1% 0402; Alternate_mfr_name_A: AVX CORPORATION; Alternate_mfr_name_B: PANASONIC-ECG-ECG; Alternate_mfr_name_C: YAGEO AMERICA; Alternate_mfr_name_D: VISHAY; Alternate_mfr_part_number_A: CR05-103F-H; Alternate_mfr_part_number_B: ERJ-2RKF1002X; Alternate_mfr_part_number_C: 9C04021A1002FLHF3; Alternate_mfr_part_number_D: CRCW040210K0FKED; Chkd/date: SHREESHAIL/310506; Crtd /date: GEETHA/290506; Custom_Duty: 15%; Customs_HS_Code: 85332119; Distributor_name: DIGIKEY; Distributor_name_A: NA; Distributor_name_B: DIGIKEY; Distributor_name_C: DIGIKEY; Distributor_name_D: DIGIKEY; Distributor_part_number: 311-10.0KLRTR-ND; Distributor_part_number_A: NA; Distributor_part_number_B: P10.0KLCT-ND; Distributor_part_number_C: 311-10.0KLCT-ND; Distributor_part_number_D: 541-10.0KLCT-ND; Height: 0.40MM; Loading: DNI; Mfr_name: YAGEO AMERICA; Mfr_part_number: RC0402FR-0710KL; Mistral Part No: 110009030220-P; Package: 0402; Part_type: RESISTORS\FIXED; Project: VOCERA; RoHS: Pb-Free; Tolerance: 1%; Wattage: 1/16W; Datasheet: Y:\MIS_DATABASE\DATASHEETS\RESISTORS\YAGEO-RC0402.PDF
R149 = RESISTOR: RES 100E 1/16W 5% 0402; Alternate_mfr_name_A: AVX CORPORATION; Alternate_mfr_name_C: YAGEO AMERICA; Alternate_mfr_name_D: YAGEO AMERICA; Alternate_mfr_part_number_A: CR05-101J-H; Alternate_mfr_part_number_C: 9C04021A1000JLHF3; Alternate_mfr_part_number_D: RC0402JR-07100RL; Chkd/date: SHREESHAIL/210406; Crtd /date: GEETHA/200406; Custom_Duty: 15%; Customs_HS_Code: 85332119; Distributor_name: DIGIKEY; Distributor_name_A: NA; Distributor_name_C: DIGIKEY; Distributor_name_D: DIGIKEY; Distributor_part_number: P100JCT-ND; Distributor_part_number_A: NA; Distributor_part_number_C: 311-100JCT-ND; Distributor_part_number_D: 311-100JRCT-ND; Height: 0.40MM; Mfr_name: PANASONIC-ECG; Mfr_part_number: ERJ-2GEJ101X; Mistral Part No: 110009030164-R; Package: 0402; Part_type: RESISTORS\FIXED; Project: RED EYE; RoHS: RoHS; Tolerance: 5%; Wattage: 1/16W; Datasheet: Y:\MIS_DATABASE\DATASHEETS\RESISTORS\ERJ12.PDF
R167 R630 R635 = RESISTOR: RES 0E 1/16W 1% 0402; Chkd/date: MAZHAR/220709; Crtd /date: USMAN/270109; Custom_Duty: 15%; Customs_HS_Code: 85332119; Distributor_name: NA; Distributor_part_number: NA; Height: 0.40MM; Mfr_name: YAGEO AMERICA; Mfr_part_number: RC0402FR-070RL; Mistral Part No: 110009030085-P; Package: 0402; Part_type: RESISTORS\FIXED; Project: OMAP_EVM; RoHS: Pb-Free; Tolerance: 1%; Wattage: 1/16W; Datasheet: Y:\MIS_DATABASE\DATASHEETS\RESISTORS\CRCW0603.PDF
R172 R194 R654 R657 = RESISTOR: RES 1K 1/16W 5% 0402; Alternate_mfr_name_A: AVX CORPORATION; Alternate_mfr_name_C: YAGEO AMERICA; Alternate_mfr_part_number_A: CR05-102J-H; Alternate_mfr_part_number_C: RC0402JR-071KL; Assembly instruciton: DNI; Chkd/date: SHREESHAIL/121205; Crtd /date: MAZHAR/230805; Custom_Duty: 15%; Customs_HS_Code: 85332119; Distributor_name: DIGIKEY; Distributor_name_A: NA; Distributor_name_C: DIGIKEY; Distributor_part_number: P1.0KJCT-ND; Distributor_part_number_A: NA; Distributor_part_number_C: 311-1.0KJRCT-ND; Height: 0.40MM; Loading: DNI; Mfr_name: PANASONIC-ECG; Mfr_part_number: ERJ-2GEJ102X; Mistral Part No: 110009030400-R; Package: 0402; Part_type: RESISTORS\FIXED; Project: HSE; RoHS: RoHS; Tolerance: 5%; Wattage: 1/16W; Datasheet: Y:\MIS_DATABASE\DATASHEETS\RESISTORS\ERJ12.PDF
R189 = RESISTOR: RES 47E 1/16W 1% 0402; Chkd/date: VASANTHA/190614; Crtd /date: NAVEED/160614; Custom_Duty: 15%; Customs_HS_Code: 85332119; Distributor_name: DIGIKEY; Distributor_part_number: RMCF0402FT47R0CT-ND; Height: 0.40MM; Mfr_name: STACKPOLE ELECTRONICS; Mfr_part_number: RMCF0402FT47R0; Mistral Part No: 110014060027-R; Package: 0402; Part_type: RESISTORS\FIXED; Project: AEGIS_POM; RoHS: RoHS; Temperature: -55°C+155°C; Tolerance: 1%; Voltage: NA; Wattage: 1/16W; Weight: NA; Datasheet: Y:\MIS_DATABASE\DATASHEETS\RESISTORS\RMCF-SERIES1.PDF
R240 R243 = RESISTOR: RES 0E 1/16W 1% 0402; Chkd/date: MAZHAR/220709; Crtd /date: USMAN/270109; Custom_Duty: 15%; Customs_HS_Code: 85332119; Distributor_name: NA; Distributor_part_number: NA; Height: 0.40MM; Loading: DNI; Mfr_name: YAGEO AMERICA; Mfr_part_number: RC0402FR-070RL; Mistral Part No: 110009030085-P; Package: 0402; Part_type: RESISTORS\FIXED; Project: OMAP_EVM; RoHS: Pb-Free; Tolerance: 1%; Wattage: 1/16W; Datasheet: Y:\MIS_DATABASE\DATASHEETS\RESISTORS\CRCW0603.PDF
R636 R641 R782 = RESISTOR: RES 4.7K 1/16W 5% 0402; Chkd/date: VASANTHA/190614; Crtd /date: NAVEED/160614; Custom_Duty: 15%; Customs_HS_Code: 85332119; Distributor_name: DIGIKEY; Distributor_part_number: RMCF0402JT4K70CT-ND; Height: 0.40MM; Mfr_name: STACKPOLE ELECTRONICS; Mfr_part_number: RMCF0402JT4K70; Mistral Part No: 110014060028-R; Package: 0402; Part_type: RESISTORS\FIXED; Project: AEGIS_POM; RoHS: RoHS; Temperature: -55°C+155°C; Tolerance: 5%; Voltage: NA; Wattage: 1/16W; Weight: NA; Datasheet: Y:\MIS_DATABASE\DATASHEETS\RESISTORS\RMCF-SERIES1.PDF
Y1 = CRY: CRY 32.768KHz SMD; Chkd/date: SHREESHAIL/211205; Crtd /date: MAZHAR/061005; Custom_Duty: 24%; Customs_HS_Code: 85439000; Distributor_name: DIGIKEY; Distributor_part_number: SE2413CT-ND; Height: 0.90MM; Mfr_name: CRYSTAL UNITS; Mfr_part_number: FC-135 32.7680KA-A3; Mistral Part No: 130009030095-P; Package: SMD; Part_type: CRYSTAL; Project: J30; RoHS: Pb-Free; Datasheet: Y:\MIS_DATABASE\DATASHEETS\MISC\CRY_OSC\FC-135.PDF
Y2 = CRY4_ABM8G: CRY 24MHZ 18pF SMD; Chkd/date: USMAN/251111; Crtd /date: CHAITHANYA/251111; Custom_Duty: 24%; Customs_HS_Code: 85439000; Distributor_name: DIGIKEY; Distributor_part_number: 535-10273-1-ND; Height: 1.00MM; Mfr_name: ABRACON; Mfr_part_number: ABM8G-24.000MHZ-18-D2Y-T; Mistral Part No: 130011110059-R; Package: SMD; Part_type: CRYSTAL; Project: NA10NG; RoHS: RoHS; Temperature: -40°C+85°C; Tolerance: NA; Voltage: NA; Wattage: NA; Weight: NA; Datasheet: Y:\MIS_DATABASE\DATASHEETS\MISC\CRY_OSC\ABM8G.PDF
C57 C59 C88 C389 C390 C399 C401 C409 C411 C418 C419 C422 = CAP: CAP CERAMIC 1uF 10V 10% X5R 0402; Chkd/date: BALACHANDAR/160514; Crtd /date: SARANYA/060514; Custom_Duty: 15%; Customs_HS_Code: 85322990; Distributor_name: DIGIKEY; Distributor_part_number: 478-4596-1-ND; Height: 0.56MM; Mfr_name: AVX CORPORATION; Mfr_part_number: 0402ZD105KAT2A; Mistral Part No: 120014050010-R; Package: 0402; Part_type: CAPACITORS\CERAMIC; Project: AEGIS GP BETA2; RoHS: RoHS; Temperature: -55°C+85°C; Tolerance: 10%; Voltage: 10V; Wattage: NA; Weight: NA; Datasheet: Y:\MIS_DATABASE\DATASHEETS\CAPACITORS\AVX_MLC.PDF
C79 C94 = CAP: CAP CERAMIC 0.01uF 16V 10% X7R 0402; Alternate_mfr_name_A: AVX CORPORATION; Alternate_mfr_name_B: KEMET; Alternate_mfr_name_D: TDK CORPORATION; Alternate_mfr_part_number_A: 0402YC103KAT2A; Alternate_mfr_part_number_B: C0402C103K4RACTU; Alternate_mfr_part_number_D: C1005X7R1C103K; Chkd/date: SHREESHAIL/180506; Crtd /date: MAZHAR/110506; Custom_Duty: 15%; Customs_HS_Code: 85322990; Distributor_name: DIGIKEY; Distributor_name_A: DIGIKEY; Distributor_name_B: DIGIKEY; Distributor_name_D: DIGIKEY; Distributor_part_number: PCC103BQCT-ND; Distributor_part_number_A: 478-1114-1-ND; Distributor_part_number_B: 399-1038-1-ND; Distributor_part_number_D: 445-1262-1-ND; Height: 0.55MM; Mfr_name: PANASONIC-ECG; Mfr_part_number: ECJ-0EB1C103K; Mistral Part No: 120009030032-R; Package: 0402; Part_type: CAPACITORS\CERAMIC; Project: VOCERA; RoHS: RoHS; Tolerance: 10%; Voltage: 16V; Datasheet: Y:\MIS_DATABASE\DATASHEETS\CAPACITORS\PAN-ECJ.PDF
FB6 = INDUCTOR_FERRITE: IND BEAD CHIP 200E 20% 0603; Assembly instruciton: DNI; Chkd/date: MAZHAR/161208; Crtd /date: USMAN/201108; Custom_Duty: 24%; Customs_HS_Code: 85437099; Distributor_name: DIGIKEY; Distributor_part_number: 445-1565-1-ND; Height: 0.95MM; Loading: DNI; Mfr_name: TDK CORPORATION; Mfr_part_number: MPZ1608S221A; Mistral Part No: 130009030553; Package: 0603; Part_type: INDUCTOR; Project: KHAN_HSST; Tolerance: 20%; Datasheet: Y:\MIS_DATABASE\DATASHEETS\DISCRETES\INDUCTORS\MPZ1608.PDF
FL13-FL16 = EMIFILTER_IND: PASSIVE FILTER EMI 50E 3000MA 1206; Chkd/date: MAZHAR/030809; Crtd /date: MAZHAR/110907; Custom_Duty: 24%; Customs_HS_Code: 85437099; Distributor_name: DIGIKEY; Distributor_part_number: 490-1055-1-ND; Height: 1.30MM; Mfr_name: MURATA; Mfr_part_number: BLM31PG500SN1L; Mistral Part No: 130009030792; Package: 1206; Part_type: MISC\FILTER; Project: HSE SERVO; Datasheet: Y:\MIS_DATABASE\DATASHEETS\ICS\MISC\BLM31.PDF
R257 R270 R293 R296 = RESISTOR: RES 0.0E 1/10W JUMP 0603; Chkd/date: VASANTHA/061014; Crtd /date: NAVEED/220714; Custom_Duty: 15%; Customs_HS_Code: 85332119; Distributor_name: DIGIKEY; Distributor_part_number: P0.0GCT-ND; Height: 0.55MM; Mechanical part status: DS CHANGED WEIGHT & TEMP ADDED; Mfr_name: PANASONIC-ECG; Mfr_part_number: ERJ-3GEY0R00V; Mistral Part No: 110014070017-R; Package: 0603; Part_type: RESISTORS\FIXED; Project: DLRU; RoHS: RoHS; Temperature: -55°C+155°C; Tolerance: NA; Voltage: NA; Wattage: 1/10W; Weight: 2/1000g; Datasheet: Y:\MIS_DATABASE\DATASHEETS\RESISTORS\PAN-ERJ-3GE.PDF

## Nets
DGND: C42.2 C43.2 C44.1 C45.1 C47.1 C55.1 C57.1 C59.1 C61.1 C67.1 C71.1 C85.1 C86.1 C87.1 C88.1 C89.1 C90.1 C375.2 C378.2 C379.2 C380.2 C381.2 C382.2 C383.2 C388.2 C389.1 C390.1 C393.1 C395.1 C399.1 C401.1 C406.1 C407.1 C409.1 C411.1 C418.1 C419.1 C421.1 C422.1 C423.1 C424.1 FL14.1 FL15.1 J8.4 J8.8 J8.10 J8.12 J8.16 J8.20 R152.1 R165.1 R630.2 R635.2 R642.1 R651.1 R653.1 R654.1 R657.1 R658.1 R782.2 U9.A1(VSS) U9.A3(VSSQ) U9.B7(VSSQ) U9.C3(VSSQ) U9.D7(VSSQ) U9.E3(VSS) U9.J1(VSS) U17.A19(VSS) U17.H1(VSS) U17.H2(VSS) U17.H8(VSS) U17.H9(VSS) U17.H15(VSS) U17.J7(VSS) U17.J8(VSS) U17.J9(VSS) U17.J10(VSS) U17.J11(VSS) U17.K1(VSS) U17.K2(VSS) U17.K7(VSS) U17.K8(VSS) U17.K9(VSS) U17.K10(VSS) U17.K11(VSS) U17.L3(VSS) U17.L5(VSS) U17.L7(VSS) U17.L8(VSS) U17.L9(VSS) U17.L10(VSS) U17.L11(VSS) U17.M1(VSS) U17.M4(VSS) U17.M5(VSS) U17.M6(VSS) U17.M7(VSS) U17.M10(VSS) U17.M11(VSS) U17.N5(VSS) U17.N11(VSS) U17.N12(VSS) U17.P11(VSS) ; also on sheet 1 11 12 13 14 15 16 17 18 19 20 21 22 23 24 25 26 27 28 29 30 31 32 33 34 35 36 37 38 39 43 44 45 46 47 48 49 50
VCC1V2_XDS: R257.1 ; also on sheet 44
VCC1V2_XDS_CVDD: C42.1 C57.2 C59.2 C61.2 C88.2 C89.2 C388.1 C401.2 C406.2 C423.2 R257.2 R296.1 U17.E5(RVDD) U17.E15(CVDD) U17.G7(CVDD) U17.G8(CVDD) U17.G13(CVDD) U17.H6(CVDD) U17.H7(CVDD) U17.H10(CVDD) U17.H11(CVDD) U17.H12(CVDD) U17.H13(CVDD) U17.H14(RVDD) U17.J6(CVDD) U17.J12(CVDD) U17.K6(CVDD) U17.K12(CVDD) U17.L12(CVDD) U17.L14(RTC_CVDD) U17.M8(CVDD) U17.M9(CVDD) U17.N7(RVDD) U17.N8(CVDD) ; also on sheet 39
VCC1V2_XDS_PLL: C90.2 C399.2 C421.2 C422.2 FL13.1 FL16.1 R296.2
VCC1V8_XDS: R293.1 ; also on sheet 43 44
VCC1V8_XDS_DVDD18: C44.2 C55.2 C85.2 C389.2 C395.2 C419.2 FB6.2 R293.2 U17.F14(DVDD18) U17.G6(DVDD18) U17.G10(DVDD18) U17.G11(DVDD18) U17.G12(DVDD18) U17.J13(DVDD18) U17.K5(DVDD18) U17.L6(DVDD18) U17.P13(DVDD18) U17.R13(DVDD18) ; also on sheet 39
VCC3V3_XDS: C375.1 C378.1 C379.1 C380.1 C381.1 C382.1 C383.1 R119.2 R123.2 R142.2 R143.2 R169.2 R172.2 R178.2 R185.2 R187.2 R194.2 R270.1 R613.2 R614.2 R615.2 R617.2 R636.2 R640.2 R641.2 R644.2 R649.2 R650.1 U9.A7(VDDQ) U9.A9(VDD) U9.B3(VDDQ) U9.C7(VDDQ) U9.D3(VDDQ) U9.E7(VDD) U9.J9(VDD) ; also on sheet 39 43 44
VCC3V3_XDS_DVDD33: C43.1 C45.2 C47.2 C67.2 C71.2 C86.2 C87.2 C390.2 C393.2 C409.2 C411.2 C418.2 C424.2 R270.2 U17.E14(DVDD3318_B) U17.F5(DVDD3318_A) U17.F6(DVDD3318_B) U17.F7(DVDD3318_B) U17.F8(DVDD3318_B) U17.F10(DVDD3318_B) U17.F11(DVDD3318_B) U17.F12(DVDD3318_B) U17.F13(DVDD3318_B) U17.F15(DVDD3318_A) U17.G5(DVDD3318_A) U17.G9(DVDD3318_B) U17.G14(DVDD3318_A) U17.G15(DVDD3318_A) U17.H5(DVDD3318_A) U17.J5(DVDD3318_C) U17.J14(DVDD3318_B) U17.K13(DVDD3318_C) U17.K15(DVDD3318_B) U17.L4(DVDD3318_C) U17.L13(DVDD3318_C) U17.M13(DVDD3318_C) U17.N13(DVDD3318_C) U17.P5(DVDD3318_C) U17.P6(DVDD3318_C) U17.P12(DVDD3318_C) U17.R4(DVDD3318_C) ; also on sheet 39
VSS_RTC: C52.2 C53.2 R630.1 U17.H18(VSS_RTC)
CPLD_A0: RA14.6 U9.H7(A0) ; also on sheet 43
CPLD_A1: RA14.8 U9.H8(A1) ; also on sheet 43
CPLD_A2: RA14.5 U9.J8(A2) ; also on sheet 43
CPLD_A3: RA14.7 U9.J7(A3) ; also on sheet 43
CPLD_BIO_0: R91.1 ; also on sheet 43
CPLD_BIO_1: RA13.7 ; also on sheet 43
CPLD_BIO_2: RA13.6 ; also on sheet 43
CPLD_BIO_3: RA13.5 ; also on sheet 43
CPLD_BIO_4: RA13.8 ; also on sheet 43
CPLD_CSn: R93.1 R614.1 ; also on sheet 43
CPLD_D0: RA2.1 U9.A8(DQ0) ; also on sheet 43
CPLD_D1: RA2.3 U9.B9(DQ1) ; also on sheet 43
CPLD_RDn: R615.1 R616.1 ; also on sheet 43
CPLD_RESETn: U17.B10(EMA_A[21]/MMCSD0_DAT[0]/GP4[5]) ; also on sheet 43
CPLD_TCK: R189.1 ; also on sheet 43
CPLD_TDI: U17.U1(GP7[14]) ; also on sheet 43
CPLD_TDO: U17.U2(GP7[15]) ; also on sheet 43
CPLD_TMS: U17.V3(GP7[13]) ; also on sheet 43
CPLD_WEn: R617.1 R618.1 U9.F9(WE#) ; also on sheet 43
DBG_EMU0: R240.1 R636.1 U17.J16(EMU0)
DBG_EMU1: R243.1 R641.1 U17.K16(EMU1)
DBG_RTCK: J8.9 R141.1
DBG_SRST: J8.15 R156.1
DBG_TCK: J8.11 R149.2 U17.J15(TCK)
DBG_TDI: J8.3 U17.M16(TDI)
DBG_TDO: J8.7 U17.J18(TDO)
DBG_TMS: J8.1 U17.L16(TMS)
DBG_TRSTN: J8.2 R782.1 U17.L17(~{TRST})
DDR_DVDD18: FB6.1 U17.N6(DDR_DVDD18) U17.N9(DDR_DVDD18) U17.N10(DDR_DVDD18) U17.P7(DDR_DVDD18) U17.P8(DDR_DVDD18) U17.P9(DDR_DVDD18) U17.P10(DDR_DVDD18) U17.R7(DDR_DVDD18) U17.R8(DDR_DVDD18) U17.R9(DDR_DVDD18)
EMA_A0: RA14.3 U17.C14(EMA_A[0]/GP5[0])
EMA_A1: RA14.1 U17.D15(EMA_A[1]/GP5[1])
EMA_A2: RA14.4 U17.B14(EMA_A[2]/GP5[2])
EMA_A3: RA14.2 U17.D14(EMA_A[3]/GP5[3])
EMA_A4: RA11.1 U17.A14(EMA_A[4]/GP5[4])
EMA_A5: RA11.2 U17.C13(EMA_A[5]/GP5[5])
EMA_A6: RA11.4 U17.E13(EMA_A[6]/GP5[6])
EMA_A7: RA11.3 U17.B13(EMA_A[7]/GP5[7])
EMA_A8: RA5.3 U17.A13(EMA_A[8]/GP5[8])
EMA_A9: RA5.4 U17.D12(EMA_A[9]/GP5[9])
EMA_A10: RA5.1 U17.C12(EMA_A[10]/GP5[10])
EMA_A11: RA5.2 U17.B12(EMA_A[11]/GP5[11])
EMA_A12: RA12.3 U17.D13(EMA_A[12]/GP5[12])
EMA_BA0: RA12.2 U17.C15(EMA_BA[0]/GP2[8])
EMA_BA1: RA12.4 U17.A15(EMA_BA[1]/GP2[9])
EMA_D0: RA2.8 U17.C9(EMA_D[0]/GP4[8])
EMA_D1: RA2.6 U17.A8(EMA_D[1]/GP4[9])
EMA_D2: RA2.7 U17.B8(EMA_D[2]/GP4[10])
EMA_D3: RA2.5 U17.E8(EMA_D[3]/GP4[11])
EMA_D4: RA4.8 U17.B5(EMA_D[4]/GP4[12])
EMA_D5: RA4.7 U17.E7(EMA_D[5]/GP4[13])
EMA_D6: RA4.6 U17.C6(EMA_D[6]/GP4[14])
EMA_D7: RA4.5 U17.D7(EMA_D[7]/GP4[15])
EMA_D8: RA3.8 U17.E10(EMA_D[8]/GP3[0])
EMA_D9: RA3.7 U17.D9(EMA_D[9]/GP3[1])
EMA_D10: RA3.6 U17.A7(EMA_D[10]/GP3[2])
EMA_D11: RA3.5 U17.D6(EMA_D[11]/GP3[3])
EMA_D12: RA1.8 U17.A6(EMA_D[12]/GP3[4])
EMA_D13: RA1.6 U17.B6(EMA_D[13]/GP3[5])
EMA_D14: RA1.7 U17.C7(EMA_D[14]/GP3[6])
EMA_D15: RA1.5 U17.E6(EMA_D[15]/GP3[7])
EMU_TVD: J8.5 R142.1
EMULED1: R89.2 ; also on sheet 39
EMULED2: R90.2 ; also on sheet 39
GP4-0: R91.2 U17.E12(EMA_A[16]/MMCSD0_DAT[5]/GP4[0])
GP4-1: RA13.2 U17.B11(EMA_A[17]/MMCSD0_DAT[4]/GP4[1])
GP4-2: RA13.3 U17.E11(EMA_A[18]/MMCSD0_DAT[3]/GP4[2])
GP4-3: RA13.4 U17.C10(EMA_A[19]/MMCSD0_DAT[2]/GP4[3])
GP4-4: RA13.1 U17.A11(EMA_A[20]/MMCSD0_DAT[1]/GP4[4])
MEM_A4: RA11.8 U9.J3(A4)
MEM_A5: RA11.7 U9.J2(A5)
MEM_A6: RA11.5 U9.H3(A6)
MEM_A7: RA11.6 U9.H2(A7)
MEM_A8: RA5.6 U9.H1(A8)
MEM_A9: RA5.5 U9.G3(A9)
MEM_A10: RA5.8 U9.H9(A10)
MEM_A11: RA5.7 U9.G2(A11)
MEM_A12: RA12.6 TP40.1(TP)
MEM_BA0: RA12.7 U9.G7(BA0)
MEM_BA1: RA12.5 U9.G8(BA1)
MEM_CASn: R88.1 U9.F7(CAS#)
MEM_CKE: R87.1 U9.F3(CKE)
MEM_CLK: R86.1 U9.F2(CLK)
MEM_CS0n: R94.1 R613.1 U9.G9(CS#)
MEM_D2: RA2.2 U9.B8(DQ2)
MEM_D3: RA2.4 U9.C9(DQ3)
MEM_D4: RA4.1 U9.C8(DQ4)
MEM_D5: RA4.2 U9.D9(DQ5)
MEM_D6: RA4.3 U9.D8(DQ6)
MEM_D7: RA4.4 U9.E9(DQ7)
MEM_D8: RA3.1 U9.E1(DQ8)
MEM_D9: RA3.2 U9.D2(DQ9)
MEM_D10: RA3.3 U9.D1(DQ10)
MEM_D11: RA3.4 U9.C2(DQ11)
MEM_D12: RA1.1 U9.C1(DQ12)
MEM_D13: RA1.3 U9.B2(DQ13)
MEM_D14: RA1.2 U9.B1(DQ14)
MEM_D15: RA1.4 U9.A2(DQ15)
MEM_RASn: R92.1 U9.F8(RAS#)
MEM_WE_DQM0n: R619.1 U9.E8(DQML)
MEM_WE_DQM1n: R620.1 U9.F1(DQHM)
OSCIN: C60.1 U17.L19(OSCIN) Y2.3
OSCOUT: C54.1 U17.K19(OSCOUT) Y2.1
OSCVSS: C54.2 C60.2 R635.1 U17.L18(OSCVSS) Y2.2(GND1) Y2.4(GND2)
PLL0_VDDA1V2: C79.2 C416.1 FL13.2 U17.L15(PLL0_VDDA)
PLL0_VSSA: C79.1 C416.2 FL14.2 U17.M17(PLL0_VSSA)
PLL1_VDDA1V2: C94.2 C459.1 FL16.2 U17.N15(PLL1_VDDA)
PLL1_VSSA: C94.1 C459.2 FL15.2 U17.M15(PLL1_VSSA)
RTC_XI: C52.1 U17.J19(RTC_XI) Y1.2
RTC_XO: C53.1 U17.H19(RTC_XO) Y1.1
RTCK/GP8[0]: R141.2 U17.K17(RTCK/GP8[0])
XDS_BOOTMODE[0]: R194.1 R658.2 U17.U3(GP7[0]/BOOT[0])
XDS_BOOTMODE[1]: R172.1 R653.2 U17.T1(GP7[1]/BOOT[1])
XDS_BOOTMODE[2]: R178.1 R654.2 U17.T2(GP7[2]/BOOT[2])
XDS_BOOTMODE[3]: R187.1 R657.2 U17.T3(GP7[3]/BOOT[3])
XDS_BOOTMODE[4]: R152.2 R644.1 U17.R1(GP7[4]/BOOT[4])
XDS_BOOTMODE[5]: R165.2 R649.1 U17.R2(GP7[5]/BOOT[5])
XDS_BOOTMODE[6]: R169.1 R651.2 U17.R3(GP7[6]/BOOT[6])
XDS_BOOTMODE[7]: R143.1 R642.2 U17.P4(GP7[7]/BOOT[7])
XDS_SYS_RESETn: R167.1 ; also on sheet 44
N17108888: R94.2 U17.A18(~{EMA_CS}[0~{]}/GP2[0])
N17108899: R88.2 U17.A9(~{EMA_CAS}/GP2[4])
N17108922: R616.2 U17.B15(~{EMA_OE}/GP3[10])
N17108924: R618.2 U17.B9(~{EMA_WE}/GP3[11])
N17109149: R90.1 U17.E9(MMCSD0_CLK/GP4[7])
N17109151: R89.1 U17.A10(EMA_A[22]/MMCSD0_CMD/GP4[6])
N17109206: R93.2 U17.B16(~{EMA_CS}[5~{]}/GP3[12])
N17109930: R619.2 U17.C8(~{EMA_WEN_DQM}[0~{]}/GP2[3])
N17109932: R620.2 U17.A5(~{EMA_WEN_DQM}[1~{]}/GP2[2])
N17110905: R86.2 U17.B7(EMA_CLK/GP2[7])
N17110913: R87.2 U17.D8(EMA_SDCKE/GP2[6])
N17110918: R92.2 U17.A16(~{EMA_RAS}/GP2[5])
N17113205: R189.2 U17.V2(GP7[12])
N17280894: R119.1 U17.B18(EMA_WAIT[0]/GP3[8])
N17280896: R123.1 U17.B19(EMA_WAIT[1]/GP2[1])
N17286145: TP65.1(TP) U17.T18(CLKOUT/GP6[14])
N17286149: R185.1 TP82.1(TP) U17.T17(RESETOUT/GP6[15])
N17289768: R156.2 R167.2 R650.2 U17.K14(~{RESET})
N17289805: C407.2 R149.1
N17289822: R640.1 U17.J17(RSVDN)
N17296373: TP57.1(TP) U17.T19(RSV2)
N21115682: J8.13 R240.2
N21115817: J8.14 R243.2

Not connected (* = marked no-connect by the designer): J8 6* 17* 18* 19*; RA12 1* 8*; U9 E2(NC)* G1(NC/A12)*; U17 A12(EMA_A[14]/MMCSD0_DAT[7]/GP5[14])* A17(~{EMA_CS}[3~{]}/GP3[14])* B17(~{EMA_CS}[2~{]}/GP3[15])* C11(EMA_A[15]/MMCSD0_DAT[6]/GP5[15])* D10(EMA_A_R~{W}/GP3[9])* D11(EMA_A[13]/GP5[13])* F1(GP8[11])* F2(GP8[10])* F9(~{EMA_CS}[4~{]}/GP3[13])* G1(GP8[15])* G2(GP8[14])* G3(GP8[12])* G4(GP8[8])* H3(GP6[4])* H4(GP8[9])* J1(NC.J1)* J2(NC.J2)* J3(GP6[2])* J4(GP8[13])* K3(GP6[3])* K4(GP6[1])* L1(NC.L1)* L2(NC.L2)* M2(NC.M2)* M3(NC.M3)* M14(NC.M14)* N1(NC.N1)* N2(NC.N2)* N3(NC.N3)* N4(NC.N4)* N16(NC12)* P1(NC.P1)* P2(NC.P2)* P3(NC.P3)* P14(NC9)* P15(NC8)* P17(GP6[5])* P18(NC10)* P19(NC11)* R5(GP6[0])* R6(DDR_VREF)* R10(DDR_DQM[1])* R11(DDR_DQGATE0)* R12(DDR_DQGATE1)* R14(RMII_TXEN)* R15(NC7)* R16(GP6[12])* R17(GP6[13])* R18(NC5)* R19(NC6)* T4(DDR_A[11])* T5(DDR_A[13])* T6(DDR_A[9])* T7(DDR_A[1])* T8(~{DDR_WE})* T9(DDR_BA[1])* T10(DDR_D[10])* T11(DDR_D[9])* T12(DDR_D[11])* T13(DDR_D[8])* T14(DDR_DQS[0])* T15(GP6[8])* T16(NC4)* U4(DDR_A[8])* U5(DDR_A[4])* U6(DDR_A[7])* U7(DDR_A[0])* U8(DDR_BA[2])* U9(~{DDR_CAS})* U10(DDR_D[12])* U11(DDR_D[14])* U12(DDR_ZP)* U13(DDR_D[3])* U14(DDR_D[1])* U15(DDR_D[0])* U16(GP6[9])* U17(GP6[11])* U18(RMII_TXD[1])* U19(NC3)* V1(GP7[11])* V4(DDR_A[12])* V5(DDR_A[5])* V6(DDR_A[3])* V7(DDR_CKE)* V8(DDR_BA[0])* V9(~{DDR_CS})* V10(DDR_D[13])* V11(DDR_DQS[1])* V12(DDR_D[5])* V13(DDR_D[4])* V14(DDR_D[2])* V15(GP6[6])* V16(RMII_TXD[0])* V17(RMII_RXD[0])* V18(NC1)* V19(NC2)* W1(GPI7[8])* W2(GP7[9])* W3(GP7[10])* W4(DDR_A[10])* W5(DDR_A[6])* W6(DDR_A[2])* W7(~{DDR_CLKN})* W8(DDR_CLKP)* W9(~{DDR_RAS})* W10(DDR_D[15])* W11(DDR_D[7])* W12(DDR_D[6])* W13(DDR_DQM[0])* W14(GP6[7])* W15(GP6[10])* W16(RMII_RXD[1])* W17(RMII_RXER)* W18(RMII_MHZ_50_CLK)* W19(RMII_CRS_DV)*

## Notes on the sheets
sheet 40
- XDS200
- SDRAM
sheet 41
- XDS200
- JTAG HEADER FOR AM1802
- BOOTMODE: SPI1-FLASH ^B0001100
- BOOT MODE
sheet 42
- XDS200  DECAPS
- XDS200
- DDR PHY DOES NOT
  REQUIRE POWER IF NOT
  USED, PER DATA SHEET,
  BUT NOT A TYPICAL USE
  CASE.
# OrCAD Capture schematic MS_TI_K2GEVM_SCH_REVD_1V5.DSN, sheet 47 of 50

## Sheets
47 46. BOARD MANAGEMENT CONTROL_3: size C; title: BOARD MANAGEMENT CONTROL_3

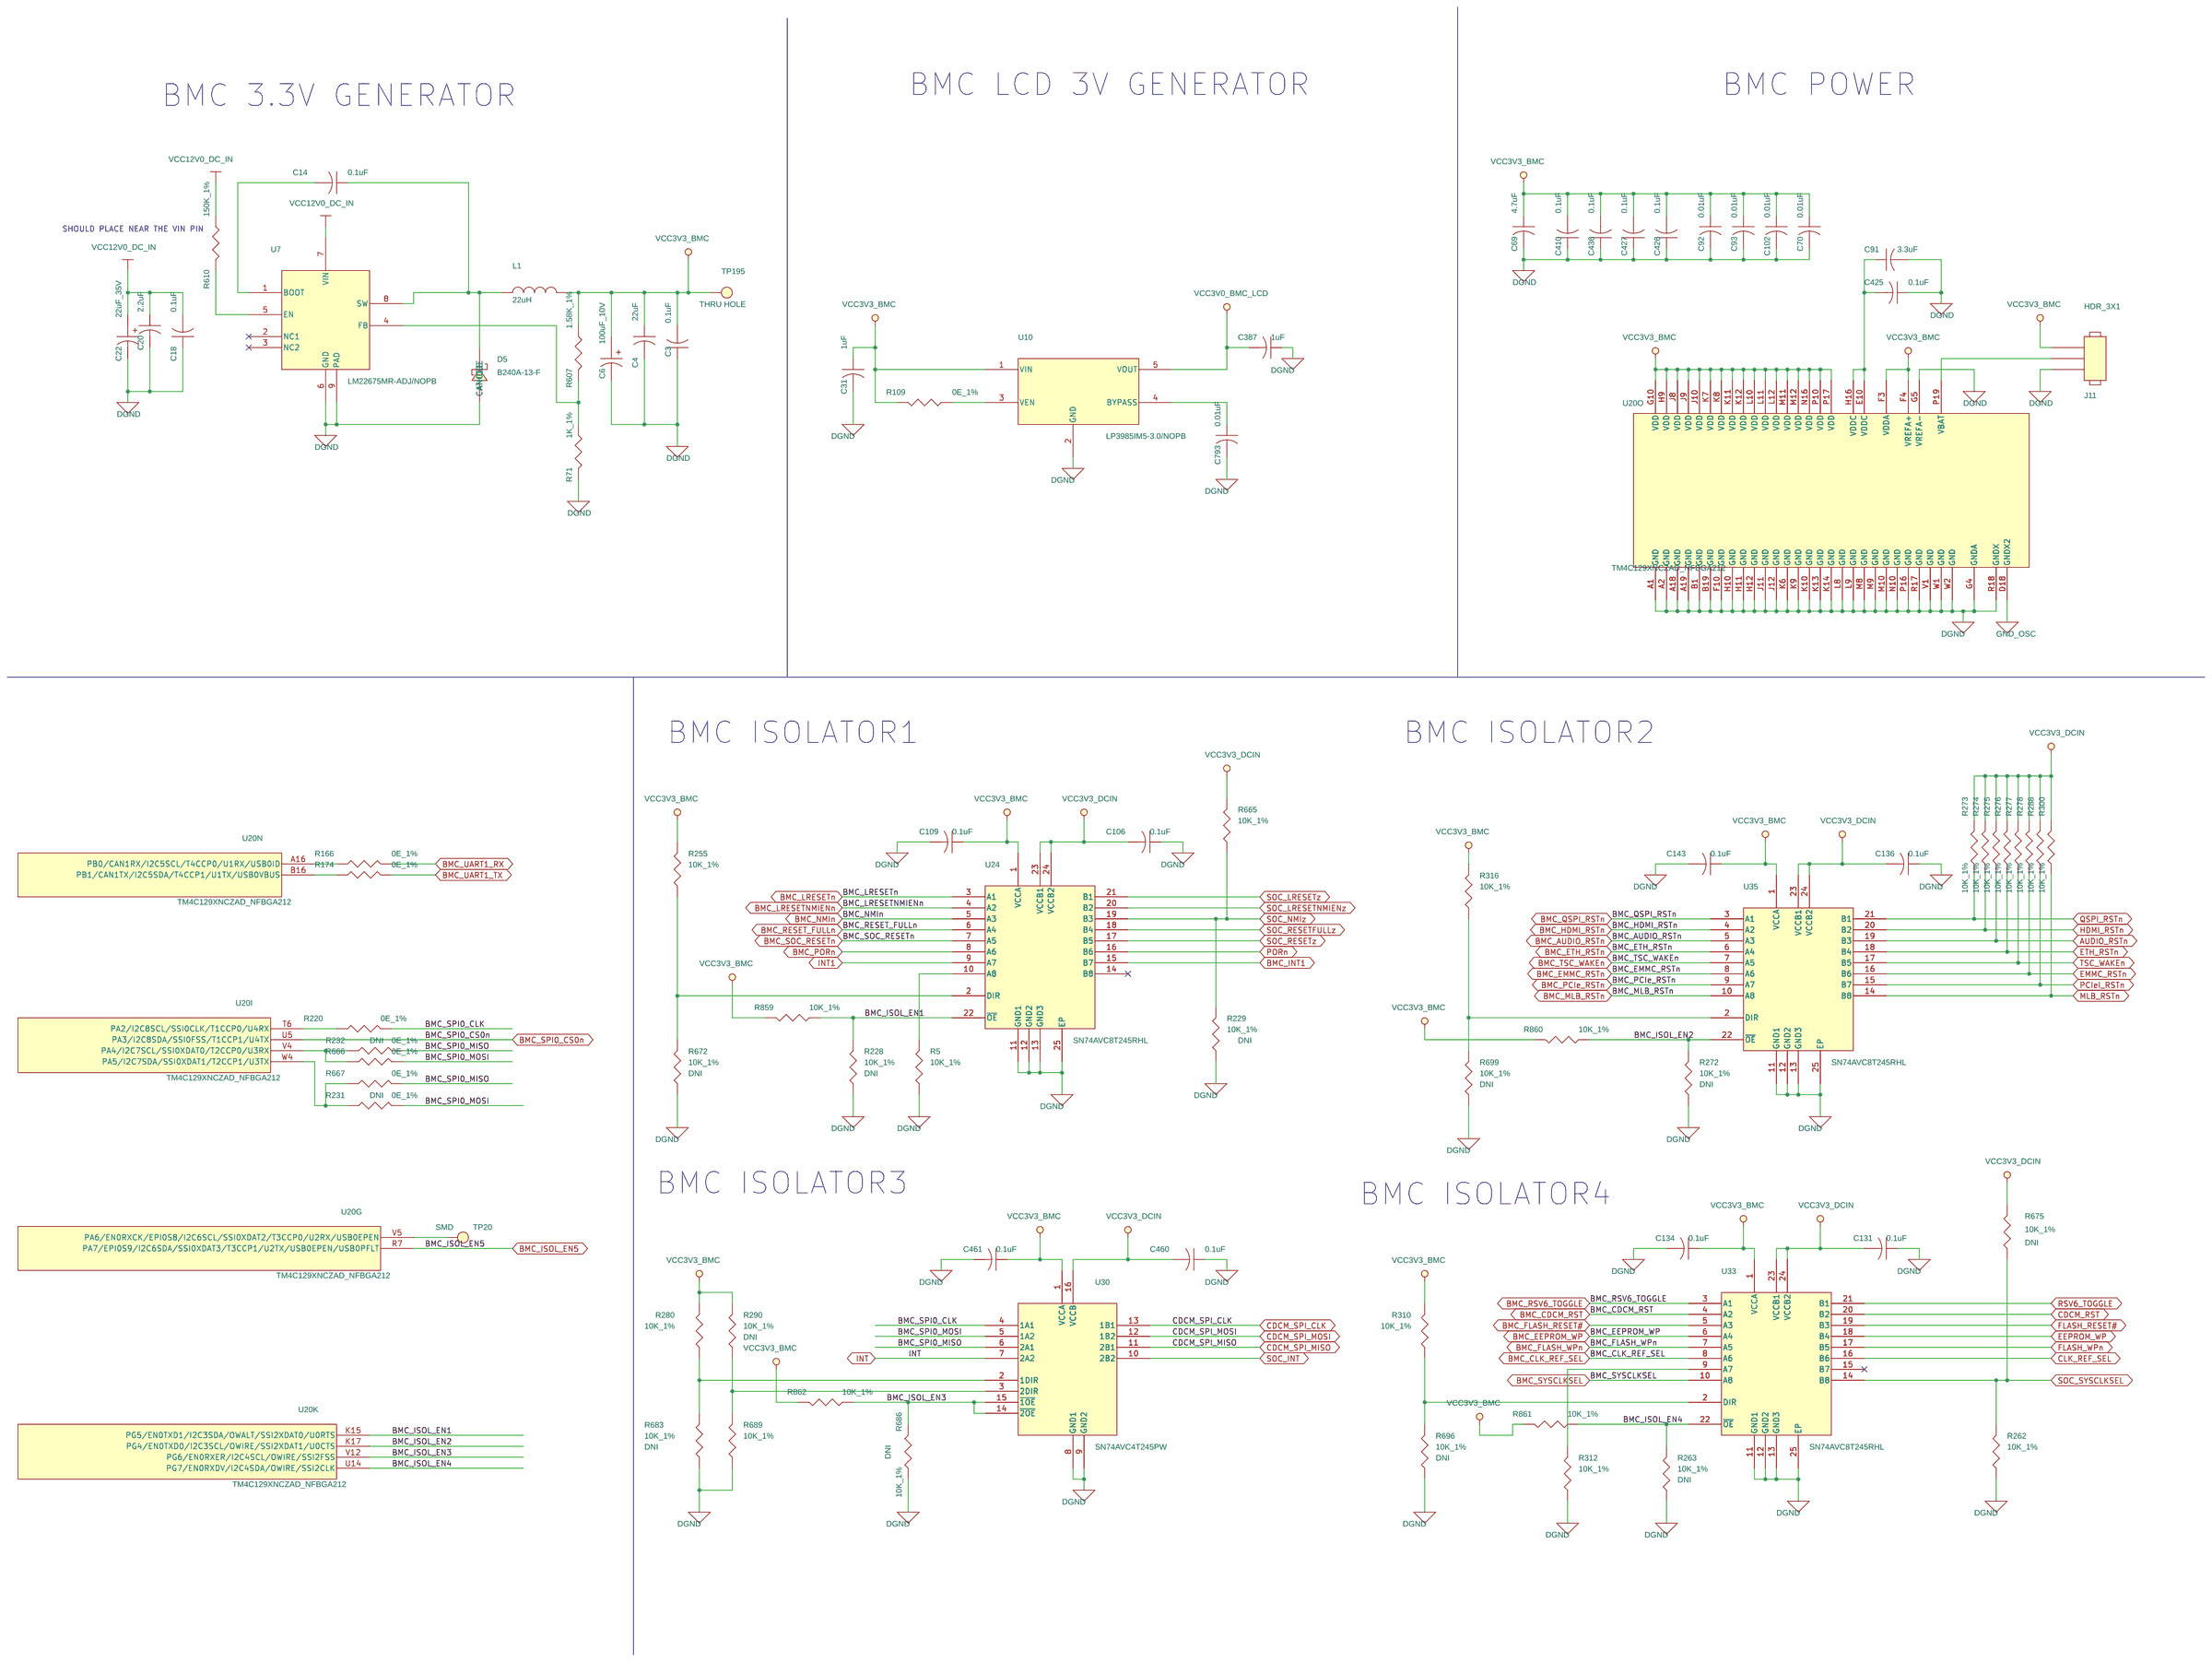
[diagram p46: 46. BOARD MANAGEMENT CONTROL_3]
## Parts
sheet 44. BOARD MANAGEMENT CONTROL_1
U20  TM4C129XNCZADI3  [NFBGA212_19-68_400X400]  (sections A,B,C,D,E,F,G,H,I,J,K,L,M,N,O)
sheet 46. BOARD MANAGEMENT CONTROL_3
C3  0.1uF  [CAP0402]
C4  22uF  [CAP1210]
C6  100uF_10V  [CAPT3528B]
C14  0.1uF  [CAP0402]
C18  0.1uF  [CAP0402]
C20  2.2uF  [CAP1210]
C22  22uF_35V  [CAPT7343E]
C31  1uF  [CAP0402]
C69  4.7uF  [CAP0603]
C70  0.01uF  [CAP0201]
C91  3.3uF  [CAP0603]
C92  0.01uF  [CAP0402]
C93  0.01uF  [CAP0402]
C102  0.01uF  [CAP0201]
C106  0.1uF  [CAP0402]
C109  0.1uF  [CAP0402]
C131  0.1uF  [CAP0402]
C134  0.1uF  [CAP0402]
C136  0.1uF  [CAP0402]
C143  0.1uF  [CAP0402]
C387  1uF  [CAP0402]
C410  0.1uF  [CAP0402]
C425  0.1uF  [CAP0402]
C426  0.1uF  [CAP0402]
C427  0.1uF  [CAP0402]
C436  0.1uF  [CAP0402]
C460  0.1uF  [CAP0402]
C461  0.1uF  [CAP0402]
C793  0.01uF  [CAP0201]
D5  B240A-13-F  [DIO_SMA]
J11  HDR_3X1  [HDR_3X1_100_S_T]
L1  22uH  [IND_DR1040_415X405_SMD]
R5  10K_1%  [RES0402]
R71  1K_1%  [RES0603]
R109  0E_1%  [RES0402]
R166  0E_1%  [RES0402]
R174  0E_1%  [RES0402]
R220  0E_1%  [RES0402]
R228  10K_1%  [RES0402]
R229  10K_1%  [RES0402]
R231  0E_1%  [RES0402]
R232  0E_1%  [RES0402]
R255  10K_1%  [RES0402]
R262  10K_1%  [RES0402]
R263  10K_1%  [RES0402]
R272  10K_1%  [RES0402]
R273  10K_1%  [RES0402]
R274  10K_1%  [RES0402]
R275  10K_1%  [RES0402]
R276  10K_1%  [RES0402]
R277  10K_1%  [RES0402]
R278  10K_1%  [RES0402]
R280  10K_1%  [RES0402]
R288  10K_1%  [RES0402]
R290  10K_1%  [RES0402]
R300  10K_1%  [RES0402]
R310  10K_1%  [RES0402]
R312  10K_1%  [RES0402]
R316  10K_1%  [RES0402]
R607  1.58K_1%  [RES0402]
R610  150K_1%  [RES0402]
R665  10K_1%  [RES0402]
R666  0E_1%  [RES0402]
R667  0E_1%  [RES0402]
R672  10K_1%  [RES0402]
R675  10K_1%  [RES0402]
R683  10K_1%  [RES0402]
R686  10K_1%  [RES0402]
R689  10K_1%  [RES0402]
R696  10K_1%  [RES0402]
R699  10K_1%  [RES0402]
R859  10K_1%  [RES0402]
R860  10K_1%  [RES0402]
R861  10K_1%  [RES0402]
R862  10K_1%  [RES0402]
TP20  SMD  [TP40_SMD]
TP195  THRU HOLE  [TP_40X65]
U7  LM22675MR-ADJ/NOPB  [ESOIC8]
U10  LP3985IM5-3.0/NOPB  [SOT23-5]
U24  SN74AVC8T245RHL  [QFN24_19-68_225X145]
U30  SN74AVC4T245PW  [TSSOP16_25-59_205X180]
U33  SN74AVC8T245RHL  [QFN24_19-68_225X145]
U35  SN74AVC8T245RHL  [QFN24_19-68_225X145]

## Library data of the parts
U20 = TM4C129XNCZAD_NFBGA212: IC TIVA C SERIES MICROCONTROLLER NFBGA212; Chkd/date: NAVEED/060115; Color: Default; Crtd /date: VASANTHA/240914; Custom_Duty: 15%; Customs_HS_Code: 85423100; Distributor_name: DIGIKEY; Distributor_part_number: 296-37958-ND; Height: 1.00MM; Location X-Coordinate: 0; Location Y-Coordinate: 0; Mfr_name: TEXAS INSTRUMENTS; Mistral Part No: 141214090006-R; Package: NFBGA212; Part_type: ICS\DIGITAL\MICROCONTROLLER; Power Pins Visible: False; Primitive: DEFAULT; Project: GALILEO_EVM; RoHS: RoHS; Temperature: -40°C+85°C; Tolerance: NA; Voltage: NA; Wattage: NA; Weight: NA; Datasheet: Y:\MIS_DATABASE\DATASHEETS\ICS\DIGITAL\MICROCONTROLLER\TM4C129XNCZAD.PDF
C3 C106 C109 C131 C134 C136 C143 C410 C425-C427 C436 C460 C461 = CAP: CAP CERAMIC 0.1uF 16V 10% X7R 0402; Alternate_mfr_name_A: KEMET; Alternate_mfr_part_number_A: C0402C104K4RACT; Chkd/date: MAZHAR/281108; Crtd /date: MAZHAR/030907; Custom_Duty: 15%; Customs_HS_Code: 85322990; Distributor_name: DIGIKEY; Distributor_name_A: DIGIKEY; Distributor_part_number: 490-3261-1-ND; Distributor_part_number_A: 399-3521-1-ND; Height: 0.55MM; Mfr_name: MURATA; Mfr_part_number: GRM155R71C104KA88D; Mistral Part No: 120009030060-R; Package: 0402; Part_type: CAPACITORS\CERAMIC; Project: SMART VIEW_IP CAMERA; Tolerance: 10%; Voltage: 16V; Datasheet: Y:\MIS_DATABASE\DATASHEETS\CAPACITORS\GRM188SERIES.PDF
C4 = CAP: CAP CERAMIC 22uF 25V 10% X7R 1210; Chkd/date: BAVISH/040311; Crtd /date: MAZHAR/190111; Custom_Duty: 15%; Customs_HS_Code: 85322990; Distributor_name: DIGIKEY; Distributor_part_number: 490-5313-1-ND; Height: 2.70MM; Mfr_name: MURATA; Mfr_part_number: GRM32ER71E226KE15L; Mistral Part No: 120011010016-R; Package: 1210; Part_type: CAPACITORS\CERAMIC; Project: ITS-PWR_CARD; RoHS: RoHS; Temperature: -55°C+125°C; Tolerance: 10%; Voltage: 25V; Wattage: NA; Weight: NA; Datasheet: Y:\MIS_DATABASE\DATASHEETS\CAPACITORS\GRM32,43,55.PDF
C6 = CAP_POL: CAP TANTALUM 100uF 10V 20% ESR 3E B3528; Chkd/date: NAVEED/241114; Crtd /date: VASANTHA/101114; Custom_Duty: 15%; Customs_HS_Code: 85322990; Distributor_name: DIGIKEY; Distributor_part_number: 399-9722-1-ND; Height: 2.10MM; Mfr_name: KEMET; Mfr_part_number: T491B107M010AT; Mistral Part No: 120014110007-R; Package: B3528; Part_type: CAPACITORS\TANTALUM; Project: GALILEO_EVM; RoHS: RoHS; Temperature: -55°C+125°C; Tolerance: 20%; Voltage: 10V; Weight: NA; Datasheet: Y:\MIS_DATABASE\DATASHEETS\CAPACITORS\KEMETTANTALUMT491.PDF
C14 C18 = CAP: CAP CERAMIC 0.1uF 50V 10% X7R 0402; Alternate_mfr_name_A: TDK CORPORATION; Alternate_mfr_part_number_A: CGA2B3X7R1H104K; Chkd/date: BAVISH/081111; Crtd /date: CHAITHANYA/051011; Custom_Duty: 15%; Customs_HS_Code: 85322990; Distributor_name: DIGIKEY; Distributor_name_A: DIGIKEY; Distributor_part_number: 445-5932-1-ND; Distributor_part_number_A: 445-6899-1-ND; Height: 0.55MM; Mfr_name: TDK CORPORATION; Mfr_part_number: C1005X7R1H104K; Mistral Part No: 120011100014-R; Package: 0402; Part_type: CAPACITORS\CERAMIC; Project: VP-4000-BASE-BOARD; RoHS: RoHS; Temperature: -55°C+125°C; Tolerance: 10%; Voltage: 50V; Wattage: NA; Weight: NA; Datasheet: Y:\MIS_DATABASE\DATASHEETS\CAPACITORS\C1005X7.PDF
C20 = CAP: CAP CERAMIC 2.2uF 25V 10% X7R 1210; Chkd/date: MAZHAR/160709; Crtd /date: MAZHAR/170807; Custom_Duty: 15%; Customs_HS_Code: 85322990; Distributor_name: DIGIKEY; Distributor_part_number: 399-3084-1-ND; Height: 0.98MM; Mfr_name: KEMET; Mfr_part_number: C1210C225K3RACTU; Mistral Part No: 120009030283-R; Package: 1210; Part_type: CAPACITORS\CERAMIC; Project: TELEMETRY ENCODER; RoHS: RoHS; Tolerance: 10%; Voltage: 25V; Datasheet: Y:\MIS_DATABASE\DATASHEETS\CAPACITORS\CSERIES-KEM.PDF
C22 = CAP_POL: CAP TANTALUM 22uF 35V 20% ESR 25mE E7343; Chkd/date: USMAN/161111; Crtd /date: CHAITHANYA/151111; Custom_Duty: 15%; Customs_HS_Code: 85322990; Distributor_name: DIGIKEY; Distributor_part_number: 478-6185-1-ND; Height: 4.30MM; Mfr_name: AVX CORPORATION; Mfr_part_number: TCME226M035R0025; Mistral Part No: 120011110013-R; Package: E7343; Part_type: CAPACITORS\TANTALUM; Project: NA10NG; RoHS: RoHS; Temperature: -55°C+105°C; Tolerance: 20%; Voltage: 35V; Wattage: NA; Weight: NA; Datasheet: Y:\MIS_DATABASE\DATASHEETS\CAPACITORS\AVX-TCM-SERIES.PDF
C31 C387 = CAP: CAP CERAMIC 1uF 10V 10% X5R 0402; Chkd/date: BALACHANDAR/160514; Crtd /date: SARANYA/060514; Custom_Duty: 15%; Customs_HS_Code: 85322990; Distributor_name: DIGIKEY; Distributor_part_number: 478-4596-1-ND; Height: 0.56MM; Mfr_name: AVX CORPORATION; Mfr_part_number: 0402ZD105KAT2A; Mistral Part No: 120014050010-R; Package: 0402; Part_type: CAPACITORS\CERAMIC; Project: AEGIS GP BETA2; RoHS: RoHS; Temperature: -55°C+85°C; Tolerance: 10%; Voltage: 10V; Wattage: NA; Weight: NA; Datasheet: Y:\MIS_DATABASE\DATASHEETS\CAPACITORS\AVX_MLC.PDF
C69 = CAP: CAP CERAMIC 4.7uF 16V 10% X5R 0603; Chkd/date: VASANTHA/230714; Crtd /date: BAVISH/060511; Custom_Duty: 15%; Customs_HS_Code: 85322990; Distributor_name: DIGIKEY; Distributor_part_number: 587-2786-1-ND; Height: 0.90MM; Mfr_name: TAIYO YUDEN; Mfr_part_number: EMK107ABJ475KA-T; Mistral Part No: 120011050004-R; Package: 0603; Part_type: CAPACITORS\CERAMIC; Project: HMC; RoHS: RoHS; Temperature: -55°C+85°C; Tolerance: 10%; Voltage: 16V; Wattage: NA; Weight: NA; Datasheet: Y:\MIS_DATABASE\DATASHEETS\CAPACITORS\EMK107.PDF
C70 C102 C793 = CAP: CAP CERAMIC 0.01uF 10V 10% X5R 0201; Chkd/date: MAZHAR/010211; Crtd /date: BAVISH/131010; Custom_Duty: 15%; Customs_HS_Code: 85322990; Distributor_name: DIGIKEY; Distributor_part_number: 445-1793-1-ND; Height: 0.33MM; Mfr_name: TDK CORPORATION; Mfr_part_number: C0603X5R1A103K; Mistral Part No: 120011010015-R; Package: 0201; Part_type: CAPACITORS\CERAMIC; Project: IDMATEK2; RoHS: RoHS; Temperature: -55°C+85°C; Tolerance: 10%; Voltage: 10V; Wattage: NA; Weight: NA; Datasheet: Y:\MIS_DATABASE\DATASHEETS\CAPACITORS\TDK_CAP.PDF
C91 = CAP: CAP CERAMIC 3.3uF 6.3V 10% X5R 0603; Chkd/date: VINITHA/230112; Crtd /date: BAVISH/200711; Custom_Duty: 15%; Customs_HS_Code: 85322990; Distributor_name: DIGIKEY; Distributor_part_number: 445-5176-1-ND; Height: 0.95MM; Mfr_name: TDK CORPORATION; Mfr_part_number: C1608X5R0J335K; Mistral Part No: 120011070007-R; Package: 0603; Part_type: CAPACITORS\CERAMIC; Project: ITS-SINGAL_COND_CARD; RoHS: RoHS; Temperature: -55°C+85°C; Tolerance: 10%; Voltage: 6.3V; Wattage: NA; Weight: NA; Datasheet: Y:\MIS_DATABASE\DATASHEETS\CAPACITORS\TDK_C-SERIES.PDF
C92 C93 = CAP: CAP CERAMIC 0.01uF 16V 10% X7R 0402; Alternate_mfr_name_A: AVX CORPORATION; Alternate_mfr_name_B: KEMET; Alternate_mfr_name_D: TDK CORPORATION; Alternate_mfr_part_number_A: 0402YC103KAT2A; Alternate_mfr_part_number_B: C0402C103K4RACTU; Alternate_mfr_part_number_D: C1005X7R1C103K; Chkd/date: SHREESHAIL/180506; Crtd /date: MAZHAR/110506; Custom_Duty: 15%; Customs_HS_Code: 85322990; Distributor_name: DIGIKEY; Distributor_name_A: DIGIKEY; Distributor_name_B: DIGIKEY; Distributor_name_D: DIGIKEY; Distributor_part_number: PCC103BQCT-ND; Distributor_part_number_A: 478-1114-1-ND; Distributor_part_number_B: 399-1038-1-ND; Distributor_part_number_D: 445-1262-1-ND; Height: 0.55MM; Mfr_name: PANASONIC-ECG; Mfr_part_number: ECJ-0EB1C103K; Mistral Part No: 120009030032-R; Package: 0402; Part_type: CAPACITORS\CERAMIC; Project: VOCERA; RoHS: RoHS; Tolerance: 10%; Voltage: 16V; Datasheet: Y:\MIS_DATABASE\DATASHEETS\CAPACITORS\PAN-ECJ.PDF
D5 = DIODE_SCHOTTKY: DIODE SCHOTTKY RECTIFIER 40V 2A SMA; Chkd/date: MAZHAR/100311; Crtd /date: BAVISH/200111; Custom_Duty: 15%; Customs_HS_Code: 85412900; Distributor_name: DIGIKEY; Distributor_part_number: B240A-FDICT-ND; Height: 2.30MM; Mfr_name: DIODES INC; Mistral Part No: 130011010038-R; Package: SMA; Part_type: DIODE\SCHOTTKY; Project: ALLYCAT; Temperature: -65°C+150°C; Tolerance: NA; Voltage: 40V; Wattage: NA; Weight: 0.064g; Datasheet: Y:\MIS_DATABASE\DATASHEETS\DISCRETES\DIODES\B240A-13-F.PDF
J11 = HEADER_3X1: CON HDR 3X1 2.54MM PITCH ST TH; Chkd/date: MAZHAR/100311; Crtd /date: BAVISH/160211; Custom_Duty: 24%; Customs_HS_Code: 85369090; Distributor_name: DIGIKEY; Distributor_part_number: A26545-ND; Height: 10.74MM; Mfr_name: TYCO ELECTRONICS; Mfr_part_number: 87224-3; Mistral Part No: 150011020004-R; Package: THRU-HOLE; Part_type: CONNECTOR\HEADERS; Project: OMAPL1_PEC20; RoHS: RoHS; Temperature: NA; Tolerance: NA; Voltage: NA; Wattage: NA; Weight: NA; Datasheet: Y:\MIS_DATABASE\DATASHEETS\CONNECTORS\87224.PDF
L1 = INDUCTOR: IND POWER 22uH 2.5A 30% SMD; Chkd/date: RAVI/290910; Crtd /date: MAZHAR/031007; Custom_Duty: 24%; Customs_HS_Code: 85437099; Distributor_name: DIGIKEY; Distributor_part_number: 513-1401-1-ND; Height: 4.00MM; Mfr_name: COIL TRONICS; Mfr_part_number: DR1040-220-R; Mistral Part No: 130009030559-R; Package: SMD; Project: TELEMETRY ENCODER; RoHS: RoHS; Temperature: -40°C+125°C; Tolerance: 30%; Datasheet: Y:\MIS_DATABASE\DATASHEETS\DISCRETES\INDUCTORS\DR1040.PDF
R5 R255 R262 R273-R278 R280 R288 R300 R310 R312 R316 R665 R689 R859-R862 = RESISTOR: RES 10K 1/16W 1% 0402; Alternate_mfr_name_A: AVX CORPORATION; Alternate_mfr_name_B: PANASONIC-ECG-ECG; Alternate_mfr_name_C: YAGEO AMERICA; Alternate_mfr_name_D: VISHAY; Alternate_mfr_part_number_A: CR05-103F-H; Alternate_mfr_part_number_B: ERJ-2RKF1002X; Alternate_mfr_part_number_C: 9C04021A1002FLHF3; Alternate_mfr_part_number_D: CRCW040210K0FKED; Chkd/date: SHREESHAIL/310506; Crtd /date: GEETHA/290506; Custom_Duty: 15%; Customs_HS_Code: 85332119; Distributor_name: DIGIKEY; Distributor_name_A: NA; Distributor_name_B: DIGIKEY; Distributor_name_C: DIGIKEY; Distributor_name_D: DIGIKEY; Distributor_part_number: 311-10.0KLRTR-ND; Distributor_part_number_A: NA; Distributor_part_number_B: P10.0KLCT-ND; Distributor_part_number_C: 311-10.0KLCT-ND; Distributor_part_number_D: 541-10.0KLCT-ND; Height: 0.40MM; Mfr_name: YAGEO AMERICA; Mfr_part_number: RC0402FR-0710KL; Mistral Part No: 110009030220-P; Package: 0402; Part_type: RESISTORS\FIXED; Project: VOCERA; RoHS: Pb-Free; Tolerance: 1%; Wattage: 1/16W; Datasheet: Y:\MIS_DATABASE\DATASHEETS\RESISTORS\YAGEO-RC0402.PDF
R71 = RESISTOR: RES 1K 1/10W 1% 0603; Alternate_mfr_name_A: AVX CORPORATION; Alternate_mfr_name_C: YAEGO CORPORATION; Alternate_mfr_part_number_A: CR10-102F-H; Alternate_mfr_part_number_C: RC0603FR-071KL; Chkd/date: SHREESHAIL/071205; Crtd /date: MAZHAR/210405; Custom_Duty: 15%; Customs_HS_Code: 85332119; Distributor_name: DIGIKEY; Distributor_name_A: NA; Distributor_name_C: DIGIKEY; Distributor_part_number: P1.00KHCT-ND; Distributor_part_number_A: NA; Distributor_part_number_C: 311-1.00KHRCT-ND; Height: 0.55MM; Mfr_name: PANASONIC-ECG; Mfr_part_number: ERJ-3EKF1001V; Mistral Part No: 110009030410-R; Package: 0603; Part_type: RESISTORS\FIXED; Project: FPI; RoHS: RoHS; Tolerance: 1%; Wattage: 1/10W; Datasheet: Y:\MIS_DATABASE\DATASHEETS\RESISTORS\PAN-ERJ.PDF
R109 R166 R174 R220 R666 R667 = RESISTOR: RES 0E 1/16W 1% 0402; Chkd/date: MAZHAR/220709; Crtd /date: USMAN/270109; Custom_Duty: 15%; Customs_HS_Code: 85332119; Distributor_name: NA; Distributor_part_number: NA; Height: 0.40MM; Mfr_name: YAGEO AMERICA; Mfr_part_number: RC0402FR-070RL; Mistral Part No: 110009030085-P; Package: 0402; Part_type: RESISTORS\FIXED; Project: OMAP_EVM; RoHS: Pb-Free; Tolerance: 1%; Wattage: 1/16W; Datasheet: Y:\MIS_DATABASE\DATASHEETS\RESISTORS\CRCW0603.PDF
R228 R229 R263 R272 R290 R672 R675 R683 R686 R696 R699 = RESISTOR: RES 10K 1/16W 1% 0402; Alternate_mfr_name_A: AVX CORPORATION; Alternate_mfr_name_B: PANASONIC-ECG-ECG; Alternate_mfr_name_C: YAGEO AMERICA; Alternate_mfr_name_D: VISHAY; Alternate_mfr_part_number_A: CR05-103F-H; Alternate_mfr_part_number_B: ERJ-2RKF1002X; Alternate_mfr_part_number_C: 9C04021A1002FLHF3; Alternate_mfr_part_number_D: CRCW040210K0FKED; Chkd/date: SHREESHAIL/310506; Crtd /date: GEETHA/290506; Custom_Duty: 15%; Customs_HS_Code: 85332119; Distributor_name: DIGIKEY; Distributor_name_A: NA; Distributor_name_B: DIGIKEY; Distributor_name_C: DIGIKEY; Distributor_name_D: DIGIKEY; Distributor_part_number: 311-10.0KLRTR-ND; Distributor_part_number_A: NA; Distributor_part_number_B: P10.0KLCT-ND; Distributor_part_number_C: 311-10.0KLCT-ND; Distributor_part_number_D: 541-10.0KLCT-ND; Height: 0.40MM; Loading: DNI; Mfr_name: YAGEO AMERICA; Mfr_part_number: RC0402FR-0710KL; Mistral Part No: 110009030220-P; Package: 0402; Part_type: RESISTORS\FIXED; Project: VOCERA; RoHS: Pb-Free; Tolerance: 1%; Wattage: 1/16W; Datasheet: Y:\MIS_DATABASE\DATASHEETS\RESISTORS\YAGEO-RC0402.PDF
R231 R232 = RESISTOR: RES 0E 1/16W 1% 0402; Chkd/date: MAZHAR/220709; Crtd /date: USMAN/270109; Custom_Duty: 15%; Customs_HS_Code: 85332119; Distributor_name: NA; Distributor_part_number: NA; Height: 0.40MM; Loading: DNI; Mfr_name: YAGEO AMERICA; Mfr_part_number: RC0402FR-070RL; Mistral Part No: 110009030085-P; Package: 0402; Part_type: RESISTORS\FIXED; Project: OMAP_EVM; RoHS: Pb-Free; Tolerance: 1%; Wattage: 1/16W; Datasheet: Y:\MIS_DATABASE\DATASHEETS\RESISTORS\CRCW0603.PDF
R607 = RESISTOR: RES 1.58K 1/16W 1% 0402; Chkd/date: MAZHAR/160609; Crtd /date: USMAN/090609; Custom_Duty: 15%; Customs_HS_Code: 85332119; Distributor_name: DIGIKEY; Distributor_part_number: P1.58KLCT-ND; Height: 0.40MM; Mfr_name: PANASONIC-ECG; Mfr_part_number: ERJ-2RKF1581X; Mistral Part No: 110009031208-R; Package: 0402; Part_type: RESISTORS\FIXED; Project: BBB; RoHS: RoHS; Tolerance: 1%; Wattage: 1/16W; Datasheet: Y:\MIS_DATABASE\DATASHEETS\RESISTORS\PAN-ERJSERIES.PDF
R610 = RESISTOR: RES 150K 1/16W 1% 0402; Alternate_mfr_name_A: YAGEO AMERICA; Alternate_mfr_name_D: ROHM; Alternate_mfr_part_number_A: RC0402FR-07150KL; Alternate_mfr_part_number_D: MCR01MZPF1503; Chkd/date: SHREESHAIL/200906; Crtd /date: MAZHAR/190906; Custom_Duty: 15%; Customs_HS_Code: 85332119; Distributor_name: DIGIKEY; Distributor_name_A: DIGIKEY; Distributor_name_D: DIGIKEY; Distributor_part_number: P150KLCT-ND; Distributor_part_number_A: 311-150KLRCT-ND; Distributor_part_number_D: RHM150KLCT-ND; Height: 0.40MM; Mfr_name: PANASONIC-ECG; Mfr_part_number: ERJ-2RKF1503X; Mistral Part No: 110009030336-R; Package: 0402; Part_type: RESISTORS\FIXED; Project: SM2_AFE; RoHS: RoHS; Tolerance: 1%; Wattage: 1/16W; Datasheet: Y:\MIS_DATABASE\DATASHEETS\RESISTORS\PAN_ERJ.PDF
TP20 = TESTPOINT: TESTPOINT 40 SMD; Chkd/date: MAZHAR/190505; Crtd /date: MAZHAR/190505; Distributor_name: NA; Distributor_part_number: NA; Height: NA; Mfr_name: LOCAL; Mistral Part No: 130009030933; Part_type: MISC\TESTPOINT; Project: RAINIER-3
TP195 = TESTPOINT: TESTPOINT 1.0MM DRILL PTH; Chkd/date: MAZHAR/271211; Crtd /date: SHREESHAIL/041005; Distributor_name: NA; Distributor_part_number: NA; Height: NA; Mfr_name: LOCAL; Mistral Part No: 130009030938; Package: THRU-HOLE; Part_type: MISC\TESTPOINT; Project: HSE; Datasheet: NA
U7 = LM22675MRE_SOIC8: IC 1A BUCK VOLTAGE REGULATOR SOIC-8; Chkd/date: NAVEED/060115; Crtd /date: JEBRAN/031114; Custom_Duty: 15%; Customs_HS_Code: 85423100; Distributor_name: DIGIKEY; Height: 1.68MM; Mfr_name: TEXAS INSTRUMENTS; Mistral Part No: 142014110002-R; Package: SOIC8; Part_type: ICS\POWER\VOLTAGE REGULATOR; Project: GALILEO EVM; RoHS: RoHS; Temperature: -40°C+125°C; Tolerance: NA; Voltage: NA; Wattage: NA; Datasheet: Y:\MIS_DATABASE\DATASHEETS\MISC\REGULATORS\LM22675MRE.PDF
U10 = LP3985IM5-2.5_SOT23-5: IC MICROPOWER LOW NOISE LDO CMOS VOLTAGE REGULATORS 3V SOT23-5; Chkd/date: NAVEED/050215; Crtd /date: JEBRAN/050215; Custom_Duty: 15%; Customs_HS_Code: 85423100; Distributor_name: DIGIKEY; Distributor_part_number: LP3985IM5-3.0/NOPBCT-ND; Height: 1.45MM; Mfr_name: TEXAS INSTRUMENTS; Mistral Part No: 142015020003-R; Part_type: ICS\POWER\VOLTAGE REGULATOR; Project: GALILEO_EVM; RoHS: RoHS; Temperature: -40°C+125°C; Tolerance: NA; Voltage: 3V; Wattage: NA; Weight: NA; Datasheet: Y:\MIS_DATABASE\DATASHEETS\MISC\REGULATORS\LP3985IM5.PDF
U24 U33 U35 = SN74AVC8T245RHL_QFN24: IC BUS TRANSCEIVER 8-BIT DUAL-SUPPLY QFN24; Chkd/date: RAGESH/050511; Crtd /date: BAVISH/290411; Custom_Duty: 15%; Customs_HS_Code: 85423100; Distributor_name: DIGIKEY; Distributor_part_number: 296-17859-1-ND; Height: 1.20MM; Mfr_name: TEXAS INSTRUMENTS; Mfr_part_number: SN74AVC8T245RHLR; Mistral Part No: 143011040001-R; Package: QFN24; Part_type: ICS\TELECOM\TRANSCEIVER; Project: OMAPL1_PEC20; RoHS: RoHS; Temperature: -40°C+85°C; Tolerance: NA; Voltage: NA; Wattage: NA; Weight: NA; Datasheet: Y:\MIS_DATABASE\DATASHEETS\ICS\DIGITAL\BUSTRANSCEIVER\SN74AVC8T245.PDF
U30 = SN74AVC4T245PW_TSSOP16: IC 4-BIT DUAL SUPPLY BUS TRANSCEIVER TSSOP16; Chkd/date: SHREESHAIL/030506; Crtd /date: MAZHAR/270406; Custom_Duty: 15%; Customs_HS_Code: 85423100; Distributor_name: MOUSER; Distributor_part_number: 595-SN74AVC4T245PW; Height: 1.20MM; Mfr_name: TEXAS INSTRUMENTS; Mistral Part No: 141009030111-R; Package: TSSOP16; Part_type: ICS\DIGITAL\COMBINATIONAL; Project: VOCERA; RoHS: Sb/ Br FREE; Datasheet: Y:\MIS_DATABASE\DATASHEETS\ICS\DIGITAL\BUSTRANSCEIVER\SN74AVC4T245.PDF

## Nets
DGND: C3.1 C4.2 C6.2 C18.1 C20.2 C22.2 C31.2 C69.2 C70.2 C91.2 C92.2 C93.2 C102.2 C106.1 C109.2 C131.1 C134.2 C136.1 C143.2 C387.1 C410.1 C425.1 C426.1 C427.1 C436.1 C460.1 C461.2 C793.2 D5.2(ANODE) J11.3 R5.1 R71.2 R228.1 R229.1 R262.1 R263.1 R272.1 R312.1 R672.1 R683.1 R686.1 R689.1 R696.1 R699.1 U7.6(GND) U7.9(PAD) U10.2(GND) U20.A1(GND) U20.A2(GND) U20.A18(GND) U20.A19(GND) U20.B1(GND) U20.B19(GND) U20.F10(GND) U20.G4(GNDA) U20.G5(VREFA-) U20.H10(GND) U20.H11(GND) U20.H12(GND) U20.J11(GND) U20.J12(GND) U20.K6(GND) U20.K9(GND) U20.K10(GND) U20.K13(GND) U20.K14(GND) U20.L8(GND) U20.L9(GND) U20.M8(GND) U20.M9(GND) U20.M10(GND) U20.N10(GND) U20.P16(GND) U20.R17(GND) U20.R18(GNDX) U20.V1(GND) U20.W1(GND) U20.W2(GND) U24.11(GND1) U24.12(GND2) U24.13(GND3) U24.25(EP) U30.8(GND1) U30.9(GND2) U33.11(GND1) U33.12(GND2) U33.13(GND3) U33.25(EP) U35.11(GND1) U35.12(GND2) U35.13(GND3) U35.25(EP) ; also on sheet 1 11 12 13 14 15 16 17 18 19 20 21 22 23 24 25 26 27 28 29 30 31 32 33 34 35 36 37 38 39 40 41 42 43 44 45 46 48 49 50
GND_OSC: U20.D18(GNDX2) ; also on sheet 46
VCC3V0_BMC_LCD: C387.2 U10.5(VOUT) ; also on sheet 45
VCC3V3_BMC: C3.2 C4.1 C6.1 C31.1 C69.1 C70.1 C92.1 C93.1 C102.1 C109.1 C134.1 C143.1 C410.2 C426.2 C427.2 C436.2 C461.1 J11.1 L1.2 R109.2 R255.2 R280.2 R290.2 R310.2 R316.2 R607.1 R859.2 R860.2 R861.2 R862.2 TP195.1(TP) U10.1(VIN) U20.F3(VDDA) U20.F4(VREFA+) U20.G10(VDD) U20.H9(VDD) U20.J8(VDD) U20.J9(VDD) U20.J10(VDD) U20.K7(VDD) U20.K8(VDD) U20.K11(VDD) U20.K12(VDD) U20.L10(VDD) U20.L11(VDD) U20.L12(VDD) U20.M11(VDD) U20.M12(VDD) U20.N16(VDD) U20.P10(VDD) U20.P17(VDD) U24.1(VCCA) U30.1(VCCA) U33.1(VCCA) U35.1(VCCA) ; also on sheet 13 28 29 37 38 45 46 50
VCC3V3_DCIN: C106.2 C131.2 C136.2 C460.2 R273.2 R274.2 R275.2 R276.2 R277.2 R278.2 R288.2 R300.2 R665.2 R675.2 U24.23(VCCB1) U24.24(VCCB2) U30.16(VCCB) U33.23(VCCB1) U33.24(VCCB2) U35.23(VCCB1) U35.24(VCCB2) ; also on sheet 11 17 18 19 20 21 22 23 24 25 26 27 28 29 30 31 32 33 34 35 36 37 38 43 44 45 46 48 50
VCC12V0_DC_IN: C18.2 C20.1 C22.1 R610.1 U7.7(VIN) ; also on sheet 1 26 31 33 34 48 50
AUDIO_RSTn: R275.1 U35.19(B3) ; also on sheet 23
BMC_AUDIO_RSTn: U35.5(A3) ; also on sheet 45
BMC_CDCM_RST: U33.4(A2) ; also on sheet 45
BMC_CLK_REF_SEL: U33.8(A6) ; also on sheet 45
BMC_EEPROM_WP: U33.6(A4) ; also on sheet 45
BMC_EMMC_RSTn: U35.8(A6) ; also on sheet 45
BMC_ETH_RSTn: U35.6(A4) ; also on sheet 45
BMC_FLASH_RESET#: U33.5(A3) ; also on sheet 45
BMC_FLASH_WPn: U33.7(A5) ; also on sheet 45
BMC_HDMI_RSTn: U35.4(A2) ; also on sheet 45
BMC_INT1: U24.15(B7) ; also on sheet 12
BMC_ISOL_EN1: R228.2 R859.1 U20.K15(PG5/EN0TXD1/I2C3SDA/OWALT/SSI2XDAT0/U0RTS) U24.22(~{OE})
BMC_ISOL_EN2: R272.2 R860.1 U20.K17(PG4/EN0TXD0/I2C3SCL/OWIRE/SSI2XDAT1/U0CTS) U35.22(~{OE})
BMC_ISOL_EN3: R686.2 R862.1 U20.V12(PG6/EN0RXER/I2C4SCL/OWIRE/SSI2FSS) U30.14(~{2OE}) U30.15(~{1OE})
BMC_ISOL_EN4: R263.2 R861.1 U20.U14(PG7/EN0RXDV/I2C4SDA/OWIRE/SSI2CLK) U33.22(~{OE})
BMC_ISOL_EN5: U20.R7(PA7/EPI0S9/I2C6SDA/SSI0XDAT3/T3CCP1/U2TX/USB0EPEN/USB0PFLT) ; also on sheet 37
BMC_LRESETn: U24.3(A1) ; also on sheet 46
BMC_LRESETNMIENn: U24.4(A2) ; also on sheet 46
BMC_MLB_RSTn: U35.10(A8) ; also on sheet 45
BMC_NMIn: U24.5(A3) ; also on sheet 46
BMC_PCIe_RSTn: U35.9(A7) ; also on sheet 45
BMC_PORn: U24.8(A6) ; also on sheet 46
BMC_QSPI_RSTn: U35.3(A1) ; also on sheet 45
BMC_RESET_FULLn: U24.6(A4) ; also on sheet 46
BMC_RSV6_TOGGLE: U33.3(A1) ; also on sheet 45
BMC_SOC_RESETn: U24.7(A5) ; also on sheet 46
BMC_SPI0_CLK: R220.2 U30.4(1A1)
BMC_SPI0_CS0n: U20.U5(PA3/I2C8SDA/SSI0FSS/T1CCP1/U4TX) ; also on sheet 37
BMC_SPI0_MISO: R232.2 R667.2 U30.6(2A1)
BMC_SPI0_MOSI: R231.2 R666.2 U30.5(1A2)
BMC_SYSCLKSEL: U33.10(A8) ; also on sheet 45
BMC_TSC_WAKEn: U35.7(A5) ; also on sheet 45
BMC_UART1_RX: R166.2 ; also on sheet 29
BMC_UART1_TX: R174.2 ; also on sheet 29
CDCM_RST: U33.20(B2) ; also on sheet 36
CDCM_SPI_CLK: U30.13(1B1) ; also on sheet 36
CDCM_SPI_MISO: U30.11(2B1) ; also on sheet 36
CDCM_SPI_MOSI: U30.12(1B2) ; also on sheet 36
CLK_REF_SEL: U33.16(B6) ; also on sheet 36
EEPROM_WP: U33.18(B4) ; also on sheet 17
EMMC_RSTn: R278.1 U35.16(B6) ; also on sheet 18
ETH_RSTn: R276.1 U35.18(B4) ; also on sheet 25
FLASH_RESET#: U33.19(B3) ; also on sheet 17
FLASH_WPn: U33.17(B5) ; also on sheet 17
HDMI_RSTn: R274.1 U35.20(B2) ; also on sheet 22
INT: U30.7(2A2) ; also on sheet 45
INT1: U24.9(A7) ; also on sheet 45
MLB_RSTn: R300.1 U35.14(B8) ; also on sheet 31
PCIeI_RSTn: R288.1 U35.15(B7) ; also on sheet 26
PORn: U24.16(B6) ; also on sheet 11
QSPI_RSTn: R273.1 U35.21(B1) ; also on sheet 17
RSV6_TOGGLE: U33.21(B1) ; also on sheet 12
SOC_INT: U30.10(2B2) ; also on sheet 12
SOC_LRESETNMIENz: U24.20(B2) ; also on sheet 11
SOC_LRESETz: U24.21(B1) ; also on sheet 11
SOC_NMIz: R229.2 R665.1 U24.19(B3) ; also on sheet 11
SOC_RESETFULLz: U24.18(B4) ; also on sheet 11
SOC_RESETz: U24.17(B5) ; also on sheet 11
SOC_SYSCLKSEL: R262.2 R675.1 U33.14(B8) ; also on sheet 11
TSC_WAKEn: R277.1 U35.17(B5) ; also on sheet 21
N14152075: J11.2 U20.P19(VBAT)
N14152267: C91.1 C425.2 U20.E10(VDDC) U20.H16(VDDC)
N17177920: R231.1 R667.1 U20.W4(PA5/I2C7SDA/SSI0XDAT1/T2CCP1/U3TX)
N17734901: C14.1 D5.1(CATHODE) L1.1 U7.8(SW)
N18031024: R109.1 U10.3(VEN)
N18144573: R316.1 R699.2 U35.2(DIR)
N18147498: R310.1 R696.2 U33.2(DIR)
N18151943: R255.1 R672.2 U24.2(DIR)
N18158148: R280.1 R683.2 U30.2(1DIR)
N18158579: R290.1 R689.2 U30.3(2DIR)
N18163620: R232.1 R666.1 U20.V4(PA4/I2C7SCL/SSI0XDAT0/T2CCP0/U3RX)
N19776412: R220.1 U20.T6(PA2/I2C8SCL/SSI0CLK/T1CCP0/U4RX)
N19921815: R71.1 R607.2 U7.4(FB)
N20334677: R166.1 U20.A16(PB0/CAN1RX/I2C5SCL/T4CCP0/U1RX/USB0ID)
N20334698: R174.1 U20.B16(PB1/CAN1TX/I2C5SDA/T4CCP1/U1TX/USB0VBUS)
N20476232: R312.2 U33.9(A7)
N20518193: R610.2 U7.5(EN)
N20519274: C14.2 U7.1(BOOT)
N21169756: TP20.1(TP) U20.V5(PA6/EN0RXCK/EPI0S8/I2C6SCL/SSI0XDAT2/T3CCP0/U2RX/USB0EPEN)
N21500371: R5.2 U24.10(A8)
N25011059: C793.1 U10.4(BYPASS)

Not connected (* = marked no-connect by the designer): U7 2(NC1)* 3(NC2)*; U24 14(B8)*; U33 15(B7)*

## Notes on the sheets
sheet 47
- BMC LCD 3V GENERATOR
- BMC POWER
- BMC 3.3V GENERATOR
- SHOULD PLACE NEAR THE VIN PIN
- BMC ISOLATOR1
- BMC ISOLATOR2
- BMC ISOLATOR3
- BMC ISOLATOR4
